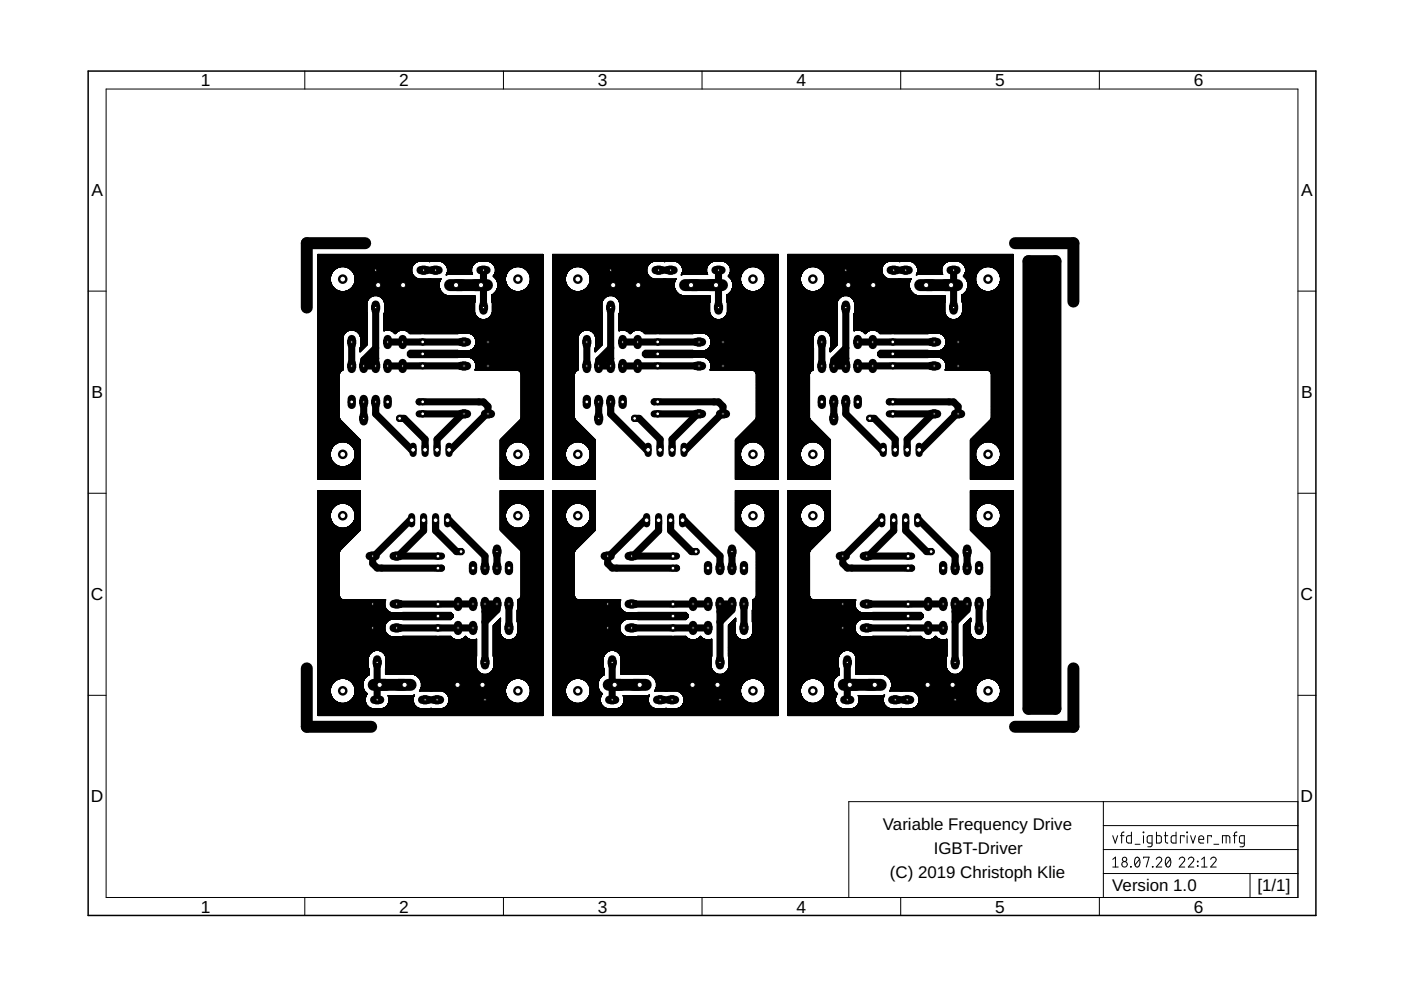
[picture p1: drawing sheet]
<svg xmlns="http://www.w3.org/2000/svg" width="297mm" height="210mm" viewBox="0 0 297 210" stroke-linecap="round" stroke-linejoin="round" font-family="sans-serif">
<defs><g id="words">
<g font-size="3.7">
<text x="42.5" y="18.3">1</text>
<text x="84.7" y="18.3">2</text>
<text x="126.8" y="18.3">3</text>
<text x="168.9" y="18.3">4</text>
<text x="211" y="18.3">5</text>
<text x="253.1" y="18.3">6</text>
<text x="19.4" y="41.6">A</text>
<text x="275.9" y="41.6">A</text>
<text x="19.4" y="84.4">B</text>
<text x="275.9" y="84.4">B</text>
<text x="19.3" y="127.3">C</text>
<text x="275.8" y="127.3">C</text>
<text x="19.3" y="170.1">D</text>
<text x="275.8" y="170.1">D</text>
<text x="42.5" y="193.5">1</text>
<text x="84.7" y="193.5">2</text>
<text x="126.8" y="193.5">3</text>
<text x="168.9" y="193.5">4</text>
<text x="211" y="193.5">5</text>
<text x="253.1" y="193.5">6</text>
</g>
<g font-size="3.6">
<text x="187.2" y="176">Variable Frequency Drive</text>
<text x="198" y="181.1">IGBT-Driver</text>
<text x="188.7" y="186.2">(C) 2019 Christoph Klie</text>
<text x="235.8" y="189">Version 1.0</text>
<text x="266.6" y="189">[1/1]</text>
</g>
</g></defs>
<g fill="none" stroke="#000" stroke-width=".51">
<circle cx="72.7" cy="59.2" r=".76"/>
<circle cx="109.8" cy="59.2" r=".76"/>
<circle cx="122.5" cy="59.2" r=".76"/>
<circle cx="159.6" cy="59.2" r=".76"/>
<circle cx="172.3" cy="59.2" r=".76"/>
<circle cx="209.5" cy="59.2" r=".76"/>
<circle cx="72.7" cy="96.3" r=".76"/>
<circle cx="109.8" cy="96.3" r=".76"/>
<circle cx="122.5" cy="96.3" r=".76"/>
<circle cx="159.6" cy="96.3" r=".76"/>
<circle cx="172.3" cy="96.3" r=".76"/>
<circle cx="209.5" cy="96.3" r=".76"/>
<circle cx="72.7" cy="109.3" r=".76"/>
<circle cx="109.8" cy="109.3" r=".76"/>
<circle cx="122.5" cy="109.3" r=".76"/>
<circle cx="159.6" cy="109.3" r=".76"/>
<circle cx="172.3" cy="109.3" r=".76"/>
<circle cx="209.5" cy="109.3" r=".76"/>
<circle cx="72.7" cy="146.5" r=".76"/>
<circle cx="109.8" cy="146.5" r=".76"/>
<circle cx="122.5" cy="146.5" r=".76"/>
<circle cx="159.6" cy="146.5" r=".76"/>
<circle cx="172.3" cy="146.5" r=".76"/>
<circle cx="209.5" cy="146.5" r=".76"/>
</g>
<path d="M77.4 51.6h-12.4v13.6M215.2 51.6h12.4v12.3M218.1 55.4h5.7v94.9h-5.7zM220 57h1.9v91.4h-1.9v-91.1M96.8 60.5h5.4M146.6 60.5h5.4M196.5 60.5h5.4M65 141.7v12.4h13.7M80.3 145.2h5.4M130.1 145.2h5.4M180 145.2h5.4M227.6 141.7v12.4h-12.4" fill="none" stroke="#000" stroke-width="2.5"/>
<g fill="none" stroke="#000" stroke-width="1.5">
<path d="M79.7 57.3v2.6l.5 .6h5.5M90.4 57.3h1.3M102.5 57.3v7.3M129.5 57.3v2.6l.5 .6h5.5M140.3 57.3h1.2M152.3 57.3v7.3M179.3 57.3v2.6l.6 .6h5.5M190.1 57.3h1.3M202.2 57.3v7.3M74.6 73.2v3.8M79.7 76h-1l-1.6 1.6h2.6M79.7 65.8v11.2"/>
<path d="M79.7 73.8l-2.6 2.5v.7M80.9 60.5l1.9 1.9 1.9-1.9M82.2 72.5h15.5M82.8 60.5v6.6l1.6 1.6h17.8l1.3 1.3v7.6M85.4 77.6h.1M89.6 72.5h.1M89.6 75v.1M89.6 75.1h12.6M96.7 60.5h.1M97.7 77.6h-15.5M102.2 60.5h.3M102.2 75.1l1.3 1.2"/>
<path d="M103.5 73.8l-1.3 1.3M124.4 73.2v3.8M129.5 76h-1l-1.6 1.6h2.6M129.5 65.8v11.2M129.5 73.8l-2.6 2.5v.7M130.7 60.5l2 1.9 1.9-1.9M132 72.5h15.6M132.7 60.5v6.6l1.5 1.6h17.8l1.3 1.3v7.6M135.2 77.6h.1M139.4 72.5h.1M139.4 75l.1 .1M139.5 75.1h12.5"/>
<path d="M146.5 60.5h.1M147.6 77.6h-15.6M152 60.5h.3M152 75.1l1.3 1.2M153.3 73.8l-1.3 1.3M174.2 73.2v3.8M179.3 76h-.9l-1.6 1.6h2.5M179.3 65.8v11.2M179.3 73.8l-2.5 2.5v.7M180.6 60.5l1.9 1.9 1.9-1.9M181.9 72.5h15.5M182.5 60.5v6.6l1.6 1.6h17.8l1.2 1.3v7.6"/>
<path d="M185.1 77.6h-.1M189.3 75l12.6 .1M189.3 72.5h.1M196.4 60.5h.1M197.4 77.6h-15.5M201.9 60.5h.3M201.9 75.1l1.2 1.2M203.1 73.8l-1.2 1.3M77.1 85.9v2.2M79.7 85.2v2.6l7.6 7.6h.3M84.7 88.7h1l4.4 4.5v2.2M88.9 87.8h8.8"/>
<path d="M89.6 87.7v.1M98.4 87.8h-.3l-5.4 5.4v2.2M101.5 85.2h-12.6M101.6 85.2h.9l1 1v1.6h-.4l-7.6 7.6h-.3M126.9 85.9v2.2M129.5 85.2v2.6l7.6 7.6h.3M134.6 88.7h.9l4.5 4.5v2.2M138.7 87.8h8.9M139.4 87.7v.1M148.2 87.8h-.3l-5.4 5.4v2.2M151.4 85.2h.9l1 1v1.6h-.3l-7.6 7.6h-.4M151.4 85.2h-12.7"/>
<path d="M176.8 85.9v2.2M179.3 85.2v2.6l7.6 7.6h.4M184.4 88.7h1l4.4 4.5v2.2M188.5 87.8h8.9M189.3 87.7v.1M198.1 87.8h-.4l-5.4 5.4v2.2M201.2 85.2h-12.7M201.2 85.2h1l.9 1v1.6h-.3l-7.6 7.6h-.3M84.7 117.9h8.9M87.3 110.3h-.3l-7.7 7.6h-.3v1.6l1 .9h.9M89.8 110.3v2.2l-5.4 5.4h-.3M92.4 110.3v2.2l4.4 4.4h.9"/>
<path d="M92.9 117.9h.1M94.9 110.3h.3l7.6 7.6v2.5M105.4 117.6v2.2M134.6 117.9h8.8M137.1 110.3h-.3l-7.6 7.6h-.4v1.6l1 .9h.9M139.6 110.3v2.2l-5.4 5.4h-.3M142.2 110.3v2.2l4.4 4.4h1M142.7 117.9h.1M144.7 110.3h.3l7.7 7.6v2.5M155.2 117.6v2.2M184.4 117.9h8.9M186.9 110.3h-.3l-7.6 7.6h-.3v1.6l.9 .9h1"/>
<path d="M189.5 110.3v2.2l-5.4 5.4h-.3M192 110.3v2.2l4.5 4.4h.9M192.6 117.9h-.1M194.6 110.3h.3l7.6 7.6v2.5M205 117.6v2.2M79 128.1v7.6l1.3 1.2h17.8l1.6 1.6v6.7M79 129.3l1.3 1.3M80.3 130.6h12.6M80.3 130.6l-1.3 1.3M84.7 133.1h15.6M92.8 133.1l.1 .1M93.6 120.4l-12.7 .1"/>
<path d="M97.1 128.1h.1M100.3 128.1h-15.6M102.8 128.1h2.6l-1.6 1.5h-1M102.8 128.7v11.1M105.4 128.7v.6l-2.6 2.6M107.9 128.7v3.8M128.8 128.1v7.6l1.3 1.2h17.8l1.6 1.6v6.7M128.8 129.3l1.3 1.3M130.1 130.6h12.6M130.1 130.6l-1.3 1.3M134.6 133.1h15.5M142.7 130.6h.1"/>
<path d="M142.7 133.1v.1M143.4 120.4l-12.6 .1M146.9 128.1h.1M150.1 128.1h-15.5M152.7 128.1h2.5l-1.6 1.5h-.9M152.7 128.7v11.1M155.2 128.7v.6l-2.5 2.6M157.7 128.7v3.8M178.7 128.1v7.6l1.3 1.2h17.7l1.6 1.6v6.7M178.7 129.3l1.3 1.3M180 130.6h12.5M180 130.6l-1.3 1.3"/>
<path d="M184.4 133.1h15.6M192.5 133.1v.1M192.5 130.6h.1M193.3 120.4l-12.7 .1M196.8 128.1h.1M200 128.1h-15.6M202.5 128.1h2.5l-1.5 1.5h-1M202.5 128.7v11.1M205 128.7v.6l-2.5 2.6M207.6 128.7v3.8M80 145.2h.3M80 141.1v7.3"/>
<path d="M85.7 145.2h.1M90.8 148.4h1.2M96.8 145.2h5.5l.5 .5v2.7M97.7 145.2l2-1.9 1.9 1.9M129.8 145.2h.3M129.8 141.1v7.3M135.5 145.2h.1M140.6 148.4h1.3M146.6 145.2h5.5l.6 .5v2.7M147.6 145.2l1.9-1.9 1.9 1.9M179.6 145.2h.4M179.6 141.1v7.3"/>
<path d="M185.4 145.2h.1M190.4 148.4h1.3M196.5 145.2h5.5l.5 .5v2.7M197.4 145.2l1.9-1.9 1.9 1.9"/>
</g>
<g fill="none" stroke="#000" stroke-width="1.8">
<path d="M79 57.3h1.3M89.2 57.3h1.2M91.7 57.3h1.3M101.9 57.3h1.2M128.8 57.3h1.3M139 57.3h1.3M141.5 57.3h1.3M151.7 57.3h1.3M178.7 57.3h1.3M188.8 57.3h1.3M191.4 57.3h1.3M201.5 57.3h1.3"/>
<path d="M74.6 71.9v1.3M74.6 77v1.2M77.1 77v1.2M79.7 64.6v1.2M79.7 77v1.2M82.2 71.9v1.3M82.2 77v1.2M85.4 71.9v1.3M85.4 77v1.2M97.7 77.6h1.3M97.7 77.6h.1M97.7 72.5h1.3"/>
<path d="M102.5 64.6v1.2M102.8 77.6h1.3M102.8 72.5h1.3M124.4 71.9v1.3M124.4 77v1.2M126.9 77v1.2M129.5 64.6v1.2M129.5 77v1.2M132 71.9v1.3M132 77v1.2M135.2 71.9v1.3M135.2 77v1.2"/>
<path d="M147.6 77.6h1.2M147.6 72.5h1.2M152.3 64.6v1.2M152.7 77.6h1.2M152.7 72.5h1.2M174.2 71.9v1.3M174.2 77v1.2M176.8 77v1.2M179.3 64.6v1.2M179.3 77v1.2M181.9 71.9v1.3M181.9 77v1.2"/>
<path d="M185 71.9v1.3M185 77v1.2M197.4 72.5h1.3M197.4 77.6h.1M197.4 77.6h1.3M202.2 64.6v1.2M202.5 77.6h1.3M202.5 72.5h1.3M74.6 84.6v1.3M77.1 84.6v1.3M77.1 88.1v1.2M79.7 84.6v1.3"/>
<path d="M82.2 84.6v1.3M97.7 87.8h1.3M102.8 87.8h1.3M124.4 84.6v1.3M126.9 84.6v1.3M126.9 88.1v1.2M129.5 84.6v1.3M132 84.6v1.3M147.6 87.8h1.2M152.7 87.8h1.2M174.2 84.6v1.3M176.8 84.6v1.3"/>
<path d="M176.8 88.1v1.2M179.3 84.6v1.3M181.9 84.6v1.3M197.4 87.8h1.3M202.5 87.8h1.3M78.4 117.9h1.3M83.5 117.9h1.2M100.3 119.8v1.3M102.8 119.8v1.3M105.4 116.3v1.3M105.4 119.8v1.3M107.9 119.8v1.3"/>
<path d="M128.2 117.9h1.3M133.3 117.9h1.3M150.1 119.8v1.3M152.7 119.8v1.3M155.2 116.3v1.3M155.2 119.8v1.3M157.7 119.8v1.3M178.1 117.9h1.2M183.1 117.9h1.3M200 119.8v1.3M202.5 119.8v1.3M205 116.3v1.3"/>
<path d="M205 119.8v1.3M207.6 119.8v1.3M78.4 128.1h1.3M78.4 133.1h1.3M80 139.8v1.3M83.5 128.1h1.2M83.5 133.1h1.2M97.1 127.4v1.3M97.1 132.5v1.3M100.3 127.4v1.3M100.3 132.5v1.3M102.8 127.4v1.3"/>
<path d="M102.8 139.8v1.3M105.4 127.4v1.3M107.9 127.4v1.3M107.9 132.5v1.3M128.2 128.1h1.3M128.2 133.1h1.3M129.8 139.8v1.3M133.3 128.1h1.3M133.3 133.1h1.3M134.6 128.1h.1M146.9 127.4v1.3M146.9 132.5v1.3"/>
<path d="M150.1 127.4v1.3M150.1 132.5v1.3M152.7 127.4v1.3M152.7 139.8v1.3M155.2 127.4v1.3M157.7 127.4v1.3M157.7 132.5v1.3M178.1 128.1h1.2M178.1 133.1h1.2M179.6 139.8v1.3M183.1 128.1h1.3M183.1 133.1h1.3"/>
<path d="M184.4 128.1h.1M196.8 127.4v1.3M196.8 132.5v1.3M200 127.4v1.3M200 132.5v1.3M202.5 127.4v1.3M202.5 139.8v1.3M205 127.4v1.3M207.6 127.4v1.3M207.6 132.5v1.3M79.3 148.4h1.3M89.5 148.4h1.3"/>
<path d="M92 148.4h1.3M102.2 148.4h1.3M129.2 148.4h1.2M139.3 148.4h1.3M141.9 148.4h1.2M152 148.4h1.3M179 148.4h1.3M189.2 148.4h1.2M191.7 148.4h1.3M201.9 148.4h1.2"/>
</g>
<path d="M89.6 87.7v.1M101.5 85.2h.1M139.4 87.7v.1M151.4 85.2h.1M189.3 87.7v.1M201.2 85.2h.1M92.9 117.9h.1M142.7 117.9h.1M192.5 117.9h.1M80.9 120.4v.1M130.7 120.4l.1 .1M180.6 120.4v.1" fill="none" stroke="#000" stroke-width="1.3"/>
<path d="M79.7 85.2l-.4 .3M129.5 85.2l-.3 .3M179.3 85.2l-.3 .3M103.1 120.1l-.3 .3M153 120.1l-.3 .3M202.8 120.1l-.3 .3" fill="none" stroke="#000" stroke-width=".63"/>
<g fill="none" stroke="#000" stroke-width=".21">
<path d="M67.4 58.2h2.8M67.4 59.1h2.6M67.4 60h2.8M67.4 59.9h2.7M67.4 59.8h2.7M67.4 59.7l2.7 .1M67.4 59.7h2.7M67.4 59.6h2.7M67.4 59.5h2.6M67.4 59.4h2.6M67.4 59.3h2.6M67.4 59.2h2.6"/>
<path d="M67.4 59h2.6M67.4 58.9h2.6M67.4 58.8h2.6M67.4 58.7h2.7M67.4 58.5h2.7M67.4 58.4h2.7M67.4 58h2.9M67.4 57.9h3M67.4 57.8h3M67.4 57.6h3.2M67.4 56h20.4M67.4 55.3h47.7"/>
<path d="M67.4 55.2h47.7M67.4 55.1h47.7M67.4 55h47.7M67.4 54.9h47.7M67.4 54.8h47.7M67.4 54.7h47.7M67.4 54.6h47.7M67.4 54.5h47.7M67.4 54.4h47.7M67.4 54.3h47.7M67.4 54.2h47.7M67.4 54.1h47.7"/>
<path d="M67.4 54h47.7M70 58.8v.7M70 59.5l.2 .7M70.1 58.8h-2.7M70.1 58.7h-2.7M70.1 58.6h-2.7M70.1 58.4l-2.7 .1M70.2 58.3l-2.8 .1M70.2 58.3h-2.8M70.2 58.2l-.2 .6M70.3 58.1l-2.9 .1M70.3 58.1h-2.9"/>
<path d="M70.3 58l-2.9 .1M70.4 57.9h-3M70.4 57.8h-3M70.5 57.7h-3.1M70.5 57.6h-3.1M70.7 57.5h-3.3M70.7 57.4l-3.3 .1M70.7 57.4h-3.3M70.8 57.3l-3.4 .1M70.9 57.3h-3.5M70.9 57.2l-3.5 .1M71 57.2h-3.6"/>
<path d="M71 57.1h-3.6M71.1 57.1l-.9 1.1M71.1 57.1h-3.7M71.2 57h-3.8M71.3 57h-3.9M71.3 56.9h-3.9M71.5 56.9h-4.1M71.5 56.8h-4.1M71.6 56.7l-4.2 .1M71.8 56.7h-4.4M72 56.6l-4.6 .1M72.2 56.6h-4.8"/>
<path d="M72.3 56.6l-1.2 .5M73 56.6l1.3 .5M73.2 56.6h14.2M73.3 56.6h14.1M73.5 56.7h13.9M73.7 56.7h13.7M73.8 56.8h13.5M73.9 56.9h13.4M74 56.9h13.3M74.1 57h13.2M74.2 57h13.1M74.3 57.1h13"/>
<path d="M74.3 57.1l.5 .5M74.4 57.2h12.9M74.5 57.3h12.8M74.6 57.4h12.7M74.7 57.5h12.6M74.7 57.6h12.6M74.8 57.6l.5 1.2M74.8 57.6h12.5M74.8 57.7h12.5M74.9 57.8h12.4M74.9 57.8h12.5M74.9 57.9h12.5"/>
<path d="M75 57.9l12.4 .1M75 58h12.4M75 58l12.5 .1M75.1 58.1h12.4M75.1 58.1l12.4 .1M75.1 58.2h12.4M75.1 58.2l12.4 .1M75.1 58.3h12.5M75.2 60h17.9M75.2 58.3l12.4 .1M75.2 59.9h18M75.2 58.4l12.5 .1"/>
<path d="M75.2 58.4h12.5M75.2 58.5l12.6 .1M75.2 58.5h12.6M75.2 59.8h18M75.2 58.6h12.7M75.2 59.7h18.1M75.2 58.7h12.7M75.3 59.6h18M75.3 58.8h12.7M75.3 58.7h12.7M75.3 58.8v.7M75.3 59.5l-.2 .7"/>
<path d="M75.3 59.1h18.2M75.3 59.5h18M75.3 59.4h18.1M75.3 59.2h18.2M75.3 59.1h13.4M75.3 59l13.2 .1M75.3 59h13.1M75.3 58.9h13M75.3 58.9h12.9M75.3 58.8h12.8M87.3 56.9v.8M87.3 57.7l.3 .7 .5 .5 .7 .3"/>
<path d="M87.4 56.5l-20 .1M87.5 56.5h-20.1M87.5 56.4l-20.1 .1M87.5 56.4h-20.1M87.5 56.3h-20.1M87.6 56.2l-.3 .7M87.6 56.2l-20.2 .1M87.6 56.2h-20.2M87.7 56.1l-20.3 .1M87.7 56.1h-20.3M87.8 56h-20.4M87.9 55.9h-20.5"/>
<path d="M88 55.8h-20.6M88.1 55.7l-.5 .5M88.1 55.7h-20.7M88.2 55.6l-20.8 .1M88.3 55.6h-20.9M88.4 55.5l-21 .1M88.6 55.5h-21.2M88.7 55.4l-21.3 .1M88.8 55.4l-.7 .3M90.8 55.4h.5M90.9 55.4h.3M90.9 59.1h.3"/>
<path d="M91 55.5h.1M91.1 59.1l-.3 .1M91.1 59.1l.2 .1M91.1 59.1h.1M93.2 59.9l-18 .1M93.2 59.8l-18 .1M93.3 59.6h-18M93.4 55.4l.6 .3M93.4 59.3h-18.1M93.4 55.4h8M93.5 59.2h-18.2M93.5 59.1h.1"/>
<path d="M93.6 59.1l-.2 .1M93.6 59.1l-.5 .9M93.6 55.5h7.7M93.7 55.5h7.4M93.8 55.6h7.2M94 55.6h6.9M94 55.7l.6 .5M94 55.7h6.8M94.1 55.8h6.6M94.3 55.9h6.3M94.3 56h6.2M94.4 56h6.1"/>
<path d="M94.4 56.1h6M94.6 56.2l.3 .7v.8l-.3 .6M94.6 56.2h5.7M94.6 56.3h5.6M94.7 58.1l5.5 .1M94.7 58.3h-.1M94.7 58.1h5.5M94.7 58l5.5 .1M94.7 58h5.4M94.7 57.9h5.4M94.7 56.6h5.4M94.8 57.9h5.3"/>
<path d="M94.8 57.8h5.3M94.8 56.7h5.3M94.8 57.8h5.2M94.8 58.2l-.2 .1M94.8 57.7h5.2M94.8 56.8h5.2M94.8 56.9h5.2M94.9 57.6h5.1M94.9 57.5h5.1M94.9 57.4h5.1M94.9 57.3h5.1M94.9 57.2h5.1"/>
<path d="M94.9 57.1h5.1M94.9 57h5.1M94.9 56.9h5.1M94.9 58.2h-.3M95 58.2l-.4 .1M100 57.7l.2 .5h-1.8M100.1 56.7l-5.3 .1M100.1 56.6l-5.3 .1M100.1 56.5l-5.4 .1M100.2 56.5h-5.5M100.2 56.4l-5.5 .1M100.2 56.4h-5.5"/>
<path d="M100.2 56.3h-5.6M100.3 56.2l-.3 .7v.8M100.3 56.2h-5.7M100.4 56.1h-5.9M100.6 55.9h-6.4M100.7 55.8h-6.5M100.8 55.7l-.5 .5M101.5 55.4l-.7 .3M103.5 55.4l.7 .3M103.6 55.4h11.5M103.7 55.5h11.4M103.9 55.5h11.2"/>
<path d="M104 55.6h11.1M104.1 55.6h11M104.2 55.7l.5 .5M104.2 55.7h10.9M104.3 55.8h10.8M104.4 55.9h10.7M104.5 56h10.6M104.6 58.5l.6 .7M104.6 58.5h2.7M104.6 56.1h10.5M104.6 58.6h2.6M104.7 58.7h2.5"/>
<path d="M104.7 58.4h2.6M104.7 56.2h10.4M104.7 58.4l-.1 .1M104.7 56.2l.3 .7M104.8 58.3h2.5M104.8 58.8h2.4M104.8 56.3h10.3M104.8 56.4h10.3M104.8 58.1h2.6M104.9 56.5h10.2M104.9 58.9h2.3M104.9 58h2.6"/>
<path d="M104.9 57.9h2.6M105 57.8h2.6M105 59h2.2M105 57.7l-.3 .7M105 56.9v.8M105.1 59h2.1M105.1 59.1h2.1M105.2 59.1h2M105.2 59.2l.3 .8M105.2 59.2h2M105.2 59.3h2M105.3 59.4h1.9"/>
<path d="M105.3 59.5h1.9M105.3 59.6h1.9M105.4 59.6h1.8M105.4 59.7h1.8M105.4 59.8h1.9M105.5 59.8l1.8 .1M105.5 59.9h1.8M105.5 60h1.8M107.2 58.8v.7M107.2 59.5l.5 1.3M107.3 58.5h-2.7M107.3 58.4l-2.7 .1"/>
<path d="M107.3 58.4h-2.6M107.4 58.2h-2.6M107.4 58.1l-2.6 .1M107.4 58h-2.5M107.5 57.9h-2.6M107.6 57.8h-2.7M107.6 57.7h-2.6M107.7 57.7h-2.7M107.7 57.6l-.5 1.2M107.7 57.6h-2.7M107.8 57.5h-2.8M107.8 57.4l-2.8 .1"/>
<path d="M107.9 57.4h-2.9M107.9 57.3l-2.9 .1M108 57.3h-3M108 57.2l-3 .1M108.1 57.2h-3.1M108.1 57.1h-3.1M108.2 57.1h-3.2M108.3 57h-3.3M108.4 57h-3.4M108.5 56.9h-3.5M108.6 56.9h-3.6M108.6 56.8h-3.6"/>
<path d="M108.8 56.7l-3.8 .1M108.9 56.7h-4M109.2 56.6l-4.3 .1M109.3 56.6h-4.4M109.5 56.6l-.7 .1-1.1 .9M110.2 56.6l1.2 .5M110.3 56.6h4.8M110.4 56.6h4.7M110.7 56.7h4.4M110.8 56.7h4.3M111 56.8h4.1M111 56.9h4.1"/>
<path d="M111.1 56.9h4M111.2 57h3.9M111.3 57h3.8M111.4 57.1h3.7M111.4 57.1l.5 .5M111.5 57.1h3.6M111.5 57.2h3.6M111.6 57.2h3.5M111.6 57.3h3.5M111.7 57.3h3.4M111.7 57.4h3.4M111.8 57.4h3.3"/>
<path d="M111.8 57.5h3.3M111.9 57.6h3.2M111.9 57.6l.5 1.2M112 57.7h3.1M112 57.8h3.1M112.1 57.9h3M112.1 58h3M112.2 58h2.9M112.2 58.1h2.9M112.3 58.2h2.8M112.3 58.3h2.8M112.3 60h2.8"/>
<path d="M112.3 58.4h2.8M112.3 59.9h2.8M112.4 59.8h2.7M112.4 58.5h2.7M112.4 59.7h2.7M112.4 58.7h2.7M112.4 58.6h2.7M112.4 59.6h2.7M112.4 58.8h2.7M112.4 58.8v.7M112.4 59.5l-.2 .7M112.4 59.1h2.7"/>
<path d="M112.4 59.5h2.7M112.4 59.4h2.7M112.4 59.3h2.7M112.4 59.2h2.7M112.4 59h2.7M112.4 58.9h2.7M115.1 56.5l-10.2 .1M115.1 55.4h-47.7M117.2 58.2h2.9M117.2 59.1h2.7M117.2 60h2.8M117.2 59.9h2.8"/>
<path d="M117.2 59.8l2.8 .1M117.2 59.8h2.8M117.2 59.7h2.7M117.2 59.6h2.7M117.2 59.5h2.7M117.2 59.4h2.7M117.2 59.3h2.7M117.2 59.2h2.7M117.2 59h2.7M117.2 58.9h2.7M117.2 58.8h2.7M117.2 58.7h2.7"/>
<path d="M117.2 58.6h2.7M117.2 58.5h2.8M117.2 58.4h2.8M117.2 58.3h2.8M117.2 58.2h2.8M117.2 58.1h2.9M117.2 56.5h20.1M117.2 56.4h20.1M117.2 56.3h20.2M117.2 56.2h20.2M117.2 55.3h47.8M117.2 55.2h47.8"/>
<path d="M117.2 55.1h47.8M117.2 55h47.8M117.2 54.9h47.8M117.2 54.8h47.8M117.2 54.7h47.8M117.2 54.6h47.8M117.2 54.5h47.8M117.2 54.4h47.8M117.2 54.3h47.8M117.2 54.2h47.8M117.2 54.1h47.8M117.2 54h47.8"/>
<path d="M119.9 58.7h-2.7M120 58.3l-2.8 .1M120.1 58.2l-.2 .6 .2 1.4M120.1 58.1h-2.9M120.1 58h-2.9M120.2 58h-3M120.2 57.9h-3M120.3 57.8h-3.1M120.3 57.7h-3.1M120.4 57.7h-3.2M120.4 57.6h-3.2M120.5 57.5h-3.3"/>
<path d="M120.5 57.4l-3.3 .1M120.6 57.4h-3.4M120.6 57.3l-3.4 .1M120.7 57.3h-3.5M120.7 57.2l-3.5 .1M120.8 57.2h-3.6M120.8 57.1h-3.6M120.9 57.1l-.8 1.1M120.9 57.1h-3.7M121 57h-3.8M121.1 57h-3.9M121.2 56.9h-4"/>
<path d="M121.3 56.9h-4.1M121.3 56.8h-4.1M121.5 56.7l-4.3 .1M121.6 56.7h-4.4M121.9 56.6l-4.7 .1M122 56.6h-4.8M122.2 56.6l-1.3 .5M122.9 56.6a2.64 2.64 0 0 1 2 1.6M123 56.6h14.2M123.1 56.6h14.1M123.4 56.7h13.8M123.5 56.7h13.7"/>
<path d="M123.7 56.8h13.5M123.7 56.9h13.4M123.8 56.9h13.3M123.9 57h13.2M124 57h13.1M124.1 57.1h13M124.2 57.1h12.9M124.2 57.2h12.9M124.3 57.2h12.8M124.3 57.3h12.8M124.4 57.3h12.7M124.4 57.4h12.7"/>
<path d="M124.5 57.4h12.6M124.5 57.5h12.6M124.6 57.6h12.5M124.7 57.7h12.4M124.7 57.7h12.5M124.7 57.8h12.5M124.8 57.9h12.4M124.8 58h12.5M124.9 58h12.4M124.9 58.1h12.4M124.9 58.2h12.5M124.9 58.2l.2 1.3"/>
<path d="M125 58.2h12.4M125 58.3l12.5 .1M125 58.3h12.4M125 58.4h12.5M125 58.5h12.6M125 58.4l12.5 .1M125.1 58.5l12.5 .1M125.1 58.7h12.7M125.1 58.6h12.6M125.1 58.8h12.8M125.1 59.1h18.2M125.1 59.5h18.1"/>
<path d="M125.1 59.4h18.1M125.1 59.2h18.2M125.1 59.1h13.4M125.1 59l13.3 .1M125.1 59h13.2M125.1 58.9h13M125.1 58.9h12.9M125.1 59.5l-.2 .7M137.1 56.9v.8M137.1 57.7l.3 .7 .5 .5 .7 .3M137.3 56.5l-20.1 .1M137.4 56.2l-.3 .7"/>
<path d="M137.4 56.2h-20.2M137.5 56.1l-20.3 .1M137.6 56.1h-20.4M137.6 56h-20.4M137.7 56h-20.5M137.7 55.9h-20.5M137.8 55.9h-20.6M137.8 55.8h-20.6M137.9 55.8h-20.7M137.9 55.7h-20.7M137.9 55.7l-.5 .5M138 55.6l-20.8 .1"/>
<path d="M138.2 55.6h-21M138.3 55.5l-21.1 .1M138.4 55.5h-21.2M138.6 55.4l-21.4 .1M138.6 55.4l-.7 .3M140.7 55.4l.2 .1M140.7 55.4h.4M140.8 59.1h.3M140.9 55.5h.1M140.9 59.1l-.2 .1M140.9 59.1l.3 .1M140.9 59.1h.1"/>
<path d="M141.2 55.4l-.3 .1M143 60h-18M143 59.9h-18M143 59.8h-17.9M143.1 59.8h-18M143.1 59.7l-18 .1M143.1 59.7h-18M143.1 59.6h-18M143.2 59.6h-18.1M143.2 59.5h-18.1M143.2 55.4l.7 .3M143.2 59.4h-18.1"/>
<path d="M143.3 59.3h-18.2M143.3 55.4h8M143.3 59.2h-18.2M143.3 59.2l-.3 .8v.9l.3 .8M143.4 59.1h-.1M143.4 59.1l-.2 .1M143.4 59.1l-.1 .1M143.4 55.5h7.7M143.6 55.5h7.4M143.6 55.6h7.3M143.8 55.6h6.9M143.9 55.7h6.7"/>
<path d="M143.9 55.7l.5 .5M144 55.8h6.6M144 55.8h6.5M144.1 55.9h6.4M144.1 55.9h6.3M144.2 56h6.2M144.2 56h6.1M144.3 56.1h6M144.3 56.1h5.9M144.4 56.2h5.7M144.4 56.2l.3 .7v.8M144.4 56.3h5.7"/>
<path d="M144.5 56.3h5.6M144.5 58.2h5.5M144.5 56.4h5.5M144.5 58.3h-.1M144.5 58.1h5.5M144.5 56.5h5.5M144.6 58h5.4M144.6 56.6h5.3M144.6 57.9h5.3M144.6 56.7h5.3M144.6 57.8h5.3M144.7 57.8h5.2"/>
<path d="M144.7 58.2l-.3 .1M144.7 57.7h5.2M144.7 56.9h5.1M144.7 57.7h5.1M144.7 57.6h5.1M144.7 57.5h5.1M144.7 57.4h5.1M144.7 57.3h5.1M144.7 57.2h5.1M144.7 57.1h5.1M144.7 57h5.1M144.7 57.7l-.3 .6"/>
<path d="M144.8 58.2h-.3M144.8 58.2l-.4 .1M148.3 58.2h.1M149.9 56.8h-5.2M150.1 56.2l-.3 .7v.8l.3 .5h-1.8M150.6 55.7l-.5 .5M151.3 55.4l-.7 .3M153.4 55.4l.7 .3M153.4 55.4h11.6M153.6 55.5h11.4M153.7 55.5h11.3M153.8 55.6h11.2"/>
<path d="M154 55.6h11M154.1 55.7h10.9M154.1 55.7l.5 .5M154.1 55.8h10.9M154.2 55.8h10.8M154.2 55.9h10.8M154.3 55.9h10.7M154.3 56h10.7M154.4 56h10.6M154.4 58.5h2.7M154.4 58.5l.6 .7 .4 .8M154.4 56.1h10.6"/>
<path d="M154.5 58.6h2.6M154.5 56.1h10.5M154.5 58.7h2.6M154.5 58.4h2.6M154.5 56.2h10.5M154.6 58.3h2.6M154.6 56.2h10.4M154.6 58.4l-.2 .1M154.6 56.2l.3 .7v.8M154.6 56.3h10.4M154.6 58.8h2.4M154.6 58.2h2.6"/>
<path d="M154.6 56.4h10.4M154.7 56.4h10.3M154.7 58.8h2.3M154.7 56.5h10.3M154.7 58.9h2.3M154.7 56.6h4.5M154.7 56.6h4.3M154.8 58.9h2.2M154.8 57.9h2.6M154.8 56.7h4M154.8 56.7h3.8M154.8 59h2.2"/>
<path d="M154.8 56.9h3.6M154.9 57.7h2.6M154.9 57.6h2.7M154.9 57.2h3M154.9 57.7l-.3 .7M154.9 59h2.1M154.9 59.1h2.1M155 59.1h2M155 59.2h2M155.1 59.3h1.9M155.1 59.4h1.9M155.2 59.5h1.8"/>
<path d="M155.2 59.6h1.8M155.2 59.6h1.9M155.2 59.7h1.9M155.3 59.7h1.8M155.3 59.8h1.8M155.3 59.9h1.8M155.3 59.9l1.8 .1M155.4 60h1.7M157 58.8v.7M157 59.5l.2 .7M157.1 58.7h-2.5M157.1 58.5h-2.7"/>
<path d="M157.1 58.4h-2.6M157.2 58.2l-2.6 .1M157.2 58.2l-.2 .6M157.2 58.1l-2.6 .1M157.2 58.1h-2.5M157.3 58l-2.6 .1M157.3 58h-2.6M157.4 57.9l-2.7 .1M157.4 57.8h-2.6M157.5 57.7h-2.7M157.5 57.6h-2.6M157.6 57.5h-2.7"/>
<path d="M157.7 57.4l-2.8 .1M157.7 57.4h-2.8M157.8 57.3l-2.9 .1M157.8 57.3h-2.9M157.9 57.2h-3M158 57.1h-3.1M158.1 57.1h-3.2M158.1 57h-3.2M158.3 57h-3.4M158.3 56.9h-3.4M158.5 56.8h-3.7M159.3 56.6a2.64 2.64 0 0 0-2.1 1.6"/>
<path d="M160 56.6l1.2 .5M160.1 56.6h4.9M160.3 56.6h4.7M160.5 56.7h4.5M160.7 56.7h4.3M160.8 56.8h4.2M160.9 56.9h4.1M161 56.9h4M161 57h4M161.1 57h3.9M161.2 57.1h3.8M161.2 57.1l.9 1.1"/>
<path d="M161.3 57.1h3.7M161.4 57.2h3.6M161.4 57.3h3.6M161.5 57.3h3.5M161.6 57.4h3.4M161.7 57.5h3.3M161.7 57.6h3.3M161.8 57.6h3.2M161.8 57.7h3.2M161.9 57.8h3.1M161.9 57.9h3.1M162 58h3"/>
<path d="M162.1 58.1h2.9M162.1 58.2h2.9M162.1 58.2l.2 .6M162.1 58.3h2.9M162.2 59.9h2.8M162.2 58.4h2.8M162.2 59.8h2.8M162.2 58.5h2.8M162.2 58.6h2.8M162.2 59.7h2.8M162.2 58.7h2.8M162.2 59.6h2.8"/>
<path d="M162.2 58.8h2.8M162.3 59.1h2.7M162.3 59.6h2.7M162.3 59.5h2.7M162.3 59.4h2.7M162.3 59.3h2.7M162.3 59.2h2.7M162.3 59h2.7M162.3 58.9h2.7M162.3 58.8h2.7M162.3 58.8v.7M162.3 59.5l-.2 .7"/>
<path d="M165 55.4h-47.8M167 58.2h2.9M167 59.1h2.7M167 60h2.8M167 59.9l2.8 .1M167 59.9h2.8M167 59.8h2.8M167 59.7h2.8M167 59.6h2.8M167 59.6h2.7M167 59.5h2.7M167 59.4h2.7"/>
<path d="M167 59.3h2.7M167 59.2h2.7M167 59h2.7M167 58.9h2.7M167 58.8h2.7M167 58.7h2.7M167 58.7h2.8M167 58.5h2.8M167 58.3h2.8M167 57.9h3.1M167 57.8h3.1M167 57.7h3.2"/>
<path d="M167 57.6h3.3M167 57.2h3.6M167 56.3h20.2M167 55.3h47.8M167 55.2h47.8M167 55.1h47.8M167 55h47.8M167 54.9h47.8M167 54.8h47.8M167 54.7h47.8M167 54.6h47.8M167 54.5h47.8"/>
<path d="M167 54.4h47.8M167 54.3h47.8M167 54.2h47.8M167 54.1h47.8M167 54h47.8M169.7 58.8v.7M169.7 59.5l.2 .7M169.7 58.8h-2.7M169.8 58.6h-2.8M169.8 58.5l-2.8 .1M169.8 58.4l-2.8 .1M169.8 58.4h-2.8"/>
<path d="M169.9 58.3h-2.9M169.9 58.2l-2.9 .1M169.9 58.1l-2.9 .1M169.9 58.1h-2.9M170 58l-3 .1M170 58h-3M170.1 57.9l-3.1 .1M170.1 57.8h-3.1M170.2 57.7h-3.2M170.2 57.6h-3.2M170.2 57.6l-.5 1.2M170.3 57.5h-3.3"/>
<path d="M170.4 57.4l-3.4 .1M170.4 57.4h-3.4M170.5 57.3l-3.5 .1M170.5 57.3h-3.5M170.6 57.2h-3.6M170.7 57.1h-3.7M170.7 57.1l-.5 .5M170.8 57.1h-3.8M170.8 57h-3.8M171 57h-4M171 56.9h-4M171.1 56.9h-4.1"/>
<path d="M171.2 56.8h-4.2M171.3 56.7l-4.3 .1M171.5 56.7h-4.5M171.7 56.6l-4.7 .1M171.9 56.6h-4.9M172 56.6l-1.3 .5M172.7 56.6l.7 .1 1 .9M172.8 56.6h14.3M173 56.6h14.1M173.2 56.7h13.8M173.4 56.7h13.6M173.5 56.8h13.5"/>
<path d="M173.5 56.9h13.5M173.7 56.9h13.3M173.7 57h13.3M173.8 57h13.2M173.9 57.1h13.1M174 57.1h13M174 57.2h13M174.1 57.2h12.9M174.1 57.3h12.9M174.2 57.3h12.8M174.3 57.4h12.7M174.3 57.5h12.7"/>
<path d="M174.4 57.6h12.6M174.4 57.6l.6 1.2M174.5 57.6h12.5M174.5 57.7h12.5M174.6 57.8h12.4M174.6 57.9h12.4M174.6 57.9l12.5 .1M174.7 58h12.4M174.7 58l12.4 .1M174.7 58.1h12.5M174.8 58.1l12.4 .1M174.8 58.2h12.4"/>
<path d="M174.8 58.2l12.4 .1M174.8 58.3h12.4M174.8 58.3l12.5 .1M174.9 59.9h17.9M174.9 58.4l12.5 .1M174.9 58.4h12.4M174.9 58.5l12.6 .1M174.9 58.5h12.5M174.9 59.8h18M174.9 58.6h12.6M174.9 59.7h18M174.9 58.7h12.7"/>
<path d="M174.9 58.8h12.8M175 59.1h18.2M175 59.5h18M175 59.1h13.4M175 59l13.2 .1M175 59h13.1M175 58.9h13M175 58.9h12.9M175 58.8h12.7M175 58.8v.7M175 59.5l-.6 1.3M187 57.7l.2 .7"/>
<path d="M187.1 56.5l-20.1 .1M187.1 56.5h-20.1M187.2 56.4l-20.2 .1M187.2 56.4h-20.2M187.2 56.3l-20.2 .1M187.2 56.2l-20.2 .1M187.2 56.2l-.2 .7v.8M187.2 58.4l.6 .5 .7 .3M187.3 56.2h-20.3M187.3 56.1l-20.3 .1M187.4 56.1h-20.4M187.5 56h-20.5"/>
<path d="M187.6 55.9h-20.6M187.7 55.8h-20.7M187.8 55.7h-20.8M187.8 55.7l-.6 .5M187.9 55.6l-20.9 .1M188 55.6h-21M188.1 55.5l-21.1 .1M188.3 55.5h-21.3M188.4 55.4l-21.4 .1M188.5 55.4l-.7 .3M190.5 55.4h.5M190.6 55.4h.3"/>
<path d="M190.6 59.1h.3M190.7 55.5h.1M190.8 59.1l-.3 .1M190.8 59.1l.2 .1M190.8 59.1h.1M192.8 59.9l-17.9 .1M192.9 59.8h-18M192.9 59.7l-18 .1M193 59.6h-18.1M193 59.5h-18M193 55.4l.7 .3M193.1 59.4h-18.1"/>
<path d="M193.1 59.3h-18.1M193.1 59.2l-18.1 .1M193.1 55.4h8M193.1 59.2h-18.1M193.1 59.1h.1M193.2 55.5h7.8M193.2 59.1l-.2 .1M193.2 59.1l-.4 .9M193.4 55.5h7.4M193.5 55.6h7.2M193.6 55.6h7M193.7 55.7l.6 .5"/>
<path d="M193.7 55.7h6.8M193.8 55.8h6.6M193.9 55.9h6.4M194 55.9h6.3M194 56h6.2M194.1 56h6.1M194.1 56.1h6M194.2 56.1h5.8M194.2 56.2h5.8M194.3 56.2l.2 .7M194.3 58.2h5.6M194.4 58.3h-.1"/>
<path d="M194.4 58.1h5.5M194.4 58.1h5.4M194.4 58h5.4M194.4 56.6h5.4M194.4 57.9h5.3M194.5 57.8h5.2M194.5 56.7h5.2M194.5 57.7h5.2M194.5 56.8h5.2M194.5 58.2l-.2 .1M194.5 56.9h5.2M194.5 57.6h5.2"/>
<path d="M194.5 57.5h5.2M194.5 57.4h5.2M194.5 57.3h5.2M194.5 57.2h5.2M194.5 57.1h5.2M194.5 57h5.2M194.5 57.7l-.2 .6M194.5 56.9v.8M194.6 58.2h-.3M194.6 58.2l-.3 .1M198.1 58.2h.1M199.7 57.7l.2 .5h-1.8"/>
<path d="M199.7 56.9v.8M199.8 56.5l-5.4 .1M199.8 56.5h-5.4M199.9 56.4l-5.5 .1M199.9 56.4h-5.6M199.9 56.3h-5.6M199.9 56.2l-5.6 .1M199.9 56.2l-.2 .7M200.5 55.7l-.6 .5M201.2 55.4l-.7 .3M203.2 55.4l.7 .3M203.3 55.4h11.5"/>
<path d="M203.4 55.5h11.4M203.6 55.5h11.2M203.6 55.6h11.2M203.8 55.6h11M203.9 55.7h10.9M203.9 55.7l.5 .5 .3 .7M203.9 55.8h10.9M204 55.8h10.8M204.1 55.9h10.7M204.2 56h10.6M204.2 58.5h2.7M204.2 58.5l.7 .7 .3 .8"/>
<path d="M204.3 56.1h10.5M204.3 58.6h2.6M204.3 58.7h2.6M204.3 58.4h2.7M204.4 58.4h2.6M204.4 56.2h10.4M204.4 58.7h2.5M204.4 58.4l-.2 .1M204.4 58.3h2.6M204.4 58.8h2.5M204.4 56.3h10.4M204.5 58.2h2.5"/>
<path d="M204.5 56.3h10.3M204.5 56.4h10.3M204.5 58.8h2.4M204.5 56.5h10.3M204.6 58.9h2.3M204.6 57.9h2.6M204.7 59h2.2M204.7 57.7l-.3 .7M204.7 56.9v.8M204.8 59.1h2.1M204.9 59.2h2M204.9 59.3h2"/>
<path d="M204.9 59.4h2M205 59.4h1.9M205 59.5h1.9M205 59.6h1.9M205.1 59.7h1.8M205.1 59.7l1.8 .1M205.1 59.8h1.8M205.1 59.9h1.8M205.2 59.9h1.8M205.2 60h1.8M206.9 58.8v.7M206.9 59.5l.1 .7"/>
<path d="M207 58.4l-2.7 .1M207 58.2l-.1 .6M207.1 58.1l-2.6 .1M207.1 58.1h-2.6M207.1 58l-2.6 .1M207.2 58h-2.6M207.2 57.9h-2.6M207.2 57.8h-2.6M207.3 57.8h-2.7M207.3 57.7h-2.6M207.4 57.6h-2.7M207.5 57.5h-2.8"/>
<path d="M207.5 57.4l-2.8 .1M207.6 57.4h-2.9M207.6 57.3l-2.9 .1M207.7 57.3h-3M207.7 57.2l-3 .1M207.8 57.2h-3.1M207.8 57.1h-3.1M207.9 57.1l-.9 1.1M207.9 57.1h-3.2M208 57h-3.3M208.1 57h-3.4M208.2 56.9h-3.5"/>
<path d="M208.3 56.9h-3.6M208.3 56.8h-3.6M208.4 56.7l-3.8 .1M208.6 56.7h-4M208.9 56.6l-4.3 .1M209 56.6h-4.4M209.1 56.6l-1.2 .5M209.8 56.6a2.67 2.67 0 0 1 2.3 2.2M210 56.6h4.8M210.1 56.6h4.7M210.4 56.7h4.4M210.5 56.7h4.3"/>
<path d="M210.6 56.8h4.2M210.7 56.9h4.1M210.8 56.9h4M210.9 57h3.9M211 57h3.8M211.1 57.1h3.7M211.2 57.2h3.6M211.3 57.3h3.5M211.4 57.4h3.4M211.5 57.4h3.3M211.5 57.5h3.3M211.6 57.6h3.2"/>
<path d="M211.6 57.7h3.2M211.7 57.7h3.1M211.7 57.8h3.1M211.8 57.9h3M211.8 58h3M211.9 58.1h2.9M211.9 58.2h2.9M212 58.3h2.8M212 60h2.8M212 58.4h2.8M212 59.9h2.8M212 59.8h2.8"/>
<path d="M212 58.5h2.8M212 59.7h2.8M212 58.6h2.8M212.1 59.7h2.7M212.1 59.6h2.7M212.1 58.7h2.7M212.1 58.8h2.7M212.1 59.1h2.7M212.1 59.5h2.7M212.1 59.4h2.7M212.1 59.3h2.7M212.1 59.2h2.7"/>
<path d="M212.1 59h2.7M212.1 58.9h2.7M212.1 58.8v.7M212.1 59.5a2.67 2.67 0 0 1-2.3 2.3M214.8 56.5l-10.2 .1M214.8 55.4h-47.8M67.4 78.4h5.3M67.4 75.7h5.4M67.4 75.8h5.4M67.4 74.3h5.4M67.4 74.4h5.4M67.4 62.7h27.5"/>
<path d="M67.4 61.8h26.2M67.4 67.7h10.5M67.4 80h4.6M67.4 79.9h4.6M67.4 79.8h4.6M67.4 79.7h4.6M67.4 79.6h4.6M67.4 79.5h4.6M67.4 79.4h4.6M67.4 79.3h4.6M67.4 79h4.7M67.4 78.9h4.7"/>
<path d="M67.4 78.5h5.3M67.4 78.3h5.3M67.4 78.2h5.3M67.4 78.1h5.3M67.4 78h5.3M67.4 77.9h5.3M67.4 77.8h5.3M67.4 77.7h5.3M67.4 77.6h5.3M67.4 77.5h5.3M67.4 77.4h5.3M67.4 77.3h5.3"/>
<path d="M67.4 77.2h5.3M67.4 77.1h5.3M67.4 77h5.3M67.4 76.9h5.3M67.4 76.8h5.3M67.4 76.7h5.3M67.4 76.6h5.3M67.4 76.2h5.4M67.4 76.1h5.4M67.4 76h5.4M67.4 75.9h5.4M67.4 75.6h5.4"/>
<path d="M67.4 75.5h5.4M67.4 75.4h5.4M67.4 75.3h5.4M67.4 75.2h5.4M67.4 75.1h5.4M67.4 75h5.4M67.4 74.9h5.4M67.4 74.8h5.4M67.4 74.7h5.4M67.4 74.6h5.4M67.4 74.5h5.4M67.4 74.2h5.4"/>
<path d="M67.4 74.1h5.4M67.4 74h5.4M67.4 73.9h5.4M67.4 73.8h5.4M67.4 73.7h5.4M67.4 73.7h5.3M67.4 73.6h5.3M67.4 73.5h5.3M67.4 73.4h5.3M67.4 73.3h5.3M67.4 73.2h5.3M67.4 73.1h5.3"/>
<path d="M67.4 73h5.3M67.4 72.9h5.3M67.4 72.8h5.3M67.4 72.7h5.3M67.4 72.6h5.3M67.4 72.5h5.3M67.4 72.4h5.3M67.4 72.3h5.3M67.4 72.2h5.3M67.4 72.1h5.3M67.4 72h5.3M67.4 71.9h5.3"/>
<path d="M67.4 71.8h5.3M67.4 71.7h5.3M67.4 71.6h5.3M67.4 71.5h5.3M67.4 71.4h5.3M67.4 71.3h5.3M67.4 71.2h5.4M67.4 71.1h5.4M67.4 71.1h5.5M67.4 71h5.5M67.4 70.9h5.5M67.4 70.7h5.7"/>
<path d="M67.4 70.4h6M67.4 70h10.5M67.4 69.9h10.5M67.4 69.8h10.5M67.4 69.7h10.5M67.4 69.6h10.5M67.4 69.5h10.5M67.4 69.4h10.5M67.4 69.3h10.5M67.4 69.2h10.5M67.4 69.1h10.5M67.4 69h10.5"/>
<path d="M67.4 68.9h10.5M67.4 68.8h10.5M67.4 68.7h10.5M67.4 68.6h10.5M67.4 68.5h10.5M67.4 68.4h10.5M67.4 68.3h10.5M67.4 68.2h10.5M67.4 68.1h10.5M67.4 68h10.5M67.4 67.9h10.5M67.4 67.8h10.5"/>
<path d="M67.4 67.6h10.5M67.4 67.5h10.5M67.4 67.4h10.5M67.4 67.3h10.5M67.4 67.2h10.5M67.4 67.1h10.5M67.4 67h10.5M67.4 66.9h10.5M67.4 66.8h10.5M67.4 66.7h10.5M67.4 66.6h10.5M67.4 66.5h10.5"/>
<path d="M67.4 66.4l10.5 .1M67.4 66.4h10.5M67.4 66.3l10.4 .1M67.4 66.3h10.4M67.4 66.2l10.4 .1M67.4 66.2h10.4M67.4 66.1h10.4M67.4 66h10.4M67.4 65.9h10.4M67.4 65.8h10.4M67.4 65.7h10.4M67.4 65.6h10.4"/>
<path d="M67.4 65.5h10.4M67.4 65.4h10.4M67.4 65.3h10.4M67.4 65.2h10.4M67.4 65.1h10.4M67.4 65h10.4M67.4 64.9h10.4M67.4 64.8h10.4M67.4 64.7h10.4M67.4 64.6h10.4M67.4 64.5h10.4M67.4 64.4h10.4"/>
<path d="M67.4 64.3h10.4M67.4 64.2h10.4M67.4 64.1h10.4M67.4 64h10.5M67.4 63.9h10.5M67.4 63.8h10.6M67.4 63.6h10.6M67.4 63.3h10.8M67.4 63h11.1M67.4 62.6l27.4 .1M67.4 62.6h27.3M67.4 62.5l27.2 .1"/>
<path d="M67.4 62.5h27M67.4 62.4l26.9 .1M67.4 62.4h26.7M67.4 62.3l26.7 .1M67.4 62.3h26.6M67.4 62.2l26.6 .1M67.4 62.2h26.5M67.4 62.1h26.5M67.4 62.1h26.4M67.4 62h26.4M67.4 62h26.3M67.4 61.9h26.3"/>
<path d="M67.4 61.8l26.2 .1M67.4 61.7l4.7 .1M67.4 61.7h4.6M67.4 61.6l4.4 .1M67.4 61.6h4.2M67.4 61.5l4.1 .1M67.4 61.5h4M67.4 61.4h3.9M67.4 61.3h3.7M67.4 61.2h3.6M67.4 61.1h3.5M67.4 61l3.4 .1"/>
<path d="M67.4 61h3.4M67.4 60.9l3.4 .1M67.4 60.9h3.3M67.4 60.8l3.2 .1M67.4 60.8h3.2M67.4 60.7l3.1 .1M67.4 60.7h3.1M67.4 60.6l3.1 .1M67.4 60.6h3M67.4 60.5h3M67.4 60.4h3M67.4 60.3l2.9 .1"/>
<path d="M67.4 60.3h2.9M67.4 60.2l2.9 .1M67.4 60.2h2.8M67.4 60.1l2.8 .1M67.4 60.1h2.8M67.4 60l2.8 .1M70.2 60.2l.4 .6M70.6 60.8l.5 .5M71.1 61.3l1.2 .5M72 79.3v9.3M72 79.2h-4.6M72 79.1h-4.6"/>
<path d="M72.1 79.1h-4.7M72.1 79h-4.7M72.1 78.9l-.1 .4M72.2 78.8l-4.8 .1M72.2 78.8h-4.8M72.3 78.7l-4.9 .1M72.3 78.7h-4.9M72.4 78.6l-.3 .3M72.4 78.6l-5 .1M72.5 78.6h-5.1M72.6 78.5l-5.2 .1M72.7 71.5v2"/>
<path d="M72.7 76.6v1.9M72.7 73.5l.1 .3M72.7 78.5l-.3 .1M72.7 76.5h-5.3M72.7 76.4l-5.3 .1M72.8 76.4h-5.4M72.8 71.3h-5.4M72.8 76.3h-5.4M72.8 73.8v2.5M72.8 76.3l-.1 .3M72.8 71.2h-5.4M73 70.8l-.3 .7"/>
<path d="M73 70.8l-5.6 .1M73 70.8h-5.6M73 70.7l-5.6 .1M73.2 70.6l-5.8 .1M73.2 70.6h-5.8M73.2 61.8h20.3M73.3 70.5l-5.9 .1M73.3 70.5h-5.9M73.3 61.7h20.2M73.4 70.4h-6M73.5 70.3l-6.1 .1M73.5 70.3h-6.1"/>
<path d="M73.6 61.7h19.9M73.7 70.2l-6.3 .1M73.7 61.6h19.7M73.8 70.2h-6.4M73.8 61.6h19.6M73.9 61.5h19.5M74 70.1h-6.6M74 61.4h19.3M74.1 61.4h19.2M74.2 61.3h19.1M74.2 70l-.7 .3-.5 .5M74.3 61.3h19"/>
<path d="M74.3 61.3l-1.3 .5M74.3 61.2h19M74.4 61.2h18.8M74.4 61.1h18.8M74.5 61.1h18.7M74.5 61h18.7M74.6 61h18.6M74.6 60.9h18.5M74.7 60.9h18.4M74.8 60.8l-.5 .5M74.8 60.8h18.3M74.8 60.7h18.3"/>
<path d="M74.8 60.6h18.3M74.9 60.6h18.2M74.9 60.5h18.2M75 70l.6 .3M75 60.5h18.1M75 60.4h18.1M75 60.3h18.1M75.1 60.3h18M75.1 70.1h2.8M75.1 60.2h18M75.1 60.2l-.3 .6M75.1 60.1h18"/>
<path d="M75.2 70.1h2.7M75.4 70.2h2.5M75.5 70.2h2.4M75.6 70.3l.6 .5M75.6 70.3h2.3M75.7 70.3h2.2M75.7 70.4h2.2M75.8 70.4h2.1M75.8 70.5h2.1M75.9 70.5h2M75.9 70.6h2M76 70.6h1.9"/>
<path d="M76.1 70.7h1.8M76.2 70.8h1.7M76.2 70.8l.3 .7M76.2 70.9h1.7M76.2 71h1.7M76.3 71.1h1.6M76.3 71.2h1.6M76.3 73.8v.8M76.3 74.6h.1M76.3 71.3h1.6M76.4 74.6h-.1M76.4 71.4h1.5"/>
<path d="M76.4 71.3h1.5M76.4 74.5h-.1M76.5 73.5l-.2 .3M76.5 71.5v2M76.5 73h1.4M76.5 72.9h1.4M76.5 72.8h1.4M76.5 72.7h1.4M76.5 72.6h1.4M76.5 72.5h1.4M76.5 72.4h1.4M76.5 72.3h1.4"/>
<path d="M76.5 72.2h1.4M76.5 72.1h1.4M76.5 72h1.4M76.5 71.9h1.4M76.5 71.8h1.4M76.5 71.7h1.4M76.5 71.6h1.4M76.5 71.5h1.4M76.5 74.5h-.2M76.5 74.4h-.2M76.6 74.4h-.3M76.6 74.3h-.3"/>
<path d="M76.7 74.3h-.4M76.8 74.2h-.5M76.8 74.1l-.5 .1M76.9 74.1h-.6M76.9 74l-.6 .1M77 74h-.7M77 73.9l-.7 .1M77.1 73.9h-.8M77.1 73.8l-.8 .1M77.2 73.8h-.9M77.2 73.7h-.8M77.3 73.7h-.9"/>
<path d="M77.3 73.6h-.9M77.4 73.6h-1M77.4 73.5h-.9M77.5 73.4l-1 .1M77.5 73.4h-1M77.6 73.3l-1.1 .1M77.6 73.3h-1.1M77.7 73.2l-1.2 .1M77.8 64.2v2l.1 .3M77.8 73.2h-1.3M77.8 73.1l-1.3 .1M77.9 73.1h-1.4"/>
<path d="M77.9 73l-1.6 1.6M77.9 70h-10.5M77.9 66.5v6.5M77.9 63.8h-10.5M78 63.7h-10.6M78 63.6h-10.6M78 63.5l-10.6 .1M78.1 63.5h-10.7M78.1 63.4l-10.7 .1M78.2 63.4h-10.8M78.3 63.3h-10.9M78.3 63.2h-10.9"/>
<path d="M78.4 63.2h-11M78.4 63.1h-11M78.5 63.1h-11.1M78.7 62.9l-11.3 .1M78.8 62.9h-11.4M78.9 62.8l-11.5 .1M79 62.8h-11.6M79.2 62.7l-11.8 .1M79.3 62.7l-.7 .3-.6 .5-.2 .7M80 62.7l.7 .3 .5 .5 .3 .7M80.1 62.7h20.6v1.2M80.3 62.8h20.4"/>
<path d="M80.4 62.8h20.3M80.5 62.9h20.2M80.6 62.9h20.1M80.8 63h19.9M80.8 63.1h19.9M80.9 63.1h19.8M80.9 63.2h19.8M81 63.2h19.7M81 63.3h19.7M81.1 63.3h19.6M81.1 63.4h19.6M81.2 63.4h19.5"/>
<path d="M81.2 63.5h19.5M81.3 63.5h19.4M81.3 63.6h19.4M81.3 63.7h19.4M81.3 63.8h19.4M81.4 63.8h19.3M81.4 63.9h19.3M81.4 66.5v3.7M81.4 67.7l33.7 .1M81.4 70.2h.1M81.4 70h33.7M81.4 69.9h33.7"/>
<path d="M81.4 69.8h33.7M81.4 69.7h33.7M81.4 69.6h33.7M81.4 69.5h33.7M81.4 69.4h33.7M81.4 69.3h33.7M81.4 69.2h33.7M81.4 69.1h33.7M81.4 69h33.7M81.4 68.9h33.7M81.4 68.8h33.7M81.4 68.7h33.7"/>
<path d="M81.4 68.6h33.7M81.4 68.5h33.7M81.4 68.4h33.7M81.4 68.3h33.7M81.4 68.2h33.7M81.4 68.1h33.7M81.4 68h33.7M81.4 67.9h33.7M81.4 67.8h33.7M81.4 67.7h20.7M81.4 67.6h20.5M81.4 67.6h20.4"/>
<path d="M81.4 67.5h20.3M81.4 67.5h20.2M81.4 67.4h20M81.4 67.3h19.9M81.4 67.2l19.9 .1M81.4 67.2h19.8M81.4 67.1l19.8 .1M81.4 67.1h19.7M81.4 67l19.7 .1M81.4 67h19.6M81.4 66.9l19.6 .1M81.4 66.9h19.5"/>
<path d="M81.4 66.8h19.5M81.4 66.7h19.4M81.4 66.6h19.4M81.4 66.5l19.4 .1M81.4 66.5h19.3M81.4 64h19.3M81.4 66.4h19.3M81.5 66.4h19.2M81.5 64.1h19.2M81.5 66.3h19.1M81.5 64.1h19.1M81.5 66.2l-.1 .3"/>
<path d="M81.5 64.2v2M81.5 66.2h19.1M81.5 66.1h19.1M81.5 66h19.1M81.5 65.9h19.1M81.5 65.8h19.1M81.5 65.7h19.1M81.5 65.6h19.1M81.5 65.5h19.1M81.5 65.4h19.1M81.5 65.3h19.1M81.5 65.2h19.1"/>
<path d="M81.5 65.1h19.1M81.5 65h19.1M81.5 64.9h19.1M81.5 64.8h19.1M81.5 64.7h19.1M81.5 64.6h19.1M81.5 64.5h19.1M81.5 64.4h19.1M81.5 64.3h19.1M81.5 64.2h19.1M81.6 70.1h-.2M81.7 70.1h-.3"/>
<path d="M81.8 70l-.4 .2M82.6 70l.6 .3M82.7 70.1h2.1M82.8 70.1h1.9M83 70.2h1.6M83.1 70.2h1.4M83.2 70.3l.5 .5M83.2 70.3h1.1M83.3 70.3h1M83.4 70.4h.8M83.5 70.5h.6M83.6 70.6h.4"/>
<path d="M83.6 70.6h.3M83.7 70.7h.2M83.7 70.7h.1M85 70l-.7 .3-.5 .5M85.7 70l.7 .3M85.9 70.1h29.2M86 70.1h29.1M86.1 70.2h29M86.3 70.2h28.8M86.4 75.3v.1M86.4 74.8v.5M86.4 75.3h28.7"/>
<path d="M86.4 75.2h28.7M86.4 75.1h28.7M86.4 75h28.7M86.4 74.9h28.7M86.4 74.8h28.7M86.4 70.3h28.7M86.4 75.4l.5 .4M86.4 74.8h.1M86.4 70.3l.5 .5M86.4 75.4h28.7M86.5 74.7h28.6M86.5 70.3h28.6"/>
<path d="M86.5 75.4h28.6M86.5 75.5h28.6M86.5 74.6h28.6M86.5 70.4h28.6M86.6 70.4h28.5M86.6 75.5h28.5M86.6 74.6h28.5M86.6 75.6h28.5M86.6 74.5h28.5M86.6 70.5h28.5M86.7 70.5h28.4M86.7 75.6h28.4"/>
<path d="M86.7 74.5h28.4M86.7 74.4h28.4M86.7 75.7h28.4M86.7 70.6h28.4M86.8 70.6h28.3M86.8 74.4h10.5M86.8 75.7h10.5M86.8 75.8h10.4M86.8 74.3h10.4M86.8 70.7h10.4M86.9 70.7h10.2M89.3 70.7l-.1 .1"/>
<path d="M90 70.7v.1M93.1 60v.9M93.1 60.9l.4 .8 .6 .7 .9 .3M97.4 75.7l-.3 .1M97.4 74.4l-.3-.1h-10.2l-.5 .5M97.4 70.6l-.3 .2M98.1 75.7h.1M98.4 62.7h1.8M99.4 75.7l.7 .3M99.4 70.6l.7 .3M99.4 74.4h15.7M99.5 75.7h15.6"/>
<path d="M99.5 75.8h15.6M99.5 74.3h15.6M99.5 70.7h15.6M99.6 70.7h15.5M99.7 74.3h15.4M99.7 75.8h15.4M99.8 70.8h15.3M99.8 75.9h15.3M99.8 74.2h15.3M99.9 70.8h15.2M99.9 75.9h15.2M99.9 74.2h15.2"/>
<path d="M100 74.1h15.1M100.1 70.9h15M100.1 76l.5 .5M100.1 70.9l.5 .5M100.1 76h15M100.1 74.1h15M100.1 71h15M100.1 76.1h15M100.2 76.1h14.9M100.2 74h14.9M100.2 71h14.9M100.2 71.1h14.9"/>
<path d="M100.2 76.2h14.9M100.2 73.9h14.9M100.3 71.1h14.8M100.3 76.2h14.8M100.3 73.9h14.8M100.3 71.2h14.8M100.4 76.3h14.7M100.4 73.9h14.7M100.4 73.8h14.7M100.4 71.2h14.7M100.4 73.7h14.7M100.4 71.3h14.7"/>
<path d="M100.5 76.4h14.6M100.5 73.7h14.6M100.5 71.3h14.6M100.5 71.4h14.6M100.6 76.5h14.5M100.6 73.6h14.5M100.6 71.4h14.5M100.6 71.4l.3 .7v.8M100.6 76.5l.3 .7M100.6 73.6l-.5 .5-.7 .3M100.6 64.2v2M100.6 66.2l.3 .7 .5 .6 .7 .2"/>
<path d="M100.6 76.6h14.5M100.6 73.5h14.5M100.6 71.5h14.5M100.7 76.7h14.4M100.7 73.4h14.4M100.7 71.6h14.4M100.7 78.4h14.4M100.7 76.8h14.4M100.7 73.3h14.4M100.7 71.7h14.4M100.7 63.9l-.1 .3M100.7 71.8h14.4"/>
<path d="M100.8 78.3h14.3M100.8 76.9h14.3M100.8 73.2h14.3M100.8 71.8h14.3M100.8 71.9h14.3M100.8 78.2h14.3M100.8 73.1h14.3M100.8 78.1h14.3M100.8 77h14.3M100.8 72h14.3M100.8 73h14.3M100.9 78.1h14.2"/>
<path d="M100.9 78h14.2M100.9 77.2h14.2M100.9 77.1h14.2M100.9 73h14.2M100.9 72.1h14.2M100.9 72.9h14.2M100.9 78l-.2 .5 14.4-.1M100.9 77.2v.8M100.9 72.9l-.3 .7M100.9 77.9h14.2M100.9 77.8h14.2M100.9 77.7h14.2"/>
<path d="M100.9 77.6h14.2M100.9 77.5h14.2M100.9 77.4h14.2M100.9 77.3h14.2M100.9 72.8h14.2M100.9 72.7h14.2M100.9 72.6h14.2M100.9 72.5h14.2M100.9 72.4h14.2M100.9 72.3h14.2M100.9 72.2h14.2M102.9 67.7h12.2"/>
<path d="M103.1 67.6h12M103.2 67.6h11.9M103.4 67.5h11.7M103.6 67.4h11.5M103.7 67.3h11.4M103.8 67.2h11.3M103.9 67.1h11.2M104 67h11.1M104.1 67h11M104.1 66.9h11M104.1 66.8h11M104.2 66.7h10.9"/>
<path d="M104.2 66.6h10.9M104.2 66.5h10.9M104.3 62.7h10.8M104.3 63.9l.1 .3v2l-.3 .7-.5 .6-.7 .2M104.3 62.5v1.4M104.3 66.5h10.8M104.3 63.9h10.8M104.3 63.8h10.8M104.3 63.7h10.8M104.3 63.6h10.8M104.3 63.5h10.8M104.3 63.4h10.8"/>
<path d="M104.3 63.3h10.8M104.3 63.2h10.8M104.3 63.1h10.8M104.3 63h10.8M104.3 62.9h10.8M104.3 62.8h10.8M104.3 62.6h10.8M104.3 62.5h10.8M104.3 66.4h10.8M104.3 64h10.8M104.3 64.1h10.8M104.4 66.3h10.7"/>
<path d="M104.4 64.1h10.7M104.4 62.5h10.7M104.4 64.2h10.7M104.4 66.2h10.7M104.4 66.1h10.7M104.4 66h10.7M104.4 65.9h10.7M104.4 65.8h10.7M104.4 65.7h10.7M104.4 65.6h10.7M104.4 65.5h10.7M104.4 65.4h10.7"/>
<path d="M104.4 65.3h10.7M104.4 65.2h10.7M104.4 65.1h10.7M104.4 65h10.7M104.4 64.9h10.7M104.4 64.8h10.7M104.4 64.7h10.7M104.4 64.6h10.7M104.4 64.5h10.7M104.4 64.4h10.7M104.4 64.3h10.7M104.5 62.4h10.6"/>
<path d="M104.5 62.4l-.2 .1M104.6 62.4h10.5M104.6 62.3h10.5M104.7 62.3h10.4M104.7 62.2h10.4M104.8 62.1h10.3M104.9 62h10.2M105 61.9h10.1M105.1 61.9h10M105.1 61.8h10M105.2 61.8h4.1M105.2 61.7l-.7 .7"/>
<path d="M105.2 61.7h3.9M105.2 61.6l3.7 .1M105.2 61.6h3.6M105.3 61.5l3.4 .1M105.3 61.5h3.3M105.3 61.4h3.2M105.3 61.4h3.1M105.3 61.3h3M105.4 61.3h2.8M105.4 61.2h2.7M105.4 61.1h2.6M105.5 61.1h2.5"/>
<path d="M105.5 61h2.4M105.5 60.9h2.3M105.5 60.9l-.3 .8M105.5 60v.9M105.5 60.8l2.3 .1M105.5 60.8h2.2M105.5 60.7l2.2 .1M105.5 60.7h2.2M105.5 60.6l2.1 .1M105.5 60.6h2.1M105.5 60.5l2.1 .1M105.5 60.5h2"/>
<path d="M105.5 60.4h2M105.5 60.3l2 .1M105.5 60.3h1.9M105.5 60.2l1.9 .1M105.5 60.2h1.9M105.5 60.1l1.9 .1M105.5 60.1h1.8M107.7 60.8l1.1 .8 .7 .2M109.7 78.5l.4 .1M109.7 78.5h5.4M109.8 78.5h5.3M110 78.6h5.1"/>
<path d="M110.1 78.6l.3 .3M110.1 78.6h5M110.1 78.7h5M110.2 78.7h4.9M110.2 78.8h4.9M110.3 78.8h4.8M110.3 61.8h4.8M110.3 78.9h4.8M110.4 78.9l.1 .4M110.4 79h4.7M110.4 79.1h4.7M110.5 79.2h4.6"/>
<path d="M110.5 61.7h4.6M110.5 79.3h4.6M110.5 79.3v9.3M110.5 80h4.6M110.5 79.9h4.6M110.5 79.8h4.6M110.5 79.7h4.6M110.5 79.6h4.6M110.5 79.5h4.6M110.5 79.4h4.6M110.7 61.7h4.4M110.8 61.6h4.3"/>
<path d="M110.9 61.6h4.2M111 61.5h4.1M111.1 61.4h4M111.2 61.4h3.9M111.3 61.3h3.8M111.4 61.3h3.7M111.5 61.2h3.6M111.6 61.1h3.5M111.7 61h3.4M111.8 60.9h3.3M111.9 60.8h3.2M111.9 60.8l-1.1 .8-.6 .2"/>
<path d="M111.9 60.7h3.2M112 60.7h3.1M112 60.6h3.1M112.1 60.5h3M112.1 60.4h3M112.2 60.3h2.9M112.2 60.2l-.3 .6M112.2 60.2h2.9M112.3 60.1h2.8M115.1 70h-33.7M117.2 78.4h5.3M117.2 75.7h5.4"/>
<path d="M117.2 75.8h5.4M117.2 74.3h5.4M117.2 74.4h5.4M117.2 62.7h27.6M117.2 61.8h26.2M117.2 67.7h10.5M117.2 80h4.6M117.2 79.9h4.6M117.2 79.8h4.6M117.2 79.7h4.6M117.2 79.6h4.6M117.2 79.5h4.6"/>
<path d="M117.2 79.4h4.6M117.2 79.3h4.6M117.2 79.2h4.6M117.2 79.1h4.7M117.2 79h4.7M117.2 78.7h5M117.2 78.5h5.3M117.2 78.3h5.3M117.2 78.2h5.3M117.2 78.1h5.3M117.2 78h5.3M117.2 77.9h5.3"/>
<path d="M117.2 77.8h5.3M117.2 77.7h5.3M117.2 77.6h5.3M117.2 77.5h5.3M117.2 77.4h5.3M117.2 77.3h5.3M117.2 77.2h5.3M117.2 77.1h5.3M117.2 77h5.3M117.2 76.9h5.3M117.2 76.8h5.3M117.2 76.7h5.3"/>
<path d="M117.2 76.6h5.3M117.2 76.5h5.4M117.2 76.3h5.4M117.2 76.2h5.4M117.2 76.1h5.4M117.2 76h5.4M117.2 75.9h5.4M117.2 75.6h5.4M117.2 75.5h5.4M117.2 75.4h5.4M117.2 75.3h5.4M117.2 75.2h5.4"/>
<path d="M117.2 75.1h5.4M117.2 75h5.4M117.2 74.9h5.4M117.2 74.8h5.4M117.2 74.7h5.4M117.2 74.6h5.4M117.2 74.5h5.4M117.2 74.2h5.4M117.2 74.1h5.4M117.2 74h5.4M117.2 73.9h5.4M117.2 73.8h5.4"/>
<path d="M117.2 73.7h5.4M117.2 73.6h5.4M117.2 73.5h5.3M117.2 73.4h5.3M117.2 73.3h5.3M117.2 73.2h5.3M117.2 73.1h5.3M117.2 73h5.3M117.2 72.9h5.3M117.2 72.8h5.3M117.2 72.7h5.3M117.2 72.6h5.3"/>
<path d="M117.2 72.5h5.3M117.2 72.4h5.3M117.2 72.3h5.3M117.2 72.2h5.3M117.2 72.1h5.3M117.2 72h5.3M117.2 71.9h5.3M117.2 71.8h5.3M117.2 71.7h5.3M117.2 71.6h5.3M117.2 71.5h5.3M117.2 71h5.5"/>
<path d="M117.2 70.9h5.6M117.2 70.8h5.6M117.2 70h10.5M117.2 69.9h10.5M117.2 69.8h10.5M117.2 69.7h10.5M117.2 69.6h10.5M117.2 69.5h10.5M117.2 69.4h10.5M117.2 69.3h10.5M117.2 69.2h10.5M117.2 69.1h10.5"/>
<path d="M117.2 69h10.5M117.2 68.9h10.5M117.2 68.8h10.5M117.2 68.7h10.5M117.2 68.6h10.5M117.2 68.5h10.5M117.2 68.4h10.5M117.2 68.3h10.5M117.2 68.2h10.5M117.2 68.1h10.5M117.2 68h10.5M117.2 67.9h10.5"/>
<path d="M117.2 67.8h10.5M117.2 67.6h10.5M117.2 67.5h10.5M117.2 67.4h10.5M117.2 67.3h10.5M117.2 67.2h10.5M117.2 67.1h10.5M117.2 67h10.5M117.2 66.9h10.5M117.2 66.8h10.5M117.2 66.7h10.5M117.2 66.6h10.5"/>
<path d="M117.2 66.5h10.5M117.2 66.4h10.5M117.2 66.3l10.5 .1M117.2 66.3h10.4M117.2 66.2l10.4 .1M117.2 66.2h10.4M117.2 66.1h10.4M117.2 66h10.4M117.2 65.9h10.4M117.2 65.8h10.4M117.2 65.7h10.4M117.2 65.6h10.4"/>
<path d="M117.2 65.5h10.4M117.2 65.4h10.4M117.2 65.3h10.4M117.2 65.2h10.4M117.2 65.1h10.4M117.2 65h10.4M117.2 64.9h10.4M117.2 64.8h10.4M117.2 64.7h10.4M117.2 64.6h10.4M117.2 64.5h10.4M117.2 64.4h10.4"/>
<path d="M117.2 64.3h10.4M117.2 64.2h10.4M117.2 64h10.5M117.2 63.9h10.5M117.2 63.8h10.6M117.2 63.7h10.6M117.2 63.6h10.6M117.2 63.6h10.7M117.2 63.5h10.7M117.2 62.6l27.5 .1M117.2 62.6h27.3M117.2 62.5l27.2 .1"/>
<path d="M117.2 62.5h27.1M117.2 62.4l26.9 .1M117.2 62.4h26.8M117.2 62.3l26.7 .1M117.2 62.3h26.7M117.2 62.2l26.6 .1M117.2 62.2h26.6M117.2 62.1h26.5M117.2 62h26.4M117.2 61.9h26.3M117.2 61.8l26.2 .1M117.2 61.7l4.8 .1"/>
<path d="M117.2 61.7h4.6M117.2 61.6l4.4 .1M117.2 61.6h4.3M117.2 61.5l4.2 .1M117.2 61.5h4.1M117.2 61.4h4M117.2 61.4h3.9M117.2 61.3h3.8M117.2 61.3h3.7M117.2 61.2h3.6M117.2 61.1h3.5M117.2 61l3.5 .1"/>
<path d="M117.2 61h3.4M117.2 60.9l3.4 .1M117.2 60.9h3.3M117.2 60.8l3.3 .1M117.2 60.8h3.2M117.2 60.7l3.2 .1M117.2 60.7h3.2M117.2 60.6l3.1 .1M117.2 60.6h3.1M117.2 60.5l3.1 .1M117.2 60.5h3M117.2 60.4h3"/>
<path d="M117.2 60.3l3 .1M117.2 60.3h2.9M117.2 60.2l2.9 .1M117.2 60.2h2.9M117.2 60.1l2.9 .1M117.2 60.1h2.8M120.1 60.2l.8 1.1M120.9 61.3l1.3 .5M121.8 79.3v9.3M121.9 79.2h-4.7M121.9 79.1h-4.7M121.9 79h-4.7"/>
<path d="M121.9 78.9l-.1 .4M122 78.9h-4.8M122 78.8l-4.8 .1M122.1 78.8h-4.9M122.1 78.7l-4.9 .1M122.2 78.6l-5 .1M122.2 78.6l-.3 .3M122.3 78.6h-5.1M122.5 78.5l-5.3 .1M122.5 78.5l-.3 .1M122.5 71.5h-5.3M122.6 76.5h-5.4"/>
<path d="M122.6 71.4l-5.4 .1M122.6 71.4h-5.4M122.6 76.4h-5.4M122.6 71.3l-5.4 .1M122.6 71.3h-5.4M122.6 76.3h-5.4M122.6 71.2h-5.4M122.6 76.3l-.1 .3v1.9M122.6 73.8v2.5M122.7 71.2h-5.5M122.7 71.1h-5.5M122.7 71h-5.5"/>
<path d="M122.8 70.8l-5.6 .1M122.8 70.8l-.3 .7v2l.1 .3M122.9 70.7l-5.7 .1M122.9 70.7h-5.7M123 70.6l-5.8 .1M123 70.6h-5.8M123 61.8h20.3M123.1 70.5l-5.9 .1M123.1 70.5h-5.9M123.2 61.7h20.1M123.2 70.4l-6 .1M123.3 70.4h-6.1"/>
<path d="M123.3 70.3l-6.1 .1M123.3 70.3l-.5 .5M123.4 70.3h-6.2M123.4 61.7h19.9M123.5 70.2l-6.3 .1M123.5 61.6h19.8M123.6 70.2h-6.4M123.6 61.6h19.6M123.7 61.5h19.5M123.8 70.1h-6.6M123.8 61.4h19.4M123.9 70.1h-6.7"/>
<path d="M123.9 61.4h19.3M124 61.3h19.2M124 70l-.7 .3M124.1 61.3h19M124.2 61.2h18.9M124.3 61.1h18.8M124.3 61.1h18.7M124.4 61h18.6M124.5 60.9h18.5M124.6 60.8h18.4M124.6 60.7h18.4M124.7 60.7h18.3"/>
<path d="M124.7 60.6h18.3M124.8 60.5h18.2M124.8 70l.7 .3M124.8 60.4h18.2M124.9 60.3h18.1M124.9 60.2h18.1M124.9 70.1h2.8M124.9 60.2a2.64 2.64 0 0 1-2 1.6M125 60.1h18M125 60h18M125 70.1h2.7M125.2 70.2h2.5"/>
<path d="M125.3 70.2h2.4M125.5 70.3h2.2M125.5 70.3l.5 .5M125.6 70.4h2.1M125.7 70.5h2M125.8 70.6h1.9M125.9 70.7h1.8M126 70.8h1.7M126 70.8l.3 .7v2l-.1 .3M126 70.9h1.7M126.1 71h1.6M126.1 71.1h1.6"/>
<path d="M126.2 71.2h1.5M126.2 74.3h.3M126.2 74.6h.1M126.2 73.9h.7M126.2 73.8v.8M126.2 71.3h1.5M126.2 71.4h1.5M126.3 71.4h1.4M126.3 74.5h-.1M126.3 71.5h1.4M126.3 73.3h1.2M126.3 73h1.4"/>
<path d="M126.3 72.9h1.4M126.3 72.8h1.4M126.3 72.7h1.4M126.3 72.6h1.4M126.3 72.5h1.4M126.3 72.4h1.4M126.3 72.3h1.4M126.3 72.2h1.4M126.3 72.1h1.4M126.3 72h1.4M126.3 71.9h1.4M126.3 71.8h1.4"/>
<path d="M126.3 71.7h1.4M126.3 71.6h1.4M126.4 74.4h-.2M126.5 74.3h-.3M126.6 74.2h-.4M126.6 74.1l-.4 .1M126.7 74.1h-.5M126.7 74l-.5 .1M126.8 74h-.6M126.9 73.9h-.7M127 73.8l-.8 .1M127 73.8h-.8"/>
<path d="M127.1 73.7h-.9M127.2 73.6h-1M127.2 73.6h-.9M127.3 73.5h-1M127.3 73.4l-1 .1M127.4 73.4h-1.1M127.4 73.3l-1.1 .1M127.6 73.2l-1.3 .1M127.6 73.2h-1.3M127.6 64.2h-10.4M127.6 64.1l-10.4 .1M127.7 73.1l-1.4 .1"/>
<path d="M127.7 64.1h-10.5M127.7 64l-10.5 .1M127.7 70h-10.5M127.7 73.1h-1.4M127.7 63.9h-10.5M127.7 73l-1.5 1.6M127.7 66.5v6.5M127.8 63.8h-10.6M127.9 63.5l-.3 .7v2l.1 .3M127.9 63.5h-10.7M128 63.4l-10.8 .1M128 63.4h-10.8"/>
<path d="M128.1 63.3l-10.9 .1M128.1 63.3h-10.9M128.2 63.2h-11M128.3 63.1h-11.1M128.4 63.1h-11.2M128.4 63h-11.2M128.5 62.9l-11.3 .1M128.6 62.9h-11.4M128.8 62.8l-11.6 .1M128.9 62.8h-11.7M129 62.7l-11.8 .1M129.1 62.7l-.7 .3-.5 .5"/>
<path d="M129.9 62.7l.7 .3 .5 .5M129.9 62.7h20.7v1.2M130.1 62.8h20.5M130.2 62.8h20.4M130.4 62.9h20.2M130.5 62.9h20.1M130.6 63h20M130.6 63.1h20M130.7 63.1h19.9M130.7 63.2h19.9M130.8 63.2h19.8M130.8 63.3h19.8"/>
<path d="M130.9 63.3h19.7M130.9 63.4h19.7M131 63.4h19.6M131.1 63.5h19.5M131.1 63.5l.3 .7v2l-.1 .3M131.1 63.6h19.5M131.1 63.7h19.5M131.2 63.8h19.4M131.2 63.9h19.4M131.3 67.7l33.7 .1M131.3 70h33.7M131.3 69.9h33.7"/>
<path d="M131.3 69.8h33.7M131.3 69.7h33.7M131.3 69.6h33.7M131.3 69.5h33.7M131.3 69.4h33.7M131.3 69.3h33.7M131.3 69.2h33.7M131.3 69.1h33.7M131.3 69h33.7M131.3 68.9h33.7M131.3 68.8h33.7M131.3 68.7h33.7"/>
<path d="M131.3 68.6h33.7M131.3 68.5h33.7M131.3 68.4h33.7M131.3 68.3h33.7M131.3 68.2h33.7M131.3 68.1h33.7M131.3 68h33.7M131.3 67.9h33.7M131.3 67.8h33.7M131.3 67.7h20.6M131.3 67.6h20.5M131.3 67.6h20.4"/>
<path d="M131.3 67.5h20.2M131.3 67.5h20.1M131.3 67.4h20M131.3 67.4h19.9M131.3 67.3h19.9M131.3 67.2l19.8 .1M131.3 67.2h19.7M131.3 67.1l19.7 .1M131.3 67.1h19.6M131.3 67l19.6 .1M131.3 67h19.6M131.3 66.9l19.5 .1"/>
<path d="M131.3 66.9h19.4M131.3 66.8l19.4 .1M131.3 66.8h19.4M131.3 66.7h19.4M131.3 66.6h19.3M131.3 66.5h19.3M131.3 66.5v3.7M131.3 70.2h.1M131.3 66.4h19.2M131.3 66.3h19.2M131.4 66.2l19.1 .1M131.4 66.2h19.1"/>
<path d="M131.4 66.1h19.1M131.4 66h19.1M131.4 65.9h19.1M131.4 65.8h19.1M131.4 65.7h19.1M131.4 65.6h19.1M131.4 65.5h19.1M131.4 65.4h19.1M131.4 65.3h19.1M131.4 65.2h19.1M131.4 65.1h19.1M131.4 65h19.1"/>
<path d="M131.4 64.9h19.1M131.4 64.8h19.1M131.4 64.7h19.1M131.4 64.6h19.1M131.4 64.5h19.1M131.4 64.4h19.1M131.4 64.3h19.1M131.4 64.2h19.1M131.4 70.1h-.1M131.5 70.1h-.2M131.7 70l-.4 .2M132.4 70l.7 .3"/>
<path d="M132.5 70.1h2.2M132.7 70.1h1.9M132.8 70.2h1.6M132.9 70.2h1.4M133.1 70.3h1.1M133.1 70.3l.5 .5M133.1 70.3h1M133.2 70.4h.8M133.3 70.5h.6M133.4 70.6h.4M133.5 70.7h.2M134.1 70.3l-.6 .4"/>
<path d="M134.8 70l-.7 .3M135.6 70l.7 .3M135.7 70.1h29.3M135.8 70.1h29.2M136 70.2h29M136.1 70.2h28.9M136.2 75.3h28.8M136.2 75.2h28.8M136.2 75.1h28.8M136.2 75h28.8M136.2 74.9h28.8M136.2 74.8h28.8"/>
<path d="M136.2 75.3l.1 .1M136.2 74.8v.5M136.2 75.4h28.8M136.2 70.3h28.8M136.3 75.4l.4 .4M136.3 70.3l.4 .5M136.3 70.3h28.7M136.3 74.7h28.7M136.3 75.4h28.7M136.4 75.5h28.6M136.4 74.7h28.6M136.4 70.4h28.6"/>
<path d="M136.4 74.6h28.6M136.5 75.6h28.5M136.5 74.5h28.5M136.5 70.5h28.5M136.6 74.4h28.4M136.6 75.7h28.4M136.6 70.6h28.4M136.6 74.4h10.6M136.7 75.8h10.3M136.7 74.3h10.3M136.7 70.7h10.3M139.1 70.7v.1"/>
<path d="M139.8 70.7v.1M143.3 61.7l.7 .7M144 62.4l.8 .3M147.1 75.7l-10.4 .1M147.2 74.4l-.3-.1h-10.2l-.5 .5M147.2 75.7l-.3 .1M147.2 70.6l-.3 .2M148 75.7h.1M148.3 62.7h1.8M149.2 75.7l.7 .3M149.2 70.6l.7 .3M149.3 74.4h15.7"/>
<path d="M149.3 75.7h15.7M149.4 70.7h15.6M149.4 75.8h15.6M149.4 74.3h15.6M149.5 70.7h15.5M149.5 74.3h15.5M149.5 75.8h15.5M149.6 75.9h15.4M149.6 74.2h15.4M149.6 70.8h15.4M149.8 70.8h15.2M149.8 75.9h15.2"/>
<path d="M149.8 74.2h15.2M149.9 74.1h15.1M149.9 76h15.1M149.9 70.9h15.1M149.9 76l.6 .5M149.9 74.1l-.7 .3M149.9 70.9l.6 .5M149.9 71h15.1M150 74.1h15M150 76.1h15M150 74h15M150 71h15"/>
<path d="M150.1 71.1h14.9M150.1 76.2h14.9M150.1 74h14.9M150.1 73.9h14.9M150.2 71.2h14.8M150.2 76.3h14.8M150.2 73.9h14.8M150.2 73.8h14.8M150.3 71.3h14.7M150.3 73.7h14.7M150.3 76.4h14.7M150.4 71.4h14.6"/>
<path d="M150.4 76.5h14.6M150.4 73.6h14.6M150.5 76.5l.2 .7M150.5 73.6l-.6 .5M150.5 71.4l.2 .7M150.5 76.6h14.5M150.5 73.5h14.5M150.5 71.5h14.5M150.5 64.2h-19.1M150.5 64.1h-19.2M150.5 76.7h14.5M150.5 73.4h14.5"/>
<path d="M150.5 71.6h14.5M150.5 64h-19.2M150.6 78.4h14.4M150.6 76.8h14.4M150.6 73.3h14.4M150.6 71.7h14.4M150.6 64h-19.3M150.6 78.3h14.4M150.6 71.8h14.4M150.6 63.9h-19.3M150.6 63.9l-.1 .3v2l.2 .7 .6 .6 .7 .2M150.6 76.9h14.4"/>
<path d="M150.6 73.2h14.4M150.6 78.2h14.4M150.6 71.9h14.4M150.6 77h14.4M150.6 73.1h14.4M150.7 78.1h14.3M150.7 77h14.3M150.7 73h14.3M150.7 72h14.3M150.7 77.1h14.3M150.7 78h14.3M150.7 77.2h14.3"/>
<path d="M150.7 72.1h14.3M150.7 78l-.2 .5 14.5-.1M150.7 77.9h14.3M150.7 77.8h14.3M150.7 77.7h14.3M150.7 77.6h14.3M150.7 77.5h14.3M150.7 77.4h14.3M150.7 77.3h14.3M150.7 72.9h14.3M150.7 72.8h14.3M150.7 72.7h14.3"/>
<path d="M150.7 72.6h14.3M150.7 72.5h14.3M150.7 72.4h14.3M150.7 72.3h14.3M150.7 72.2h14.3M150.7 72.1v.8M150.7 77.2v.8M150.7 72.9l-.2 .7M152.8 67.7h12.2M152.9 67.6h12.1M153 67.6h12M153.2 67.5h11.8"/>
<path d="M153.3 67.5h11.7M153.4 67.4h11.6M153.5 67.4h11.5M153.5 67.3h11.5M153.6 67.3h11.4M153.6 67.2h11.4M153.7 67.2h11.3M153.7 67.1h11.3M153.8 67.1h11.2M153.8 67h11.2M153.9 67h11.1M153.9 66.9h11.1"/>
<path d="M154 66.8h11M154 66.7h11M154.1 66.6h10.9M154.1 62.7h10.9M154.1 66.5h10.9M154.1 63.9h10.9M154.1 63.8h10.9M154.1 63.7h10.9M154.1 63.6h10.9M154.1 63.5h10.9M154.1 63.4h10.9M154.1 63.3h10.9"/>
<path d="M154.1 63.2h10.9M154.1 63.1h10.9M154.1 63h10.9M154.1 62.9h10.9M154.1 62.8h10.9M154.1 62.6h10.9M154.1 62.5h10.9M154.1 63.9l.1 .3M154.1 62.5v1.4M154.1 64h10.9M154.2 66.4h10.8M154.2 64.1h10.8"/>
<path d="M154.2 66.3h10.8M154.2 62.5h10.8M154.2 66.2h10.8M154.2 66.1h10.8M154.2 66h10.8M154.2 65.9h10.8M154.2 65.8h10.8M154.2 65.7h10.8M154.2 65.6h10.8M154.2 65.5h10.8M154.2 65.4h10.8M154.2 65.3h10.8"/>
<path d="M154.2 65.2h10.8M154.2 65.1h10.8M154.2 65h10.8M154.2 64.9h10.8M154.2 64.8h10.8M154.2 64.7h10.8M154.2 64.6h10.8M154.2 64.5h10.8M154.2 64.4h10.8M154.2 64.3h10.8M154.2 64.2h10.8M154.2 66.2l-.3 .7-.5 .6-.7 .2"/>
<path d="M154.2 64.2v2M154.3 62.4h10.7M154.4 62.4h10.6M154.5 62.3h10.5M154.6 62.2h10.4M154.6 62.1h10.4M154.7 62.1h10.3M154.7 62h10.3M154.8 62h10.2M154.8 61.9h10.2M154.9 61.9h10.1M154.9 61.8h10.1"/>
<path d="M155 61.8h4.1M155 61.7h4M155.1 61.6l3.6 .1M155.1 61.6h3.5M155.1 61.5l3.4 .1M155.1 61.5h3.3M155.2 61.4h3.1M155.2 61.4h3M155.2 61.3h2.9M155.2 61.2h2.8M155.3 61.2h2.6M155.3 61.1h2.6"/>
<path d="M155.3 61l2.5 .1M155.3 61h2.5M155.3 61h2.4M155.4 60.9h2.3M155.4 60.8l2.2 .1M155.4 60.8h2.2M155.4 60.7h2.1M155.4 60.6h2.1M155.4 60.6h2M155.4 60.5h2M155.4 60.4h1.9M155.4 60.3l1.9 .1"/>
<path d="M155.4 60.3h1.9M155.4 60.2l1.8 .1M155.4 60.2h1.8M155.4 60.1h1.8M155.4 60h1.8M155.4 60.9l-.4 .8-.9 .8M155.4 60v.9M157.2 60.2a2.64 2.64 0 0 0 2.1 1.6M159.5 78.5h5.5M159.5 78.5l.4 .1M159.7 78.5h5.3M159.8 78.6h5.2"/>
<path d="M159.9 78.6h5.1M159.9 78.6l.3 .3M160 78.7h5M160.1 78.8h4.9M160.2 61.8h4.8M160.2 78.9h4.8M160.2 78.9l.2 .4M160.2 79h4.8M160.3 79.1h4.7M160.3 79.2h4.7M160.3 61.7h4.7M160.3 79.3h4.7"/>
<path d="M160.4 80h4.6M160.4 79.9h4.6M160.4 79.8h4.6M160.4 79.7h4.6M160.4 79.6h4.6M160.4 79.5h4.6M160.4 79.4h4.6M160.4 79.3h4.6M160.4 79.3v9.3M160.5 61.7h4.5M160.7 61.6h4.3M160.8 61.6h4.2"/>
<path d="M160.9 61.5h4.1M161 61.4h4M161.2 61.3h3.8M161.2 61.3l-1.2 .5M161.3 61.2h3.7M161.4 61.2h3.6M161.4 61.1h3.6M161.5 61.1h3.5M161.5 61h3.5M161.6 61h3.4M161.6 60.9h3.4M161.7 60.9h3.3"/>
<path d="M161.7 60.8h3.3M161.8 60.8h3.2M161.8 60.7h3.2M161.9 60.6h3.1M161.9 60.5h3.1M162 60.4h3M162 60.3h3M162.1 60.2h2.9M162.1 60.2l-.9 1.1M162.1 60.1h2.9M162.1 60h2.9M165 70h-33.7"/>
<path d="M167 78.4h5.4M167 75.7h5.5M167 75.8h5.5M167 74.3h5.5M167 74.4h5.5M167 62.7h27.6M167 61.8h26.2M167 67.7h10.6M167 80h4.6M167 79.9h4.6M167 79.8h4.6M167 79.7h4.6"/>
<path d="M167 79.6h4.6M167 79.5h4.6M167 79.4h4.6M167 79.3h4.6M167 79.2h4.7M167 79.1h4.7M167 79h4.7M167 78.9h4.8M167 78.5h5.4M167 78.3h5.4M167 78.2h5.4M167 78.1h5.4"/>
<path d="M167 78h5.4M167 77.9h5.4M167 77.8h5.4M167 77.7h5.4M167 77.6h5.4M167 77.5h5.4M167 77.4h5.4M167 77.3h5.4M167 77.2h5.4M167 77.1h5.4M167 77h5.4M167 76.9h5.4"/>
<path d="M167 76.8h5.4M167 76.7h5.4M167 76.6h5.4M167 76.5h5.4M167 76.4h5.4M167 76.3h5.5M167 76.2h5.5M167 76.1h5.5M167 76h5.5M167 75.9h5.5M167 75.6h5.5M167 75.5h5.5"/>
<path d="M167 75.4h5.5M167 75.3h5.5M167 75.2h5.5M167 75.1h5.5M167 75h5.5M167 74.9h5.5M167 74.8h5.5M167 74.7h5.5M167 74.6h5.5M167 74.5h5.5M167 74.2h5.5M167 74.1h5.5"/>
<path d="M167 74h5.5M167 73.9h5.5M167 73.8h5.5M167 73.7h5.4M167 73.6h5.4M167 73.5h5.4M167 73.4h5.4M167 73.3h5.4M167 73.2h5.4M167 73.1h5.4M167 73h5.4M167 72.9h5.4"/>
<path d="M167 72.8h5.4M167 72.7h5.4M167 72.6h5.4M167 72.5h5.4M167 72.4h5.4M167 72.3h5.4M167 72.2h5.4M167 72.1h5.4M167 72h5.4M167 71.9h5.4M167 71.8h5.4M167 71.7h5.4"/>
<path d="M167 71.6h5.4M167 71.5h5.4M167 71.4h5.4M167 71.3h5.4M167 71.3h5.5M167 71.2h5.5M167 71.1h5.5M167 71h5.6M167 70h10.6M167 69.9h10.6M167 69.8h10.6M167 69.7h10.6"/>
<path d="M167 69.6h10.6M167 69.5h10.6M167 69.4h10.6M167 69.3h10.6M167 69.2h10.6M167 69.1h10.6M167 69h10.6M167 68.9h10.6M167 68.8h10.6M167 68.7h10.6M167 68.6h10.6M167 68.5h10.6"/>
<path d="M167 68.4h10.6M167 68.3h10.6M167 68.2h10.6M167 68.1h10.6M167 68h10.6M167 67.9h10.6M167 67.8h10.6M167 67.6h10.6M167 67.5h10.6M167 67.4h10.6M167 67.3h10.6M167 67.2h10.6"/>
<path d="M167 67.1h10.6M167 67h10.6M167 66.9h10.6M167 66.8h10.6M167 66.7h10.6M167 66.6h10.6M167 66.5h10.6M167 66.4l10.5 .1M167 66.4h10.5M167 66.3l10.5 .1M167 66.3h10.5M167 66.2l10.5 .1"/>
<path d="M167 66.2h10.4M167 66.1h10.4M167 66h10.4M167 65.9h10.4M167 65.8h10.4M167 65.7h10.4M167 65.6h10.4M167 65.5h10.4M167 65.4h10.4M167 65.3h10.4M167 65.2h10.4M167 65.1h10.4"/>
<path d="M167 65h10.4M167 64.9h10.4M167 64.8h10.4M167 64.7h10.4M167 64.6h10.4M167 64.5h10.4M167 64.4h10.4M167 64.3h10.4M167 64.2h10.4M167 64.1h10.5M167 64h10.5M167 62.6l27.5 .1"/>
<path d="M167 62.6h27.4M167 62.5l27.2 .1M167 62.5h27.1M167 62.4l27 .1M167 62.4h26.8M167 62.3l26.8 .1M167 62.3h26.7M167 62.2l26.7 .1M167 62.2h26.6M167 62.1h26.5M167 62h26.4M167 61.9h26.4"/>
<path d="M167 61.8l26.3 .1M167 61.7l4.8 .1M167 61.7h4.7M167 61.6l4.4 .1M167 61.6h4.3M167 61.5l4.2 .1M167 61.5h4.1M167 61.4h4M167 61.4h3.9M167 61.3h3.8M167 61.2h3.7M167 61.2h3.6"/>
<path d="M167 61.1h3.6M167 61l3.5 .1M167 61h3.5M167 60.9l3.4 .1M167 60.9h3.4M167 60.8l3.3 .1M167 60.8h3.2M167 60.7l3.2 .1M167 60.7h3.2M167 60.6h3.2M167 60.6h3.1M167 60.5h3.1"/>
<path d="M167 60.4h3M167 60.3l3 .1M167 60.3h3M167 60.2l2.9 .1M167 60.2h2.9M167 60.1h2.9M167 60h2.9M169.9 60.2l.3 .6M170.2 60.8l1.1 .8 .7 .2M171.6 79.3v9.3M171.7 79.2h-4.7M171.7 79.1h-4.7"/>
<path d="M171.8 79h-4.8M171.8 78.9l-.2 .4M171.9 78.8l-4.9 .1M171.9 78.8h-4.9M172 78.7l-5 .1M172 78.7h-5M172.1 78.6l-5.1 .1M172.1 78.6l-.3 .3M172.2 78.6h-5.2M172.3 78.5l-5.3 .1M172.4 71.5v2M172.4 76.6v1.9"/>
<path d="M172.4 73.5l.1 .3M172.4 78.5l-.3 .1M172.4 76.5l-5.4 .1M172.4 76.4l-5.4 .1M172.5 76.3h-5.5M172.5 73.8v2.5M172.5 76.3l-.1 .3M172.5 71.2h-5.5M172.6 71.1h-5.6M172.6 71h-5.6M172.6 70.9h-5.6M172.6 70.8l-5.6 .1"/>
<path d="M172.7 70.8h-5.7M172.7 70.8l-.3 .7M172.7 70.7l-5.7 .1M172.8 70.7h-5.8M172.8 70.6l-5.8 .1M172.9 70.6h-5.9M172.9 61.8h20.3M172.9 70.5l-5.9 .1M173 70.5h-6M173 61.7h20.1M173 70.4l-6 .1M173.1 70.4h-6.1"/>
<path d="M173.1 70.3l-6.1 .1M173.2 70.3h-6.2M173.2 70.3l-.5 .5M173.2 61.7h19.9M173.4 70.2l-6.4 .1M173.4 61.6h19.7M173.5 70.2h-6.5M173.5 61.6h19.6M173.6 61.5h19.5M173.6 70.1h-6.6M173.7 61.4h19.3M173.7 70.1h-6.7"/>
<path d="M173.9 61.3h19.1M173.9 70l-.7 .3M174 61.2h18.9M174.1 61.2h18.8M174.1 61.1h18.8M174.2 61.1h18.7M174.2 61h18.6M174.3 60.9h18.5M174.4 60.9h18.4M174.4 60.8h18.4M174.4 60.8l-1 .8-.7 .2M174.5 60.8h18.3"/>
<path d="M174.5 60.7h18.3M174.6 60.6h18.2M174.6 60.5h18.2M174.6 70l.7 .3 .6 .5 .2 .7M174.6 60.4h18.2M174.7 60.4h18.1M174.7 60.3h18.1M174.8 70.1h2.8M174.8 60.2h18M174.8 60.1h18M174.8 60h18M174.9 70.1h2.7"/>
<path d="M175 70.2h2.6M175.2 70.2h2.4M175.3 70.3h2.3M175.4 70.4h2.2M175.5 70.4h2.1M175.5 70.5h2.1M175.6 70.5h2M175.6 70.6h2M175.7 70.6h1.9M175.7 70.7h1.9M175.8 70.7h1.8M175.8 70.8h1.8"/>
<path d="M175.9 70.8h1.7M175.9 71h1.7M175.9 70.9h1.7M175.9 71.1h1.7M176 71.1h1.6M176 74.6h.1M176 71.2h1.6M176 73.8v.8M176 71.3h1.6M176.1 71.3h1.5M176.1 71.4h1.5M176.1 74.5h-.1"/>
<path d="M176.1 73h1.5M176.1 72.9h1.5M176.1 72.8h1.5M176.1 72.7h1.5M176.1 72.6h1.5M176.1 72.5h1.5M176.1 72.4h1.5M176.1 72.3h1.5M176.1 72.2h1.5M176.1 72.1h1.5M176.1 72h1.5M176.1 71.9h1.5"/>
<path d="M176.1 71.8h1.5M176.1 71.7h1.5M176.1 71.6h1.5M176.1 71.5h1.5M176.1 73.5l-.1 .3M176.1 71.5v2M176.2 74.4h-.2M176.3 74.4h-.3M176.3 74.3h-.3M176.4 74.3h-.4M176.4 74.2h-.4M176.5 74.1l-.5 .1"/>
<path d="M176.5 74.1h-.5M176.6 74l-.6 .1M176.7 74h-.7M176.7 73.9l-.7 .1M176.7 73.9h-.7M176.8 73.8l-.8 .1M176.8 73.8h-.8M176.9 73.7h-.9M177 73.7h-.9M177 73.6h-.9M177.1 73.6h-1M177.1 73.5h-1"/>
<path d="M177.2 73.4l-1.1 .1M177.2 73.4h-1.1M177.3 73.3l-1.2 .1M177.3 73.3h-1.2M177.4 73.2l-1.3 .1M177.4 73.2h-1.3M177.4 64.2v2M177.4 66.2l.2 .3M177.5 73.1l-1.4 .1M177.5 64.1h-10.5M177.5 64h-10.5M177.5 73.1h-1.4"/>
<path d="M177.6 70h-10.6M177.6 63.9h-10.6M177.6 73l-1.6 1.6M177.6 66.5v6.5M177.6 63.8h-10.6M177.7 63.7h-10.7M177.7 63.6l-10.7 .1M177.7 63.6h-10.7M177.7 63.5l-10.7 .1M177.8 63.5h-10.8M177.8 63.4l-10.8 .1M177.9 63.4h-10.9"/>
<path d="M177.9 63.3l-10.9 .1M178 63.3h-11M178 63.2h-11M178.1 63.2h-11.1M178.1 63.1h-11.1M178.2 63.1h-11.2M178.2 63h-11.2M178.4 62.9l-11.4 .1M178.4 62.9h-11.4M178.6 62.8l-11.6 .1M178.7 62.8h-11.7M178.9 62.7l-11.9 .1"/>
<path d="M178.9 62.7l-.6 .3-.6 .5-.3 .7M179.7 62.7l.7 .3 .5 .5 .3 .7M179.8 62.7h20.6v1.2M179.9 62.8h20.5M180.1 62.8h20.3M180.2 62.9h20.2M180.3 62.9h20.1M180.4 63h20M180.5 63.1h19.9M180.6 63.2h19.8M180.7 63.3h19.7M180.8 63.4h19.6"/>
<path d="M180.9 63.5h19.5M181 63.6h19.4M181 63.7h19.4M181 63.8h19.4M181.1 63.9h19.3M181.1 67.7l33.7 .1M181.1 70h33.7M181.1 69.9h33.7M181.1 69.8h33.7M181.1 69.7h33.7M181.1 69.6h33.7M181.1 69.5h33.7"/>
<path d="M181.1 69.4h33.7M181.1 69.3h33.7M181.1 69.2h33.7M181.1 69.1h33.7M181.1 69h33.7M181.1 68.9h33.7M181.1 68.8h33.7M181.1 68.7h33.7M181.1 68.6h33.7M181.1 68.5h33.7M181.1 68.4h33.7M181.1 68.3h33.7"/>
<path d="M181.1 68.2h33.7M181.1 68.1h33.7M181.1 68h33.7M181.1 67.9h33.7M181.1 67.8h33.7M181.1 67.7h20.7M181.1 67.6h20.5M181.1 67.6h20.4M181.1 67.5h20.2M181.1 67.4h20M181.1 67.3h19.9M181.1 67.2l19.9 .1"/>
<path d="M181.1 67.2h19.8M181.1 67.1l19.8 .1M181.1 67.1h19.7M181.1 67l19.6 .1M181.1 67h19.6M181.1 66.9l19.5 .1M181.1 66.9h19.5M181.1 66.8h19.5M181.1 66.8h19.4M181.1 66.7h19.4M181.1 66.6h19.4M181.1 66.5l19.3 .1"/>
<path d="M181.1 66.5h19.3M181.1 66.5v3.7M181.1 70.2h.1M181.1 64h19.3M181.1 66.4h19.3M181.1 64.1h19.2M181.2 66.3h19.1M181.2 64.1h19.1M181.2 66.2h19.1M181.2 66.1h19.1M181.2 66h19.1M181.2 65.9h19.1"/>
<path d="M181.2 65.8h19.1M181.2 65.7h19.1M181.2 65.6h19.1M181.2 65.5h19.1M181.2 65.4h19.1M181.2 65.3h19.1M181.2 65.2h19.1M181.2 65.1h19.1M181.2 65h19.1M181.2 64.9h19.1M181.2 64.8h19.1M181.2 64.7h19.1"/>
<path d="M181.2 64.6h19.1M181.2 64.5h19.1M181.2 64.4h19.1M181.2 64.3h19.1M181.2 64.2h19.1M181.2 64.2v2l-.1 .3M181.3 70.1h-.2M181.5 70l-.4 .2M182.2 70l.7 .3M182.4 70.1h2.1M182.5 70.1h1.9M182.6 70.2h1.7"/>
<path d="M182.8 70.2h1.3M182.9 70.3h1.1M182.9 70.3l.5 .4 .6-.4M183 70.3h.9M183 70.4h.9M183.1 70.4h.7M183.1 70.5h.7M183.2 70.5h.5M183.2 70.6h.5M183.3 70.6h.3M183.3 70.7h.3M184.7 70l-.7 .3"/>
<path d="M185.4 70l.7 .3M185.6 70.1h29.2M185.7 70.1h29.1M185.8 70.2h29M185.9 70.2h28.9M186.1 75.3h28.7M186.1 75.2h28.7M186.1 75.1h28.7M186.1 75h28.7M186.1 74.9h28.7M186.1 74.8h28.7M186.1 75.3v.1"/>
<path d="M186.1 74.8v.5M186.1 75.4h28.7M186.1 70.3h28.7M186.1 70.3l.5 .4h10.2M186.1 75.4l.5 .4M186.2 75.4h28.6M186.2 74.7h28.6M186.2 75.5h28.6M186.2 70.4h28.6M186.3 75.5h28.5M186.3 74.6h28.5M186.3 75.6h28.5"/>
<path d="M186.3 74.5h28.5M186.3 70.5h28.5M186.4 70.5h28.4M186.4 75.6h28.4M186.4 74.5h28.4M186.4 75.7h28.4M186.4 74.4h28.4M186.4 70.6h28.4M186.5 70.6h28.3M186.5 75.7h10.5M186.5 74.4h10.5M186.5 75.8h10.3"/>
<path d="M186.5 74.3h10.4M186.5 70.7h10.4M188.9 70.7v.1M189.7 70.7v.1M192.8 60v.9M192.8 60.9l.3 .8M193.1 61.7l.7 .7 .8 .3M197 74.4l-.3-.1h-10.1l-.5 .5M197 75.7l-.3 .1M197 70.6l-.3 .2M197.8 75.7h.1M198.1 62.7h1.8"/>
<path d="M199.1 75.7l.6 .3M199.1 70.6l.6 .3M199.1 74.4h15.7M199.1 75.7h15.7M199.2 75.8h15.6M199.2 74.3h15.6M199.2 70.7h15.6M199.3 70.7h15.5M199.4 74.3h15.4M199.4 75.8h15.4M199.5 75.9h15.3M199.5 74.2h15.3"/>
<path d="M199.5 70.8h15.3M199.6 70.8h15.2M199.6 75.9h15.2M199.6 74.2h15.2M199.7 74.1h15.1M199.7 76h15.1M199.7 70.9h15.1M199.7 76l.6 .5M199.7 70.9l.6 .5M199.8 71h15M199.8 76.1h15M199.8 74.1h15"/>
<path d="M199.9 76.1h14.9M199.9 74h14.9M199.9 71h14.9M199.9 71.1h14.9M199.9 76.2h14.9M200 76.2h14.8M200 73.9h14.8M200 71.1h14.8M200 71.2h14.8M200 76.3h14.8M200.1 76.3h14.7M200.1 73.8h14.7"/>
<path d="M200.1 71.2h14.7M200.1 71.3h14.7M200.1 76.4h14.7M200.1 73.7h14.7M200.2 76.4h14.6M200.2 73.7h14.6M200.2 71.3h14.6M200.2 71.4h14.6M200.2 76.5h14.6M200.2 73.6h14.6M200.3 76.5h14.5M200.3 73.6h14.5"/>
<path d="M200.3 71.4h14.5M200.3 76.5l.3 .7M200.3 73.6l-.6 .5-.6 .3M200.3 71.4l.3 .7M200.3 76.6h14.5M200.3 73.5h14.5M200.3 71.5h14.5M200.3 64.2v2M200.3 66.2l.3 .7 .5 .6 .7 .2M200.3 73.4h14.5M200.3 71.6h14.5M200.4 76.7h14.4"/>
<path d="M200.4 73.4h14.4M200.4 71.6h14.4M200.4 71.7h14.4M200.4 78.4h14.4M200.4 76.8h14.4M200.4 73.3h14.4M200.4 71.8h14.4M200.4 63.9l-.1 .3M200.4 78.3h14.4M200.4 76.9h14.4M200.4 73.2h14.4M200.5 76.9h14.3"/>
<path d="M200.5 73.1h14.3M200.5 71.9h14.3M200.5 78.2h14.3M200.5 77h14.3M200.5 78.1h14.3M200.5 73h14.3M200.5 72h14.3M200.5 77.1h14.3M200.6 78h14.2M200.6 77.2h14.2M200.6 72.9h14.2M200.6 72.1h14.2"/>
<path d="M200.6 78l-.2 .5h14.4M200.6 77.9h14.2M200.6 77.8h14.2M200.6 77.7h14.2M200.6 77.6h14.2M200.6 77.5h14.2M200.6 77.4h14.2M200.6 77.3h14.2M200.6 72.8h14.2M200.6 72.7h14.2M200.6 72.6h14.2M200.6 72.5h14.2"/>
<path d="M200.6 72.4h14.2M200.6 72.3h14.2M200.6 72.2h14.2M200.6 72.1v.8M200.6 77.2v.8M200.6 72.9l-.3 .7M202.6 67.7h12.2M202.8 67.6h12M202.9 67.6h11.9M203 67.5h11.8M203.1 67.5h11.7M203.3 67.4h11.5"/>
<path d="M203.4 67.3h11.4M203.5 67.2h11.3M203.6 67.1h11.2M203.7 67h11.1M203.8 66.9l-.6 .6-.6 .2M203.8 66.9h11M203.8 66.8h11M203.9 66.7h10.9M203.9 66.6h10.9M203.9 62.7h10.9M203.9 66.5h10.9M203.9 63.9h10.9"/>
<path d="M203.9 63.8h10.9M203.9 63.7h10.9M203.9 63.6h10.9M203.9 63.5h10.9M203.9 63.4h10.9M203.9 63.3h10.9M203.9 63.2h10.9M203.9 63.1h10.9M203.9 63h10.9M203.9 62.9h10.9M203.9 62.8h10.9M203.9 62.6h10.9"/>
<path d="M203.9 62.5h10.9M203.9 63.9l.2 .3M203.9 62.5v1.4M204 66.5h10.8M204 64h10.8M204 66.4h10.8M204 64.1h10.8M204 66.3h10.8M204 62.5h10.8M204.1 66.2h10.7M204.1 66.1h10.7M204.1 66h10.7"/>
<path d="M204.1 65.9h10.7M204.1 65.8h10.7M204.1 65.7h10.7M204.1 65.6h10.7M204.1 65.5h10.7M204.1 65.4h10.7M204.1 65.3h10.7M204.1 65.2h10.7M204.1 65.1h10.7M204.1 65h10.7M204.1 64.9h10.7M204.1 64.8h10.7"/>
<path d="M204.1 64.7h10.7M204.1 64.6h10.7M204.1 64.5h10.7M204.1 64.4h10.7M204.1 64.3h10.7M204.1 64.2h10.7M204.1 66.2l-.3 .7M204.1 64.2v2M204.2 62.4h10.6M204.3 62.3h10.5M204.4 62.2h10.4M204.5 62.1h10.3"/>
<path d="M204.6 62h10.2M204.7 61.9h10.1M204.8 61.8h10M204.9 61.7l4.1 .1M204.9 61.7l-1 .8M204.9 61.7h3.9M204.9 61.7h3.7M204.9 61.6h3.5M204.9 61.6h3.4M205 61.5h3.3M205 61.4h3.2M205 61.4h3.1"/>
<path d="M205 61.3h3M205 61.3h2.9M205.1 61.2h2.7M205.1 61.1h2.6M205.2 61h2.4M205.2 60.9h2.3M205.2 60.8l2.3 .1M205.2 60.8h2.2M205.2 60.7l2.2 .1M205.2 60.7h2.1M205.2 60.6l2.1 .1M205.2 60.6h2.1"/>
<path d="M205.2 60.5h2M205.2 60.4h2M205.2 60.3l1.9 .1M205.2 60.3h1.9M205.2 60.2l1.9 .1M205.2 60.2h1.9M205.2 60.1l1.8 .1M205.2 60.1h1.8M205.2 60l1.8 .1M205.2 60.9l-.3 .8M205.2 60v.9M207 60.2l.9 1.1"/>
<path d="M207.9 61.3l1.2 .5M209.4 78.5l.3 .1M209.4 78.5h5.4M209.5 78.5h5.3M209.7 78.6h5.1M209.7 78.6l.5 .7M209.8 78.7h5M209.9 78.8h4.9M210 78.8h4.8M210 78.9h4.8M210 61.8h4.8M210 79h4.8"/>
<path d="M210.1 79.1h4.7M210.1 79h4.7M210.1 79.2h4.7M210.1 61.7h4.7M210.2 79.2h4.6M210.2 80h4.6M210.2 79.9h4.6M210.2 79.8h4.6M210.2 79.7h4.6M210.2 79.6h4.6M210.2 79.5h4.6M210.2 79.4h4.6"/>
<path d="M210.2 79.3h4.6M210.2 79.3v9.3M210.4 61.7h4.4M210.5 61.6h4.3M210.6 61.6h4.2M210.7 61.5h4.1M210.8 61.4h4M210.9 61.4h3.9M211 61.3h3.8M211.1 61.3h3.7M211.1 61.2h3.7M211.2 61.2h3.6"/>
<path d="M211.2 61.1h3.6M211.3 61.1h3.5M211.3 61h3.5M211.4 61h3.4M211.5 60.9h3.3M211.6 60.8h3.2M211.6 60.7h3.2M211.7 60.6h3.1M211.7 60.5h3.1M211.8 60.5h3M211.8 60.4h3M211.9 60.3h2.9"/>
<path d="M211.9 60.2h2.9M211.9 60.1h2.9M212 60.1h2.8M214.8 70h-33.7M67.4 99h9M67.4 99.9h9M67.4 99.8h9M67.4 99.7h9M67.4 99.6h9M67.4 99.5h9M67.4 99.4h9M67.4 99.3h9"/>
<path d="M67.4 99.2h9M67.4 99.1h9M67.4 98.9h4.9M67.4 98.8l4.6 .1M67.4 98.8h4.5M67.4 98.7l4.2 .1M67.4 98.7h4.2M67.4 98.6l4.1 .1M67.4 98.6h4M67.4 98.5l3.9 .1M67.4 98.5h3.8M67.4 98.4h3.7"/>
<path d="M67.4 98.4h3.6M67.4 98.3h3.6M67.4 98.3h3.5M67.4 98.2h3.5M67.4 98.1l3.4 .1M67.4 98.1h3.4M67.4 98l3.3 .1M67.4 98h3.3M67.4 97.9l3.2 .1M67.4 97.9h3.1M67.4 97.8h3.1M67.4 97.7h3.1"/>
<path d="M67.4 97.7h3M67.4 97.6h3M67.4 97.5h2.9M67.4 97.4h2.9M67.4 97.3l2.9 .1M67.4 97.3h2.8M67.4 97.2l2.8 .1M67.4 97.2h2.8M67.4 97.1h2.8M67.4 97h2.7M67.4 96.9l2.7 .1M67.4 96.9h2.7"/>
<path d="M67.4 96.8h2.7M67.4 96.7h2.7M67.4 96.7h2.6M67.4 96.6h2.6M67.4 96.5h2.6M67.4 96.4h2.6M67.4 96.3h2.6M67.4 96.2h2.6M67.4 96.1h2.6M67.4 96h2.6M67.4 95.9h2.6M67.4 95.9h2.7"/>
<path d="M67.4 95.8h2.7M67.4 95.7h2.7M67.4 95.6h2.7M67.4 95.5h2.7M67.4 95.4h2.8M67.4 95.2h2.9M67.4 95.1h3M67.4 95h3M67.4 94.8h3.1M67.4 93.6h9M67.4 93.5h9M67.4 93.4h9"/>
<path d="M67.4 93.3h9M67.4 93.2h9M67.4 93.2h8.9M67.4 93.1l8.9 .1M67.4 93.1h8.8M67.4 93h8.8M67.4 93h8.7M67.4 92.9h8.7M67.4 92.9h8.6M67.4 92.8h8.6M67.4 92.8h8.5M67.4 92.7h8.5"/>
<path d="M67.4 92.6l8.4 .1M67.4 92.6h8.4M67.4 92.5l8.3 .1M67.4 92.5h8.3M67.4 92.4l8.2 .1M67.4 92.4h8.2M67.4 92.3l8.1 .1M67.4 92.3h8.1M67.4 92.2h8M67.4 92.2h7.9M67.4 92.1h7.9M67.4 92.1h7.8"/>
<path d="M67.4 92h7.8M67.4 91.9l7.7 .1M67.4 91.9h7.7M67.4 91.8l7.6 .1M67.4 91.8h7.6M67.4 91.7l7.5 .1M67.4 91.7h7.5M67.4 91.6l7.4 .1M67.4 91.6h7.4M67.4 91.5h7.3M67.4 91.4h7.2M67.4 91.4h7.1"/>
<path d="M67.4 91.3h7.1M67.4 91.2l7 .1M67.4 91.2h7M67.4 91.1l6.9 .1M67.4 91.1h6.9M67.4 91l6.8 .1M67.4 91h6.8M67.4 90.9l6.7 .1M67.4 90.9h6.7M67.4 90.8l6.6 .1M67.4 90.8h6.6M67.4 90.7l6.5 .1"/>
<path d="M67.4 90.7h6.5M67.4 90.6l6.4 .1M67.4 90.6h6.3M67.4 90.5l6.3 .1M67.4 90.5h6.2M67.4 90.4h6.2M67.4 90.4h6.1M67.4 90.3h6.1M67.4 90.3h6M67.4 90.2h6M67.4 90.1l5.9 .1M67.4 90.1h5.9"/>
<path d="M67.4 90l5.8 .1M67.4 90h5.8M67.4 89.9l5.7 .1M67.4 89.9h5.7M67.4 89.8l5.6 .1M67.4 89.8h5.6M67.4 89.7h5.5M67.4 89.6h5.4M67.4 89.6h5.3M67.4 89.5h5.3M67.4 89.5h5.2M67.4 89.4h5.2"/>
<path d="M67.4 89.3l5.1 .1M67.4 89.3h5.1M67.4 89.2l5 .1M67.4 89.2h5M67.4 89.1l4.9 .1M67.4 89.1h4.9M67.4 89l4.8 .1M67.4 89h4.8M67.4 88.9l4.7 .1M67.4 88.9h4.7M67.4 88.8l4.7 .1M67.4 88.8h4.7"/>
<path d="M67.4 88.7l4.6 .1M67.4 88.7h4.6M67.4 88.6h4.6M67.4 88.5h4.6M67.4 88.4h4.6M67.4 88.3h4.6M67.4 88.2h4.6M67.4 88.1h4.6M67.4 88h4.6M67.4 87.9h4.6M67.4 87.8h4.6M67.4 87.7h4.6"/>
<path d="M67.4 87.6h4.6M67.4 87.5h4.6M67.4 87.4h4.6M67.4 87.3h4.6M67.4 87.2h4.6M67.4 87.1h4.6M67.4 87h4.6M67.4 86.9h4.6M67.4 86.8h4.6M67.4 86.7h4.6M67.4 86.6h4.6M67.4 86.5h4.6"/>
<path d="M67.4 86.4h4.6M67.4 86.3h4.6M67.4 86.2h4.6M67.4 86.1h4.6M67.4 86h4.6M67.4 85.9h4.6M67.4 85.8h4.6M67.4 85.7h4.6M67.4 85.6h4.6M67.4 85.5h4.6M67.4 85.4h4.6M67.4 85.3h4.6"/>
<path d="M67.4 85.2h4.6M67.4 85.1h4.6M67.4 85h4.6M67.4 84.9h4.6M67.4 84.8h4.6M67.4 84.7h4.6M67.4 84.6h4.6M67.4 84.5h4.6M67.4 84.4h4.6M67.4 84.3h4.6M67.4 84.2h4.6M67.4 84.1h4.6"/>
<path d="M67.4 84h4.6M67.4 83.9h4.6M67.4 83.8h4.6M67.4 83.7h4.6M67.4 83.6h4.6M67.4 83.5h4.6M67.4 83.4h4.6M67.4 83.3h4.6M67.4 83.2h4.6M67.4 83.1h4.6M67.4 83h4.6M67.4 82.9h4.6"/>
<path d="M67.4 82.8h4.6M67.4 82.7h4.6M67.4 82.6h4.6M67.4 82.5h4.6M67.4 82.4h4.6M67.4 82.3h4.6M67.4 82.2h4.6M67.4 82.1h4.6M67.4 82h4.6M67.4 81.9h4.6M67.4 81.8h4.6M67.4 81.7h4.6"/>
<path d="M67.4 81.6h4.6M67.4 81.5h4.6M67.4 81.4h4.6M67.4 81.3h4.6M67.4 81.2h4.6M67.4 81.1h4.6M67.4 81h4.6M67.4 80.9h4.6M67.4 80.8h4.6M67.4 80.7h4.6M67.4 80.6h4.6M67.4 80.5h4.6"/>
<path d="M67.4 80.4h4.6M67.4 80.3h4.6M67.4 80.2h4.6M67.4 80.1h4.6M70 96v.7M70 96.7l.2 .6M70.1 95.8h-2.7M70.1 95.7h-2.7M70.2 95.5h-2.8M70.2 95.4l-2.8 .1M70.2 95.3l-.2 .7M70.2 97.3l.9 1.1"/>
<path d="M70.2 95.3l-2.8 .1M70.2 95.3h-2.8M70.3 95.2l-2.9 .1M70.3 95.1h-2.9M70.4 95l-3 .1M70.4 94.9h-3M70.5 94.9h-3.1M70.5 94.8h-3.1M70.6 94.7l-.4 .6M70.6 94.7h-3.2M70.7 94.6h-3.3M70.8 94.5h-3.4"/>
<path d="M70.8 94.4l-3.4 .1M70.9 94.4h-3.5M70.9 94.3l-3.5 .1M71 94.3h-3.6M71 94.2l-3.6 .1M71.1 98.4l.5 .4M71.1 94.2h-3.7M71.2 94.1h-3.8M71.3 94.1h-3.9M71.4 94h-4M71.5 94h-4.1M71.6 93.9h-4.2"/>
<path d="M71.6 98.8l.7 .2M71.8 93.9h-4.4M71.9 93.8h-4.5M72 88.6l.1 .4M72.1 89l4.3 4.3M72.1 93.7l-4.7 .1M72.3 93.7l-.7 .2-1 .8M73 93.7l.7 .2 1.1 .8M73.1 98.9h3.3M73.2 93.7h3.2M73.3 98.9h3.1M73.4 93.8h3"/>
<path d="M73.4 98.8h3M73.6 93.9h2.8M73.7 98.8l-.7 .2M73.7 98.8h2.7M73.7 93.9h2.7M73.8 98.7h2.6M73.8 94h2.6M73.9 98.7h2.5M73.9 94h2.5M74 98.6h2.4M74 94.1h2.4M74.1 94.1h2.3"/>
<path d="M74.2 98.5h2.2M74.2 94.2h2.2M74.2 98.4h2.2M74.3 94.2h2.1M74.3 98.4h2.1M74.3 94.3h2.1M74.4 98.3h2M74.4 94.3h2M74.4 94.4h2M74.5 98.2h1.9M74.5 94.4h1.9M74.5 94.5h1.9"/>
<path d="M74.6 98.1h1.8M74.6 94.6h1.8M74.7 94.6h1.7M74.7 98h1.7M74.7 94.7h1.7M74.8 97.9l-1.1 .9M74.8 94.7l.3 .6M74.8 94.7h1.6M74.8 97.9h1.6M74.8 94.8h1.6M74.8 97.8h1.6M74.8 94.9h1.6"/>
<path d="M74.9 97.7h1.5M74.9 94.9h1.5M74.9 97.6h1.5M74.9 95h1.5M75 97.6h1.4M75 95h1.4M75 95.1h1.4M75 97.5h1.4M75 95.2h1.4M75.1 97.4h1.3M75.1 95.2h1.3M75.1 95.3h1.3"/>
<path d="M75.1 95.3l.2 .7M75.1 97.3h1.3M75.1 97.2h1.3M75.1 95.4h1.3M75.2 97.1h1.2M75.2 95.5h1.2M75.2 97h1.2M75.2 95.6h1.2M75.2 95.7h1.2M75.2 96.9h1.2M75.2 95.8h1.2M75.2 96.8h1.2"/>
<path d="M75.3 96.7h1.1M75.3 95.9h1.1M75.3 96v.7M75.3 96.7l-.5 1.2M75.3 96.6h1.1M75.3 96.5h1.1M75.3 96.4h1.1M75.3 96.3h1.1M75.3 96.2h1.1M75.3 96.1h1.1M75.3 96h1.1M76.4 93.3v8.3h-9v-47.7h47.7v47.7h-9v-8.3"/>
<path d="M76.4 93.7h-9M106.1 99h9M106.1 99.9h9M106.1 99.8h9M106.1 99.7h9M106.1 99.6h9M106.1 99.5h9M106.1 99.4h9M106.1 99.3h9M106.1 99.2h9M106.1 99.1h9M106.1 98.9h3.3"/>
<path d="M106.1 98.8l3.1 .1M106.1 98.8h2.9M106.1 98.7l2.7 .1M106.1 98.7h2.6M106.1 98.6l2.5 .1M106.1 98.6h2.4M106.1 98.5l2.3 .1M106.1 98.5h2.2M106.1 98.4h2.1M106.1 98.3h2M106.1 98.3h1.9M106.1 98.2h1.9"/>
<path d="M106.1 98.1l1.8 .1M106.1 98.1h1.8M106.1 98l1.7 .1M106.1 98h1.7M106.1 97.9h1.6M106.1 97.8l1.6 .1M106.1 97.8h1.5M106.1 97.7h1.5M106.1 97.6h1.4M106.1 97.5h1.4M106.1 97.5h1.3M106.1 97.4h1.3"/>
<path d="M106.1 97.3l1.3 .1M106.1 97.3h1.3M106.1 97.2h1.2M106.1 97.1l1.2 .1M106.1 97.1h1.2M106.1 97l1.2 .1M106.1 97h1.2M106.1 96.9h1.2M106.1 96.9h1.1M106.1 96.8h1.1M106.1 96.7l1.1 .1M106.1 96.7h1.1"/>
<path d="M106.1 96.6h1.1M106.1 96.5h1.1M106.1 96.4h1.1M106.1 96.3h1.1M106.1 96.2h1.1M106.1 96.1h1.1M106.1 96h1.1M106.1 95.9h1.1M106.1 95.8h1.1M106.1 95.7h1.2M106.1 95.6h1.2M106.1 95.5h1.2"/>
<path d="M106.1 95.4h1.2M106.1 95.3h1.3M106.1 95.1h1.4M106.1 94.4h1.9M106.1 93.6h9M106.1 93.5h9M106.1 93.4h9M106.1 93.3h9M106.1 93.2h9M106.2 93.2h8.9M106.2 93.1h8.9M106.3 93h8.8"/>
<path d="M106.4 92.9h8.7M106.5 92.8h8.6M106.6 92.8h8.5M106.6 92.7h8.5M106.7 92.6h8.4M106.8 92.5h8.3M106.9 92.5h8.2M106.9 92.4h8.2M107 92.4h8.1M107 92.3h8.1M107.1 92.2h8M107.2 96v.7"/>
<path d="M107.2 96.7l.5 1.2M107.2 92.1h7.9M107.2 95.9h-1.1M107.3 92.1h7.8M107.3 92h7.8M107.3 95.5l-1.2 .1M107.4 95.3l-.2 .7M107.4 95.2h-1.3M107.4 91.9h7.7M107.5 95.1h-1.4M107.5 91.8h7.6M107.5 95h-1.4"/>
<path d="M107.6 91.8h7.5M107.6 94.9l-1.5 .1M107.6 91.7h7.5M107.6 94.9h-1.5M107.7 94.8h-1.6M107.7 91.7h7.4M107.7 94.7l-.3 .6M107.7 97.9l1.1 .9M107.7 94.7h-1.6M107.7 91.6h7.4M107.8 94.7h-1.7M107.8 91.5h7.3"/>
<path d="M107.8 94.6h-1.7M107.9 94.6h-1.8M107.9 91.4h7.2M107.9 94.5h-1.8M108 91.3h7.1M108 94.4h-1.9M108.1 94.3l-2 .1M108.1 91.2h7M108.1 94.3h-2M108.2 94.2l-2.1 .1M108.2 91.1h6.9M108.3 94.2h-2.2"/>
<path d="M108.3 91h6.8M108.4 94.1h-2.3M108.4 91h6.7M108.4 90.9h6.7M108.5 94.1h-2.4M108.5 90.9h6.6M108.5 90.8h6.6M108.5 94h-2.4M108.6 90.7h6.5M108.6 94h-2.5M108.7 90.6h6.4M108.7 93.9h-2.6"/>
<path d="M108.8 90.6h6.3M108.8 98.8l.7 .2M108.8 90.5h6.3M108.9 90.4h6.2M108.9 93.9h-2.8M109 90.3h6.1M109 93.8h-2.9M109.1 90.3h6M109.1 90.2h6M109.2 90.2h5.9M109.2 90.1h5.9M109.3 93.7l-3.2 .1"/>
<path d="M109.3 90h5.8M109.4 89.9h5.7M109.5 93.7l-1.3 .5-.5 .5M109.5 89.9h5.6M109.5 89.8h5.6M109.6 89.7h5.5M109.7 89.6h5.4M109.8 89.5h5.3M109.9 89.4h5.2M110 89.3h5.1M110.1 89.2h5M110.2 93.7l.6 .2 1.1 .8"/>
<path d="M110.2 98.9h4.9M110.2 89.1h4.9M110.3 89h4.8M110.3 93.7h4.8M110.4 89l-4.3 4.3M110.4 88.9h4.7M110.4 88.8h4.7M110.4 98.9h4.7M110.4 88.7h4.7M110.5 88.7h4.6M110.5 88.6h4.6M110.5 88.6l-.1 .4"/>
<path d="M110.5 88.5h4.6M110.5 88.4h4.6M110.5 88.3h4.6M110.5 88.2h4.6M110.5 88.1h4.6M110.5 88h4.6M110.5 87.9h4.6M110.5 87.8h4.6M110.5 87.7h4.6M110.5 87.6h4.6M110.5 87.5h4.6M110.5 87.4h4.6"/>
<path d="M110.5 87.3h4.6M110.5 87.2h4.6M110.5 87.1h4.6M110.5 87h4.6M110.5 86.9h4.6M110.5 86.8h4.6M110.5 86.7h4.6M110.5 86.6h4.6M110.5 86.5h4.6M110.5 86.4h4.6M110.5 86.3h4.6M110.5 86.2h4.6"/>
<path d="M110.5 86.1h4.6M110.5 86h4.6M110.5 85.9h4.6M110.5 85.8h4.6M110.5 85.7h4.6M110.5 85.6h4.6M110.5 85.5h4.6M110.5 85.4h4.6M110.5 85.3h4.6M110.5 85.2h4.6M110.5 85.1h4.6M110.5 85h4.6"/>
<path d="M110.5 84.9h4.6M110.5 84.8h4.6M110.5 84.7h4.6M110.5 84.6h4.6M110.5 84.5h4.6M110.5 84.4h4.6M110.5 84.3h4.6M110.5 84.2h4.6M110.5 84.1h4.6M110.5 84h4.6M110.5 83.9h4.6M110.5 83.8h4.6"/>
<path d="M110.5 83.7h4.6M110.5 83.6h4.6M110.5 83.5h4.6M110.5 83.4h4.6M110.5 83.3h4.6M110.5 83.2h4.6M110.5 83.1h4.6M110.5 83h4.6M110.5 82.9h4.6M110.5 82.8h4.6M110.5 82.7h4.6M110.5 82.6h4.6"/>
<path d="M110.5 82.5h4.6M110.5 82.4h4.6M110.5 82.3h4.6M110.5 82.2h4.6M110.5 82.1h4.6M110.5 82h4.6M110.5 81.9h4.6M110.5 81.8h4.6M110.5 81.7h4.6M110.5 81.6h4.6M110.5 81.5h4.6M110.5 81.4h4.6"/>
<path d="M110.5 81.3h4.6M110.5 81.2h4.6M110.5 81.1h4.6M110.5 81h4.6M110.5 80.9h4.6M110.5 80.8h4.6M110.5 80.7h4.6M110.5 80.6h4.6M110.5 80.5h4.6M110.5 80.4h4.6M110.5 80.3h4.6M110.5 80.2h4.6"/>
<path d="M110.5 80.1h4.6M110.6 98.8h4.5M110.6 93.8h4.5M110.7 93.9h4.4M110.8 98.8h4.3M110.8 98.8l-.6 .2M110.9 93.9h4.2M110.9 98.7h4.2M111 94h4.1M111 98.7h4.1M111.1 94h4M111.1 98.6h4"/>
<path d="M111.1 94.1h4M111.2 98.6h3.9M111.3 94.1h3.8M111.3 98.5h3.8M111.3 94.2h3.8M111.4 98.4h3.7M111.4 94.2h3.7M111.5 94.3h3.6M111.5 98.3h3.6M111.6 98.3h3.5M111.6 94.4h3.5M111.6 98.2h3.5"/>
<path d="M111.7 98.2h3.4M111.7 94.5h3.4M111.7 98.1h3.4M111.7 94.6h3.4M111.8 98.1h3.3M111.8 94.6h3.3M111.8 98h3.3M111.9 94.7h3.2M111.9 97.9h3.2M111.9 94.7l.3 .6M111.9 97.9l-1.1 .9M111.9 94.8h3.2"/>
<path d="M112 97.9h3.1M112 94.8h3.1M112 97.8h3.1M112 94.9h3.1M112 97.7h3.1M112.1 95h3M112.1 97.6h3M112.1 95.1h3M112.1 97.5h3M112.2 97.5h2.9M112.2 95.2h2.9M112.2 97.4h2.9"/>
<path d="M112.2 95.3l.2 .7M112.2 95.3h2.9M112.3 97.3h2.8M112.3 97.2h2.8M112.3 95.4h2.8M112.3 95.3h2.8M112.3 97.1h2.8M112.3 95.5h2.8M112.3 97h2.8M112.3 95.6h2.8M112.4 97h2.7M112.4 96.9h2.7"/>
<path d="M112.4 95.7h2.7M112.4 95.8h2.7M112.4 96.8h2.7M112.4 95.9h2.7M112.4 96.7h2.7M112.4 96v.7M112.4 96.7l-.5 1.2M112.4 96.6h2.7M112.4 96.5h2.7M112.4 96.4h2.7M112.4 96.3h2.7M112.4 96.2h2.7"/>
<path d="M112.4 96.1h2.7M112.4 96h2.7M115.1 93.7h-9M117.2 99h9M117.2 99.9h9M117.2 99.8h9M117.2 99.7h9M117.2 99.6h9M117.2 99.5h9M117.2 99.4h9M117.2 99.3h9M117.2 99.2h9"/>
<path d="M117.2 99.1h9M117.2 98.9h4.9M117.2 98.8l4.7 .1M117.2 98.8h4.5M117.2 98.7l4.3 .1M117.2 98.7h4.2M117.2 98.6l4.1 .1M117.2 98.6h4M117.2 98.5l3.9 .1M117.2 98.5h3.8M117.2 98.4h3.7M117.2 98.3h3.6"/>
<path d="M117.2 98.3h3.5M117.2 98.2h3.5M117.2 98.1l3.4 .1M117.2 98.1h3.4M117.2 98l3.3 .1M117.2 98h3.3M117.2 97.9h3.2M117.2 97.8l3.2 .1M117.2 97.8h3.1M117.2 97.7h3.1M117.2 97.6h3M117.2 97.5h3"/>
<path d="M117.2 97.5h2.9M117.2 97.4h2.9M117.2 97.3l2.9 .1M117.2 97.3h2.9M117.2 97.2h2.8M117.2 97.1l2.8 .1M117.2 97.1h2.8M117.2 97h2.8M117.2 96.9h2.8M117.2 96.9h2.7M117.2 96.8h2.7M117.2 96.7h2.7"/>
<path d="M117.2 96.6h2.7M117.2 96.5h2.7M117.2 96.4h2.7M117.2 96.3h2.7M117.2 96.2h2.7M117.2 96.1h2.7M117.2 96h2.7M117.2 95.9h2.7M117.2 95.8h2.7M117.2 95.7h2.8M117.2 95.6h2.8M117.2 95.5h2.8"/>
<path d="M117.2 95.4h2.8M117.2 95.3h2.9M117.2 94.8h3.2M117.2 94.4h3.5M117.2 93.6h9M117.2 93.5h9M117.2 93.4h9M117.2 93.3h9M117.2 93.2h9M117.2 93.1l8.9 .1M117.2 93.1h8.9M117.2 93h8.8"/>
<path d="M117.2 92.9h8.7M117.2 92.8h8.6M117.2 92.7h8.5M117.2 92.6l8.5 .1M117.2 92.6h8.4M117.2 92.5h8.3M117.2 92.4l8.2 .1M117.2 92.4h8.2M117.2 92.3l8.1 .1M117.2 92.3h8.1M117.2 92.2h8M117.2 92.1h7.9"/>
<path d="M117.2 92h7.8M117.2 91.9l7.8 .1M117.2 91.9h7.7M117.2 91.8h7.6M117.2 91.7l7.5 .1M117.2 91.7h7.5M117.2 91.6l7.5 .1M117.2 91.6h7.4M117.2 91.5h7.3M117.2 91.4h7.2M117.2 91.3h7.1M117.2 91.2l7.1 .1"/>
<path d="M117.2 91.2h7M117.2 91.1l7 .1M117.2 91.1h6.9M117.2 91l6.9 .1M117.2 91h6.8M117.2 90.9l6.8 .1M117.2 90.9h6.7M117.2 90.8l6.6 .1M117.2 90.8h6.6M117.2 90.7l6.6 .1M117.2 90.7h6.5M117.2 90.6h6.4"/>
<path d="M117.2 90.5l6.3 .1M117.2 90.5h6.3M117.2 90.4h6.2M117.2 90.3h6.1M117.2 90.2h6M117.2 90.1l5.9 .1M117.2 90.1h5.9M117.2 90l5.9 .1M117.2 90h5.8M117.2 89.9h5.7M117.2 89.8l5.6 .1M117.2 89.8h5.6"/>
<path d="M117.2 89.7h5.5M117.2 89.6h5.4M117.2 89.5h5.3M117.2 89.4h5.2M117.2 89.3l5.2 .1M117.2 89.3h5.1M117.2 89.2l5.1 .1M117.2 89.2h5M117.2 89.1l5 .1M117.2 89.1h4.9M117.2 89h4.8M117.2 88.9h4.7"/>
<path d="M117.2 88.8h4.7M117.2 88.7h4.7M117.2 88.7h4.6M117.2 88.6h4.6M117.2 88.5h4.6M117.2 88.4h4.6M117.2 88.3h4.6M117.2 88.2h4.6M117.2 88.1h4.6M117.2 88h4.6M117.2 87.9h4.6M117.2 87.8h4.6"/>
<path d="M117.2 87.7h4.6M117.2 87.6h4.6M117.2 87.5h4.6M117.2 87.4h4.6M117.2 87.3h4.6M117.2 87.2h4.6M117.2 87.1h4.6M117.2 87h4.6M117.2 86.9h4.6M117.2 86.8h4.6M117.2 86.7h4.6M117.2 86.6h4.6"/>
<path d="M117.2 86.5h4.6M117.2 86.4h4.6M117.2 86.3h4.6M117.2 86.2h4.6M117.2 86.1h4.6M117.2 86h4.6M117.2 85.9h4.6M117.2 85.8h4.6M117.2 85.7h4.6M117.2 85.6h4.6M117.2 85.5h4.6M117.2 85.4h4.6"/>
<path d="M117.2 85.3h4.6M117.2 85.2h4.6M117.2 85.1h4.6M117.2 85h4.6M117.2 84.9h4.6M117.2 84.8h4.6M117.2 84.7h4.6M117.2 84.6h4.6M117.2 84.5h4.6M117.2 84.4h4.6M117.2 84.3h4.6M117.2 84.2h4.6"/>
<path d="M117.2 84.1h4.6M117.2 84h4.6M117.2 83.9h4.6M117.2 83.8h4.6M117.2 83.7h4.6M117.2 83.6h4.6M117.2 83.5h4.6M117.2 83.4h4.6M117.2 83.3h4.6M117.2 83.2h4.6M117.2 83.1h4.6M117.2 83h4.6"/>
<path d="M117.2 82.9h4.6M117.2 82.8h4.6M117.2 82.7h4.6M117.2 82.6h4.6M117.2 82.5h4.6M117.2 82.4h4.6M117.2 82.3h4.6M117.2 82.2h4.6M117.2 82.1h4.6M117.2 82h4.6M117.2 81.9h4.6M117.2 81.8h4.6"/>
<path d="M117.2 81.7h4.6M117.2 81.6h4.6M117.2 81.5h4.6M117.2 81.4h4.6M117.2 81.3h4.6M117.2 81.2h4.6M117.2 81.1h4.6M117.2 81h4.6M117.2 80.9h4.6M117.2 80.8h4.6M117.2 80.7h4.6M117.2 80.6h4.6"/>
<path d="M117.2 80.5h4.6M117.2 80.4h4.6M117.2 80.3h4.6M117.2 80.2h4.6M117.2 80.1h4.6M119.9 95.9h-2.7M120 95.7h-2.8M120 95.5l-2.8 .1M120 95.4h-2.8M120.1 95.3l-.2 .7 .2 1.3M120.1 97.3l.8 1.1 .6 .4M120.1 95.2h-2.9"/>
<path d="M120.2 95.1h-3M120.2 95l-3 .1M120.2 95h-3M120.3 94.9l-3.1 .1M120.3 94.9h-3.1M120.4 94.8h-3.2M120.4 94.7h-3.2M120.5 94.7h-3.3M120.5 94.6h-3.3M120.6 94.6h-3.4M120.6 94.5h-3.4M120.7 94.4h-3.5"/>
<path d="M120.8 94.3l-3.6 .1M120.8 94.3h-3.6M120.9 94.2l-3.7 .1M121 94.2h-3.8M121.1 94.1h-3.9M121.2 94.1h-4M121.2 94h-4M121.3 94h-4.1M121.4 93.9h-4.2M121.5 98.8l.7 .2M121.6 93.9h-4.4M121.7 93.8h-4.5"/>
<path d="M121.8 88.6l.1 .4M121.9 89l4.3 4.3M122 93.7l-4.8 .1M122.2 93.7a2.54 2.54 0 0 0-2.1 1.6M122.9 93.7a2.54 2.54 0 0 1 2 1.6M122.9 98.9h3.3M123 93.7h3.2M123.1 98.9h3.1M123.3 98.8h2.9M123.3 93.8h2.9M123.4 93.9h2.8M123.5 98.8h2.7"/>
<path d="M123.5 98.8l-.6 .2M123.6 93.9h2.6M123.6 98.7h2.6M123.7 94h2.5M123.7 98.7h2.5M123.8 94h2.4M123.8 98.6h2.4M123.8 94.1h2.4M123.9 98.6h2.3M124 94.1h2.2M124 98.5h2.2M124 94.2h2.2"/>
<path d="M124.1 98.4h2.1M124.1 94.2h2.1M124.2 94.3h2M124.2 98.3h2M124.3 98.3h1.9M124.3 94.4h1.9M124.3 98.2h1.9M124.4 98.2h1.8M124.4 94.5h1.8M124.4 98.1h1.8M124.4 94.6h1.8M124.5 98.1h1.7"/>
<path d="M124.5 94.6h1.7M124.5 98h1.7M124.5 94.7h1.7M124.6 97.9h1.6M124.6 94.7h1.6M124.6 94.8h1.6M124.7 97.9h1.5M124.7 94.8h1.5M124.7 97.8h1.5M124.7 94.9h1.5M124.7 97.7h1.5M124.8 95h1.4"/>
<path d="M124.8 97.6h1.4M124.8 95.1h1.4M124.8 97.5h1.4M124.9 97.5h1.3M124.9 97.4h1.3M124.9 95.2h1.3M124.9 97.3h1.3M124.9 95.3h1.3M124.9 95.3l.2 .7M124.9 97.3l-.8 1.1-.6 .4M125 97.2h1.2M125 95.4h1.2"/>
<path d="M125 95.3h1.2M125 97.1h1.2M125 95.5h1.2M125 97h1.2M125 95.6h1.2M125.1 96.9h1.1M125.1 95.7h1.1M125.1 95.8h1.1M125.1 96.8h1.1M125.1 95.9h1.1M125.1 96.7h1.1M125.1 96.6h1.1"/>
<path d="M125.1 96.5h1.1M125.1 96.4h1.1M125.1 96.3h1.1M125.1 96.2h1.1M125.1 96.1h1.1M125.1 96h1.1M125.1 96l-.2 1.3M126.2 93.3v8.3h-9v-47.7h47.8v47.7h-9.1v-8.3M126.2 93.7h-9M155.9 99h9.1M155.9 99.9h9.1M155.9 99.8h9.1"/>
<path d="M155.9 99.7h9.1M155.9 99.6h9.1M155.9 99.5h9.1M155.9 99.4h9.1M155.9 99.3h9.1M155.9 99.2h9.1M155.9 99.1h9.1M155.9 98.9h3.4M155.9 98.8l3.1 .1M155.9 98.8h3M155.9 98.7l2.7 .1M155.9 98.7h2.6"/>
<path d="M155.9 98.6l2.5 .1M155.9 98.6h2.4M155.9 98.5l2.4 .1M155.9 98.5h2.3M155.9 98.4h2.2M155.9 98.4h2.1M155.9 98.3h2M155.9 98.2h1.9M155.9 98.1l1.9 .1M155.9 98.1h1.8M155.9 98l1.8 .1M155.9 98h1.7"/>
<path d="M155.9 97.9l1.7 .1M155.9 97.9h1.6M155.9 97.8l1.6 .1M155.9 97.8h1.6M155.9 97.7h1.5M155.9 97.6h1.5M155.9 97.5h1.4M155.9 97.4h1.3M155.9 97.3l1.3 .1M155.9 97.3h1.3M155.9 97.2l1.3 .1M155.9 97.2h1.3"/>
<path d="M155.9 97.1l1.3 .1M155.9 97.1h1.2M155.9 97h1.2M155.9 96.9h1.2M155.9 96.8l1.2 .1M155.9 96.8h1.2M155.9 96.7h1.1M155.9 96.6h1.1M155.9 96.5h1.1M155.9 96.4h1.1M155.9 96.3h1.1M155.9 96.2h1.1"/>
<path d="M155.9 96.1h1.1M155.9 96h1.1M155.9 95.9h1.1M155.9 95.8h1.2M155.9 95.7h1.2M155.9 95.5h1.2M155.9 95.4h1.3M155.9 95.3h1.3M155.9 95.1h1.4M155.9 94.9h1.6M155.9 94.8h1.6M155.9 93.6h9.1"/>
<path d="M155.9 93.5h9.1M155.9 93.4h9.1M155.9 93.3h9.1M155.9 93.2h9.1M156 93.2h9M156.1 93.1h8.9M156.1 93h8.9M156.2 93h8.8M156.2 92.9h8.8M156.3 92.9h8.7M156.3 92.8h8.7M156.4 92.8h8.6"/>
<path d="M156.4 92.7h8.6M156.5 92.7h8.5M156.5 92.6h8.5M156.6 92.6h8.4M156.6 92.5h8.4M156.7 92.5h8.3M156.7 92.4h8.3M156.8 92.4h8.2M156.8 92.3h8.2M156.9 92.2h8.1M157 92.2h8M157 92.1h8"/>
<path d="M157 96v.7M157 96.7l.2 .6M157 95.9h-1.1M157.1 95.8h-1.2M157.1 92.1h7.9M157.1 95.6h-1.2M157.1 92h7.9M157.2 95.4l-1.3 .1M157.2 92h7.8M157.2 95.3h-1.3M157.2 95.3l-.2 .7M157.2 97.3l.3 .6 1.1 .9"/>
<path d="M157.2 91.9h7.8M157.2 95.2l-1.3 .1M157.3 95.2h-1.4M157.3 91.9h7.7M157.3 95.1l-1.4 .1M157.3 91.8h7.7M157.4 95l-1.5 .1M157.4 95h-1.5M157.4 91.8h7.6M157.4 94.9l-1.5 .1M157.4 91.7h7.6M157.5 94.8h-1.6"/>
<path d="M157.5 91.7h7.5M157.5 94.7h-1.6M157.5 91.6h7.5M157.5 94.7l-.3 .6M157.6 94.7h-1.7M157.6 91.5h7.4M157.6 94.6h-1.7M157.7 94.6h-1.8M157.7 91.4h7.3M157.8 91.4h7.2M157.8 94.5h-1.9M157.8 94.4l-1.9 .1"/>
<path d="M157.8 91.3h7.2M157.9 94.4h-2M157.9 91.3h7.1M157.9 94.3l-2 .1M157.9 91.2h7.1M158 94.3h-2.1M158 91.2h7M158 94.2l-2.1 .1M158 91.1h7M158.1 91.1h6.9M158.1 94.2h-2.2M158.1 91h6.9"/>
<path d="M158.2 91h6.8M158.2 94.1h-2.3M158.2 90.9h6.8M158.3 90.9h6.7M158.3 94.1h-2.4M158.3 90.8h6.7M158.4 94h-2.5M158.4 90.8h6.6M158.5 90.7h6.5M158.5 94h-2.6M158.6 93.9h-2.7M158.6 90.6h6.4"/>
<path d="M158.6 98.8l.7 .2M158.7 90.5h6.3M158.7 90.4h6.3M158.7 93.9h-2.8M158.8 90.4h6.2M158.8 90.3h6.2M158.9 93.8h-3M158.9 90.3h6.1M158.9 90.2h6.1M159 90.2h6M159 90.1h6M159.1 90.1h5.9"/>
<path d="M159.1 93.7l-3.2 .1M159.1 90h5.9M159.2 90h5.8M159.2 89.9h5.8M159.3 89.9h5.7M159.3 93.7l-.7 .2-1.1 .8M159.3 89.8h5.7M159.4 89.7h5.6M159.5 89.6h5.5M159.6 89.6h5.4M159.6 89.5h5.4M159.7 89.5h5.3"/>
<path d="M159.7 89.4h5.3M159.8 89.4h5.2M159.8 89.3h5.2M159.9 89.3h5.1M159.9 89.2h5.1M160 89.2h5M160 93.7a2.62 2.62 0 0 1 2.1 1.6M160 98.9h5M160 89.1h5M160.1 89.1h4.9M160.1 89h4.9M160.2 93.7h4.8"/>
<path d="M160.2 89h4.8M160.2 89l-4.3 4.3M160.2 88.9h4.8M160.3 98.9h4.7M160.3 88.8h4.7M160.3 88.7h4.7M160.3 88.6h4.7M160.4 88.6h4.6M160.4 88.5h4.6M160.4 88.4h4.6M160.4 88.3h4.6M160.4 88.2h4.6"/>
<path d="M160.4 88.1h4.6M160.4 88h4.6M160.4 87.9h4.6M160.4 87.8h4.6M160.4 87.7h4.6M160.4 87.6h4.6M160.4 87.5h4.6M160.4 87.4h4.6M160.4 87.3h4.6M160.4 87.2h4.6M160.4 87.1h4.6M160.4 87h4.6"/>
<path d="M160.4 86.9h4.6M160.4 86.8h4.6M160.4 86.7h4.6M160.4 86.6h4.6M160.4 86.5h4.6M160.4 86.4h4.6M160.4 86.3h4.6M160.4 86.2h4.6M160.4 86.1h4.6M160.4 86h4.6M160.4 85.9h4.6M160.4 85.8h4.6"/>
<path d="M160.4 85.7h4.6M160.4 85.6h4.6M160.4 85.5h4.6M160.4 85.4h4.6M160.4 85.3h4.6M160.4 85.2h4.6M160.4 85.1h4.6M160.4 85h4.6M160.4 84.9h4.6M160.4 84.8h4.6M160.4 84.7h4.6M160.4 84.6h4.6"/>
<path d="M160.4 84.5h4.6M160.4 84.4h4.6M160.4 84.3h4.6M160.4 84.2h4.6M160.4 84.1h4.6M160.4 84h4.6M160.4 83.9h4.6M160.4 83.8h4.6M160.4 83.7h4.6M160.4 83.6h4.6M160.4 83.5h4.6M160.4 83.4h4.6"/>
<path d="M160.4 83.3h4.6M160.4 83.2h4.6M160.4 83.1h4.6M160.4 83h4.6M160.4 82.9h4.6M160.4 82.8h4.6M160.4 82.7h4.6M160.4 82.6h4.6M160.4 82.5h4.6M160.4 82.4h4.6M160.4 82.3h4.6M160.4 82.2h4.6"/>
<path d="M160.4 82.1h4.6M160.4 82h4.6M160.4 81.9h4.6M160.4 81.8h4.6M160.4 81.7h4.6M160.4 81.6h4.6M160.4 81.5h4.6M160.4 81.4h4.6M160.4 81.3h4.6M160.4 81.2h4.6M160.4 81.1h4.6M160.4 81h4.6"/>
<path d="M160.4 80.9h4.6M160.4 80.8h4.6M160.4 80.7h4.6M160.4 80.6h4.6M160.4 80.5h4.6M160.4 80.4h4.6M160.4 80.3h4.6M160.4 80.2h4.6M160.4 80.1h4.6M160.4 88.6l-.2 .4M160.4 93.8h4.6M160.4 98.8h4.6"/>
<path d="M160.5 93.9h4.5M160.7 98.8h4.3M160.7 98.8l-.7 .2M160.7 93.9h4.3M160.7 98.7h4.3M160.8 94h4.2M160.8 98.7h4.2M160.9 94h4.1M161 98.6h4M161 94.1h4M161.1 94.1h3.9M161.1 98.5h3.9"/>
<path d="M161.2 94.2h3.8M161.2 98.4h3.8M161.3 94.2h3.7M161.3 98.4h3.7M161.3 94.3h3.7M161.3 98.3h3.7M161.4 94.3h3.6M161.4 98.3h3.6M161.4 94.4h3.6M161.4 98.2h3.6M161.5 94.4h3.5M161.5 98.2h3.5"/>
<path d="M161.5 94.5h3.5M161.5 98.1h3.5M161.6 94.6h3.4M161.6 98.1h3.4M161.6 98h3.4M161.7 94.7h3.3M161.7 98h3.3M161.8 97.9h3.2M161.8 94.8h3.2M161.8 97.8h3.2M161.8 97.7h3.2M161.8 94.9h3.2"/>
<path d="M161.9 94.9h3.1M161.9 97.7h3.1M161.9 95h3.1M161.9 97.6h3.1M162 97.5h3M162 95.1h3M162 95.2h3M162 97.4h3M162.1 95.2h2.9M162.1 97.4h2.9M162.1 97.3h2.9M162.1 95.3h2.9"/>
<path d="M162.1 95.3l.2 .7M162.1 97.3l-.3 .6-1.1 .9M162.1 97.2h2.9M162.1 95.4h2.9M162.1 97.1h2.9M162.1 95.5h2.9M162.2 97.1h2.8M162.2 97h2.8M162.2 95.5h2.8M162.2 95.7h2.8M162.2 95.6h2.8M162.2 96.9h2.8"/>
<path d="M162.2 96.8h2.8M162.2 95.8h2.8M162.2 96.7h2.8M162.2 95.9h2.8M162.3 96.7h2.7M162.3 96.6h2.7M162.3 96.5h2.7M162.3 96.4h2.7M162.3 96.3h2.7M162.3 96.2h2.7M162.3 96.1h2.7M162.3 96h2.7"/>
<path d="M162.3 95.9h2.7M162.3 96v.7M162.3 96.7l-.2 .6M165 93.7h-9.1M167 99h9.1M167 99.9h9.1M167 99.8h9.1M167 99.7h9.1M167 99.6h9.1M167 99.5h9.1M167 99.4h9.1M167 99.3h9.1"/>
<path d="M167 99.2h9.1M167 99.1h9.1M167 98.9h4.9M167 98.8l4.7 .1M167 98.8h4.6M167 98.7l4.3 .1M167 98.7h4.2M167 98.6l4.1 .1M167 98.6h4M167 98.5l4 .1M167 98.5h3.8M167 98.4h3.8"/>
<path d="M167 98.4h3.7M167 98.3h3.6M167 98.2h3.5M167 98.1l3.5 .1M167 98.1h3.4M167 98l3.4 .1M167 98h3.3M167 97.9l3.3 .1M167 97.9h3.2M167 97.8l3.2 .1M167 97.8h3.2M167 97.7h3.1"/>
<path d="M167 97.6h3.1M167 97.5h3M167 97.4h2.9M167 97.3l2.9 .1M167 97.3h2.9M167 97.2l2.9 .1M167 97.2h2.9M167 97.1h2.8M167 97h2.8M167 96.9l2.8 .1M167 96.9h2.8M167 96.8h2.8"/>
<path d="M167 96.7h2.7M167 96.6h2.7M167 96.5h2.7M167 96.4h2.7M167 96.3h2.7M167 96.2h2.7M167 96.1h2.7M167 96h2.7M167 95.9h2.7M167 95.8h2.8M167 95.7h2.8M167 95.5h2.8"/>
<path d="M167 95.4h2.9M167 95.1h3M167 95h3.1M167 94.9h3.2M167 94.8h3.2M167 93.6h9.1M167 93.5h9.1M167 93.4h9.1M167 93.3h9.1M167 93.2l9.1 .1M167 93.2h9M167 93.1l9 .1"/>
<path d="M167 93.1h8.9M167 93h8.9M167 93h8.8M167 92.9h8.8M167 92.9h8.7M167 92.8h8.7M167 92.8h8.6M167 92.7h8.6M167 92.6l8.5 .1M167 92.6h8.5M167 92.5l8.4 .1M167 92.5h8.3"/>
<path d="M167 92.4l8.3 .1M167 92.4h8.2M167 92.3l8.2 .1M167 92.3h8.1M167 92.2h8.1M167 92.2h8M167 92.1h8M167 92.1h7.9M167 92h7.9M167 91.9l7.8 .1M167 91.9h7.8M167 91.8l7.7 .1"/>
<path d="M167 91.8h7.6M167 91.7l7.6 .1M167 91.7h7.5M167 91.6l7.5 .1M167 91.6h7.4M167 91.5h7.4M167 91.5h7.3M167 91.4h7.3M167 91.4h7.2M167 91.3h7.2M167 91.2l7.1 .1M167 91.2h7.1"/>
<path d="M167 91.1l7 .1M167 91.1h6.9M167 91l6.9 .1M167 91h6.8M167 90.9l6.8 .1M167 90.9h6.7M167 90.8l6.7 .1M167 90.8h6.6M167 90.7l6.6 .1M167 90.7h6.5M167 90.6l6.5 .1M167 90.6h6.4"/>
<path d="M167 90.5l6.4 .1M167 90.5h6.3M167 90.4h6.3M167 90.4h6.2M167 90.3h6.2M167 90.3h6.1M167 90.2h6.1M167 90.1l6 .1M167 90.1h6M167 90l5.9 .1M167 90h5.8M167 89.9l5.8 .1"/>
<path d="M167 89.9h5.7M167 89.8l5.7 .1M167 89.8h5.6M167 89.7h5.6M167 89.7h5.5M167 89.6h5.5M167 89.6h5.4M167 89.5h5.4M167 89.5h5.3M167 89.4h5.3M167 89.3l5.2 .1M167 89.3h5.1"/>
<path d="M167 89.2l5.1 .1M167 89.2h5M167 89.1l5 .1M167 89.1h4.9M167 89l4.9 .1M167 89h4.8M167 88.9h4.8M167 88.8h4.7M167 88.7h4.7M167 88.6h4.7M167 88.6h4.6M167 88.5h4.6"/>
<path d="M167 88.4h4.6M167 88.3h4.6M167 88.2h4.6M167 88.1h4.6M167 88h4.6M167 87.9h4.6M167 87.8h4.6M167 87.7h4.6M167 87.6h4.6M167 87.5h4.6M167 87.4h4.6M167 87.3h4.6"/>
<path d="M167 87.2h4.6M167 87.1h4.6M167 87h4.6M167 86.9h4.6M167 86.8h4.6M167 86.7h4.6M167 86.6h4.6M167 86.5h4.6M167 86.4h4.6M167 86.3h4.6M167 86.2h4.6M167 86.1h4.6"/>
<path d="M167 86h4.6M167 85.9h4.6M167 85.8h4.6M167 85.7h4.6M167 85.6h4.6M167 85.5h4.6M167 85.4h4.6M167 85.3h4.6M167 85.2h4.6M167 85.1h4.6M167 85h4.6M167 84.9h4.6"/>
<path d="M167 84.8h4.6M167 84.7h4.6M167 84.6h4.6M167 84.5h4.6M167 84.4h4.6M167 84.3h4.6M167 84.2h4.6M167 84.1h4.6M167 84h4.6M167 83.9h4.6M167 83.8h4.6M167 83.7h4.6"/>
<path d="M167 83.6h4.6M167 83.5h4.6M167 83.4h4.6M167 83.3h4.6M167 83.2h4.6M167 83.1h4.6M167 83h4.6M167 82.9h4.6M167 82.8h4.6M167 82.7h4.6M167 82.6h4.6M167 82.5h4.6"/>
<path d="M167 82.4h4.6M167 82.3h4.6M167 82.2h4.6M167 82.1h4.6M167 82h4.6M167 81.9h4.6M167 81.8h4.6M167 81.7h4.6M167 81.6h4.6M167 81.5h4.6M167 81.4h4.6M167 81.3h4.6"/>
<path d="M167 81.2h4.6M167 81.1h4.6M167 81h4.6M167 80.9h4.6M167 80.8h4.6M167 80.7h4.6M167 80.6h4.6M167 80.5h4.6M167 80.4h4.6M167 80.3h4.6M167 80.2h4.6M167 80.1h4.6"/>
<path d="M169.7 96v.7M169.7 96.7l.5 1.2M169.7 95.9h-2.7M169.8 95.8h-2.8M169.8 95.7h-2.8M169.8 95.6h-2.8M169.9 95.4l-2.9 .1M169.9 95.3l-2.9 .1M169.9 95.3l-.2 .7M169.9 95.3h-2.9M169.9 95.2l-2.9 .1M170 95.2h-3"/>
<path d="M170 95.1l-3 .1M170.1 95l-3.1 .1M170.1 94.9l-3.1 .1M170.2 94.8h-3.2M170.2 94.7h-3.2M170.2 94.7l-.3 .6M170.2 97.9l1.1 .9M170.3 94.7h-3.3M170.3 94.6h-3.3M170.4 94.6h-3.4M170.5 94.5h-3.5M170.5 94.4l-3.5 .1"/>
<path d="M170.6 94.4h-3.6M170.6 94.3l-3.6 .1M170.7 94.3h-3.7M170.7 94.2l-3.7 .1M170.8 94.2h-3.8M170.9 94.1h-3.9M171 94.1h-4M171.1 94h-4.1M171.2 94h-4.2M171.3 93.9h-4.3M171.3 98.8l.7 .2M171.4 93.9h-4.4"/>
<path d="M171.6 93.8h-4.6M171.6 88.6l.2 .4M171.8 89l4.3 4.3M171.8 93.7l-4.8 .1M172 93.7l-.7 .2-1.1 .8M172.7 93.7l.7 .2 1 .8M172.7 98.9h3.4M172.9 93.7h3.2M173 98.9h3.1M173.1 93.8h3M173.1 98.8h3M173.2 93.9h2.9"/>
<path d="M173.4 98.8h2.7M173.4 98.8l-.7 .2M173.4 93.9h2.7M173.4 98.7h2.7M173.5 94h2.6M173.5 98.7h2.6M173.6 94h2.5M173.7 98.6h2.4M173.7 94.1h2.4M173.8 94.1h2.3M173.8 98.5h2.3M173.9 94.2h2.2"/>
<path d="M173.9 98.4h2.2M174 94.2h2.1M174 98.4h2.1M174 94.3h2.1M174 98.3h2.1M174.1 94.3h2M174.1 98.3h2M174.1 94.4h2M174.1 98.2h2M174.2 94.4h1.9M174.2 98.2h1.9M174.2 94.5h1.9"/>
<path d="M174.2 98.1h1.9M174.3 94.6h1.8M174.3 98.1h1.8M174.3 98h1.8M174.4 94.7h1.7M174.4 98h1.7M174.4 97.9l-1 .9M174.4 94.7l.6 1.3M174.5 97.9h1.6M174.5 94.8h1.6M174.5 97.8h1.6M174.5 97.7h1.6"/>
<path d="M174.5 94.9h1.6M174.6 94.9h1.5M174.6 97.7h1.5M174.6 95h1.5M174.6 97.6h1.5M174.7 97.5h1.4M174.7 95.1h1.4M174.7 95.2h1.4M174.7 97.4h1.4M174.8 97.4h1.3M174.8 95.2h1.3M174.8 95.3h1.3"/>
<path d="M174.8 97.3h1.3M174.8 97.2h1.3M174.8 95.4h1.3M174.8 97.1h1.3M174.8 95.5h1.3M174.9 97.1h1.2M174.9 97h1.2M174.9 95.5h1.2M174.9 95.7h1.2M174.9 95.6h1.2M174.9 96.9h1.2M174.9 95.8h1.2"/>
<path d="M174.9 96.8h1.2M174.9 96.7h1.2M174.9 95.9h1.2M175 96.7h1.1M175 96.6h1.1M175 96.5h1.1M175 96.4h1.1M175 96.3h1.1M175 96.2h1.1M175 96.1h1.1M175 96h1.1M175 95.9h1.1"/>
<path d="M175 96v.7M175 96.7l-.6 1.2M176.1 93.3v8.3h-9.1v-47.7h47.8v47.7h-9.1v-8.3M176.1 93.7h-9.1M205.7 99h9.1M205.7 99.9h9.1M205.7 99.8h9.1M205.7 99.7h9.1M205.7 99.6h9.1M205.7 99.5h9.1M205.7 99.4h9.1M205.7 99.3h9.1"/>
<path d="M205.7 99.2h9.1M205.7 99.1h9.1M205.7 98.9h3.4M205.7 98.8l3.2 .1M205.7 98.8h3M205.7 98.7l2.8 .1M205.7 98.7h2.7M205.7 98.6l2.6 .1M205.7 98.6h2.5M205.7 98.5l2.4 .1M205.7 98.5h2.3M205.7 98.4h2.2"/>
<path d="M205.7 98.4h2.1M205.7 98.3h2.1M205.7 98.3h2M205.7 98.2h2M205.7 98.1l1.9 .1M205.7 98.1h1.9M205.7 98l1.8 .1M205.7 98h1.8M205.7 97.9l1.7 .1M205.7 97.9h1.7M205.7 97.8h1.6M205.7 97.7h1.6"/>
<path d="M205.7 97.7h1.5M205.7 97.6h1.5M205.7 97.5h1.5M205.7 97.5h1.4M205.7 97.4h1.4M205.7 97.3l1.4 .1M205.7 97.3h1.3M205.7 97.2h1.3M205.7 97.1h1.3M205.7 97h1.3M205.7 97h1.2M205.7 96.9h1.2"/>
<path d="M205.7 96.8h1.2M205.7 96.7h1.2M205.7 96.6h1.2M205.7 96.5h1.2M205.7 96.4h1.2M205.7 96.3h1.2M205.7 96.2h1.2M205.7 96.1h1.2M205.7 96h1.2M205.7 95.9h1.2M205.7 95.8h1.2M205.7 95.7h1.2"/>
<path d="M205.7 95.6h1.2M205.7 95.4h1.3M205.7 95.2h1.4M205.7 95.1h1.5M205.7 94.4h1.9M205.7 93.6h9.1M205.7 93.5h9.1M205.7 93.4h9.1M205.7 93.3h9.1M205.8 93.2h9M205.9 93.1h8.9M206 93h8.8"/>
<path d="M206.1 92.9h8.7M206.2 92.8h8.6M206.3 92.7h8.5M206.4 92.6h8.4M206.5 92.5h8.3M206.6 92.4h8.2M206.7 92.4h8.1M206.7 92.3h8.1M206.8 92.2h8M206.9 92.1h7.9M206.9 96v.7M206.9 96.7a2.54 2.54 0 0 0 1.6 2.1"/>
<path d="M206.9 95.9h-1.2M206.9 95.8h-1.2M206.9 95.7h-1.2M207 95.5l-1.3 .1M207 92h7.8M207 95.5h-1.3M207 95.3l-1.3 .1M207 95.3l-.1 .7M207.1 95.3h-1.4M207.1 95.2l-1.4 .1M207.1 91.9h7.7M207.1 95.1h-1.4"/>
<path d="M207.2 91.8h7.6M207.2 95h-1.5M207.3 94.9h-1.6M207.3 91.7h7.5M207.3 94.8h-1.6M207.4 94.7h-1.7M207.4 91.6h7.4M207.5 91.5h7.3M207.5 94.6h-1.8M207.6 91.4h7.2M207.6 94.5h-1.9M207.7 91.3h7.1"/>
<path d="M207.7 94.4h-2M207.8 94.3l-2.1 .1M207.8 91.2h7M207.8 94.3h-2.1M207.9 94.2l-2.2 .1M207.9 91.1h6.9M208 94.2h-2.3M208 91h6.8M208 94.1h-2.3M208.1 90.9h6.7M208.2 94.1h-2.5M208.2 90.8h6.6"/>
<path d="M208.2 94h-2.5M208.3 90.7h6.5M208.3 94h-2.6M208.4 93.9h-2.7M208.4 90.6h6.4M208.5 98.8l.6 .2M208.5 90.5h6.3M208.6 90.4h6.2M208.6 93.9h-2.9M208.7 90.3h6.1M208.7 93.8h-3M208.8 90.2h6"/>
<path d="M208.9 90.1h5.9M209 93.7l-3.3 .1M209 90h5.8M209.1 89.9h5.7M209.1 93.7a2.62 2.62 0 0 0-2.1 1.6M209.2 89.8h5.6M209.3 89.7h5.5M209.4 89.6h5.4M209.5 89.5h5.3M209.6 89.4h5.2M209.7 89.3h5.1M209.8 89.2h5"/>
<path d="M209.8 93.7l.7 .2 1.1 .8M209.9 98.9h4.9M209.9 89.1h4.9M210 89h4.8M210 93.7h4.8M210 88.9h4.8M210 89l-4.3 4.3M210.1 88.9h4.7M210.1 88.8h4.7M210.1 98.9h4.7M210.1 88.7h4.7M210.2 88.6h4.6"/>
<path d="M210.2 88.5h4.6M210.2 88.4h4.6M210.2 88.3h4.6M210.2 88.2h4.6M210.2 88.1h4.6M210.2 88h4.6M210.2 87.9h4.6M210.2 87.8h4.6M210.2 87.7h4.6M210.2 87.6h4.6M210.2 87.5h4.6M210.2 87.4h4.6"/>
<path d="M210.2 87.3h4.6M210.2 87.2h4.6M210.2 87.1h4.6M210.2 87h4.6M210.2 86.9h4.6M210.2 86.8h4.6M210.2 86.7h4.6M210.2 86.6h4.6M210.2 86.5h4.6M210.2 86.4h4.6M210.2 86.3h4.6M210.2 86.2h4.6"/>
<path d="M210.2 86.1h4.6M210.2 86h4.6M210.2 85.9h4.6M210.2 85.8h4.6M210.2 85.7h4.6M210.2 85.6h4.6M210.2 85.5h4.6M210.2 85.4h4.6M210.2 85.3h4.6M210.2 85.2h4.6M210.2 85.1h4.6M210.2 85h4.6"/>
<path d="M210.2 84.9h4.6M210.2 84.8h4.6M210.2 84.7h4.6M210.2 84.6h4.6M210.2 84.5h4.6M210.2 84.4h4.6M210.2 84.3h4.6M210.2 84.2h4.6M210.2 84.1h4.6M210.2 84h4.6M210.2 83.9h4.6M210.2 83.8h4.6"/>
<path d="M210.2 83.7h4.6M210.2 83.6h4.6M210.2 83.5h4.6M210.2 83.4h4.6M210.2 83.3h4.6M210.2 83.2h4.6M210.2 83.1h4.6M210.2 83h4.6M210.2 82.9h4.6M210.2 82.8h4.6M210.2 82.7h4.6M210.2 82.6h4.6"/>
<path d="M210.2 82.5h4.6M210.2 82.4h4.6M210.2 82.3h4.6M210.2 82.2h4.6M210.2 82.1h4.6M210.2 82h4.6M210.2 81.9h4.6M210.2 81.8h4.6M210.2 81.7h4.6M210.2 81.6h4.6M210.2 81.5h4.6M210.2 81.4h4.6"/>
<path d="M210.2 81.3h4.6M210.2 81.2h4.6M210.2 81.1h4.6M210.2 81h4.6M210.2 80.9h4.6M210.2 80.8h4.6M210.2 80.7h4.6M210.2 80.6h4.6M210.2 80.5h4.6M210.2 80.4h4.6M210.2 80.3h4.6M210.2 80.2h4.6"/>
<path d="M210.2 80.1h4.6M210.2 88.6l-.2 .4M210.2 98.8h4.6M210.2 93.8h4.6M210.4 93.9h4.4M210.5 98.8h4.3M210.5 98.8l-.7 .2M210.6 93.9h4.2M210.6 98.7h4.2M210.7 94h4.1M210.7 98.7h4.1M210.8 94h4"/>
<path d="M210.8 98.6h4M210.8 94.1h4M210.9 98.6h3.9M210.9 94.1h3.9M211 98.5h3.8M211 94.2h3.8M211.1 98.4h3.7M211.1 94.2h3.7M211.2 94.3h3.6M211.2 98.3h3.6M211.3 94.4h3.5M211.3 98.2h3.5"/>
<path d="M211.3 94.5h3.5M211.4 98.1h3.4M211.4 94.6h3.4M211.5 98.1h3.3M211.5 94.6h3.3M211.5 98h3.3M211.5 94.7h3.3M211.6 98h3.2M211.6 94.7h3.2M211.6 94.7l.5 1.3M211.6 97.9h3.2M211.6 94.8h3.2"/>
<path d="M211.6 97.8h3.2M211.7 94.9h3.1M211.7 97.7h3.1M211.7 95h3.1M211.8 97.6h3M211.8 95h3M211.8 95.1h3M211.8 97.5h3M211.9 95.2h2.9M211.9 97.4h2.9M211.9 95.3h2.9M211.9 97.3h2.9"/>
<path d="M212 97.2h2.8M212 95.4h2.8M212 97.1h2.8M212 95.5h2.8M212 97h2.8M212 95.6h2.8M212 96.9h2.8M212 95.7h2.8M212 95.8h2.8M212.1 96.8h2.7M212.1 95.8h2.7M212.1 96.7h2.7"/>
<path d="M212.1 95.9h2.7M212.1 96.6h2.7M212.1 96.5h2.7M212.1 96.4h2.7M212.1 96.3h2.7M212.1 96.2h2.7M212.1 96.1h2.7M212.1 96h2.7M212.1 96v.7M212.1 96.7a2.64 2.64 0 0 1-1.6 2.1M214.8 93.7h-9.1M67.4 101.6h9"/>
<path d="M67.4 101.5h9M67.4 101.4h9M67.4 101.3h9M67.4 101.2h9M67.4 101.1h9M67.4 101h9M67.4 100.9h9M67.4 100.8h9M67.4 100.7h9M67.4 100.6h9M67.4 100.5h9M67.4 100.4h9"/>
<path d="M67.4 100.3h9M67.4 100.2h9M67.4 100.1h9M67.4 100h9M67.4 111.9l9 .1M67.4 120h4.6M67.4 119.9h4.6M67.4 119.8h4.6M67.4 119.7h4.6M67.4 119.6h4.6M67.4 119.5h4.6M67.4 119.4h4.6"/>
<path d="M67.4 119.3h4.6M67.4 119.2h4.6M67.4 119.1h4.6M67.4 119h4.6M67.4 118.9h4.6M67.4 118.8h4.6M67.4 118.7h4.6M67.4 118.6h4.6M67.4 118.5h4.6M67.4 118.4h4.6M67.4 118.3h4.6M67.4 118.2h4.6"/>
<path d="M67.4 118.1h4.6M67.4 118h4.6M67.4 117.9h4.6M67.4 117.8h4.6M67.4 117.7h4.6M67.4 117.6h4.6M67.4 117.5h4.6M67.4 117.4h4.6M67.4 117.3h4.6M67.4 117.2h4.6M67.4 117.1h4.6M67.4 117h4.6"/>
<path d="M67.4 116.9h4.7M67.4 116.5h4.9M67.4 116.2h5.2M67.4 115.9h5.5M67.4 115.6h5.8M67.4 115.3h6.1M67.4 115h6.5M67.4 114.6h6.8M67.4 114.3h7.1M67.4 114h7.4M67.4 113.7h7.7M67.4 113.4h8"/>
<path d="M67.4 113.1h8.4M67.4 112.7h8.7M67.4 112.4h9M67.4 112.3h9M67.4 112.2h9M67.4 112.1h9M67.4 112h9M67.4 111.9h4.7M67.4 111.8l4.5 .1M67.4 111.8h4.3M67.4 111.7l4.2 .1M67.4 111.7h4.1"/>
<path d="M67.4 111.6l4 .1M67.4 111.6h3.9M67.4 111.5h3.8M67.4 111.5h3.7M67.4 111.4h3.7M67.4 111.3l3.6 .1M67.4 111.3h3.5M67.4 111.2l3.5 .1M67.4 111.2h3.4M67.4 111.1l3.4 .1M67.4 111.1h3.3M67.4 111l3.3 .1"/>
<path d="M67.4 111h3.2M67.4 110.9l3.2 .1M67.4 110.9h3.1M67.4 110.8h3.1M67.4 110.7h3M67.4 110.6h3M67.4 110.5h2.9M67.4 110.4h2.9M67.4 110.3l2.8 .1M67.4 110.3h2.8M67.4 110.2h2.8M67.4 110.1h2.8"/>
<path d="M67.4 110.1h2.7M67.4 110h2.7M67.4 109.9h2.7M67.4 109.8h2.7M67.4 109.7h2.7M67.4 109.7h2.6M67.4 109.6h2.6M67.4 109.5h2.6M67.4 109.4h2.6M67.4 109.3h2.6M67.4 109.2h2.6M67.4 109.1h2.6"/>
<path d="M67.4 109h2.6M67.4 108.9h2.7M67.4 108.8h2.7M67.4 108.6h2.7M67.4 108.5h2.8M67.4 108.3h2.8M67.4 107.9h3.1M67.4 107.8h3.1M67.4 107.6h3.3M67.4 107.3h3.6M67.4 106.6h9M67.4 106.5h9"/>
<path d="M67.4 106.4h9M67.4 106.3h9M67.4 106.2h9M67.4 106.1h9M67.4 106h9M67.4 105.9h9M67.4 105.8h9M67.4 105.7h9M67.4 105.6h9M67.4 105.5h9M67.4 105.4h9M67.4 105.3h9"/>
<path d="M67.4 105.2h9M67.4 105.1h9M67.4 105h9M67.4 104.9h9M67.4 104.8h9M67.4 104.7h9M67.4 104.6h9M67.4 104.5h9M67.4 104.4h9M67.4 104.3h9M67.4 104.2h9M67.4 104.1h9"/>
<path d="M67.4 104h9M70 109v.7M70 109.7l.2 .6M70.1 108.9h-2.7M70.1 108.8h-2.7M70.1 108.7h-2.7M70.1 108.6h-2.7M70.2 108.4l-2.8 .1M70.2 108.3l-.2 .7M70.2 110.3l.4 .7M70.2 108.4h-2.8M70.3 108.3h-2.9"/>
<path d="M70.3 108.2h-2.9M70.3 108.1h-2.9M70.4 108.1h-3M70.4 108h-3M70.4 107.9l-3 .1M70.5 107.8l-3.1 .1M70.5 107.7l-3.1 .1M70.6 111l.5 .4M70.6 107.7h-3.2M70.7 107.6l-3.3 .1M70.8 107.5l-3.4 .1M70.8 107.5h-3.4"/>
<path d="M70.9 107.4l-3.5 .1M70.9 107.4h-3.5M71 107.3h-3.6M71.1 107.2l-.9 1.1M71.1 111.4l1.2 .6M71.1 107.2l-3.7 .1M71.2 107.2h-3.8M71.3 107.1h-3.9M71.4 107.1h-4M71.5 107h-4.1M71.6 106.9l-.5 .3M71.6 106.9h-4.2"/>
<path d="M71.8 106.8l-4.4 .1M72 117.1v9.3M72 117h-4.6M72 116.9h-4.6M72 106.8h-4.6M72.1 116.8h-4.7M72.1 116.7l-.1 .4M72.1 116.7h-4.7M72.2 116.6l-4.8 .1M72.2 116.6h-4.8M72.2 106.7l-4.8 .1M72.3 106.7l-.7 .2"/>
<path d="M72.3 116.5h-4.9M72.4 116.4l-5 .1M72.4 116.4h-5M72.5 116.3l-5.1 .1M72.5 116.3h-5.1M72.6 116.2h-5.2M72.7 116.1h-5.3M72.8 116h-5.4M72.9 116h-5.5M73 115.8l-5.6 .1M73 106.7l.7 .2M73 115.8h-5.6"/>
<path d="M73.1 115.7l-5.7 .1M73.1 115.7h-5.7M73.1 106.7h3.3M73.2 115.6l-5.8 .1M73.2 111.9h3.2M73.3 115.5l-5.9 .1M73.3 106.8h3.1M73.3 115.5h-5.9M73.4 115.4l-6 .1M73.4 111.9h3M73.4 115.4h-6M73.5 115.3h-6.1"/>
<path d="M73.5 106.8h2.9M73.6 115.2l-6.2 .1M73.6 111.8h2.8M73.6 115.2h-6.2M73.7 106.9l1.1 .8M73.7 106.9h2.7M73.7 115.1h-6.3M73.7 111.8h2.7M73.8 107h2.6M73.8 115h-6.4M73.8 111.7h2.6M73.9 107h2.5"/>
<path d="M73.9 111.7h2.5M73.9 114.9h-6.5M74 114.9h-6.6M74 107.1h2.4M74 111.6h2.4M74 114.8h-6.6M74.1 114.7l-6.7 .1M74.1 107.1h2.3M74.1 111.5h2.3M74.1 114.7h-6.7M74.2 107.2h2.2M74.2 111.5h2.2"/>
<path d="M74.2 114.6h-6.8M74.3 111.4l-1.3 .6M74.3 114.5l-6.9 .1M74.3 111.4h2.1M74.3 107.3h2.1M74.3 114.5h-6.9M74.4 107.3h2M74.4 114.4h-7M74.4 111.3h2M74.4 107.4h2M74.5 107.4h1.9M74.5 111.2h1.9"/>
<path d="M74.5 107.5h1.9M74.5 114.3h-7.1M74.6 107.5h1.8M74.6 114.2h-7.2M74.6 111.1h1.8M74.6 107.6h1.8M74.7 114.2h-7.3M74.7 111.1h1.7M74.7 107.6h1.7M74.7 114.1h-7.3M74.7 111h1.7M74.7 107.7h1.7"/>
<path d="M74.8 107.7l.3 .6M74.8 111l-.5 .4M74.8 114l-7.4 .1M74.8 111h1.6M74.8 107.7h1.6M74.8 110.9h1.6M74.8 107.8h1.6M74.8 110.8h1.6M74.9 113.9l-7.5 .1M74.9 110.8h1.5M74.9 107.9h1.5M74.9 110.7h1.5"/>
<path d="M74.9 113.9h-7.5M74.9 108h1.5M75 110.6h1.4M75 108.1h1.4M75 113.8l-7.6 .1M75 113.8h-7.6M75 110.5h1.4M75 108.2h1.4M75.1 110.4h1.3M75.1 108.2h1.3M75.1 113.7h-7.7M75.1 108.3h1.3"/>
<path d="M75.1 108.3l.2 .7M75.1 110.3l-.3 .7M75.1 110.3h1.3M75.1 108.4h1.3M75.1 110.2h1.3M75.2 110.1h1.2M75.2 108.5h1.2M75.2 113.6l-7.8 .1M75.2 110h1.2M75.2 108.6h1.2M75.2 108.7h1.2M75.2 113.6h-7.8"/>
<path d="M75.2 109.9h1.2M75.2 108.8h1.2M75.2 109.8h1.2M75.2 108.9h1.2M75.3 109.7h1.1M75.3 108.9h1.1M75.3 109v.7M75.3 109.7l-.2 .6M75.3 113.5l-7.9 .1M75.3 109.6h1.1M75.3 109.5h1.1M75.3 109.4h1.1"/>
<path d="M75.3 109.3h1.1M75.3 109.2h1.1M75.3 109.1h1.1M75.3 109h1.1M75.3 113.5h-7.9M75.4 113.4h-8M75.5 113.3h-8.1M75.6 113.2h-8.2M75.7 113.1h-8.3M75.8 113h-8.4M75.9 112.9l-8.5 .1M75.9 112.9h-8.5"/>
<path d="M76 112.8l-8.6 .1M76 112.8h-8.6M76.1 112.7h-8.7M76.2 112.6h-8.8M76.3 112.5h-8.9M76.4 112.4v-8.4h-9v47.7h47.7v-47.7h-9v8.4M76.4 112.4l-4.3 4.3M76.4 106.7h-9M106.1 101.6h9M106.1 101.5h9M106.1 101.4h9M106.1 101.3h9"/>
<path d="M106.1 101.2h9M106.1 101.1h9M106.1 101h9M106.1 100.9h9M106.1 100.8h9M106.1 100.7h9M106.1 100.6h9M106.1 100.5h9M106.1 100.4h9M106.1 100.3h9M106.1 100.2h9M106.1 100.1h9"/>
<path d="M106.1 100h9M106.1 112.4l4.3 4.3M106.1 111.9l9 .1M106.1 112.4h9M106.1 112.3h9M106.1 112.2h9M106.1 112.1h9M106.1 112h9M106.1 111.9h3.2M106.1 111.8l3 .1M106.1 111.8h2.8M106.1 111.7l2.7 .1"/>
<path d="M106.1 111.7h2.5M106.1 111.6l2.5 .1M106.1 111.6h2.4M106.1 111.5h2.3M106.1 111.5h2.2M106.1 111.4h2.1M106.1 111.3l2 .1M106.1 111.3h2M106.1 111.2l1.9 .1M106.1 111.2h1.9M106.1 111.1l1.8 .1M106.1 111.1h1.8"/>
<path d="M106.1 111l1.7 .1M106.1 111h1.7M106.1 110.9l1.6 .1M106.1 110.9h1.6M106.1 110.8h1.6M106.1 110.8h1.5M106.1 110.7h1.5M106.1 110.7h1.4M106.1 110.6h1.4M106.1 110.5h1.4M106.1 110.4h1.3M106.1 110.3h1.3"/>
<path d="M106.1 110.2h1.2M106.1 110.1h1.2M106.1 110h1.2M106.1 109.9h1.2M106.1 109.9h1.1M106.1 109.8h1.1M106.1 109.7l1.1 .1M106.1 109.7h1.1M106.1 109.6l1.1 .1M106.1 109.6h1.1M106.1 109.5h1.1M106.1 109.4h1.1"/>
<path d="M106.1 109.3h1.1M106.1 109.2h1.1M106.1 109.1h1.1M106.1 109h1.1M106.1 108.9h1.1M106.1 108.8h1.1M106.1 108.7h1.2M106.1 108.5h1.2M106.1 108.4h1.2M106.1 108.2h1.3M106.1 108.1h1.4M106.1 108h1.4"/>
<path d="M106.1 107.9h1.5M106.1 107.6h1.7M106.1 107.3h2.1M106.1 106.6h9M106.1 106.5h9M106.1 106.4h9M106.1 106.3h9M106.1 106.2h9M106.1 106.1h9M106.1 106h9M106.1 105.9h9M106.1 105.8h9"/>
<path d="M106.1 105.7h9M106.1 105.6h9M106.1 105.5h9M106.1 105.4h9M106.1 105.3h9M106.1 105.2h9M106.1 105.1h9M106.1 105h9M106.1 104.9h9M106.1 104.8h9M106.1 104.7h9M106.1 104.6h9"/>
<path d="M106.1 104.5h9M106.1 104.4h9M106.1 104.3h9M106.1 104.2h9M106.1 104.1h9M106.1 104h9M106.1 112.5h9M106.2 112.5h8.9M106.2 112.6h8.9M106.3 112.6h8.8M106.3 112.7h8.8M106.4 112.7h8.7"/>
<path d="M106.4 112.8h8.7M106.5 112.8h8.6M106.6 112.9h8.5M106.7 113h8.4M106.7 113.1h8.4M106.8 113.2h8.3M106.9 113.2h8.2M106.9 113.3h8.2M107 113.3h8.1M107 113.4h8.1M107.1 113.4h8M107.1 113.5h8"/>
<path d="M107.2 109v.7M107.2 109.7l.2 .6M107.2 113.5h7.9M107.2 109h-1.1M107.2 108.9h-1.1M107.2 108.8h-1.1M107.3 113.6h7.8M107.3 108.6l-1.2 .1M107.3 108.6h-1.2M107.3 108.5h-1.2M107.4 108.3l-.2 .7M107.4 110.3l.3 .7"/>
<path d="M107.4 113.7h7.7M107.4 108.3l-1.3 .1M107.4 108.3h-1.3M107.4 113.8h7.7M107.4 108.2h-1.3M107.5 113.8h7.6M107.5 108.1h-1.4M107.6 113.9h7.5M107.6 107.9l-1.5 .1M107.6 107.8l-1.5 .1M107.7 107.8h-1.6M107.7 114h7.4"/>
<path d="M107.7 111l.5 .4M107.7 107.7l-1.6 .1M107.7 107.7h-1.6M107.8 114.1h7.3M107.8 107.6l-1.7 .1M107.8 114.2h7.3M107.9 114.2h7.2M107.9 107.5l-1.8 .1M107.9 114.3h7.2M107.9 107.5h-1.8M108 114.3h7.1M108 114.4h7.1"/>
<path d="M108 107.4l-1.9 .1M108.1 107.4h-2M108.1 114.4h7M108.1 107.3h-2M108.1 114.5h7M108.2 111.4l1.3 .6M108.2 114.5h6.9M108.2 114.6h6.9M108.2 107.2l-2.1 .1M108.3 114.6h6.8M108.3 107.2h-2.2M108.3 114.7h6.8"/>
<path d="M108.4 114.7h6.7M108.4 107.1h-2.3M108.5 114.8h6.6M108.5 107.1h-2.4M108.5 114.9h6.6M108.6 114.9h6.5M108.6 107h-2.5M108.6 115h6.5M108.7 107h-2.6M108.7 115.1h6.4M108.8 115.1h6.3M108.8 106.9l-1.1 .8-.3 .6"/>
<path d="M108.8 106.9h-2.7M108.8 115.2h6.3M108.9 115.2h6.2M108.9 106.8l-2.8 .1M108.9 115.3h6.2M109 115.3h6.1M109 115.4h6.1M109.1 115.4h6M109.2 115.5h5.9M109.2 106.8h-3.1M109.3 115.6h5.8M109.3 115.7h5.8"/>
<path d="M109.4 106.7l-3.3 .1M109.4 115.7h5.7M109.5 106.7l-.7 .2M109.5 115.8h5.6M109.6 115.9h5.5M109.6 116h5.5M109.7 116h5.4M109.7 116.1h5.4M109.8 116.1h5.3M109.8 116.2h5.3M109.9 116.2h5.2M109.9 116.3h5.2"/>
<path d="M110 116.3h5.1M110 116.4h5.1M110.1 116.4h5M110.2 106.7l.6 .2M110.2 116.5h4.9M110.2 116.6h4.9M110.3 106.7h4.8M110.3 116.6h4.8M110.3 111.9h4.8M110.4 116.7l.1 .4M110.4 116.7h4.7M110.4 116.8h4.7"/>
<path d="M110.4 116.9h4.7M110.4 106.8h4.7M110.5 117h4.6M110.5 117.1v9.3M110.5 120h4.6M110.5 119.9h4.6M110.5 119.8h4.6M110.5 119.7h4.6M110.5 119.6h4.6M110.5 119.5h4.6M110.5 119.4h4.6M110.5 119.3h4.6"/>
<path d="M110.5 119.2h4.6M110.5 119.1h4.6M110.5 119h4.6M110.5 118.9h4.6M110.5 118.8h4.6M110.5 118.7h4.6M110.5 118.6h4.6M110.5 118.5h4.6M110.5 118.4h4.6M110.5 118.3h4.6M110.5 118.2h4.6M110.5 118.1h4.6"/>
<path d="M110.5 118h4.6M110.5 117.9h4.6M110.5 117.8h4.6M110.5 117.7h4.6M110.5 117.6h4.6M110.5 117.5h4.6M110.5 117.4h4.6M110.5 117.3h4.6M110.5 117.2h4.6M110.5 117.1h4.6M110.5 111.9h4.6M110.7 106.8h4.4"/>
<path d="M110.8 111.8h4.3M110.8 106.9l1.1 .8 .3 .6M110.8 106.9h4.3M110.9 107h4.2M111 111.7h4.1M111 107h4.1M111.1 107.1h4M111.1 111.6h4M111.2 107.1h3.9M111.2 111.5h3.9M111.3 107.2h3.8M111.3 111.5h3.8"/>
<path d="M111.4 107.2h3.7M111.4 111.4h3.7M111.4 111.4l-1.2 .6M111.5 107.3h3.6M111.5 111.4h3.6M111.5 111.3h3.6M111.5 107.4h3.6M111.6 111.3h3.5M111.6 107.4h3.5M111.6 111.2h3.5M111.7 107.5h3.4M111.7 111.1h3.4"/>
<path d="M111.8 111.1h3.3M111.8 107.6h3.3M111.9 111h3.2M111.9 107.7h3.2M111.9 111l-.5 .4M111.9 110.9h3.2M112 107.8h3.1M112 110.8h3.1M112 107.9h3.1M112 110.7h3.1M112.1 110.7h3M112.1 110.6h3"/>
<path d="M112.1 108h3M112.1 108.1h3M112.1 110.5h3M112.2 108.2h2.9M112.2 110.4h2.9M112.2 108.3h2.9M112.2 108.3l.2 .7M112.2 110.3l-.3 .7M112.2 110.3h2.9M112.3 110.3h2.8M112.3 108.4h2.8M112.3 110.2h2.8"/>
<path d="M112.3 108.5h2.8M112.3 110.1h2.8M112.3 110h2.8M112.3 108.6h2.8M112.4 110h2.7M112.4 109.9h2.7M112.4 108.7h2.7M112.4 108.8h2.7M112.4 109.8h2.7M112.4 108.9h2.7M112.4 109.7h2.7M112.4 109h2.7"/>
<path d="M112.4 109v.7M112.4 109.7l-.2 .6M112.4 109.6h2.7M112.4 109.5h2.7M112.4 109.4h2.7M112.4 109.3h2.7M112.4 109.2h2.7M112.4 109.1h2.7M115.1 106.7h-9M117.2 101.6h9M117.2 101.5h9M117.2 101.4h9"/>
<path d="M117.2 101.3h9M117.2 101.2h9M117.2 101.1h9M117.2 101h9M117.2 100.9h9M117.2 100.8h9M117.2 100.7h9M117.2 100.6h9M117.2 100.5h9M117.2 100.4h9M117.2 100.3h9M117.2 100.2h9"/>
<path d="M117.2 100.1h9M117.2 100h9M117.2 111.9l9 .1M117.2 120h4.6M117.2 119.9h4.6M117.2 119.8h4.6M117.2 119.7h4.6M117.2 119.6h4.6M117.2 119.5h4.6M117.2 119.4h4.6M117.2 119.3h4.6M117.2 119.2h4.6"/>
<path d="M117.2 119.1h4.6M117.2 119h4.6M117.2 118.9h4.6M117.2 118.8h4.6M117.2 118.7h4.6M117.2 118.6h4.6M117.2 118.5h4.6M117.2 118.4h4.6M117.2 118.3h4.6M117.2 118.2h4.6M117.2 118.1h4.6M117.2 118h4.6"/>
<path d="M117.2 117.9h4.6M117.2 117.8h4.6M117.2 117.7h4.6M117.2 117.6h4.6M117.2 117.5h4.6M117.2 117.4h4.6M117.2 117.3h4.6M117.2 117.2h4.6M117.2 117.1h4.6M117.2 116.9h4.7M117.2 116.8h4.7M117.2 112.4h9"/>
<path d="M117.2 112.3h9M117.2 112.2h9M117.2 112.1h9M117.2 112h9M117.2 111.9h4.8M117.2 111.8l4.6 .1M117.2 111.8h4.4M117.2 111.7l4.3 .1M117.2 111.7h4.1M117.2 111.6l4.1 .1M117.2 111.6h4M117.2 111.5h3.9"/>
<path d="M117.2 111.5h3.8M117.2 111.4h3.7M117.2 111.3l3.6 .1M117.2 111.3h3.6M117.2 111.2l3.5 .1M117.2 111.2h3.5M117.2 111.1h3.4M117.2 111.1h3.3M117.2 111l3.3 .1M117.2 111h3.3M117.2 110.9l3.2 .1M117.2 110.9h3.2"/>
<path d="M117.2 110.8h3.1M117.2 110.7h3.1M117.2 110.7h3M117.2 110.6h3M117.2 110.5h3M117.2 110.4h2.9M117.2 110.3h2.9M117.2 110.2l2.8 .1M117.2 110.2h2.8M117.2 110.1h2.8M117.2 110h2.8M117.2 109.9h2.8"/>
<path d="M117.2 109.9h2.7M117.2 109.8h2.7M117.2 109.7l2.7 .1M117.2 109.7h2.7M117.2 109.6l2.7 .1M117.2 109.6h2.7M117.2 109.5h2.7M117.2 109.4h2.7M117.2 109.3h2.7M117.2 109.2h2.7M117.2 109.1h2.7M117.2 109h2.7"/>
<path d="M117.2 108.9h2.7M117.2 108.8h2.7M117.2 108.7h2.8M117.2 108.6h2.8M117.2 108.5h2.8M117.2 108.4h2.8M117.2 108.2h2.9M117.2 108.1h3M117.2 107.9h3.1M117.2 106.6h9M117.2 106.5h9M117.2 106.4h9"/>
<path d="M117.2 106.3h9M117.2 106.2h9M117.2 106.1h9M117.2 106h9M117.2 105.9h9M117.2 105.8h9M117.2 105.7h9M117.2 105.6h9M117.2 105.5h9M117.2 105.4h9M117.2 105.3h9M117.2 105.2h9"/>
<path d="M117.2 105.1h9M117.2 105h9M117.2 104.9h9M117.2 104.8h9M117.2 104.7h9M117.2 104.6h9M117.2 104.5h9M117.2 104.4h9M117.2 104.3h9M117.2 104.2h9M117.2 104.1h9M117.2 104h9"/>
<path d="M119.9 109h-2.7M119.9 108.8h-2.7M120 108.6l-2.8 .1M120 108.5h-2.8M120.1 108.3l-.2 .7 .2 1.3M120.1 108.3l-2.9 .1M120.1 110.3l.8 1.1M120.1 108.3h-2.9M120.1 108.2h-2.9M120.2 108.1h-3M120.2 108h-3M120.3 107.9l-3.1 .1"/>
<path d="M120.3 107.8l-3.1 .1M120.4 107.8h-3.2M120.4 107.7l-3.2 .1M120.4 107.7h-3.2M120.5 107.6l-3.3 .1M120.5 107.6h-3.3M120.6 107.5l-3.4 .1M120.6 107.5h-3.4M120.7 107.4l-3.5 .1M120.8 107.4h-3.6M120.8 107.3l-3.6 .1M120.9 107.3h-3.7"/>
<path d="M120.9 111.4l1.3 .6M120.9 107.2l-3.7 .1M121 107.2h-3.8M121.1 107.1h-3.9M121.2 107.1h-4M121.3 107h-4.1M121.4 107h-4.2M121.5 106.9h-4.3M121.5 106.9l-1.1 .8-.3 .6M121.6 106.8l-4.4 .1M121.8 117.1v9.3M121.8 117l-4.6 .1"/>
<path d="M121.8 117h-4.6M121.9 116.9h-4.7M121.9 106.8h-4.7M121.9 116.8h-4.7M121.9 116.7h-4.7M121.9 116.7l-.1 .4M122 116.6l-4.8 .1M122.1 116.6h-4.9M122.1 106.7l-4.9 .1M122.1 116.5l-4.9 .1M122.2 106.7l-.7 .2M122.2 116.5h-5"/>
<path d="M122.2 116.4l-5 .1M122.3 116.4h-5.1M122.3 116.3l-5.1 .1M122.4 116.3h-5.2M122.4 116.2h-5.2M122.5 116.2h-5.3M122.5 116.1h-5.3M122.6 116.1h-5.4M122.6 116h-5.4M122.7 116h-5.5M122.7 115.9h-5.5M122.8 115.8l-5.6 .1"/>
<path d="M122.8 115.8h-5.6M122.9 106.7l.6 .2M122.9 115.7l-5.7 .1M123 115.7h-5.8M123 106.7h3.2M123 115.6l-5.8 .1M123 111.9h3.2M123.1 115.6h-5.9M123.1 115.5l-5.9 .1M123.1 115.5h-5.9M123.1 106.8h3.1M123.2 115.4l-6 .1"/>
<path d="M123.2 111.9h3M123.3 115.4h-6.1M123.3 115.3l-6.1 .1M123.4 115.3h-6.2M123.4 106.8h2.8M123.4 115.2l-6.2 .1M123.4 111.8h2.8M123.5 115.2h-6.3M123.5 106.9h2.7M123.5 106.9l.6 .3 .8 1.1M123.5 115.1h-6.3M123.5 111.8h2.7"/>
<path d="M123.6 115.1h-6.4M123.6 107h2.6M123.7 115h-6.5M123.7 111.7h2.5M123.7 107h2.5M123.8 114.9h-6.6M123.8 107.1h2.4M123.8 114.8h-6.6M123.8 111.6h2.4M123.9 107.1h2.3M123.9 114.7l-6.7 .1M123.9 111.5h2.3"/>
<path d="M124 114.7h-6.8M124 107.2h2.2M124 114.6l-6.8 .1M124 111.5h2.2M124.1 107.2h2.1M124.1 114.6h-6.9M124.1 114.5l-6.9 .1M124.1 111.4h2.1M124.1 107.3h2.1M124.2 114.5h-7M124.2 111.4h2M124.2 107.3h2"/>
<path d="M124.2 114.4h-7M124.2 111.3h2M124.2 107.4h2M124.3 111.3h1.9M124.3 114.4h-7.1M124.3 107.4h1.9M124.3 114.3h-7.1M124.3 111.2h1.9M124.4 107.5h1.8M124.4 114.3h-7.2M124.4 111.1h1.8M124.4 114.2h-7.2"/>
<path d="M124.5 111.1h1.7M124.5 107.6h1.7M124.5 114.2h-7.3M124.5 114.1h-7.3M124.5 111h1.7M124.6 107.7h1.6M124.6 111h1.6M124.6 114l-7.4 .1M124.6 110.9h1.6M124.7 114h-7.5M124.7 107.8h1.5M124.7 110.8h1.5"/>
<path d="M124.7 113.9l-7.5 .1M124.7 110.7h1.5M124.7 107.9h1.5M124.7 113.9h-7.5M124.8 110.7h1.4M124.8 110.6h1.4M124.8 108h1.4M124.8 113.8l-7.6 .1M124.8 108.1h1.4M124.8 110.5h1.4M124.9 113.8h-7.7M124.9 108.2h1.3"/>
<path d="M124.9 110.4h1.3M124.9 113.7l-7.7 .1M124.9 108.3h1.3M124.9 108.3l.2 1.4M124.9 110.3h1.3M124.9 110.3a2.61 2.61 0 0 1-2 1.7M125 113.7h-7.8M125 110.3h1.2M125 108.4h1.2M125 110.2h1.2M125 108.5h1.2M125 110.1h1.2"/>
<path d="M125 108.6h1.2M125 113.6l-7.8 .1M125 110h1.2M125.1 113.6h-7.9M125.1 110h1.1M125.1 109.9h1.1M125.1 108.7h1.1M125.1 108.8h1.1M125.1 109.8h1.1M125.1 108.9h1.1M125.1 113.5l-7.9 .1M125.1 109.7h1.1"/>
<path d="M125.1 109h1.1M125.1 109.6h1.1M125.1 109.5h1.1M125.1 109.4h1.1M125.1 109.3h1.1M125.1 109.2h1.1M125.1 109.1h1.1M125.1 109.7l-.2 .6M125.2 113.5h-8M125.2 113.4l-8 .1M125.3 113.4h-8.1M125.3 113.3h-8.1"/>
<path d="M125.4 113.3h-8.2M125.4 113.2h-8.2M125.5 113.2h-8.3M125.6 113.1h-8.4M125.7 113h-8.5M125.7 112.9l-8.5 .1M125.8 112.9h-8.6M125.8 112.8l-8.6 .1M125.9 112.8h-8.7M125.9 112.7l-8.7 .1M126 112.7h-8.8M126 112.6h-8.8"/>
<path d="M126.1 112.6h-8.9M126.1 112.5h-8.9M126.2 112.5h-9M126.2 112.4v-8.4h-9v47.7h47.8v-47.7h-9.1v8.4M126.2 106.7h-9M126.2 112.4h-9M126.2 112.4l-4.3 4.3M155.9 101.6h9.1M155.9 101.5h9.1M155.9 101.4h9.1M155.9 101.3h9.1M155.9 101.2h9.1"/>
<path d="M155.9 101.1h9.1M155.9 101h9.1M155.9 100.9h9.1M155.9 100.8h9.1M155.9 100.7h9.1M155.9 100.6h9.1M155.9 100.5h9.1M155.9 100.4h9.1M155.9 100.3h9.1M155.9 100.2h9.1M155.9 100.1h9.1M155.9 100h9.1"/>
<path d="M155.9 111.9l9.1 .1M155.9 112.4h9.1M155.9 112.3h9.1M155.9 112.2h9.1M155.9 112.1h9.1M155.9 112h9.1M155.9 111.9h3.2M155.9 111.8l3 .1M155.9 111.8h2.8M155.9 111.7l2.7 .1M155.9 111.7h2.6M155.9 111.6l2.5 .1"/>
<path d="M155.9 111.6h2.4M155.9 111.5h2.3M155.9 111.5h2.2M155.9 111.4h2.2M155.9 111.3l2.1 .1M155.9 111.3h2M155.9 111.2l2 .1M155.9 111.2h1.9M155.9 111.1h1.9M155.9 111.1h1.8M155.9 111l1.7 .1M155.9 111h1.7"/>
<path d="M155.9 110.9l1.7 .1M155.9 110.9h1.6M155.9 110.8h1.6M155.9 110.8h1.5M155.9 110.7h1.5M155.9 110.6h1.5M155.9 110.6h1.4M155.9 110.5h1.4M155.9 110.4l1.4 .1M155.9 110.4h1.3M155.9 110.3l1.3 .1M155.9 110.3h1.3"/>
<path d="M155.9 110.2h1.3M155.9 110.1h1.2M155.9 110h1.2M155.9 109.9h1.2M155.9 109.8h1.2M155.9 109.7h1.1M155.9 109.6h1.1M155.9 109.5h1.1M155.9 109.4h1.1M155.9 109.3h1.1M155.9 109.2h1.1M155.9 109.1h1.1"/>
<path d="M155.9 109h1.1M155.9 108.9h1.1M155.9 108.8h1.2M155.9 108.6h1.2M155.9 108.5h1.3M155.9 108.4h1.3M155.9 108.3h1.3M155.9 108.2h1.3M155.9 106.6h9.1M155.9 106.5h9.1M155.9 106.4h9.1M155.9 106.3h9.1"/>
<path d="M155.9 106.2h9.1M155.9 106.1h9.1M155.9 106h9.1M155.9 105.9h9.1M155.9 105.8h9.1M155.9 105.7h9.1M155.9 105.6h9.1M155.9 105.5h9.1M155.9 105.4h9.1M155.9 105.3h9.1M155.9 105.2h9.1M155.9 105.1h9.1"/>
<path d="M155.9 105h9.1M155.9 104.9h9.1M155.9 104.8h9.1M155.9 104.7h9.1M155.9 104.6h9.1M155.9 104.5h9.1M155.9 104.4h9.1M155.9 104.3h9.1M155.9 104.2h9.1M155.9 104.1h9.1M155.9 104h9.1M155.9 112.4l4.3 4.3"/>
<path d="M156 112.5h9M156.1 112.6h8.9M156.2 112.7h8.8M156.3 112.8h8.7M156.4 112.9h8.6M156.5 113h8.5M156.5 113.1h8.5M156.6 113.1h8.4M156.7 113.2h8.3M156.8 113.3h8.2M156.9 113.4h8.1M157 113.5h8"/>
<path d="M157 109v.7M157 109.7l.2 .6M157.1 108.9h-1.2M157.1 113.6h7.9M157.1 108.7h-1.2M157.1 108.5l-1.2 .1M157.2 113.7h7.8M157.2 108.4h-1.3M157.2 108.3l-.2 .7M157.2 110.3a2.61 2.61 0 0 0 2.1 1.7M157.2 108.3h-1.3M157.3 113.8h7.7"/>
<path d="M157.3 108.2h-1.4M157.3 108.1h-1.4M157.4 108.1h-1.5M157.4 108h-1.5M157.4 113.9h7.6M157.4 107.9l-1.5 .1M157.4 107.9h-1.5M157.5 107.8l-1.6 .1M157.5 114h7.5M157.5 107.8h-1.6M157.5 107.7l-1.6 .1M157.6 107.7h-1.7"/>
<path d="M157.6 114.1h7.4M157.6 114.2h7.4M157.6 107.6l-1.7 .1M157.7 107.6h-1.8M157.7 114.2h7.3M157.7 107.5l-1.8 .1M157.8 114.3h7.2M157.8 107.5h-1.9M157.8 107.4l-1.9 .1M157.9 114.4h7.1M157.9 107.4h-2M158 114.5h7"/>
<path d="M158 107.3l-2.1 .1M158 107.3h-2.1M158.1 114.6h6.9M158.1 107.2l-2.2 .1M158.1 107.2h-2.2M158.2 114.7h6.8M158.3 107.1h-2.4M158.3 114.8h6.7M158.3 114.9h6.7M158.4 114.9h6.6M158.5 115h6.5M158.5 107h-2.6"/>
<path d="M158.6 115.1h6.4M158.6 106.9h-2.7M158.6 106.9l-1.1 .8-.3 .6M158.7 115.2h6.3M158.8 115.3h6.2M158.8 106.8l-2.9 .1M158.9 115.4h6.1M159 115.5h6M159 106.8h-3.1M159.1 115.6h5.9M159.2 115.7h5.8M159.2 106.7l-3.3 .1"/>
<path d="M159.3 115.8h5.7M159.3 106.7l-.7 .2M159.4 115.9h5.6M159.4 116h5.6M159.5 116h5.5M159.6 116.1h5.4M159.7 116.2h5.3M159.8 116.3h5.2M159.9 116.4h5.1M160 116.5h5M160 106.7l.7 .2M160.1 116.6h4.9"/>
<path d="M160.1 106.7h4.9M160.2 111.9h4.8M160.2 116.7h4.8M160.2 116.7l.2 .4M160.2 116.8h4.8M160.3 116.9h4.7M160.3 106.8h4.7M160.3 117h4.7M160.4 117.1v9.3M160.4 120h4.6M160.4 119.9h4.6M160.4 119.8h4.6"/>
<path d="M160.4 119.7h4.6M160.4 119.6h4.6M160.4 119.5h4.6M160.4 119.4h4.6M160.4 119.3h4.6M160.4 119.2h4.6M160.4 119.1h4.6M160.4 119h4.6M160.4 118.9h4.6M160.4 118.8h4.6M160.4 118.7h4.6M160.4 118.6h4.6"/>
<path d="M160.4 118.5h4.6M160.4 118.4h4.6M160.4 118.3h4.6M160.4 118.2h4.6M160.4 118.1h4.6M160.4 118h4.6M160.4 117.9h4.6M160.4 117.8h4.6M160.4 117.7h4.6M160.4 117.6h4.6M160.4 117.5h4.6M160.4 117.4h4.6"/>
<path d="M160.4 117.3h4.6M160.4 117.2h4.6M160.4 117.1h4.6M160.4 111.9h4.6M160.5 106.8h4.5M160.6 111.8h4.4M160.7 106.9h4.3M160.7 106.9l1.1 .8 .3 .6M160.7 111.8h4.3M160.8 107h4.2M160.8 111.7h4.2M160.9 111.7h4.1"/>
<path d="M161 107.1h4M161 111.6h4M161.1 111.5h3.9M161.1 107.2h3.9M161.2 111.5h3.8M161.2 107.2h3.8M161.2 111.4h3.8M161.2 111.4l-1.2 .6M161.3 107.3h3.7M161.3 111.4h3.7M161.4 111.3h3.6M161.4 107.4h3.6"/>
<path d="M161.5 111.2h3.5M161.5 107.5h3.5M161.6 111.1h3.4M161.6 107.6h3.4M161.7 111h3.3M161.7 107.7h3.3M161.8 107.7h3.2M161.8 110.9h3.2M161.8 110.8h3.2M161.8 107.8h3.2M161.9 110.7h3.1M161.9 107.9h3.1"/>
<path d="M161.9 108h3.1M161.9 110.6h3.1M161.9 108.1h3.1M162 110.6h3M162 108.1h3M162 110.5h3M162 108.2h3M162 110.4h3M162.1 110.4h2.9M162.1 108.3h2.9M162.1 110.3h2.9M162.1 108.3l.2 .7"/>
<path d="M162.1 110.3l-.9 1.1M162.1 110.2h2.9M162.1 108.4h2.9M162.1 108.5h2.9M162.2 110.1h2.8M162.2 108.6h2.8M162.2 108.5h2.8M162.2 110h2.8M162.2 109.9h2.8M162.2 108.8h2.8M162.2 108.7h2.8M162.2 109.8h2.8"/>
<path d="M162.2 109.7h2.8M162.2 108.9h2.8M162.3 109v.7M162.3 109.7h2.7M162.3 109.6h2.7M162.3 109.5h2.7M162.3 109.4h2.7M162.3 109.3h2.7M162.3 109.2h2.7M162.3 109.1h2.7M162.3 109h2.7M162.3 109.7l-.2 .6"/>
<path d="M165 106.7h-9.1M167 101.6h9.1M167 101.5h9.1M167 101.4h9.1M167 101.3h9.1M167 101.2h9.1M167 101.1h9.1M167 101h9.1M167 100.9h9.1M167 100.8h9.1M167 100.7h9.1M167 100.6h9.1"/>
<path d="M167 100.5h9.1M167 100.4h9.1M167 100.3h9.1M167 100.2h9.1M167 100.1h9.1M167 100h9.1M167 111.9l9.1 .1M167 120h4.6M167 119.9h4.6M167 119.8h4.6M167 119.7h4.6M167 119.6h4.6"/>
<path d="M167 119.5h4.6M167 119.4h4.6M167 119.3h4.6M167 119.2h4.6M167 119.1h4.6M167 119h4.6M167 118.9h4.6M167 118.8h4.6M167 118.7h4.6M167 118.6h4.6M167 118.5h4.6M167 118.4h4.6"/>
<path d="M167 118.3h4.6M167 118.2h4.6M167 118.1h4.6M167 118h4.6M167 117.9h4.6M167 117.8h4.6M167 117.7h4.6M167 117.6h4.6M167 117.5h4.6M167 117.4h4.6M167 117.3h4.6M167 117.2h4.6"/>
<path d="M167 117.1h4.6M167 112.4h9.1M167 112.3h9.1M167 112.2h9.1M167 112.1h9.1M167 112h9.1M167 111.9h4.8M167 111.8l4.6 .1M167 111.8h4.4M167 111.7l4.3 .1M167 111.7h4.2M167 111.6l4.1 .1"/>
<path d="M167 111.6h4M167 111.5h3.9M167 111.5h3.8M167 111.4h3.7M167 111.3l3.7 .1M167 111.3h3.6M167 111.2l3.6 .1M167 111.2h3.5M167 111.1l3.5 .1M167 111.1h3.4M167 111l3.3 .1M167 111h3.3"/>
<path d="M167 110.9l3.2 .1M167 110.9h3.2M167 110.8h3.2M167 110.8h3.1M167 110.7h3.1M167 110.6h3.1M167 110.6h3M167 110.5h3M167 110.4l3 .1M167 110.4h2.9M167 110.3l2.9 .1M167 110.3h2.9"/>
<path d="M167 110.2h2.9M167 110.1h2.8M167 110h2.8M167 109.9h2.8M167 109.8h2.8M167 109.7h2.7M167 109.6h2.7M167 109.5h2.7M167 109.4h2.7M167 109.3h2.7M167 109.2h2.7M167 109.1h2.7"/>
<path d="M167 109h2.7M167 108.9h2.7M167 108.9h2.8M167 108.8h2.8M167 108.6h2.8M167 108.5h2.8M167 108.4h2.9M167 108.3h2.9M167 107.9h3.1M167 106.6h9.1M167 106.5h9.1M167 106.4h9.1"/>
<path d="M167 106.3h9.1M167 106.2h9.1M167 106.1h9.1M167 106h9.1M167 105.9h9.1M167 105.8h9.1M167 105.7h9.1M167 105.6h9.1M167 105.5h9.1M167 105.4h9.1M167 105.3h9.1M167 105.2h9.1"/>
<path d="M167 105.1h9.1M167 105h9.1M167 104.9h9.1M167 104.8h9.1M167 104.7h9.1M167 104.6h9.1M167 104.5h9.1M167 104.4h9.1M167 104.3h9.1M167 104.2h9.1M167 104.1h9.1M167 104h9.1"/>
<path d="M169.7 109v.7M169.7 109.7l.2 .6M169.8 108.7h-2.8M169.8 108.5l-2.8 .1M169.9 108.4h-2.9M169.9 108.3l-.2 .7M169.9 110.3l.3 .7M169.9 108.3h-2.9M169.9 108.2h-2.9M170 108.2h-3M170 108.1h-3M170.1 108.1h-3.1"/>
<path d="M170.1 108h-3.1M170.1 107.9l-3.1 .1M170.2 107.8l-3.2 .1M170.2 107.8h-3.2M170.2 107.7l-3.2 .1M170.2 107.7l-.3 .6M170.2 111l.5 .4M170.3 107.7h-3.3M170.3 107.6l-3.3 .1M170.4 107.6h-3.4M170.4 107.5l-3.4 .1M170.5 107.5h-3.5"/>
<path d="M170.5 107.4l-3.5 .1M170.6 107.4h-3.6M170.6 107.3l-3.6 .1M170.7 107.3h-3.7M170.7 111.4l1.3 .6M170.8 107.2l-3.8 .1M170.8 107.2h-3.8M171 107.1h-4M171.2 107h-4.2M171.3 106.9h-4.3M171.3 106.9l-1.1 .8M171.5 106.8l-4.5 .1"/>
<path d="M171.6 117.1v9.3M171.7 117h-4.7M171.7 116.9h-4.7M171.7 106.8h-4.7M171.7 116.8h-4.7M171.8 116.8h-4.8M171.8 116.7h-4.8M171.8 116.7l-.2 .4M171.8 116.6l-4.8 .1M171.9 116.6h-4.9M171.9 106.7l-4.9 .1M171.9 116.5l-4.9 .1"/>
<path d="M172 116.5h-5M172 106.7l-.7 .2M172 116.4l-5 .1M172.1 116.4h-5.1M172.1 116.3l-5.1 .1M172.2 116.3h-5.2M172.3 116.2h-5.3M172.4 116.1h-5.4M172.5 116h-5.5M172.6 115.9h-5.6M172.6 115.8l-5.6 .1M172.7 115.8h-5.7"/>
<path d="M172.7 106.7l.7 .2M172.7 115.7l-5.7 .1M172.8 115.7h-5.8M172.8 106.7h3.3M172.8 115.6l-5.8 .1M172.9 111.9h3.2M172.9 115.6h-5.9M173 115.5l-6 .1M173 106.8h3.1M173 115.5h-6M173.1 115.4l-6.1 .1M173.1 111.9h3"/>
<path d="M173.1 115.4h-6.1M173.2 115.3l-6.2 .1M173.2 115.3h-6.2M173.2 106.8h2.9M173.3 115.2l-6.3 .1M173.3 111.8h2.8M173.3 115.2h-6.3M173.4 106.9h2.7M173.4 106.9l1 .8M173.4 115.1h-6.4M173.4 111.8h2.7M173.5 107h2.6"/>
<path d="M173.5 115h-6.5M173.5 111.7h2.6M173.6 111.7h2.5M173.6 114.9h-6.6M173.7 107.1h2.4M173.7 111.6h2.4M173.7 114.8h-6.7M173.7 114.7l-6.7 .1M173.8 111.5h2.3M173.8 114.7h-6.8M173.8 114.6l-6.8 .1M173.8 107.2h2.3"/>
<path d="M173.9 111.5h2.2M173.9 114.6h-6.9M173.9 107.2h2.2M173.9 114.5l-6.9 .1M173.9 111.4h2.2M173.9 111.4l-1.2 .6M174 107.3h2.1M174 114.5h-7M174 111.4h2.1M174.1 114.4h-7.1M174.1 111.3h2M174.1 107.4h2"/>
<path d="M174.2 114.3h-7.2M174.2 111.2h1.9M174.2 107.5h1.9M174.3 114.2h-7.3M174.3 111.1h1.8M174.3 107.6h1.8M174.4 114.1h-7.4M174.4 111h1.7M174.4 107.7h1.7M174.4 114l-7.4 .1M174.4 107.7l.4 .6M174.4 111l-.5 .4"/>
<path d="M174.5 107.7h1.6M174.5 114h-7.5M174.5 110.9h1.6M174.5 110.8h1.6M174.5 107.8h1.6M174.5 113.9l-7.5 .1M174.5 107.9h1.6M174.6 110.7h1.5M174.6 107.9h1.5M174.6 113.9h-7.6M174.6 108h1.5M174.6 110.6h1.5"/>
<path d="M174.6 113.8l-7.6 .1M174.6 108.1h1.5M174.7 108.1h1.4M174.7 113.8h-7.7M174.7 110.5h1.4M174.7 108.2h1.4M174.7 110.4h1.4M174.8 113.7l-7.8 .1M174.8 110.4h1.3M174.8 108.3h1.3M174.8 113.7h-7.8M174.8 110.3h1.3"/>
<path d="M174.8 108.4h1.3M174.8 108.3l.2 .7M174.8 110.2h1.3M174.8 108.5h1.3M174.9 113.6l-7.9 .1M174.9 110.1h1.2M174.9 108.6h1.2M174.9 108.5h1.2M174.9 110h1.2M174.9 108.7h1.2M174.9 113.6h-7.9M174.9 109.9h1.2"/>
<path d="M174.9 108.8h1.2M174.9 109.8h1.2M174.9 109.7h1.2M174.9 108.9h1.2M175 109v.7M175 113.5l-8 .1M175 109.7h1.1M175 109.6h1.1M175 109.5h1.1M175 109.4h1.1M175 109.3h1.1M175 109.2h1.1"/>
<path d="M175 109.1h1.1M175 109h1.1M175 109.7l-.6 1.3M175 113.5h-8M175.1 113.4l-8.1 .1M175.1 113.4h-8.1M175.2 113.3h-8.2M175.3 113.2h-8.3M175.4 113.1h-8.4M175.5 113h-8.5M175.5 112.9l-8.5 .1M175.6 112.9h-8.6"/>
<path d="M175.6 112.8l-8.6 .1M175.7 112.8h-8.7M175.7 112.7l-8.7 .1M175.8 112.7h-8.8M175.9 112.6h-8.9M176 112.5h-9M176.1 112.4h-9.1M176.1 112.4v-8.4h-9.1v47.7h47.8v-47.7h-9.1v8.4M176.1 106.7h-9.1M176.1 112.4l-4.3 4.3M205.7 101.6h9.1M205.7 101.5h9.1"/>
<path d="M205.7 101.4h9.1M205.7 101.3h9.1M205.7 101.2h9.1M205.7 101.1h9.1M205.7 101h9.1M205.7 100.9h9.1M205.7 100.8h9.1M205.7 100.7h9.1M205.7 100.6h9.1M205.7 100.5h9.1M205.7 100.4h9.1M205.7 100.3h9.1"/>
<path d="M205.7 100.2h9.1M205.7 100.1h9.1M205.7 100h9.1M205.7 111.9l9.1 .1M205.7 112.4h9.1M205.7 112.3h9.1M205.7 112.2h9.1M205.7 112.1h9.1M205.7 112h9.1M205.7 111.9h3.3M205.7 111.8l3.1 .1M205.7 111.8h2.8"/>
<path d="M205.7 111.7l2.7 .1M205.7 111.7h2.6M205.7 111.6l2.6 .1M205.7 111.6h2.5M205.7 111.5h2.3M205.7 111.5h2.2M205.7 111.4h2.2M205.7 111.3l2.1 .1M205.7 111.3h2.1M205.7 111.2l2 .1M205.7 111.2h1.9M205.7 111.1l1.9 .1"/>
<path d="M205.7 111.1h1.8M205.7 111l1.8 .1M205.7 111h1.7M205.7 110.9l1.7 .1M205.7 110.9h1.6M205.7 110.8h1.6M205.7 110.7h1.6M205.7 110.7h1.5M205.7 110.6h1.5M205.7 110.5h1.4M205.7 110.4h1.4M205.7 110.3l1.4 .1"/>
<path d="M205.7 110.3h1.3M205.7 110.2h1.3M205.7 110.1l1.3 .1M205.7 110.1h1.3M205.7 110h1.2M205.7 109.9h1.2M205.7 109.8h1.2M205.7 109.7h1.2M205.7 109.6h1.2M205.7 109.5h1.2M205.7 109.4h1.2M205.7 109.3h1.2"/>
<path d="M205.7 109.2h1.2M205.7 109.1h1.2M205.7 109h1.2M205.7 108.9h1.2M205.7 108.8h1.2M205.7 108.7h1.2M205.7 108.6h1.2M205.7 108.5h1.3M205.7 108.4h1.3M205.7 108.3h1.3M205.7 108h1.5M205.7 107.9h1.6"/>
<path d="M205.7 107.8h1.6M205.7 107.6h1.8M205.7 107.3h2.1M205.7 106.6h9.1M205.7 106.5h9.1M205.7 106.4h9.1M205.7 106.3h9.1M205.7 106.2h9.1M205.7 106.1h9.1M205.7 106h9.1M205.7 105.9h9.1M205.7 105.8h9.1"/>
<path d="M205.7 105.7h9.1M205.7 105.6h9.1M205.7 105.5h9.1M205.7 105.4h9.1M205.7 105.3h9.1M205.7 105.2h9.1M205.7 105.1h9.1M205.7 105h9.1M205.7 104.9h9.1M205.7 104.8h9.1M205.7 104.7h9.1M205.7 104.6h9.1"/>
<path d="M205.7 104.5h9.1M205.7 104.4h9.1M205.7 104.3h9.1M205.7 104.2h9.1M205.7 104.1h9.1M205.7 104h9.1M205.7 112.4l4.3 4.3M205.8 112.4h9M205.8 112.5h9M205.9 112.6h8.9M206 112.6h8.8M206 112.7h8.8"/>
<path d="M206.1 112.7h8.7M206.1 112.8h8.7M206.2 112.8h8.6M206.2 112.9h8.6M206.3 112.9h8.5M206.3 113h8.5M206.4 113.1h8.4M206.5 113.2h8.3M206.6 113.3h8.2M206.7 113.3h8.1M206.7 113.4h8.1M206.8 113.5h8"/>
<path d="M206.9 109v.7M206.9 113.5h7.9M206.9 109.7l.1 .6M206.9 108.9h-1.2M206.9 113.6h7.9M206.9 108.8h-1.2M207 113.6h7.8M207 108.6h-1.3M207 108.4l-1.3 .1M207 113.7h7.8M207 108.3l-.1 .7M207 110.3l.9 1.1"/>
<path d="M207.1 113.7h7.7M207.1 108.3h-1.4M207.1 108.2h-1.4M207.1 113.8h7.7M207.2 108.1h-1.5M207.2 113.8h7.6M207.2 113.9h7.6M207.2 107.9l-1.5 .1M207.3 113.9h7.5M207.3 107.8l-1.6 .1M207.3 114h7.5M207.4 114h7.4"/>
<path d="M207.4 107.7l-1.7 .1M207.4 107.7h-1.7M207.4 114.1h7.4M207.5 107.6l-1.8 .1M207.5 114.2h7.3M207.6 114.2h7.2M207.6 107.5l-1.9 .1M207.6 114.3h7.2M207.6 107.5h-1.9M207.7 114.3h7.1M207.7 114.4h7.1M207.7 107.4l-2 .1"/>
<path d="M207.7 107.4h-2M207.8 114.4h7M207.8 107.3h-2.1M207.8 114.5h7M207.9 114.5h6.9M207.9 111.4l1.2 .6M207.9 114.6h6.9M207.9 107.2l-2.2 .1M208 114.6h6.8M208 107.2h-2.3M208 114.7h6.8M208.1 114.7h6.7"/>
<path d="M208.1 107.1h-2.4M208.1 114.8h6.7M208.2 107.1h-2.5M208.2 114.9h6.6M208.3 115h6.5M208.3 107h-2.6M208.4 107h-2.7M208.4 115.1h6.4M208.5 106.9h-2.8M208.5 106.9l-1.1 .8-.4 .6M208.5 115.2h6.3M208.6 115.2h6.2"/>
<path d="M208.6 115.3h6.2M208.6 106.8l-2.9 .1M208.7 115.4h6.1M208.8 115.4h6M208.8 115.5h6M208.9 106.8h-3.2M208.9 115.5h5.9M208.9 115.6h5.9M209 115.6h5.8M209 115.7h5.8M209 106.7l-3.3 .1M209.1 115.7h5.7"/>
<path d="M209.1 106.7l-.6 .2M209.1 115.8h5.7M209.2 115.8h5.6M209.3 115.9h5.5M209.3 116h5.5M209.4 116.1h5.4M209.5 116.1h5.3M209.5 116.2h5.3M209.6 116.2h5.2M209.6 116.3h5.2M209.7 116.3h5.1M209.7 116.4h5.1"/>
<path d="M209.8 116.4h5M209.8 116.5h5M209.8 106.7l.7 .2M209.9 116.5h4.9M209.9 116.6h4.9M209.9 106.7h4.9M210 116.6h4.8M210 111.9h4.8M210 116.7h4.8M210 116.7l.2 .4M210.1 116.8h4.7M210.1 116.9h4.7"/>
<path d="M210.1 106.8h4.7M210.1 117h4.7M210.2 117h4.6M210.2 117.1v9.3M210.2 120h4.6M210.2 119.9h4.6M210.2 119.8h4.6M210.2 119.7h4.6M210.2 119.6h4.6M210.2 119.5h4.6M210.2 119.4h4.6M210.2 119.3h4.6"/>
<path d="M210.2 119.2h4.6M210.2 119.1h4.6M210.2 119h4.6M210.2 118.9h4.6M210.2 118.8h4.6M210.2 118.7h4.6M210.2 118.6h4.6M210.2 118.5h4.6M210.2 118.4h4.6M210.2 118.3h4.6M210.2 118.2h4.6M210.2 118.1h4.6"/>
<path d="M210.2 118h4.6M210.2 117.9h4.6M210.2 117.8h4.6M210.2 117.7h4.6M210.2 117.6h4.6M210.2 117.5h4.6M210.2 117.4h4.6M210.2 117.3h4.6M210.2 117.2h4.6M210.2 117.1h4.6M210.2 111.9h4.6M210.4 106.8h4.4"/>
<path d="M210.4 111.8h4.4M210.5 106.9h4.3M210.5 106.9l.6 .3 .8 1.1M210.5 111.8h4.3M210.6 107h4.2M210.7 111.7h4.1M210.7 107h4.1M210.8 107.1h4M210.8 111.6h4M210.9 107.1h3.9M210.9 111.5h3.9M211 107.2h3.8"/>
<path d="M211 111.5h3.8M211.1 107.2h3.7M211.1 111.4h3.7M211.1 107.3h3.7M211.2 111.4h3.6M211.2 107.3h3.6M211.2 111.3h3.6M211.2 107.4h3.6M211.3 111.3h3.5M211.3 107.4h3.5M211.3 111.2h3.5M211.3 107.5h3.5"/>
<path d="M211.4 111.2h3.4M211.4 107.5h3.4M211.4 111.1h3.4M211.5 107.6h3.3M211.5 111.1h3.3M211.5 111h3.3M211.6 107.7h3.2M211.6 110.9h3.2M211.6 111l-.5 .4-1.3 .6M211.6 107.8h3.2M211.6 110.8h3.2M211.7 110.8h3.1"/>
<path d="M211.7 107.9h3.1M211.7 110.7h3.1M211.8 110.6h3M211.8 108h3M211.8 108.1h3M211.8 110.5h3M211.8 108.2h3M211.9 110.5h2.9M211.9 110.4h2.9M211.9 108.2h2.9M211.9 108.3h2.9M211.9 110.3h2.9"/>
<path d="M211.9 108.4h2.9M211.9 108.3l.2 .7M212 110.2h2.8M212 108.5h2.8M212 108.4h2.8M212 110.1h2.8M212 110h2.8M212 108.6h2.8M212 108.7h2.8M212 109.9h2.8M212 108.8h2.8M212.1 109.8h2.7"/>
<path d="M212.1 108.9h2.7M212.1 109.7h2.7M212.1 109v.7M212.1 109.6h2.7M212.1 109.5h2.7M212.1 109.4h2.7M212.1 109.3h2.7M212.1 109.2h2.7M212.1 109.1h2.7M212.1 109h2.7M212.1 109.7l-.5 1.3M214.8 106.7h-9.1"/>
<path d="M67.4 135.6l33.6 .1M67.4 127.2h14.4l-.2 .5M67.4 129.9l28.3 .1M67.4 129.8l15.5 .1M67.4 135h28.3M67.4 134.9h15.4M67.4 140h10.7M67.4 139.9h10.7M67.4 139.8h10.7M67.4 139.7h10.7M67.4 139.6h10.7M67.4 139.5h10.7"/>
<path d="M67.4 139.4h10.7M67.4 139.3h10.7M67.4 137.9h33.6M67.4 137.8h33.6M67.4 137.7h33.6M67.4 137.6h33.6M67.4 137.5h33.6M67.4 137.4h33.6M67.4 137.3h33.6M67.4 137.2h33.6M67.4 137.1h33.6M67.4 137h33.6"/>
<path d="M67.4 136.9h33.6M67.4 136.8h33.6M67.4 136.7h33.6M67.4 136.6h33.6M67.4 136.5h33.6M67.4 136.4h33.6M67.4 136.3h33.6M67.4 136.2h33.6M67.4 136.1h33.6M67.4 136h33.6M67.4 135.9h33.6M67.4 135.8h33.6"/>
<path d="M67.4 135.7h33.6M67.4 135.6h29.2M67.4 135.5l29.1 .1M67.4 135.5h28.9M67.4 135.4h28.8M67.4 135.4h28.7M67.4 135.3h28.6M67.4 135.3h28.5M67.4 135.2h28.5M67.4 135.1h28.4M67.4 135l28.3 .1M67.4 134.9l15.5 .1"/>
<path d="M67.4 134.8l15.3 .1M67.4 134.8h15.2M67.4 134.7h15M67.4 134.6h14.9M67.4 134.5h14.8M67.4 134.5h14.7M67.4 134.4h14.7M67.4 134.3l14.6 .1M67.4 134.3h14.6M67.4 134.2l14.5 .1M67.4 134.2h14.5M67.4 134.1l14.5 .1"/>
<path d="M67.4 134.1h14.4M67.4 134l14.4 .1M67.4 134h14.4M67.4 133.9h14.3M67.4 133.8h14.3M67.4 133.7h14.3M67.4 133.7h14.2M67.4 133.6h14.2M67.4 133.5h14.2M67.4 133.4h14.2M67.4 133.3h14.2M67.4 133.2h14.2"/>
<path d="M67.4 133.1h14.2M67.4 133h14.2M67.4 132.9h14.2M67.4 132.8h14.2M67.4 132.3h14.4M67.4 132.2h14.4M67.4 132.1h14.5M67.4 131h28.5M67.4 130.8h28.7M67.4 130.7h28.7M67.4 130.6h28.7M67.4 130.5h28.7"/>
<path d="M67.4 130.4h28.7M67.4 130.3h28.7M67.4 130.2h28.6M67.4 130.2h28.5M67.4 130.1h28.5M67.4 130l28.4 .1M67.4 130h28.4M67.4 129.9h15.6M67.4 129.8h15.4M67.4 129.7l15.3 .1M67.4 129.7h15.1M67.4 129.6l15 .1"/>
<path d="M67.4 129.6h14.9M67.4 129.5l14.9 .1M67.4 129.5h14.8M67.4 129.4h14.8M67.4 129.4h14.7M67.4 129.3h14.7M67.4 129.3h14.6M67.4 129.2h14.6M67.4 129.2h14.5M67.4 129.1h14.5M67.4 129.1h14.4M67.4 129h14.4"/>
<path d="M67.4 128.9h14.4M67.4 128.8h14.3M67.4 128.7h14.3M67.4 128.6l14.3 .1M67.4 128.6h14.2M67.4 128.5h14.2M67.4 128.4h14.2M67.4 128.3h14.2M67.4 128.2h14.2M67.4 128.1h14.2M67.4 128h14.2M67.4 127.9h14.2"/>
<path d="M67.4 127.8h14.2M67.4 127.7h14.2M67.4 127.5h14.3M67.4 127.4h14.3M67.4 127.3h14.3M67.4 127.1l5.3 .1M67.4 127.1h5.2M67.4 127l5.1 .1M67.4 127h5M67.4 126.9l4.9 .1M67.4 126.9h4.9M67.4 126.8h4.8"/>
<path d="M67.4 126.7h4.7M67.4 126.6h4.7M67.4 126.5h4.6M67.4 126.4l4.6 .1M67.4 126.4h4.6M67.4 126.3h4.6M67.4 126.2h4.6M67.4 126.1h4.6M67.4 126h4.6M67.4 125.9h4.6M67.4 125.8h4.6M67.4 125.7h4.6"/>
<path d="M67.4 125.6h4.6M67.4 125.5h4.6M67.4 125.4h4.6M67.4 125.3h4.6M67.4 125.2h4.6M67.4 125.1h4.6M67.4 125h4.6M67.4 124.9h4.6M67.4 124.8h4.6M67.4 124.7h4.6M67.4 124.6h4.6M67.4 124.5h4.6"/>
<path d="M67.4 124.4h4.6M67.4 124.3h4.6M67.4 124.2h4.6M67.4 124.1h4.6M67.4 124h4.6M67.4 123.9h4.6M67.4 123.8h4.6M67.4 123.7h4.6M67.4 123.6h4.6M67.4 123.5h4.6M67.4 123.4h4.6M67.4 123.3h4.6"/>
<path d="M67.4 123.2h4.6M67.4 123.1h4.6M67.4 123h4.6M67.4 122.9h4.6M67.4 122.8h4.6M67.4 122.7h4.6M67.4 122.6h4.6M67.4 122.5h4.6M67.4 122.4h4.6M67.4 122.3h4.6M67.4 122.2h4.6M67.4 122.1h4.6"/>
<path d="M67.4 122h4.6M67.4 121.9h4.6M67.4 121.8h4.6M67.4 121.7h4.6M67.4 121.6h4.6M67.4 121.5h4.6M67.4 121.4h4.6M67.4 121.3h4.6M67.4 121.2h4.6M67.4 121.1h4.6M67.4 121h4.6M67.4 120.9h4.6"/>
<path d="M67.4 120.8h4.6M67.4 120.7h4.6M67.4 120.6h4.6M67.4 120.5h4.6M67.4 120.4h4.6M67.4 120.3h4.6M67.4 120.2h4.6M67.4 120.1h4.6M72 126.4l.1 .3M72.1 126.7l.3 .3M72.4 127l.4 .2M78.1 139.4h-10.7"/>
<path d="M78.1 139.3h-10.7M78.2 139.2l-10.8 .1M78.2 139.2h-10.8M78.2 139.1h-10.8M78.3 139h-10.9M78.3 138.9h-10.9M78.3 138.8h-10.9M78.4 138.7l-.3 .7v2.1M78.4 138.7l-11 .1M78.4 138.7h-11M78.5 138.6l-11.1 .1M78.5 138.6h-11.1"/>
<path d="M78.6 138.5l-11.2 .1M78.6 138.5h-11.2M78.7 138.4l-11.3 .1M78.7 138.4h-11.3M78.8 138.3l-11.4 .1M78.8 138.3h-11.4M78.9 138.2l-.5 .5M78.9 138.2l-11.5 .1M79 138.2h-11.6M79.1 138.1l-11.7 .1M79.2 138.1h-11.8M79.4 138h-12"/>
<path d="M79.5 138h-12.1M79.6 137.9l-.7 .3M80.3 137.9l.7 .3M80.4 138h20.6M80.5 138h20.5M80.7 138.1h20.3M80.8 138.1h20.2M80.9 138.2h20.1M81 138.2l.6 .5M81 138.2h20M81.1 138.3h19.9M81.2 138.3h19.8"/>
<path d="M81.2 138.4h19.8M81.3 138.5h19.7M81.4 138.5h19.6M81.4 138.6h19.6M81.5 138.6h19.5M81.5 138.7h19.5M81.6 138.7l.3 .7M81.6 138.7h19.4M81.6 127.7v.7M81.6 132.8v.7M81.6 128.4l.3 .7M81.6 133.5l.3 .7 .5 .5 .7 .3"/>
<path d="M81.6 138.8h19.4M81.6 132.7h-14.2M81.6 127.6l-14.2 .1M81.6 138.9h19.4M81.6 127.6h-14.2M81.6 132.6h-14.2M81.6 127.5l-14.2 .1M81.7 139h19.3M81.7 132.5l-14.3 .1M81.7 132.5h-14.3M81.7 127.4h-14.3M81.7 139.1h19.3"/>
<path d="M81.7 132.4l-14.3 .1M81.7 132.4h-14.3M81.7 127.3h-14.3M81.7 132.3l-14.3 .1M81.8 139.2h19.2M81.8 139.3h19.2M81.8 132.2l-14.4 .1M81.8 139.4h19.2M81.8 132.1l-14.4 .1M81.9 129.1l.5 .6 .7 .2M81.9 132.1l-.3 .7M81.9 139.4v2.1"/>
<path d="M81.9 140h19M81.9 139.9h19M81.9 139.8h19M81.9 139.7h19M81.9 139.6h19M81.9 139.5h19M81.9 139.4h19M81.9 132l-14.5 .1M82 132h-14.6M82 131.9l-14.6 .1M82.1 131.9h-14.7M82.1 131.8h-14.7"/>
<path d="M82.2 131.8h-14.8M82.2 131.7h-14.8M82.3 131.7h-14.9M82.3 131.6h-14.9M82.4 131.6l-.5 .5M82.4 131.6h-15M82.5 131.5h-15.1M82.7 131.4l-15.3 .1M82.8 131.4h-15.4M82.9 131.3l-15.5 .1M83 131.3h-15.6M83.1 131.3l-.7 .3"/>
<path d="M84.3 129.9v.1M85.1 135l.3-.1h10.2l.4 .5M85.1 131.3h10.6M85.2 129.9h10.5M85.3 135h10.3M85.3 129.9h10.3M85.3 131.3h10.3M85.4 129.8l-.3 .2M92.5 134.9h.1M93.2 134.9h.1M95.6 129.8l.4 .5M95.7 131.2l-28.3 .1"/>
<path d="M95.8 131.2h-28.4M95.8 131.1h-28.4M95.9 131.1h-28.5M96 131h-28.6M96 130.3h.1M96 130.9l-.4 .5h-10.2l-.3-.1M96 135.4l.7 .3M96 130.9h-28.6M96.1 130.3v.6M96.1 130.9h-.1M96.1 130.9h-28.7M97.6 135.6h2.2"/>
<path d="M97.7 135.6h1.9M97.9 135.5h1.6M98 135.4h1.4M98.1 135.4h1.1M98.2 135.4l.4-.5 .6 .5M98.2 135.4l-.7 .3M98.2 135.3h1M98.3 135.3h.8M98.3 135.2h.8M98.4 135.2h.6M98.4 135.1h.6M98.5 135.1h.4"/>
<path d="M98.5 135h.4M98.6 135h.2M99.2 135.4l.7 .3M100.8 135.6h.2M100.9 135.6h.1M101 139.1l-.1 2.4M101 135.5l-.4 .2M101 135.5v3.6M101 137.9h-33.6M101 139.2h-19.3M101 135.5h.1M104.6 135.6l10.5 .1"/>
<path d="M104.6 135h1.9M104.6 134.9h1.8M104.6 139.1l.1 .3v2.1l-.3 .7M104.6 132.6v6.5M104.6 137.9h10.5M104.6 139.1h10.5M104.6 139h10.5M104.6 138.9h10.5M104.6 138.8h10.5M104.6 138.7h10.5M104.6 138.6h10.5M104.6 138.5h10.5"/>
<path d="M104.6 138.4h10.5M104.6 138.3h10.5M104.6 138.2h10.5M104.6 138.1h10.5M104.6 138h10.5M104.6 137.8h10.5M104.6 137.7h10.5M104.6 137.6h10.5M104.6 137.5h10.5M104.6 137.4h10.5M104.6 137.3h10.5M104.6 137.2h10.5"/>
<path d="M104.6 137.1h10.5M104.6 137h10.5M104.6 136.9h10.5M104.6 136.8h10.5M104.6 136.7h10.5M104.6 136.6h10.5M104.6 136.5h10.5M104.6 136.4h10.5M104.6 136.3h10.5M104.6 136.2h10.5M104.6 136.1h10.5M104.6 136h10.5"/>
<path d="M104.6 135.9h10.5M104.6 135.8h10.5M104.6 135.7h10.5M104.6 135.6h2.8M104.6 135.5l2.7 .1M104.6 135.5h2.5M104.6 135.4h2.4M104.6 135.4h2.2M104.6 135.3h2.2M104.6 135.3h2.1M104.6 135.2h2.1M104.6 135.1h2"/>
<path d="M104.6 135l1.9 .1M104.6 134.9l1.8 .1M104.6 134.8h1.7M104.6 134.7h1.7M104.6 134.7h1.6M104.6 134.6h1.6M104.6 134.5h1.6M104.6 134.4h1.5M104.6 134.3l1.5 .1M104.6 134.3h1.5M104.6 134.2l1.5 .1M104.6 134.2h1.4"/>
<path d="M104.6 134.1l1.4 .1M104.6 134.1h1.4M104.6 134h1.4M104.6 133.9h1.4M104.6 133.8h1.4M104.6 133.7h1.4M104.6 133.6h1.4M104.6 133.5h1.4M104.6 133.4h1.4M104.6 133.3h1.4M104.6 133.2h1.4M104.6 133.1h1.4"/>
<path d="M104.6 133h1.4M104.6 132.9h1.4M104.6 132.8h1.4M104.6 132.7h1.4M104.6 132.6h1.4M104.6 139.2h10.5M104.6 139.3h10.5M104.6 132.5h1.4M104.7 139.3h10.4M104.7 139.4h10.4M104.7 132.5h1.3M104.7 140h10.4"/>
<path d="M104.7 139.9h10.4M104.7 139.8h10.4M104.7 139.7h10.4M104.7 139.6h10.4M104.7 139.5h10.4M104.8 132.4h1.2M104.9 132.3h1.1M105 132.2h1M105.2 132h.9M105.3 131.8h.8M105.4 131.8h.7M105.5 131.7h.6"/>
<path d="M105.5 131.6h.6M105.6 131.6h.5M105.6 131.5h.5M105.7 131.5h.4M105.8 131.4h.3M105.8 131.3h.3M105.9 131.3h.2M106 131.2h.1M106 132.1v2.1M106 134.2l.3 .7M106 132.1l-1 .1M106 131.1h.1"/>
<path d="M106 132.1h-.9M106.1 132h-1M106.1 131.1h.1M106.1 131.9l-.9 .1M106.1 131.8v-.8l-1.5 1.6M106.1 131.8l-.1 .3M106.1 131.9h-.8M106.3 134.9l.5 .5 .7 .3M108.4 135.6h6.7M108.5 135.6h6.6M108.7 135.5h6.4M108.8 135.4h6.3"/>
<path d="M108.9 135.4h6.2M109 135.3h6.1M109.1 135.3h6M109.1 135.2h6M109.2 135.2h5.9M109.2 135.1h5.9M109.3 135.1h5.8M109.3 135h5.8M109.4 135h5.7M109.4 134.9h5.7M109.5 134.9l-.5 .5-.7 .3M109.5 134.8h5.6"/>
<path d="M109.5 134.7h5.6M109.6 134.7h5.5M109.6 134.6h5.5M109.6 134.5h5.5M109.7 131.8l.1 .3M109.7 129.4v2.4M109.7 129.9h5.4M109.7 129.8h5.4M109.7 131.4h5.4M109.7 131.2h5.4M109.7 134.4h5.4M109.7 131.8h5.4"/>
<path d="M109.7 131.7h5.4M109.7 131.6h5.4M109.7 131.5h5.4M109.7 131.3h5.4M109.7 131.1h5.4M109.7 131h5.4M109.7 130.9h5.4M109.7 130.8h5.4M109.7 130.7h5.4M109.7 130.6h5.4M109.7 130.5h5.4M109.7 130.4h5.4"/>
<path d="M109.7 130.3h5.4M109.7 130.2h5.4M109.7 130.1h5.4M109.7 130h5.4M109.7 129.7h5.4M109.7 129.6h5.4M109.7 129.5h5.4M109.7 129.4h5.4M109.7 129.3h5.4M109.7 131.9h5.4M109.7 134.3h5.4M109.7 129.2h5.4"/>
<path d="M109.7 132h5.4M109.8 134.2h5.3M109.8 132.1h5.3M109.8 129.1h5.3M109.8 134.2l-.3 .7M109.8 127.1v2M109.8 132.1v2.1M109.8 129.1l-.1 .3M109.8 127.2h5.3M109.8 134.1h5.3M109.8 134h5.3M109.8 133.9h5.3"/>
<path d="M109.8 133.8h5.3M109.8 133.7h5.3M109.8 133.6h5.3M109.8 133.5h5.3M109.8 133.4h5.3M109.8 133.3h5.3M109.8 133.2h5.3M109.8 133.1h5.3M109.8 133h5.3M109.8 132.9h5.3M109.8 132.8h5.3M109.8 132.7h5.3"/>
<path d="M109.8 132.6h5.3M109.8 132.5h5.3M109.8 132.4h5.3M109.8 132.3h5.3M109.8 132.2h5.3M109.8 129h5.3M109.8 128.9h5.3M109.8 128.8h5.3M109.8 128.7h5.3M109.8 128.6h5.3M109.8 128.5h5.3M109.8 128.4h5.3"/>
<path d="M109.8 128.3h5.3M109.8 128.2h5.3M109.8 128.1h5.3M109.8 128h5.3M109.8 127.9h5.3M109.8 127.8h5.3M109.8 127.7h5.3M109.8 127.6h5.3M109.8 127.5h5.3M109.8 127.4h5.3M109.8 127.3h5.3M109.8 127.1h5.3"/>
<path d="M110 127.1h5.1M110.1 127l-.3 .1M110.1 127h5M110.2 126.9h4.9M110.3 126.8h4.8M110.3 126.7h4.8M110.4 126.7l-.3 .3M110.4 126.7h4.7M110.4 126.6h4.7M110.4 126.5h4.7M110.5 126.4h4.6M110.5 126.4l-.1 .3"/>
<path d="M110.5 126.3h4.6M110.5 126.2h4.6M110.5 126.1h4.6M110.5 126h4.6M110.5 125.9h4.6M110.5 125.8h4.6M110.5 125.7h4.6M110.5 125.6h4.6M110.5 125.5h4.6M110.5 125.4h4.6M110.5 125.3h4.6M110.5 125.2h4.6"/>
<path d="M110.5 125.1h4.6M110.5 125h4.6M110.5 124.9h4.6M110.5 124.8h4.6M110.5 124.7h4.6M110.5 124.6h4.6M110.5 124.5h4.6M110.5 124.4h4.6M110.5 124.3h4.6M110.5 124.2h4.6M110.5 124.1h4.6M110.5 124h4.6"/>
<path d="M110.5 123.9h4.6M110.5 123.8h4.6M110.5 123.7h4.6M110.5 123.6h4.6M110.5 123.5h4.6M110.5 123.4h4.6M110.5 123.3h4.6M110.5 123.2h4.6M110.5 123.1h4.6M110.5 123h4.6M110.5 122.9h4.6M110.5 122.8h4.6"/>
<path d="M110.5 122.7h4.6M110.5 122.6h4.6M110.5 122.5h4.6M110.5 122.4h4.6M110.5 122.3h4.6M110.5 122.2h4.6M110.5 122.1h4.6M110.5 122h4.6M110.5 121.9h4.6M110.5 121.8h4.6M110.5 121.7h4.6M110.5 121.6h4.6"/>
<path d="M110.5 121.5h4.6M110.5 121.4h4.6M110.5 121.3h4.6M110.5 121.2h4.6M110.5 121.1h4.6M110.5 121h4.6M110.5 120.9h4.6M110.5 120.8h4.6M110.5 120.7h4.6M110.5 120.6h4.6M110.5 120.5h4.6M110.5 120.4h4.6"/>
<path d="M110.5 120.3h4.6M110.5 120.2h4.6M110.5 120.1h4.6M117.2 135.6l33.7 .1M117.2 127.2h14.4l-.2 .5M117.2 129.9l28.4 .1M117.2 129.8l15.6 .1M117.2 135h28.3M117.2 134.9h15.5M117.2 140h10.7M117.2 139.9h10.7M117.2 139.8h10.7"/>
<path d="M117.2 139.7h10.7M117.2 139.6h10.7M117.2 139.5h10.7M117.2 139.4h10.7M117.2 139.3h10.8M117.2 139.2h10.8M117.2 139.1h10.8M117.2 139.1h10.9M117.2 139h10.9M117.2 138.9h10.9M117.2 138.8h11M117.2 138.7h11"/>
<path d="M117.2 138.4h11.4M117.2 137.9h33.7M117.2 137.8h33.7M117.2 137.7h33.7M117.2 137.6h33.7M117.2 137.5h33.7M117.2 137.4h33.7M117.2 137.3h33.7M117.2 137.2h33.7M117.2 137.1h33.7M117.2 137h33.7M117.2 136.9h33.7"/>
<path d="M117.2 136.8h33.7M117.2 136.7h33.7M117.2 136.6h33.7M117.2 136.5h33.7M117.2 136.4h33.7M117.2 136.3h33.7M117.2 136.2h33.7M117.2 136.1h33.7M117.2 136h33.7M117.2 135.9h33.7M117.2 135.8h33.7M117.2 135.7h33.7"/>
<path d="M117.2 135.6h29.2M117.2 135.5l29.1 .1M117.2 135.5h28.9M117.2 135.4h28.8M117.2 135.4h28.7M117.2 135.3h28.6M117.2 135.2h28.5M117.2 135.1l28.5 .1M117.2 135.1h28.4M117.2 135l28.4 .1M117.2 134.9l15.6 .1M117.2 134.8l15.3 .1"/>
<path d="M117.2 134.8h15.2M117.2 134.7h15M117.2 134.6h14.9M117.2 134.5h14.8M117.2 134.4h14.7M117.2 134.3l14.7 .1M117.2 134.3h14.6M117.2 134.2l14.6 .1M117.2 134.2h14.5M117.2 134.1l14.5 .1M117.2 134.1h14.5M117.2 134h14.4"/>
<path d="M117.2 133.9h14.4M117.2 133.8h14.4M117.2 133.8h14.3M117.2 133.7h14.3M117.2 133.6h14.3M117.2 133.6h14.2M117.2 133.5h14.2M117.2 133.4h14.2M117.2 133.3h14.2M117.2 133.2h14.2M117.2 133.1h14.2M117.2 133h14.2"/>
<path d="M117.2 132.9h14.2M117.2 132.8h14.2M117.2 132.7h14.2M117.2 132.7h14.3M117.2 132.6h14.3M117.2 132.5h14.3M117.2 132.4h14.4M117.2 132.3h14.4M117.2 132h14.6M117.2 131.7h14.9M117.2 130.8h28.7M117.2 130.7h28.7"/>
<path d="M117.2 130.6h28.7M117.2 130.5h28.7M117.2 130.4h28.7M117.2 130.3h28.7M117.2 130.2h28.6M117.2 130.1h28.5M117.2 130l28.5 .1M117.2 130h28.4M117.2 129.9h15.7M117.2 129.8h15.4M117.2 129.7l15.3 .1M117.2 129.7h15.1"/>
<path d="M117.2 129.6l15 .1M117.2 129.6h15M117.2 129.5l14.9 .1M117.2 129.5h14.9M117.2 129.4l14.8 .1M117.2 129.4h14.8M117.2 129.3h14.7M117.2 129.3h14.6M117.2 129.2h14.6M117.2 129.2h14.5M117.2 129.1h14.5M117.2 129h14.5"/>
<path d="M117.2 128.9l14.4 .1M117.2 128.9h14.4M117.2 128.8l14.4 .1M117.2 128.8h14.4M117.2 128.7h14.3M117.2 128.6h14.3M117.2 128.5h14.3M117.2 128.5h14.2M117.2 128.4h14.2M117.2 128.3h14.2M117.2 128.2h14.2M117.2 128.1h14.2"/>
<path d="M117.2 128h14.2M117.2 127.9h14.2M117.2 127.8h14.2M117.2 127.7h14.2M117.2 127.6h14.3M117.2 127.5h14.3M117.2 127.1l5.4 .1M117.2 127.1h5.3M117.2 127l5.1 .1M117.2 127h5M117.2 126.9l5 .1M117.2 126.9h4.9"/>
<path d="M117.2 126.8l4.9 .1M117.2 126.8h4.8M117.2 126.7h4.8M117.2 126.7h4.7M117.2 126.6h4.7M117.2 126.5h4.7M117.2 126.4l4.7 .1M117.2 126.4h4.6M117.2 126.3l4.6 .1M117.2 126.3h4.6M117.2 126.2h4.6M117.2 126.1h4.6"/>
<path d="M117.2 126h4.6M117.2 125.9h4.6M117.2 125.8h4.6M117.2 125.7h4.6M117.2 125.6h4.6M117.2 125.5h4.6M117.2 125.4h4.6M117.2 125.3h4.6M117.2 125.2h4.6M117.2 125.1h4.6M117.2 125h4.6M117.2 124.9h4.6"/>
<path d="M117.2 124.8h4.6M117.2 124.7h4.6M117.2 124.6h4.6M117.2 124.5h4.6M117.2 124.4h4.6M117.2 124.3h4.6M117.2 124.2h4.6M117.2 124.1h4.6M117.2 124h4.6M117.2 123.9h4.6M117.2 123.8h4.6M117.2 123.7h4.6"/>
<path d="M117.2 123.6h4.6M117.2 123.5h4.6M117.2 123.4h4.6M117.2 123.3h4.6M117.2 123.2h4.6M117.2 123.1h4.6M117.2 123h4.6M117.2 122.9h4.6M117.2 122.8h4.6M117.2 122.7h4.6M117.2 122.6h4.6M117.2 122.5h4.6"/>
<path d="M117.2 122.4h4.6M117.2 122.3h4.6M117.2 122.2h4.6M117.2 122.1h4.6M117.2 122h4.6M117.2 121.9h4.6M117.2 121.8h4.6M117.2 121.7h4.6M117.2 121.6h4.6M117.2 121.5h4.6M117.2 121.4h4.6M117.2 121.3h4.6"/>
<path d="M117.2 121.2h4.6M117.2 121.1h4.6M117.2 121h4.6M117.2 120.9h4.6M117.2 120.8h4.6M117.2 120.7h4.6M117.2 120.6h4.6M117.2 120.5h4.6M117.2 120.4h4.6M117.2 120.3h4.6M117.2 120.2h4.6M117.2 120.1h4.6"/>
<path d="M121.8 126.4l.1 .3M121.9 126.7l.3 .3M122.2 127l.4 .2M127.9 139.4h-10.7M128 139.3h-10.8M128 139.2h-10.8M128.2 138.9h-11M128.2 138.7l-11 .1M128.2 138.7l-.3 .7v2.1l.1 .3M128.3 138.6l-11.1 .1M128.4 138.6h-11.2M128.4 138.5l-11.2 .1"/>
<path d="M128.5 138.5h-11.3M128.5 138.4l-11.3 .1M128.6 138.3l-11.4 .1M128.7 138.3h-11.5M128.7 138.2l-11.5 .1M128.7 138.2l-.5 .5M128.8 138.2h-11.6M129 138.1l-11.8 .1M129.1 138.1h-11.9M129.2 138h-12M129.3 138h-12.1M129.4 137.9l-.7 .3"/>
<path d="M130.2 137.9l.7 .3M130.3 138h20.6M130.4 138h20.5M130.5 138.1h20.4M130.6 138.1h20.3M130.8 138.2h20.1M130.9 138.2h20M130.9 138.2l.5 .5M130.9 138.3h20M131 138.3h19.9M131 138.4h19.9M131.1 138.4h19.8"/>
<path d="M131.1 138.5h19.8M131.2 138.5h19.7M131.3 138.6h19.6M131.4 138.7h19.5M131.4 127.7v.7M131.4 132.8v.7M131.4 128.4l.3 .7M131.4 133.5l.3 .7M131.4 138.7l.3 .7v2.1l-.1 .3M131.4 138.8h19.5M131.4 127.7h-14.2M131.4 138.9h19.5"/>
<path d="M131.4 127.6h-14.2M131.5 139h19.4M131.5 138.9h19.4M131.5 127.5h-14.3M131.5 139.1h19.4M131.5 127.4h-14.3M131.6 132.4l-14.4 .1M131.6 127.4h-14.4M131.6 139.2h19.3M131.6 139.1h19.3M131.6 127.3h-14.4M131.6 132.3l-14.4 .1"/>
<path d="M131.6 139.3h19.2M131.6 132.2h-14.4M131.7 139.4h19.1M131.7 139.3h19.1M131.7 132.2h-14.5M131.7 132.1h-14.5M131.7 140h19.1M131.7 139.9h19.1M131.7 139.8h19.1M131.7 139.7h19.1M131.7 139.6h19.1M131.7 139.5h19.1"/>
<path d="M131.7 129.1l.5 .6M131.7 132.1l-.3 .7M131.7 134.2l.5 .5M131.8 132h-14.6M131.9 131.9l-14.7 .1M131.9 131.9h-14.7M132 131.8h-14.8M132.1 131.7h-14.9M132.2 131.6h-15M132.2 129.7l.7 .2M132.2 131.6l-.5 .5M132.2 134.7l.7 .3"/>
<path d="M132.4 131.5h-15.2M132.5 131.4l-15.3 .1M132.6 131.4h-15.4M132.7 131.3l-15.5 .1M132.9 131.3h-15.7M132.9 131.3l-.7 .3M134.2 129.9v.1M134.9 135l10.5-.1 .5 .5 .7 .3M135 131.3h10.5M135 129.9h10.5M135.1 135h10.4M135.1 129.9h10.4"/>
<path d="M135.1 131.3h10.4M135.2 129.8l-.3 .2M142.3 134.9h.1M143.1 134.9h-.1M145.4 129.8l.5 .5M145.5 131.2l-28.3 .1M145.6 131.2h-28.4M145.7 131.1h-28.5M145.8 131h-28.6M145.9 130.9h-28.7M145.9 130.9l-.5 .5h-10.2l-.3-.1M145.9 130.3v.6"/>
<path d="M145.9 130.9h.1M147.3 135.7l.7-.3 .5-.5 .6 .5 .7 .3M147.5 135.6h2.1M147.6 135.6h1.9M147.7 135.5h1.6M147.8 135.4h1.4M148 135.4h1.1M148 135.3h1M148.1 135.3h.8M148.2 135.2h.7M148.2 135.1l.6 .1M148.3 135.1h.5"/>
<path d="M148.3 135.1h.4M148.4 135h.3M148.4 135h.2M150.6 135.6h.3M150.8 135.6h.1M150.9 139.1l-.1 .3v2.1l.3 .7M150.9 137.9h-33.7M150.9 135.5l-.4 .2M150.9 135.5v3.6M150.9 135.5h.1M154.4 135.6l10.6 .1M154.4 135h1.9"/>
<path d="M154.4 134.9h1.8M154.4 137.9h10.6M154.4 139.2h10.6M154.4 139.1h10.6M154.4 139h10.6M154.4 138.9h10.6M154.4 138.8h10.6M154.4 138.7h10.6M154.4 138.6h10.6M154.4 138.5h10.6M154.4 138.4h10.6M154.4 138.3h10.6"/>
<path d="M154.4 138.2h10.6M154.4 138.1h10.6M154.4 138h10.6M154.4 137.8h10.6M154.4 137.7h10.6M154.4 137.6h10.6M154.4 137.5h10.6M154.4 137.4h10.6M154.4 137.3h10.6M154.4 137.2h10.6M154.4 137.1h10.6M154.4 137h10.6"/>
<path d="M154.4 136.9h10.6M154.4 136.8h10.6M154.4 136.7h10.6M154.4 136.6h10.6M154.4 136.5h10.6M154.4 136.4h10.6M154.4 136.3h10.6M154.4 136.2h10.6M154.4 136.1h10.6M154.4 136h10.6M154.4 135.9h10.6M154.4 135.8h10.6"/>
<path d="M154.4 135.7h10.6M154.4 135.6h2.8M154.4 135.5l2.7 .1M154.4 135.5h2.5M154.4 135.4h2.4M154.4 135.4h2.3M154.4 135.3h2.2M154.4 135.2h2.1M154.4 135.1l2.1 .1M154.4 135.1h2M154.4 135l2 .1M154.4 134.9l1.9 .1"/>
<path d="M154.4 134.8h1.7M154.4 134.7h1.7M154.4 134.6h1.7M154.4 134.6h1.6M154.4 134.5h1.6M154.4 134.4h1.6M154.4 134.3l1.6 .1M154.4 134.3h1.5M154.4 134.2l1.5 .1M154.4 134.2h1.5M154.4 134.1l1.5 .1M154.4 134.1h1.5"/>
<path d="M154.4 134h1.5M154.4 133.9h1.5M154.4 133.8h1.5M154.4 133.7h1.5M154.4 133.6h1.5M154.4 133.5h1.5M154.4 133.4h1.5M154.4 133.3h1.5M154.4 133.2h1.5M154.4 133.1h1.5M154.4 133h1.5M154.4 132.9h1.5"/>
<path d="M154.4 132.8h1.5M154.4 132.7h1.5M154.4 132.6h1.5M154.4 139.1l.1 2.4M154.4 132.6v6.5M154.5 139.3h10.5M154.5 139.2h10.5M154.5 132.5h1.4M154.5 139.4h10.5M154.5 140h10.5M154.5 139.9h10.5M154.5 139.8h10.5"/>
<path d="M154.5 139.7h10.5M154.5 139.6h10.5M154.5 139.5h10.5M154.6 132.4h1.3M154.7 132.3h1.2M154.8 132.2h1.1M154.9 132.2h1M154.9 132.1h1M155 132h.9M155.1 131.9h.9M155.2 131.8h.8M155.3 131.7h.7"/>
<path d="M155.4 131.6h.6M155.5 131.5h.5M155.6 131.5h.4M155.6 131.4h.4M155.7 131.4h.3M155.7 131.3h.3M155.8 131.3h.2M155.8 131.2h.2M155.9 132.1v2.1l.2 .7M155.9 131.1h.1M155.9 132l-.9 .1M156 131.9l-.9 .1"/>
<path d="M156 131.8v-.8l-1.6 1.6M156 131.8l-.1 .3M156 131.1h.1M156.1 134.9l.6 .5M156.7 135.4l.7 .3M158.3 135.6h6.7M158.4 135.6h6.6M158.5 135.5h6.5M158.6 135.4h6.4M158.8 135.4h6.2M158.8 135.4l-.7 .3M158.8 135.3h6.2"/>
<path d="M158.9 135.3h6.1M159 135.2h6M159 135.1h6M159.1 135.1h5.9M159.2 135h5.8M159.3 134.9h5.7M159.3 134.8h5.7M159.3 134.9l-.5 .5M159.4 134.7h5.6M159.4 134.6h5.6M159.5 134.5h5.5M159.5 129.9h5.5"/>
<path d="M159.5 129.8h5.5M159.5 131.4h5.5M159.5 131.2h5.5M159.5 134.4h5.5M159.5 131.9h5.5M159.5 131.8h5.5M159.5 131.7h5.5M159.5 131.6h5.5M159.5 131.5h5.5M159.5 131.3h5.5M159.5 131.1h5.5M159.5 131h5.5"/>
<path d="M159.5 130.9h5.5M159.5 130.8h5.5M159.5 130.7h5.5M159.5 130.6h5.5M159.5 130.5h5.5M159.5 130.4h5.5M159.5 130.3h5.5M159.5 130.2h5.5M159.5 130.1h5.5M159.5 130h5.5M159.5 129.7h5.5M159.5 129.6h5.5"/>
<path d="M159.5 129.5h5.5M159.5 129.4h5.5M159.5 129.3h5.5M159.5 131.8l.1 .3M159.5 129.4v2.4M159.6 134.3h5.4M159.6 132h5.4M159.6 129.2h5.4M159.6 134.2h5.4M159.6 132.1h5.4M159.6 129.1h5.4M159.6 127.2h5.4"/>
<path d="M159.6 134.1h5.4M159.6 134h5.4M159.6 133.9h5.4M159.6 133.8h5.4M159.6 133.7h5.4M159.6 133.6h5.4M159.6 133.5h5.4M159.6 133.4h5.4M159.6 133.3h5.4M159.6 133.2h5.4M159.6 133.1h5.4M159.6 133h5.4"/>
<path d="M159.6 132.9h5.4M159.6 132.8h5.4M159.6 132.7h5.4M159.6 132.6h5.4M159.6 132.5h5.4M159.6 132.4h5.4M159.6 132.3h5.4M159.6 132.2h5.4M159.6 129h5.4M159.6 128.9h5.4M159.6 128.8h5.4M159.6 128.7h5.4"/>
<path d="M159.6 128.6h5.4M159.6 128.5h5.4M159.6 128.4h5.4M159.6 128.3h5.4M159.6 128.2h5.4M159.6 128.1h5.4M159.6 128h5.4M159.6 127.9h5.4M159.6 127.8h5.4M159.6 127.7h5.4M159.6 127.6h5.4M159.6 127.5h5.4"/>
<path d="M159.6 127.4h5.4M159.6 127.3h5.4M159.6 127.1h5.4M159.6 134.2l-.3 .7M159.6 127.1v2M159.6 132.1v2.1M159.6 129.1l-.1 .3M159.7 127.1h5.3M159.8 127.1h5.2M159.9 127h5.1M159.9 127l-.3 .1M160 127h5"/>
<path d="M160 126.9h5M160.1 126.9h4.9M160.1 126.8h4.9M160.2 126.7h4.8M160.2 126.7l-.3 .3M160.2 126.6h4.8M160.3 126.6h4.7M160.3 126.5h4.7M160.3 126.4h4.7M160.4 126.3h4.6M160.4 126.2h4.6M160.4 126.1h4.6"/>
<path d="M160.4 126h4.6M160.4 125.9h4.6M160.4 125.8h4.6M160.4 125.7h4.6M160.4 125.6h4.6M160.4 125.5h4.6M160.4 125.4h4.6M160.4 125.3h4.6M160.4 125.2h4.6M160.4 125.1h4.6M160.4 125h4.6M160.4 124.9h4.6"/>
<path d="M160.4 124.8h4.6M160.4 124.7h4.6M160.4 124.6h4.6M160.4 124.5h4.6M160.4 124.4h4.6M160.4 124.3h4.6M160.4 124.2h4.6M160.4 124.1h4.6M160.4 124h4.6M160.4 123.9h4.6M160.4 123.8h4.6M160.4 123.7h4.6"/>
<path d="M160.4 123.6h4.6M160.4 123.5h4.6M160.4 123.4h4.6M160.4 123.3h4.6M160.4 123.2h4.6M160.4 123.1h4.6M160.4 123h4.6M160.4 122.9h4.6M160.4 122.8h4.6M160.4 122.7h4.6M160.4 122.6h4.6M160.4 122.5h4.6"/>
<path d="M160.4 122.4h4.6M160.4 122.3h4.6M160.4 122.2h4.6M160.4 122.1h4.6M160.4 122h4.6M160.4 121.9h4.6M160.4 121.8h4.6M160.4 121.7h4.6M160.4 121.6h4.6M160.4 121.5h4.6M160.4 121.4h4.6M160.4 121.3h4.6"/>
<path d="M160.4 121.2h4.6M160.4 121.1h4.6M160.4 121h4.6M160.4 120.9h4.6M160.4 120.8h4.6M160.4 120.7h4.6M160.4 120.6h4.6M160.4 120.5h4.6M160.4 120.4h4.6M160.4 120.3h4.6M160.4 120.2h4.6M160.4 120.1h4.6"/>
<path d="M160.4 126.4l-.2 .3M167 135.6l33.7 .1M167 127.2h14.5l-.2 .5M167 129.9l28.4 .1M167 129.8l15.6 .1M167 135h28.4M167 134.9h15.5M167 140h10.8M167 139.9h10.8M167 139.8h10.8M167 139.7h10.8M167 139.6h10.8"/>
<path d="M167 139.5h10.8M167 139.4h10.8M167 139h10.9M167 138.9h11M167 137.9h33.7M167 137.8h33.7M167 137.7h33.7M167 137.6h33.7M167 137.5h33.7M167 137.4h33.7M167 137.3h33.7M167 137.2h33.7"/>
<path d="M167 137.1h33.7M167 137h33.7M167 136.9h33.7M167 136.8h33.7M167 136.7h33.7M167 136.6h33.7M167 136.5h33.7M167 136.4h33.7M167 136.3h33.7M167 136.2h33.7M167 136.1h33.7M167 136h33.7"/>
<path d="M167 135.9h33.7M167 135.8h33.7M167 135.7h33.7M167 135.6h29.3M167 135.5l29.1 .1M167 135.5h29M167 135.4h28.9M167 135.4h28.7M167 135.3h28.7M167 135.3h28.6M167 135.2h28.6M167 135.1l28.5 .1"/>
<path d="M167 135.1h28.5M167 135l28.4 .1M167 134.9l15.6 .1M167 134.8l15.3 .1M167 134.8h15.2M167 134.7h15.1M167 134.7h15M167 134.6h15M167 134.6h14.9M167 134.5h14.9M167 134.5h14.8M167 134.4h14.8"/>
<path d="M167 134.3l14.7 .1M167 134.3h14.7M167 134.2l14.6 .1M167 134.2h14.5M167 134.1l14.5 .1M167 134.1h14.5M167 134l14.5 .1M167 134h14.5M167 133.9l14.4 .1M167 133.9h14.4M167 133.8l14.4 .1M167 133.8h14.4"/>
<path d="M167 133.7l14.4 .1M167 133.7h14.3M167 133.6h14.3M167 133.5h14.3M167 133.4h14.3M167 133.3h14.3M167 133.2h14.3M167 133.1h14.3M167 133h14.3M167 132.9h14.3M167 132.8h14.3M167 132.6h14.3"/>
<path d="M167 132.5h14.4M167 132.4h14.4M167 132.3h14.4M167 132.2h14.5M167 132.1h14.5M167 130.8h28.8M167 130.7h28.8M167 130.6h28.8M167 130.5h28.8M167 130.4h28.8M167 130.3h28.8M167 130.3h28.7"/>
<path d="M167 130.2h28.7M167 130.2h28.6M167 130.1h28.6M167 130l28.5 .1M167 130h28.5M167 129.9h15.7M167 129.8h15.5M167 129.7l15.3 .1M167 129.7h15.2M167 129.6l15.1 .1M167 129.6h15M167 129.5l15 .1"/>
<path d="M167 129.5h14.9M167 129.4l14.9 .1M167 129.4h14.8M167 129.3h14.8M167 129.3h14.7M167 129.2h14.7M167 129.2h14.6M167 129.1h14.5M167 129h14.5M167 128.9h14.5M167 128.8h14.4M167 128.7h14.4"/>
<path d="M167 128.6h14.3M167 128.5h14.3M167 128.4h14.3M167 128.3h14.3M167 128.2h14.3M167 128.1h14.3M167 128h14.3M167 127.9h14.3M167 127.8h14.3M167 127.7h14.3M167 127.6h14.3M167 127.5h14.3"/>
<path d="M167 127.4h14.4M167 127.3h14.4M167 127.1l5.4 .1M167 127.1h5.3M167 127l5.2 .1M167 127h5.1M167 126.9l5 .1M167 126.9h5M167 126.8h4.9M167 126.7h4.8M167 126.6h4.7M167 126.5h4.7"/>
<path d="M167 126.4h4.7M167 126.3h4.6M167 126.2h4.6M167 126.1h4.6M167 126h4.6M167 125.9h4.6M167 125.8h4.6M167 125.7h4.6M167 125.6h4.6M167 125.5h4.6M167 125.4h4.6M167 125.3h4.6"/>
<path d="M167 125.2h4.6M167 125.1h4.6M167 125h4.6M167 124.9h4.6M167 124.8h4.6M167 124.7h4.6M167 124.6h4.6M167 124.5h4.6M167 124.4h4.6M167 124.3h4.6M167 124.2h4.6M167 124.1h4.6"/>
<path d="M167 124h4.6M167 123.9h4.6M167 123.8h4.6M167 123.7h4.6M167 123.6h4.6M167 123.5h4.6M167 123.4h4.6M167 123.3h4.6M167 123.2h4.6M167 123.1h4.6M167 123h4.6M167 122.9h4.6"/>
<path d="M167 122.8h4.6M167 122.7h4.6M167 122.6h4.6M167 122.5h4.6M167 122.4h4.6M167 122.3h4.6M167 122.2h4.6M167 122.1h4.6M167 122h4.6M167 121.9h4.6M167 121.8h4.6M167 121.7h4.6"/>
<path d="M167 121.6h4.6M167 121.5h4.6M167 121.4h4.6M167 121.3h4.6M167 121.2h4.6M167 121.1h4.6M167 121h4.6M167 120.9h4.6M167 120.8h4.6M167 120.7h4.6M167 120.6h4.6M167 120.5h4.6"/>
<path d="M167 120.4h4.6M167 120.3h4.6M167 120.2h4.6M167 120.1h4.6M171.6 126.4l.2 .3M171.8 126.7l.3 .3M172.1 127l.3 .2M177.8 139.4v2.1M177.8 139.4h-10.8M177.8 139.3l-10.8 .1M177.8 139.3h-10.8M177.8 139.2l-10.8 .1"/>
<path d="M177.9 139.2h-10.9M177.9 139.1h-10.9M177.9 139h-10.9M178 138.9h-11M178 138.8h-11M178 138.7l-.2 .7M178.1 138.7l-11.1 .1M178.1 138.7h-11.1M178.1 138.6l-11.1 .1M178.2 138.6h-11.2M178.2 138.5l-11.2 .1M178.3 138.5h-11.3"/>
<path d="M178.4 138.4l-11.4 .1M178.4 138.4h-11.4M178.5 138.3l-11.5 .1M178.5 138.3h-11.5M178.6 138.2l-11.6 .1M178.6 138.2l-.6 .5M178.7 138.2h-11.7M178.8 138.1l-11.8 .1M178.9 138.1h-11.9M179.1 138h-12.1M179.2 138h-12.2M179.3 137.9l-.7 .3"/>
<path d="M180 137.9l.7 .3M180.1 138h20.6M180.2 138h20.5M180.4 138.1h20.3M180.5 138.1h20.2M180.6 138.2h20.1M180.7 138.2h20M180.7 138.2l.6 .5M180.8 138.3h19.9M180.9 138.4h19.8M181 138.5h19.7M181.1 138.6h19.6"/>
<path d="M181.2 138.7h19.5M181.3 138.7h19.4M181.3 127.7v.7M181.3 132.8v.7M181.3 128.4l.2 .7M181.3 133.5l.2 .7M181.3 138.7l.2 .7v2.1M181.3 138.8h19.4M181.3 132.7h-14.3M181.3 127.6l-14.3 .1M181.3 138.9h19.4M181.3 139h19.4"/>
<path d="M181.3 132.5l-14.3 .1M181.4 139h19.3M181.4 139.1h19.3M181.4 132.4l-14.4 .1M181.4 139.2h19.3M181.4 127.3h-14.4M181.5 139.3h19.2M181.5 139.4h19.1M181.5 140h19.1M181.5 139.9h19.1M181.5 139.8h19.1M181.5 139.7h19.1"/>
<path d="M181.5 139.6h19.1M181.5 139.5h19.1M181.5 129.1l.6 .6M181.5 132.1l-.2 .7M181.5 134.2l.6 .5M181.6 132l-14.6 .1M181.6 132h-14.6M181.7 131.9l-14.7 .1M181.7 131.9h-14.7M181.8 131.8h-14.8M181.9 131.8h-14.9M181.9 131.7h-14.9"/>
<path d="M182 131.6h-15M182.1 131.6h-15.1M182.1 129.7l.7 .2M182.1 131.6l-.6 .5M182.1 134.7l.7 .3M182.2 131.5h-15.2M182.3 131.4l-15.3 .1M182.5 131.4h-15.5M182.6 131.3l-15.6 .1M182.7 131.3h-15.7M182.8 131.3l-.7 .3M184 129.9v.1"/>
<path d="M184.8 131.3l.3 .1M184.8 131.3h10.5M184.9 129.9h10.4M184.9 135h10.4M185 129.9h10.3M185 131.3h10.3M185.1 134.9h10.2M185.1 129.8l-.3 .2M185.1 134.9l-.3 .1M192.2 134.9h.1M192.9 134.9h.1M195.2 134.9l.5 .5 .7 .3"/>
<path d="M195.3 129.8l.5 .5M195.4 131.2l-28.4 .1M195.5 131.2h-28.5M195.5 131.1h-28.5M195.6 131.1h-28.6M195.6 131h-28.6M195.7 131h-28.7M195.7 130.9l-.5 .5h-10.1M195.7 130.9h-28.7M195.8 130.9h-28.8M195.8 130.3v.6M195.8 130.9h-.1"/>
<path d="M197.3 135.6h2.1M197.4 135.6h1.9M197.6 135.5h1.6M197.7 135.4h1.4M197.8 135.4h1.1M197.9 135.3h1M198 135.3h.8M198 135.2h.8M198.1 135.2h.6M198.1 135.1h.5M198.2 135.1h.4M198.2 135h.3"/>
<path d="M198.3 135h.2M198.3 134.9h.1M198.3 134.9l-.5 .5-.6 .3M198.4 134.9l.5 .5 .7 .3M200.5 135.6h.2M200.6 135.6h.1M200.6 139.4v2.1M200.7 137.9h-33.7M200.7 135.5l-.4 .2M200.7 135.5v3.6M200.7 139.1l-.1 .3M204.3 135.6l10.5 .1"/>
<path d="M204.3 135h1.9M204.3 134.9h1.8M204.3 137.9h10.5M204.3 139.1h10.5M204.3 139h10.5M204.3 138.9h10.5M204.3 138.8h10.5M204.3 138.7h10.5M204.3 138.6h10.5M204.3 138.5h10.5M204.3 138.4h10.5M204.3 138.3h10.5"/>
<path d="M204.3 138.2h10.5M204.3 138.1h10.5M204.3 138h10.5M204.3 137.8h10.5M204.3 137.7h10.5M204.3 137.6h10.5M204.3 137.5h10.5M204.3 137.4h10.5M204.3 137.3h10.5M204.3 137.2h10.5M204.3 137.1h10.5M204.3 137h10.5"/>
<path d="M204.3 136.9h10.5M204.3 136.8h10.5M204.3 136.7h10.5M204.3 136.6h10.5M204.3 136.5h10.5M204.3 136.4h10.5M204.3 136.3h10.5M204.3 136.2h10.5M204.3 136.1h10.5M204.3 136h10.5M204.3 135.9h10.5M204.3 135.8h10.5"/>
<path d="M204.3 135.7h10.5M204.3 135.6h2.8M204.3 135.5l2.6 .1M204.3 135.5h2.5M204.3 135.4h2.4M204.3 135.4h2.2M204.3 135.3h2.2M204.3 135.3h2.1M204.3 135.2h2.1M204.3 135.1l2 .1M204.3 135.1h2M204.3 135l1.9 .1"/>
<path d="M204.3 134.9l1.8 .1M204.3 134.8l1.7 .1M204.3 134.8h1.7M204.3 134.7h1.6M204.3 134.6h1.6M204.3 134.5h1.5M204.3 134.4h1.5M204.3 134.3l1.5 .1M204.3 134.3h1.5M204.3 134.2l1.4 .1M204.3 134.2h1.4M204.3 134.1h1.4"/>
<path d="M204.3 134h1.4M204.3 133.9h1.4M204.3 133.8h1.4M204.3 133.7h1.4M204.3 133.6h1.4M204.3 133.5h1.4M204.3 133.4h1.4M204.3 133.3h1.4M204.3 133.2h1.4M204.3 133.1h1.4M204.3 133h1.4M204.3 132.9h1.4"/>
<path d="M204.3 132.8h1.4M204.3 132.7h1.4M204.3 132.6h1.4M204.3 139.1l.1 .3M204.3 132.6v6.5M204.3 139.2h10.5M204.3 139.3h10.5M204.3 132.5h1.4M204.4 139.4h10.4M204.4 132.5h1.3M204.4 140h10.4M204.4 139.9h10.4"/>
<path d="M204.4 139.8h10.4M204.4 139.7h10.4M204.4 139.6h10.4M204.4 139.5h10.4M204.4 139.4v2.1M204.4 132.4h1.3M204.5 132.4h1.2M204.6 132.3h1.1M204.7 132.2h1M204.8 132h.9M205 131.9h.8M205.1 131.8h.7"/>
<path d="M205.1 131.7h.7M205.2 131.7h.6M205.2 131.6h.6M205.3 131.6h.5M205.3 131.5h.5M205.4 131.5h.4M205.4 131.4h.4M205.5 131.3h.3M205.6 131.3h.2M205.6 131.2h.2M205.7 131.1h.1M205.7 132.1v2.1"/>
<path d="M205.7 134.2l.3 .7M205.7 132.1h-1M205.8 132h-.9M205.8 131.1h.1M205.8 131.9l-.9 .1M205.8 131.8h-.8M205.8 131.8v-.8l-1.5 1.6M205.8 131.8l-.1 .3M206 134.9l.5 .5M206.5 135.4l.7 .3M208.1 135.6h6.7M208.2 135.6h6.6"/>
<path d="M208.4 135.5h6.4M208.5 135.4h6.3M208.6 135.4h6.2M208.6 135.4l-.6 .3M208.7 135.3h6.1M208.8 135.2h6M208.9 135.2h5.9M208.9 135.1h5.9M209 135.1h5.8M209 135h5.8M209.1 135h5.7M209.1 134.9h5.7"/>
<path d="M209.2 134.9h5.6M209.2 134.9l-.6 .5M209.2 134.8h5.6M209.2 134.7h5.6M209.3 134.6h5.5M209.3 134.5h5.5M209.3 129.9h5.5M209.3 129.8h5.5M209.3 131.4h5.5M209.3 131.2h5.5M209.3 131.8h5.5M209.3 131.7h5.5"/>
<path d="M209.3 131.6h5.5M209.3 131.5h5.5M209.3 131.3h5.5M209.3 131.1h5.5M209.3 131h5.5M209.3 130.9h5.5M209.3 130.8h5.5M209.3 130.7h5.5M209.3 130.6h5.5M209.3 130.5h5.5M209.3 130.4h5.5M209.3 130.3h5.5"/>
<path d="M209.3 130.2h5.5M209.3 130.1h5.5M209.3 130h5.5M209.3 129.7h5.5M209.3 129.6h5.5M209.3 129.5h5.5M209.3 129.4h5.5M209.3 131.8l.2 .3M209.3 129.4v2.4M209.4 134.4h5.4M209.4 131.9h5.4M209.4 129.3h5.4"/>
<path d="M209.4 134.3h5.4M209.4 132h5.4M209.4 129.2h5.4M209.4 134.2h5.4M209.4 132.1h5.4M209.4 129.1h5.4M209.5 127.2h5.3M209.5 134.1h5.3M209.5 134h5.3M209.5 133.9h5.3M209.5 133.8h5.3M209.5 133.7h5.3"/>
<path d="M209.5 133.6h5.3M209.5 133.5h5.3M209.5 133.4h5.3M209.5 133.3h5.3M209.5 133.2h5.3M209.5 133.1h5.3M209.5 133h5.3M209.5 132.9h5.3M209.5 132.8h5.3M209.5 132.7h5.3M209.5 132.6h5.3M209.5 132.5h5.3"/>
<path d="M209.5 132.4h5.3M209.5 132.3h5.3M209.5 132.2h5.3M209.5 132.1h5.3M209.5 129.1h5.3M209.5 129h5.3M209.5 128.9h5.3M209.5 128.8h5.3M209.5 128.7h5.3M209.5 128.6h5.3M209.5 128.5h5.3M209.5 128.4h5.3"/>
<path d="M209.5 128.3h5.3M209.5 128.2h5.3M209.5 128.1h5.3M209.5 128h5.3M209.5 127.9h5.3M209.5 127.8h5.3M209.5 127.7h5.3M209.5 127.6h5.3M209.5 127.5h5.3M209.5 127.4h5.3M209.5 127.3h5.3M209.5 127.1h5.3"/>
<path d="M209.5 132.1v2.1l-.3 .7M209.5 127.1v2M209.5 129.1l-.2 .3M209.7 127.1h5.1M209.7 127h5.1M209.7 127l-.2 .1M209.8 127h5M209.9 126.9h4.9M209.9 126.8h4.9M210 126.8h4.8M210 126.7h4.8M210.1 126.6h4.7"/>
<path d="M210.1 126.5h4.7M210.1 126.4h4.7M210.2 126.4h4.6M210.2 126.3h4.6M210.2 126.2h4.6M210.2 126.1h4.6M210.2 126h4.6M210.2 125.9h4.6M210.2 125.8h4.6M210.2 125.7h4.6M210.2 125.6h4.6M210.2 125.5h4.6"/>
<path d="M210.2 125.4h4.6M210.2 125.3h4.6M210.2 125.2h4.6M210.2 125.1h4.6M210.2 125h4.6M210.2 124.9h4.6M210.2 124.8h4.6M210.2 124.7h4.6M210.2 124.6h4.6M210.2 124.5h4.6M210.2 124.4h4.6M210.2 124.3h4.6"/>
<path d="M210.2 124.2h4.6M210.2 124.1h4.6M210.2 124h4.6M210.2 123.9h4.6M210.2 123.8h4.6M210.2 123.7h4.6M210.2 123.6h4.6M210.2 123.5h4.6M210.2 123.4h4.6M210.2 123.3h4.6M210.2 123.2h4.6M210.2 123.1h4.6"/>
<path d="M210.2 123h4.6M210.2 122.9h4.6M210.2 122.8h4.6M210.2 122.7h4.6M210.2 122.6h4.6M210.2 122.5h4.6M210.2 122.4h4.6M210.2 122.3h4.6M210.2 122.2h4.6M210.2 122.1h4.6M210.2 122h4.6M210.2 121.9h4.6"/>
<path d="M210.2 121.8h4.6M210.2 121.7h4.6M210.2 121.6h4.6M210.2 121.5h4.6M210.2 121.4h4.6M210.2 121.3h4.6M210.2 121.2h4.6M210.2 121.1h4.6M210.2 121h4.6M210.2 120.9h4.6M210.2 120.8h4.6M210.2 120.7h4.6"/>
<path d="M210.2 120.6h4.6M210.2 120.5h4.6M210.2 120.4h4.6M210.2 120.3h4.6M210.2 120.2h4.6M210.2 120.1h4.6M210.2 126.4l-.5 .6M67.4 142.9h10.8M67.4 149.1h10.2M67.4 150.3h47.7M67.4 147.4h2.8M67.4 147.5h2.9"/>
<path d="M67.4 146.5h2.6M67.4 151.6h47.7M67.4 151.5h47.7M67.4 151.4h47.7M67.4 151.3h47.7M67.4 151.2h47.7M67.4 151.1h47.7M67.4 151h47.7M67.4 150.9h47.7M67.4 150.8h47.7M67.4 150.7h47.7M67.4 150.6h47.7"/>
<path d="M67.4 150.5h47.7M67.4 150.4h47.7M67.4 150.2h11.5M67.4 150.2h11.3M67.4 150.1h11.3M67.4 150.1h11.1M67.4 150h11M67.4 149.9l10.9 .1M67.4 149.9h10.8M67.4 149.8l10.7 .1M67.4 149.8h10.7M67.4 149.7l10.6 .1"/>
<path d="M67.4 149.7h10.6M67.4 149.6h10.5M67.4 149.5h10.4M67.4 149.4h10.3M67.4 149.3h10.3M67.4 149.2h10.3M67.4 149.2h10.2M67.4 149.1l10.2 .1M67.4 149l4.8 .1M67.4 149h4.6M67.4 148.9h4.4M67.4 148.9h4.2"/>
<path d="M67.4 148.8h4.1M67.4 148.7h4M67.4 148.7h3.8M67.4 148.6h3.7M67.4 148.5l3.7 .1M67.4 148.5h3.6M67.4 148.4l3.6 .1M67.4 148.4h3.5M67.4 148.3l3.4 .1M67.4 148.3h3.4M67.4 148.2l3.3 .1M67.4 148.2h3.3"/>
<path d="M67.4 148.1l3.3 .1M67.4 148.1h3.2M67.4 148l3.1 .1M67.4 148h3.1M67.4 147.9l3.1 .1M67.4 147.9h3M67.4 147.8h3M67.4 147.7h3M67.4 147.7h2.9M67.4 147.6h2.9M67.4 147.3l2.8 .1M67.4 147.3h2.8"/>
<path d="M67.4 147.2h2.7M67.4 147.1h2.7M67.4 147h2.7M67.4 146.9h2.7M67.4 146.8h2.6M67.4 146.7h2.6M67.4 146.6h2.6M67.4 146.4h2.6M67.4 146.3h2.6M67.4 146.2h2.6M67.4 146.1h2.6M67.4 146.1h2.7"/>
<path d="M67.4 146h2.7M67.4 145.9h2.7M67.4 145.8h2.7M67.4 145.7h2.7M67.4 145.6h2.8M67.4 145.5h2.8M67.4 145.1h3M67.4 145h3.1M67.4 144.9h3.1M67.4 143.1h10.8M67.4 143h10.8M67.4 142.8h10.8"/>
<path d="M67.4 142.7h10.8M67.4 142.6h10.8M67.4 142.5h10.8M67.4 142.4h10.8M67.4 142.3h10.8M67.4 142.2h10.8M67.4 142.1h10.8M67.4 142h10.8M67.4 141.9h10.8M67.4 141.8h10.8M67.4 141.7l10.8 .1M67.4 141.7h10.8"/>
<path d="M67.4 141.6h10.8M67.4 141.6h10.7M67.4 141.5h10.7M67.4 141.4h10.7M67.4 141.3h10.7M67.4 141.2h10.7M67.4 141.1h10.7M67.4 141h10.7M67.4 140.9h10.7M67.4 140.8h10.7M67.4 140.7h10.7M67.4 140.6h10.7"/>
<path d="M67.4 140.5h10.7M67.4 140.4h10.7M67.4 140.3h10.7M67.4 140.2h10.7M67.4 140.1h10.7M70 146.1v.7M70 146.8l.2 .7M70.1 145.9h-2.7M70.1 145.8h-2.7M70.2 145.6h-2.8M70.2 145.5l-.2 .6M70.2 147.5l.9 1.1"/>
<path d="M70.2 145.5h-2.8M70.2 145.4l-2.8 .1M70.3 145.4h-2.9M70.3 145.3l-2.9 .1M70.3 145.3h-2.9M70.4 145.2h-3M70.4 145.1h-3M70.5 144.9l-3.1 .1M70.6 144.8l-3.2 .1M70.6 144.8h-3.2M70.7 144.7l-3.3 .1M70.7 144.7h-3.3"/>
<path d="M70.8 144.6l-3.4 .1M70.8 144.6h-3.4M70.9 144.5l-3.5 .1M71 144.5h-3.6M71 144.4l-3.6 .1M71 144.4h-3.6M71.1 148.6l1.2 .5M71.1 144.3l-3.7 .1M71.2 144.3h-3.8M71.4 144.2l-4 .1M71.4 144.2h-4M71.5 144.1h-4.1"/>
<path d="M71.6 144.1h-4.2M71.8 144h-4.4M71.9 144h-4.5M72.2 143.9h-4.8M72.3 143.8a2.72 2.72 0 0 0-2.1 1.7M73 143.8l1.3 .6M73.2 149.1h4.4M73.2 143.9h4.1M73.3 149h4.3M73.4 144h3.9M73.6 148.9h3.9M73.6 144h3.7"/>
<path d="M73.7 148.9h3.8M73.7 144.1h3.5M73.8 148.8h3.7M73.8 144.1h3.4M73.9 148.8h3.6M73.9 144.2h3.3M74 148.7h3.4M74 144.2h3.2M74.1 148.7h3.3M74.1 144.3h3M74.2 144.3h2.9M74.2 148.6h3.2"/>
<path d="M74.3 148.6h3.1M74.3 144.4l.5 .5M74.3 148.6l-1.3 .5M74.3 144.4h2.8M74.3 148.5h3.1M74.4 148.5h3M74.4 144.5h2.6M74.4 148.4h3M74.5 148.4h2.9M74.5 144.6h2.5M74.5 148.3h2.9M74.6 148.3h2.8"/>
<path d="M74.6 144.7h2.4M74.6 148.2h2.8M74.6 144.7h2.3M74.7 148.2h2.7M74.7 144.8h2.2M74.7 148.1h2.7M74.8 148.1l-.5 .5M74.8 144.9l.3 .6M74.8 148h2.6M74.8 144.9h2.1M74.8 145h2.1M74.9 145.1h2"/>
<path d="M74.9 147.9h2.6M74.9 145.2h2M75 145.2h1.9M75 145.3h1.9M75.1 145.4h1.8M75.1 145.5l.2 .6M75.1 145.5h1.8M75.1 145.6h1.8M75.2 145.6h1.7M75.2 145.8h1.8M75.2 145.7h1.8M75.2 147.1h2.7"/>
<path d="M75.2 147h2.6M75.2 145.9h1.9M75.2 145.9h1.8M75.2 146h1.9M75.3 146.9h2.4M75.3 146.1h1.8M75.3 146h1.8M75.3 146.1v.7M75.3 146.8l-.5 1.3M75.3 146.5h2M75.3 146.8h2.3M75.3 146.7l2.3 .1"/>
<path d="M75.3 146.7h2.2M75.3 146.6l2.2 .1M75.3 146.6h2.1M75.3 146.5l2.1 .1M75.3 146.4l2 .1M75.3 146.4h2M75.3 146.3l1.9 .1M75.3 146.3h1.9M75.3 146.2l1.9 .1M75.3 146.2h1.9M75.3 146.1l1.9 .1M76.9 144.8v.9"/>
<path d="M76.9 145.7l.4 .8 .6 .6M77.4 143.8l-10 .1M77.4 143.8h-10M77.4 148a1.89 1.89 0 0 0 1.6 2.3M77.4 143.7l-10 .1M77.5 147.9l-2.7 .1M77.5 143.7h-10.1M77.5 147.8h-2.6M77.6 147.8h-2.7M77.6 147.7h-2.6M77.6 143.6l-10.2 .1M77.6 147.6h-2.6"/>
<path d="M77.6 147.6h-2.5M77.6 143.6h-10.2M77.7 147.5h-2.6M77.7 147.4l-2.6 .1M77.7 143.5l-10.3 .1M77.7 147.4h-2.6M77.7 147.3l-2.6 .1M77.7 143.5h-10.3M77.8 147.3h-2.6M77.8 143.4h-10.4M77.8 147.2l-2.6 .1M77.9 147.2h-2.7"/>
<path d="M77.9 143.3h-10.5M77.9 147.1l-.5 .9M77.9 147.1l-2.7 .1M78 143.3h-10.6M78.1 141.5l.1 .3M78.1 143.2h-10.7M78.2 143.2l-.9 .7-.4 .9M78.2 141.8v1.4M78.2 143.2h-10.8M81 150.2h8.1M81.2 150.2h7.7M81.3 150.1h7.5"/>
<path d="M81.4 150.1h7.3M81.6 150h6.9M81.7 150h6.7M81.7 141.8v1.1h20.6M81.7 149.9h6.7M81.7 142.8l20.5 .1M81.7 142.8h20.4M81.7 142.7h20.2M81.7 142.7h20.1M81.7 142.6h20M81.7 142.5h19.9M81.7 142.4h19.8"/>
<path d="M81.7 142.3l19.8 .1M81.7 142.3h19.7M81.7 142.2l19.6 .1M81.7 142.2h19.6M81.7 142.1l19.6 .1M81.7 142.1h19.5M81.7 142l19.5 .1M81.7 142h19.5M81.7 141.9l19.5 .1M81.7 141.9h19.4M81.7 141.8l19.4 .1M81.7 141.8h19.4"/>
<path d="M81.7 141.7h19.3M81.8 141.6h19.2M81.8 149.9h6.5M81.8 141.5h19.2M81.8 149.8h6.5M81.9 141.5l-.2 .3M81.9 141.5h19M81.9 141.4h19M81.9 141.3h19M81.9 141.2h19M81.9 141.1h19M81.9 141h19"/>
<path d="M81.9 140.9h19M81.9 140.8h19M81.9 140.7h19M81.9 140.6h19M81.9 140.5h19M81.9 140.4h19M81.9 140.3h19M81.9 140.2h19M81.9 140.1h19M81.9 149.8h6.3M81.9 149.7h6.3M82 149.6h6.1"/>
<path d="M82.1 149.5h5.9M82.2 149.5h5.7M82.2 142.9h.1M82.2 149.4h5.7M82.2 142.9h1.9M82.3 149.3h5.5M82.3 149.2l5.5 .1M82.3 149.2h5.5M82.3 147.6h5.5M82.3 149.1h5.5M82.3 147.7h5.4M82.4 149l5.3 .1"/>
<path d="M82.4 147.7h5.3M82.4 149h5.3M82.4 147.8h5.3M82.4 148.9h5.3M82.4 147.9h5.3M82.4 148.8h5.2M82.5 148.8h5.1M82.5 148h5.1M82.5 148.8l-.3 .7-.5 .5-.7 .3M82.5 148v.8M82.5 148.7h5.1M82.5 148.6h5.1"/>
<path d="M82.5 148.5h5.1M82.5 148.4h5.1M82.5 148.3h5.1M82.5 148.2h5.1M82.5 148.1h5.1M84.1 147.5h-1.8l.2 .5M84.1 142.9h-.1M87.5 142.9l.8 .4 .7 .6 .3 .9M87.5 142.9l27.6 .1M87.6 148v.8M87.6 148.8l.3 .7 .5 .5 .7 .3M87.7 143h27.4"/>
<path d="M87.8 143h27.3M87.8 147.5h-5.5M87.8 147.4h.1M87.8 147.4l-.3 .1M87.9 147.4h-.2M87.9 147.3l-.4 .2M87.9 147.3l-.3 .7M87.9 147.3v.1M87.9 143.1h27.2M88.1 143.2h27M88.3 143.3h26.8M88.4 143.3h26.7"/>
<path d="M88.4 143.4h26.7M88.5 143.4h26.6M88.5 143.5h26.6M88.6 143.5h26.5M88.6 143.6h26.5M88.7 143.6h26.4M88.8 143.7h26.3M88.9 143.8h26.2M89 143.9h20.3M89 146.5l-.1 .1M89 146.5h18.2M89 144h20.1"/>
<path d="M89 146.4h18.2M89 146.3h18.2M89 144.1h19.7M89.1 146.3h18.1M89.1 144.1h19.6M89.1 146.2h18.1M89.1 144.2h19.5M89.1 146.5l-.2 .1M89.1 144.2h19.4M89.1 144.3h19.3M89.2 146.1h18M89.2 144.3h19.1"/>
<path d="M89.2 146h18M89.2 144.4h18.9M89.2 145.9h18M89.2 145.9h18.1M89.2 144.5h18.9M89.3 145.8h18M89.3 145.7l-.4 .9M89.3 144.8v.9M89.3 145.6h18M89.3 145.5h18M89.3 145.4h18.1M89.3 145.3h18.1"/>
<path d="M89.3 145.2h18.2M89.3 145.1h18.2M91.1 150.3h.6M91.1 146.5h.6M91.2 150.2h.4M91.2 146.5h.3M91.3 150.2h.1M93.7 146.5l.7 .3 .5 .5M93.7 150.2h21.4M93.8 146.5h13.4M93.9 150.2h21.2M93.9 146.6h13.3"/>
<path d="M94 150.1h21.1M94 146.6h13.2M94.1 150.1h21M94.2 146.7h13M94.3 150h20.8M94.3 146.7h12.9M94.4 150h20.7M94.4 146.8h12.8M94.4 149.9h20.7M94.4 146.9h12.8M94.5 149.9h20.6M94.5 146.9h12.7"/>
<path d="M94.5 149.8h20.6M94.6 147h12.6M94.6 149.8h20.5M94.6 149.7h20.5M94.6 147.1h12.7M94.7 149.6h20.4M94.7 147.1l12.6 .1M94.8 147.2h12.5M94.8 149.5h20.3M94.9 149.5h20.2M94.9 147.3h12.4M94.9 149.5l-.5 .5-.7 .3"/>
<path d="M94.9 147.3l.3 .7v.8l-.3 .7M94.9 149.4h20.2M94.9 147.4h12.4M95 147.4l12.4 .1M95 149.3h20.1M95 147.5h12.4M95 149.2h20.1M95 147.6h12.4M95 149.1h20.1M95 147.7h12.5M95.1 149l14.2 .1M95.1 147.7h12.4"/>
<path d="M95.1 149h14M95.1 147.8h12.4M95.1 148.9h13.8M95.1 147.8h12.5M95.1 148.9h13.7M95.1 147.9h12.5M95.1 148.8h13.6M95.1 147.9l12.5 .1M95.2 148.8h13.4M95.2 148h12.5M95.2 148.7h13.3M95.2 148.7h13.2"/>
<path d="M95.2 148.6h13.1M95.2 148.5l13 .1M95.2 148.5h12.9M95.2 148.4l12.9 .1M95.2 148.4h12.8M95.2 148.3l12.8 .1M95.2 148.3h12.7M95.2 148.2l12.7 .1M95.2 148.2h12.6M95.2 148.1l12.6 .1M95.2 148.1h12.5M95.2 148l12.5 .1"/>
<path d="M100.9 141.5l.3 .7M101.2 142.2l.5 .5 .7 .3M103.3 142.9h11.8M103.5 142.9h11.6M103.6 142.8h11.5M103.7 142.7h11.4M103.8 142.7h11.3M103.9 142.6h11.2M104 142.6h11.1M104 142.5h11.1M104.1 142.5h11M104.1 142.4h11"/>
<path d="M104.2 142.4h10.9M104.2 142.3h10.9M104.3 142.3h10.8M104.4 142.2h10.7M104.4 142.2l-.5 .5-.7 .3M104.4 142.1h10.7M104.5 142h10.6M104.5 141.9h10.6M104.5 141.8h10.6M104.6 141.8h10.5M104.6 141.7h10.5M104.6 141.6h10.5"/>
<path d="M104.7 141.5h10.4M104.7 141.4h10.4M104.7 141.3h10.4M104.7 141.2h10.4M104.7 141.1h10.4M104.7 141h10.4M104.7 140.9h10.4M104.7 140.8h10.4M104.7 140.7h10.4M104.7 140.6h10.4M104.7 140.5h10.4M104.7 140.4h10.4"/>
<path d="M104.7 140.3h10.4M104.7 140.2h10.4M104.7 140.1h10.4M107.2 146.1v.7M107.2 146.8l.5 1.3M107.2 146.5h-18.2M107.2 146.1h-18.1M107.2 146h-18M107.3 145.8h-18M107.3 145.7h-18M107.3 145.6l-18 .1M107.4 145.5h-18.1"/>
<path d="M107.4 145.4h-18.1M107.5 145.3h-18.2M107.5 145.2h-18.2M107.6 145.1h-18.3M107.6 145h-18.3M107.7 144.9l-18.4 .1M107.7 144.9h-18.4M107.7 148.1l1.1 .8 .7 .2M107.7 144.8l-18.4 .1M107.8 144.8h-18.5M107.8 144.7l-18.5 .1M107.9 144.7h-18.6"/>
<path d="M107.9 144.6l-18.6 .1M108 144.6h-18.7M108.1 144.5h-18.9M108.2 144.4l-.5 .5-.5 1.2M108.2 144.4h-19M108.9 144h-19.9M109.5 143.8l-1.3 .6M110.2 143.8l1.2 .6M110.3 143.9h4.8M110.3 149.1h4.8M110.5 149h4.6M110.5 144h4.6"/>
<path d="M110.7 144h4.4M110.7 148.9h4.4M110.8 148.9h4.3M110.9 144.1h4.2M111 148.8h4.1M111.1 144.2h4M111.1 148.7h4M111.2 148.7h3.9M111.2 144.3h3.9M111.3 148.6h3.8M111.3 144.3h3.8M111.4 148.6h3.7"/>
<path d="M111.4 144.4l.5 .5M111.4 148.6l-1.2 .5M111.4 144.4h3.7M111.5 148.5h3.6M111.5 144.4h3.6M111.5 144.5h3.6M111.6 148.4h3.5M111.6 144.5h3.5M111.6 144.6h3.5M111.7 148.3h3.4M111.7 144.6h3.4M111.7 144.7h3.4"/>
<path d="M111.8 148.2h3.3M111.8 144.7h3.3M111.8 144.8h3.3M111.9 148.1h3.2M111.9 144.8h3.2M111.9 144.9l.3 .6M111.9 148.1l-.5 .5M111.9 148h3.2M111.9 144.9h3.2M112 148h3.1M112 144.9h3.1M112 147.9h3.1"/>
<path d="M112 145h3.1M112 145.1h3.1M112 147.8h3.1M112.1 145.1h3M112.1 147.8h3M112.1 145.2h3M112.1 147.7h3M112.1 145.3h3M112.2 147.6h2.9M112.2 145.3h2.9M112.2 145.4h2.9M112.2 147.5h2.9"/>
<path d="M112.2 145.5l.2 .6M112.2 145.5h2.9M112.3 147.4h2.8M112.3 145.5h2.8M112.3 147.3h2.8M112.3 145.6h2.8M112.3 145.7h2.8M112.3 147.2h2.8M112.3 145.8h2.8M112.4 147.1h2.7M112.4 145.9h2.7M112.4 147h2.7"/>
<path d="M112.4 146.9h2.7M112.4 146h2.7M112.4 146.1h2.7M112.4 146.1v.7M112.4 146.8l-.5 1.3M112.4 146.5h2.7M112.4 146.8h2.7M112.4 146.7h2.7M112.4 146.6h2.7M112.4 146.4h2.7M112.4 146.3h2.7M112.4 146.2h2.7"/>
<path d="M117.2 142.9h10.8M117.2 149.1h10.2M117.2 150.3h47.8M117.2 147.4l2.9 .1M117.2 147.5h2.9M117.2 146.5h2.7M117.2 151.6h47.8M117.2 151.5h47.8M117.2 151.4h47.8M117.2 151.3h47.8M117.2 151.2h47.8M117.2 151.1h47.8"/>
<path d="M117.2 151h47.8M117.2 150.9h47.8M117.2 150.8h47.8M117.2 150.7h47.8M117.2 150.6h47.8M117.2 150.5h47.8M117.2 150.4h47.8M117.2 150.2h11.5M117.2 150.2h11.4M117.2 150.1h11.3M117.2 150.1h11.1M117.2 150h11"/>
<path d="M117.2 149.9h10.9M117.2 149.8l10.8 .1M117.2 149.8h10.8M117.2 149.7l10.7 .1M117.2 149.7h10.6M117.2 149.6h10.6M117.2 149.6h10.5M117.2 149.5h10.5M117.2 149.5h10.4M117.2 149.4h10.4M117.2 149.3h10.3M117.2 149.2h10.3"/>
<path d="M117.2 149l4.8 .1M117.2 149h4.6M117.2 148.9h4.4M117.2 148.9h4.3M117.2 148.8h4.1M117.2 148.7h4M117.2 148.7h3.9M117.2 148.6h3.8M117.2 148.5l3.7 .1M117.2 148.5h3.6M117.2 148.4l3.6 .1M117.2 148.4h3.5"/>
<path d="M117.2 148.3l3.5 .1M117.2 148.3h3.4M117.2 148.2l3.4 .1M117.2 148.2h3.3M117.2 148.1l3.3 .1M117.2 148.1h3.2M117.2 148h3.2M117.2 147.9l3.1 .1M117.2 147.9h3.1M117.2 147.8h3.1M117.2 147.8h3M117.2 147.7h3"/>
<path d="M117.2 147.6h2.9M117.2 147.4h2.8M117.2 147.3h2.8M117.2 147.2h2.8M117.2 147.1l2.8 .1M117.2 147.1h2.8M117.2 147h2.7M117.2 146.9h2.7M117.2 146.8h2.7M117.2 146.7h2.7M117.2 146.6h2.7M117.2 146.4h2.7"/>
<path d="M117.2 146.3h2.7M117.2 146.2h2.7M117.2 146.1h2.7M117.2 146h2.7M117.2 145.9h2.7M117.2 145.8h2.8M117.2 145.6h2.8M117.2 145.4h2.9M117.2 145.3h2.9M117.2 145.1h3M117.2 143.5h10.3M117.2 143.1h10.8"/>
<path d="M117.2 143h10.8M117.2 142.8h10.8M117.2 142.7h10.8M117.2 142.6h10.8M117.2 142.5h10.8M117.2 142.4h10.8M117.2 142.3h10.8M117.2 142.2h10.8M117.2 142.1h10.8M117.2 142h10.8M117.2 141.9h10.8M117.2 141.8h10.8"/>
<path d="M117.2 141.7h10.8M117.2 141.6h10.8M117.2 141.5h10.8M117.2 141.5h10.7M117.2 141.4h10.7M117.2 141.3h10.7M117.2 141.2h10.7M117.2 141.1h10.7M117.2 141h10.7M117.2 140.9h10.7M117.2 140.8h10.7M117.2 140.7h10.7"/>
<path d="M117.2 140.6h10.7M117.2 140.5h10.7M117.2 140.4h10.7M117.2 140.3h10.7M117.2 140.2h10.7M117.2 140.1h10.7M119.9 146.1h-2.7M119.9 146h-2.7M120 145.9h-2.8M120 145.8h-2.8M120 145.7h-2.8M120 145.5l-2.8 .1"/>
<path d="M120.1 145.5l-.2 .6 .2 1.4M120.1 145.5h-2.9M120.1 147.5l.8 1.1M120.1 145.4h-2.9M120.2 145.3h-3M120.2 145.2h-3M120.3 145.1h-3.1M120.3 145h-3.1M120.4 144.9l-3.2 .1M120.4 144.9h-3.2M120.4 144.8l-3.2 .1M120.5 144.8h-3.3"/>
<path d="M120.5 144.7l-3.3 .1M120.6 144.7h-3.4M120.6 144.6l-3.4 .1M120.7 144.6h-3.5M120.7 144.5l-3.5 .1M120.8 144.5h-3.6M120.8 144.4l-3.6 .1M120.9 144.4h-3.7M120.9 144.4l-.8 1.1M120.9 148.6l1.3 .5M121 144.3l-3.8 .1M121.1 144.3h-3.9"/>
<path d="M121.2 144.2l-4 .1M121.2 144.2h-4M121.4 144.1h-4.2M121.6 144h-4.4M121.8 144h-4.6M122 143.9h-4.8M122.2 143.8l-1.3 .6M122.9 143.8l1.2 .6M123 143.9h4.1M123 149.1h4.4M123.2 149h4.2M123.2 144h3.9"/>
<path d="M123.4 144h3.7M123.4 148.9h4M123.5 148.9h3.8M123.6 144.1h3.5M123.6 144.1h3.4M123.7 148.8h3.6M123.8 144.2h3.2M123.8 148.7h3.5M123.9 148.7h3.4M123.9 144.3h3.1M124 148.6h3.3M124 144.3h3"/>
<path d="M124.1 148.6h3.2M124.1 144.4h2.8M124.1 144.4l.8 1.1M124.2 148.5h3.1M124.2 144.4h2.7M124.2 144.5h2.7M124.3 148.4h3M124.3 144.5h2.6M124.3 144.6h2.6M124.4 148.3h2.9M124.4 144.6h2.4M124.4 144.7h2.4"/>
<path d="M124.5 148.2h2.8M124.5 144.7h2.3M124.5 144.8h2.3M124.6 148.1h2.7M124.6 144.8h2.2M124.6 148h2.7M124.6 144.9h2.2M124.7 144.9h2.1M124.7 145h2.1M124.7 147.9h2.6M124.7 145.1h2.1M124.8 145.1h2"/>
<path d="M124.8 147.8h2.6M124.8 145.2h2M124.8 147.7h2.6M124.8 145.3h2M124.9 147.6h2.5M124.9 145.3h1.9M124.9 147.6h2.6M124.9 145.4h1.9M124.9 147.5h2.6M124.9 145.5l.2 .6-.2 1.4M124.9 145.5h1.9M124.9 147.5a2.64 2.64 0 0 1-2 1.6"/>
<path d="M125 145.5h1.8M125 147.3h2.6M125 145.6h1.8M125 145.7h1.8M125 145.6l1.8 .1M125 145.8h1.9M125 145.8h1.8M125.1 147.1h2.6M125.1 145.9h1.8M125.1 147h2.6M125.1 147h2.5M125.1 146.9h2.5"/>
<path d="M125.1 146h1.8M125.1 146.9h2.4M125.1 146.8h2.4M125.1 146.1h1.9M125.1 146.5h2M125.1 146.7l2.3 .1M125.1 146.7h2.3M125.1 146.6l2.2 .1M125.1 146.6h2.2M125.1 146.5l2.1 .1M125.1 146.4h2M125.1 146.3h2"/>
<path d="M125.1 146.3h1.9M125.1 146.2h1.9M126.8 144.8v.9M126.8 145.7l.3 .8 .7 .6M127.2 143.8l-10 .1M127.3 143.8h-10.1M127.3 148h-2.6M127.3 143.7l-10.1 .1M127.3 147.9l-2.6 .1M127.4 147.8h-2.7M127.4 143.7h-10.2M127.4 147.7h-2.6"/>
<path d="M127.4 143.6l-10.2 .1M127.5 143.6h-10.3M127.6 147.4h-2.6M127.6 143.5h-10.4M127.6 147.3h-2.6M127.6 143.4h-10.4M127.6 147.2l-2.6 .1M127.7 143.4h-10.5M127.7 147.2h-2.7M127.7 143.3h-10.5M127.7 147.1l-2.7 .1M127.8 147.1a1.87 1.87 0 0 0 1 3.2"/>
<path d="M127.8 143.3h-10.6M128 143.2h-10.8M128 143.2l-.9 .7-.3 .9M128 141.8v1.4M130.9 150.2h8M131 150.2h7.7M131.1 150.1h7.6M131.3 150.1h7.2M131.4 150h7M131.5 149.9h6.7M131.6 149.9h6.6M131.6 141.8v1.1h20.6"/>
<path d="M131.6 142.8l20.4 .1M131.6 142.8h20.3M131.6 142.7h20.2M131.6 142.7h20.1M131.6 142.6h20M131.6 142.6h19.9M131.6 142.5h19.8M131.6 142.4h19.7M131.6 142.3l19.7 .1M131.6 142.3h19.6M131.6 142.2l19.6 .1M131.6 142.2h19.5"/>
<path d="M131.6 142.1l19.5 .1M131.6 142.1h19.4M131.6 142h19.4M131.6 141.9h19.4M131.6 141.8h19.3M131.6 141.7h19.3M131.6 149.9h6.5M131.6 141.6h19.3M131.6 141.6h19.2M131.7 149.8h6.4M131.7 141.5h19.1M131.7 141.4h19.1"/>
<path d="M131.7 141.3h19.1M131.7 141.2h19.1M131.7 141.1h19.1M131.7 141h19.1M131.7 140.9h19.1M131.7 140.8h19.1M131.7 140.7h19.1M131.7 140.6h19.1M131.7 140.5h19.1M131.7 140.4h19.1M131.7 140.3h19.1M131.7 140.2h19.1"/>
<path d="M131.7 140.1h19.1M131.7 149.8h6.3M131.8 149.7h6.2M131.8 149.6h6.1M131.9 149.6h6M131.9 149.5h5.9M132 149.5h5.8M132 149.4h5.7M132.1 142.9h1.8M132.1 149.4h5.6M132.1 149.3h5.6M132.1 147.5h5.5"/>
<path d="M132.1 149.2h5.5M132.1 147.6h5.5M132.2 149.1h5.4M132.2 147.6h5.4M132.2 147.7h5.4M132.2 149h5.4M132.2 149h5.3M132.2 147.8h5.3M132.2 148.9h5.3M132.3 148.9h5.2M132.3 147.9h5.2M132.3 148.8h5.2"/>
<path d="M132.3 148h5.2M132.3 148.7h5.1M132.3 148.6h5.1M132.3 148.5h5.1M132.3 148.4h5.1M132.3 148.3h5.1M132.3 148.2h5.1M132.3 148.1h5.1M132.3 148h5.1M133.9 147.5h.1M133.9 147.5h-1.8a1.86 1.86 0 0 1-1.3 2.8M133.9 142.9h.1"/>
<path d="M137.4 142.9l.8 .4 .6 .6M137.4 142.9l27.6 .1M137.4 147.5h.3M137.4 148v.8M137.4 148.8l.3 .7 .6 .5 .7 .3M137.5 143h27.5M137.6 147.4h.1M137.6 143h27.4M137.7 147.4h-.2M137.7 147.3l-.3 .2M137.7 147.3l-.3 .7M137.7 147.3v.1"/>
<path d="M137.7 143.1h27.3M137.9 143.2h27.1M138 143.2h27M138.1 143.3h26.9M138.2 143.3h26.8M138.3 143.4h26.7M138.4 143.5h26.6M138.5 143.5h26.5M138.5 143.6h26.5M138.6 143.6h26.4M138.6 143.7h26.4M138.7 143.7h26.3"/>
<path d="M138.7 143.8h26.3M138.8 143.8h26.2M138.8 143.9h20.4M138.8 146.5l-.1 .1M138.8 143.9l.4 .9M138.9 146.5l-.1 .1M138.9 146.4h18.1M138.9 146.3h18.1M139 146.2h18M139 146.5l-.3 .1M139 146.1h18M139 146h18.1"/>
<path d="M139 144.4h19M139.1 144.5h18.8M139.1 145.9h18M139.1 145.8h18M139.1 144.6h18.7M139.1 144.7h18.6M139.2 145.6h17.9M139.2 145.5h18M139.2 145.4h18M139.2 144.8h18.4M139.2 145.7l-.4 .8M139.2 144.8v.9"/>
<path d="M141 146.5h.5M141 150.2h.4M141.1 146.5h.3M141.2 150.2h.1M141.2 150.2l-.2 .1M141.2 150.2l.3 .1M143.5 146.5l.7 .3 .5 .5 .3 .7M143.6 150.2h21.4M143.6 146.5h13.4M143.7 150.2h21.3M143.8 146.6h13.2M143.8 150.1h21.2"/>
<path d="M143.9 146.6h13.1M144 150.1h21M144 146.7h13M144.1 150h20.9M144.1 146.7h12.9M144.2 149.9h20.8M144.2 146.8h12.8M144.3 149.9h20.7M144.3 146.9h12.7M144.3 146.9h12.8M144.4 149.8h20.6M144.4 147h12.7"/>
<path d="M144.5 149.7h20.5M144.5 147.1h12.6M144.5 149.6h20.5M144.6 149.6h20.4M144.6 147.2h12.5M144.6 149.5h20.4M144.7 147.2l12.4 .1M144.7 149.5h20.3M144.7 147.3h12.4M144.7 149.4h20.3M144.7 147.3h12.5M144.8 149.4h20.2"/>
<path d="M144.8 147.4h12.4M144.8 149.3h20.2M144.8 147.5h12.4M144.8 149.2h20.2M144.8 147.6h12.5M144.8 147.6h12.4M144.9 149.1h20.1M144.9 149.1h14.3M144.9 147.7h12.4M144.9 149h14.1M144.9 147.8h12.5M144.9 148.9h13.8"/>
<path d="M144.9 148.9h13.7M145 147.9h12.4M145 148.8h13.5M145 148.8h13.4M145 147.9h12.5M145 148h12.5M145 148.7h13.3M145 148.7h13.2M145 148.6h13.1M145 148.5l13.1 .1M145 148.5h13M145 148.4l12.9 .1"/>
<path d="M145 148.4h12.9M145 148.3l12.8 .1M145 148.3h12.8M145 148.2l12.7 .1M145 148.2h12.7M145 148.1l12.6 .1M145 148.1h12.6M145 148a1.92 1.92 0 0 1-1.5 2.3M151.1 142.2l.5 .5 .7 .3M153.2 142.9h11.8M153.3 142.9h11.7M153.4 142.8h11.6"/>
<path d="M153.5 142.7h11.5M153.6 142.7h11.4M153.8 142.6h11.2M153.9 142.5h11.1M154 142.4h11M154.1 142.3h10.9M154.2 142.2h10.8M154.3 142.1h10.7M154.3 142.2l-.6 .5-.7 .3M154.3 142h10.7M154.4 141.9h10.6M154.4 141.8h10.6"/>
<path d="M154.5 141.7h10.5M154.5 141.6h10.5M154.5 141.5h10.5M154.5 141.4h10.5M154.5 141.3h10.5M154.5 141.2h10.5M154.5 141.1h10.5M154.5 141h10.5M154.5 140.9h10.5M154.5 140.8h10.5M154.5 140.7h10.5M154.5 140.6h10.5"/>
<path d="M154.5 140.5h10.5M154.5 140.4h10.5M154.5 140.3h10.5M154.5 140.2h10.5M154.5 140.1h10.5M154.5 141.5l-.2 .7M157 146.1v.7M157 146.5h-18.2M157 146.8l.2 .7M157.1 145.9h-18M157.1 145.7h-18M157.2 145.6h-18"/>
<path d="M157.2 147.5a2.64 2.64 0 0 0 2.1 1.6M157.2 145.5l-.2 .6M157.2 145.4h-18M157.3 145.3l-18.1 .1M157.3 145.3h-18.1M157.3 145.2h-18.1M157.4 145.2h-18.2M157.4 145.1h-18.2M157.5 145h-18.3M157.5 144.9l-18.3 .1M157.5 144.9h-18.3M157.6 144.8l-18.4 .1"/>
<path d="M157.7 144.7l-18.5 .1M157.8 144.6l-18.7 .1M157.9 144.5h-18.8M158 144.4h-19M158 144.4l-.8 1.1M158.1 144.3h-19.1M158.2 144.3h-19.2M158.3 144.2h-19.3M158.4 144.2h-19.5M158.5 144.1h-19.6M158.6 144.1h-19.7M158.7 144h-19.8"/>
<path d="M158.9 144h-20M159.3 143.8l-1.3 .6M160 143.8a2.73 2.73 0 0 1 2.1 1.7M160.1 149.1h4.9M160.1 143.9h4.9M160.3 149h4.7M160.4 144h4.6M160.5 144h4.5M160.6 148.9h4.4M160.7 148.9h4.3M160.7 144.1h4.3M160.8 148.8h4.2"/>
<path d="M160.8 144.1h4.2M160.9 144.2h4.1M161 144.2h4M161 148.7h4M161.1 148.7h3.9M161.1 144.3h3.9M161.2 148.6h3.8M161.2 144.3h3.8M161.2 148.6l-1.2 .5M161.3 144.4h3.7M161.3 148.5h3.7M161.4 144.5h3.6"/>
<path d="M161.4 148.4h3.6M161.5 148.4h3.5M161.5 144.6h3.5M161.5 148.3h3.5M161.6 148.3h3.4M161.6 144.7h3.4M161.6 148.2h3.4M161.7 144.8h3.3M161.7 148.1h3.3M161.8 148.1h3.2M161.8 144.9h3.2M161.8 148h3.2"/>
<path d="M161.8 145h3.2M161.9 147.9h3.1M161.9 145.1h3.1M161.9 147.8h3.1M161.9 145.2h3.1M161.9 147.7h3.1M162 147.7h3M162 145.3h3M162 147.6h3M162 145.4h3M162.1 147.6h2.9M162.1 147.5h2.9"/>
<path d="M162.1 145.4h2.9M162.1 147.4h2.9M162.1 145.5h2.9M162.1 145.5l.2 .6M162.1 147.5l-.9 1.1M162.1 145.6h2.9M162.1 147.3h2.9M162.2 147.2h2.8M162.2 145.7h2.8M162.2 147.1h2.8M162.2 145.8h2.8M162.2 145.9h2.8"/>
<path d="M162.2 147h2.8M162.2 146h2.8M162.2 146.9h2.8M162.3 146.1v.7M162.3 146.5h2.7M162.3 146.8h2.7M162.3 146.7h2.7M162.3 146.6h2.7M162.3 146.4h2.7M162.3 146.3h2.7M162.3 146.2h2.7M162.3 146.1h2.7"/>
<path d="M162.3 146.8l-.2 .7M167 142.9h10.9M167 149.1h10.3M167 150.3h47.8M167 147.4h2.9M167 147.5h2.9M167 146.5h2.7M167 151.6h47.8M167 151.5h47.8M167 151.4h47.8M167 151.3h47.8M167 151.2h47.8"/>
<path d="M167 151.1h47.8M167 151h47.8M167 150.9h47.8M167 150.8h47.8M167 150.7h47.8M167 150.6h47.8M167 150.5h47.8M167 150.4h47.8M167 150.2h11.6M167 150.2h11.4M167 150.1h11.3M167 150.1h11.2"/>
<path d="M167 150h11.1M167 149.9l10.9 .1M167 149.9h10.9M167 149.8l10.8 .1M167 149.8h10.8M167 149.7l10.7 .1M167 149.7h10.7M167 149.6h10.6M167 149.5h10.5M167 149.5h10.4M167 149.4h10.4M167 149.3h10.4"/>
<path d="M167 149.2h10.3M167 149.1l10.3 .1M167 149l4.9 .1M167 149h4.7M167 148.9h4.4M167 148.9h4.3M167 148.8h4.2M167 148.8h4.1M167 148.7h4M167 148.7h3.9M167 148.6h3.8M167 148.5l3.8 .1"/>
<path d="M167 148.5h3.7M167 148.4l3.6 .1M167 148.4h3.6M167 148.3l3.5 .1M167 148.3h3.5M167 148.2l3.4 .1M167 148.2h3.4M167 148.1l3.3 .1M167 148.1h3.3M167 148h3.2M167 147.9h3.2M167 147.9h3.1"/>
<path d="M167 147.8h3.1M167 147.7h3M167 147.6h3M167 147.6h2.9M167 147.3h2.9M167 147.3h2.8M167 147.2l2.8 .1M167 147.2h2.8M167 147.1h2.8M167 147h2.8M167 146.9h2.7M167 146.8h2.7"/>
<path d="M167 146.7h2.7M167 146.6h2.7M167 146.4h2.7M167 146.3h2.7M167 146.2h2.7M167 146.1h2.7M167 146h2.8M167 145.9h2.8M167 145.8h2.8M167 145.7h2.8M167 145.6h2.8M167 145.5h2.9"/>
<path d="M167 144.9h3.2M167 144.8h3.3M167 144.5h3.6M167 143.1h10.9M167 143h10.9M167 142.8h10.9M167 142.7h10.9M167 142.6h10.9M167 142.5h10.9M167 142.4h10.9M167 142.3h10.9M167 142.2h10.9"/>
<path d="M167 142.1h10.9M167 142h10.9M167 141.9h10.9M167 141.8h10.9M167 141.7l10.9 .1M167 141.7h10.9M167 141.6h10.8M167 141.5h10.8M167 141.4h10.8M167 141.3h10.8M167 141.2h10.8M167 141.1h10.8"/>
<path d="M167 141h10.8M167 140.9h10.8M167 140.8h10.8M167 140.7h10.8M167 140.6h10.8M167 140.5h10.8M167 140.4h10.8M167 140.3h10.8M167 140.2h10.8M167 140.1h10.8M169.7 146.1v.7M169.7 146.8l.5 1.3"/>
<path d="M169.7 146.1h-2.7M169.8 145.9h-2.8M169.8 145.8h-2.8M169.9 145.6h-2.9M169.9 145.5l-.2 .6M169.9 145.4l-2.9 .1M169.9 145.4h-2.9M170 145.3l-3 .1M170 145.3h-3M170 145.2h-3M170.1 145.2h-3.1M170.1 145.1h-3.1"/>
<path d="M170.2 145h-3.2M170.2 144.9l-3.2 .1M170.2 144.9l-.3 .6M170.2 148.1l.5 .5M170.3 144.8l-3.3 .1M170.4 144.7l-3.4 .1M170.4 144.7h-3.4M170.5 144.6l-3.5 .1M170.5 144.6h-3.5M170.6 144.5h-3.6M170.7 144.4l-3.7 .1M170.7 144.4h-3.7"/>
<path d="M170.7 144.4l-.5 .5M170.7 148.6l1.3 .5M170.8 144.3l-3.8 .1M170.9 144.3h-3.9M171 144.2l-4 .1M171.1 144.2h-4.1M171.2 144.1h-4.2M171.3 144.1h-4.3M171.4 144h-4.4M171.6 144h-4.6M171.9 143.9h-4.9M172 143.8l-1.3 .6"/>
<path d="M172.7 143.8l1.2 .6M172.8 149.1h4.4M172.8 143.9h4.2M173 149h4.2M173.1 144h3.9M173.2 148.9h4M173.2 144h3.7M173.4 148.9h3.8M173.4 144.1h3.5M173.5 148.8h3.7M173.5 144.1h3.4M173.5 148.8h3.6"/>
<path d="M173.6 144.2h3.3M173.7 144.2h3.1M173.7 148.7h3.4M173.8 148.7h3.3M173.8 144.3h3M173.9 148.6h3.2M173.9 144.3h2.9M173.9 144.4l.5 .5M174 144.4h2.8M174 148.5h3.1M174.1 144.5h2.6M174.1 148.4h3"/>
<path d="M174.2 148.4h2.9M174.2 144.6h2.5M174.2 148.3h2.9M174.3 148.3h2.8M174.3 144.7h2.3M174.3 148.2h2.8M174.4 144.8h2.2M174.4 148.1h2.7M174.4 148.1l-1 .8-.7 .2M174.4 144.9l.6 1.2M174.5 148.1h2.6M174.5 144.9h2.1"/>
<path d="M174.5 148h2.6M174.5 145h2.1M174.6 145.1h2M174.6 145.2h2M174.7 147.7h2.6M174.7 145.3h1.9M174.7 145.4h1.9M174.8 145.4h1.8M174.8 145.5h1.8M174.8 145.6h1.8M174.9 145.8h1.8M174.9 145.7h1.8"/>
<path d="M174.9 147.1h2.7M174.9 147h2.6M174.9 145.9h1.8M174.9 146h1.9M174.9 146.9h2.5M175 146.1v.7M175 146.5h2M175 146.8h2.3M175 146.7l2.2 .1M175 146.7h2.2M175 146.6l2.1 .1M175 146.6h2.1"/>
<path d="M175 146.5l2.1 .1M175 146.4l2 .1M175 146.4h1.9M175 146.3l1.9 .1M175 146.3h1.9M175 146.2h1.9M175 146.2h1.8M175 146.1h1.8M175 146.8l-.6 1.3M176.6 144.8v.9M176.6 145.7l.4 .8 .6 .6M177 143.8l-10 .1"/>
<path d="M177.1 143.8h-10.1M177.1 143.7l-10.1 .1M177.1 148v.8M177.1 148.8l.3 .7 .5 .5 .7 .3M177.2 147.9l-2.7 .1M177.2 147.9h-2.6M177.2 143.7h-10.2M177.2 147.8h-2.6M177.2 147.7h-2.6M177.2 143.6l-10.2 .1M177.3 147.6h-2.6M177.3 143.6h-10.3"/>
<path d="M177.3 147.5h-2.5M177.4 147.4l-2.6 .1M177.4 143.5l-10.4 .1M177.4 147.4h-2.6M177.4 147.3l-2.6 .1M177.4 143.5h-10.4M177.4 147.3h-2.6M177.4 143.4h-10.4M177.5 147.2l-2.6 .1M177.5 143.4h-10.5M177.5 147.2h-2.6M177.6 143.3h-10.6"/>
<path d="M177.6 147.1l-2.7 .1M177.6 147.1l-.5 .9M177.7 143.3h-10.7M177.8 141.5l.1 .3M177.8 143.2h-10.8M177.9 143.2h-10.9M177.9 143.2l-.9 .7-.4 .9M177.9 141.8v1.4M180.7 150.2h8M180.8 150.2h7.8M181 150.1h7.5M181.1 150.1h7.2"/>
<path d="M181.2 150h7M181.4 150h6.7M181.4 141.8v1.1h20.6M181.4 149.9h6.6M181.4 142.8l20.4 .1M181.4 142.8h20.4M181.4 142.7h20.2M181.4 142.7h20.1M181.4 142.6h20M181.4 142.5h19.9M181.4 142.4h19.8M181.4 142.3l19.7 .1"/>
<path d="M181.4 142.3h19.7M181.4 142.2l19.6 .1M181.4 142.2h19.6M181.4 142.1l19.5 .1M181.4 142.1h19.5M181.4 142l19.5 .1M181.4 142h19.5M181.4 141.9l19.4 .1M181.4 141.9h19.4M181.4 141.8l19.4 .1M181.4 141.8h19.3M181.4 141.7h19.3"/>
<path d="M181.4 141.6h19.3M181.5 149.9h6.5M181.5 141.6h19.2M181.5 141.5h19.1M181.5 149.8h6.4M181.5 141.4h19.1M181.5 141.3h19.1M181.5 141.2h19.1M181.5 141.1h19.1M181.5 141h19.1M181.5 140.9h19.1M181.5 140.8h19.1"/>
<path d="M181.5 140.7h19.1M181.5 140.6h19.1M181.5 140.5h19.1M181.5 140.4h19.1M181.5 140.3h19.1M181.5 140.2h19.1M181.5 140.1h19.1M181.5 141.5l-.1 .3M181.6 149.8h6.3M181.6 149.7h6.2M181.7 149.6h6.1M181.7 149.6h6"/>
<path d="M181.8 149.5h5.9M181.8 149.5h5.8M181.9 149.4h5.7M181.9 149.5l-.5 .5-.7 .3M181.9 142.9h.1M181.9 142.9h1.8M181.9 149.4h5.6M181.9 149.3h5.6M181.9 147.5h5.6M181.9 149.2h5.6M182 149.2h5.5M182 147.6h5.5"/>
<path d="M182 149.1h5.4M182 147.7h5.4M182.1 149h5.3M182.1 147.8h5.3M182.1 148.9h5.3M182.1 148.9h5.2M182.1 148.8h5.2M182.1 147.9h5.2M182.2 148.7h5.1M182.2 148.6h5.1M182.2 148.5h5.1M182.2 148.4h5.1"/>
<path d="M182.2 148.3h5.1M182.2 148.2h5.1M182.2 148.1h5.1M182.2 148h5.1M182.2 148v.8l-.3 .7M183.7 147.5h.1M183.7 147.5h-1.8l.3 .5M183.7 142.9h.1M187.2 142.9l27.6 .1M187.2 142.9l.8 .4 .7 .6 .3 .9M187.3 148v.8l.3 .7M187.3 143h27.5"/>
<path d="M187.5 143h27.3M187.5 147.4l-.3 .1M187.5 147.4h-.2M187.6 147.3l-.1 .1M187.6 147.3l-.4 .2M187.6 147.3l-.3 .7M187.6 149.5l.5 .5 .7 .3M187.6 147.3v.1M187.6 143.1h27.2M187.7 143.2h27.1M187.8 143.2h27M188 143.3h26.8"/>
<path d="M188.1 143.3h26.7M188.1 143.4h26.7M188.2 143.4h26.6M188.2 143.5h26.6M188.3 143.5h26.5M188.3 143.6h26.5M188.4 143.6h26.4M188.4 143.7h26.4M188.5 143.7h26.3M188.5 143.8h26.3M188.6 143.8h26.2M188.6 146.6h.1"/>
<path d="M188.6 143.9h20.4M188.7 146.5l-.1 .1M188.7 146.5h18.2M188.7 144h20.1M188.7 146.4h18.2M188.7 144h19.9M188.7 144.1h19.7M188.7 146.3h18.2M188.7 144.1h19.6M188.8 146.3h18.1M188.8 144.2h19.4M188.8 146.2h18.1"/>
<path d="M188.8 146.5l-.2 .1M188.8 144.3h19.2M188.8 146.1h18.1M188.8 146h18.1M188.9 144.4h18.9M188.9 144.5h18.8M188.9 145.9h18M189 145.8h17.9M189 145.7h18M189 145.5h18M189 145.2h18.2M189 145.1h18.2"/>
<path d="M189 145h18.3M189 145.7l-.4 .9M189 144.8v.9M190.8 150.3h.5M190.8 146.5h.5M190.9 150.2h.4M190.9 146.5h.3M191 150.2h.1M193.4 146.5l.6 .3 .6 .5 .3 .7M193.4 150.2h21.4M193.5 146.5h13.4M193.5 150.2h21.3"/>
<path d="M193.6 146.6h13.3M193.7 150.1h21.1M193.7 146.6h13.2M193.8 150.1h21M193.9 146.7h13M193.9 150h20.9M194 146.7h12.9M194.1 150h20.7M194.1 146.8h12.8M194.1 149.9h20.7M194.1 146.9h12.8M194.2 149.9h20.6"/>
<path d="M194.2 146.9h12.7M194.2 149.8h20.6M194.2 147h12.7M194.3 149.8h20.5M194.3 147h12.6M194.3 149.7h20.5M194.3 147.1h12.6M194.4 149.6h20.4M194.4 147.1h12.5M194.4 147.2h12.6M194.5 149.5h20.3M194.5 147.2h12.5"/>
<path d="M194.5 147.3h12.5M194.6 149.4h20.2M194.6 147.3h12.4M194.6 147.4h12.4M194.6 149.3h20.2M194.6 147.5h12.5M194.6 149.2h20.2M194.7 149.2h20.1M194.7 147.6h12.4M194.7 149.1h20.1M194.7 147.7h12.4M194.7 149.1h14.3"/>
<path d="M194.7 147.7h12.5M194.8 149h14M194.8 147.8h12.4M194.8 148.9h13.8M194.8 148.9h13.6M194.8 147.9h12.5M194.8 148.8h13.5M194.8 147.9l12.5 .1M194.8 148h12.5M194.9 148.7h13.3M194.9 148.7h13.2M194.9 148.6h13.1"/>
<path d="M194.9 148.5l13 .1M194.9 148.5h12.9M194.9 148.4l12.9 .1M194.9 148.4h12.8M194.9 148.3l12.8 .1M194.9 148.3h12.7M194.9 148.2l12.7 .1M194.9 148.2h12.6M194.9 148.1l12.6 .1M194.9 148.1h12.5M194.9 148l12.5 .1M194.9 148.8l-.3 .7-.6 .5-.6 .3"/>
<path d="M194.9 148v.8M200.6 141.5l.3 .7 .5 .5 .7 .3M203 142.9h11.8M203.1 142.9h11.7M203.2 142.8h11.6M203.4 142.7h11.4M203.5 142.7h11.3M203.6 142.6h11.2M203.7 142.5h11.1M203.8 142.5h11M203.8 142.4h11M203.9 142.4h10.9"/>
<path d="M203.9 142.3h10.9M204 142.3h10.8M204 142.2h10.8M204.1 142.2h10.7M204.1 142.2l-.5 .5-.7 .3M204.1 142.1h10.7M204.1 142h10.7M204.2 142h10.6M204.2 141.9h10.6M204.2 141.8h10.6M204.3 141.8h10.5M204.3 141.7h10.5"/>
<path d="M204.3 141.6h10.5M204.3 141.5h10.5M204.4 141.5h10.4M204.4 141.4h10.4M204.4 141.3h10.4M204.4 141.2h10.4M204.4 141.1h10.4M204.4 141h10.4M204.4 140.9h10.4M204.4 140.8h10.4M204.4 140.7h10.4M204.4 140.6h10.4"/>
<path d="M204.4 140.5h10.4M204.4 140.4h10.4M204.4 140.3h10.4M204.4 140.2h10.4M204.4 140.1h10.4M204.4 141.5l-.3 .7M206.9 146.1v.7M206.9 146.5h-18.3M206.9 146.8l.1 .7M206.9 146h-18M206.9 145.9h-18M206.9 145.8h-17.9"/>
<path d="M207 145.6l-18 .1M207 145.6h-18M207 147.5l.9 1.1M207 145.5h-18M207 145.5l-.1 .6M207.1 145.4l-18.1 .1M207.1 145.4h-18.1M207.1 145.3l-18.1 .1M207.1 145.3h-18.1M207.2 145.2h-18.2M207.3 145.1h-18.3M207.3 144.9l-18.3 .1"/>
<path d="M207.3 144.9h-18.3M207.4 144.8l-18.4 .1M207.4 144.8h-18.4M207.5 144.7l-18.5 .1M207.5 144.7h-18.5M207.6 144.6l-18.6 .1M207.7 144.6h-18.7M207.8 144.5h-18.9M207.9 144.4h-19M207.9 148.6l1.2 .5M209.1 143.8a2.73 2.73 0 0 0-2.1 1.7M209.8 143.8l1.3 .6"/>
<path d="M210 143.9h4.8M210 149.1h4.8M210.2 149h4.6M210.2 144h4.6M210.4 148.9h4.4M210.4 144h4.4M210.5 148.9h4.3M210.6 144.1h4.2M210.6 148.8h4.2M210.7 148.8h4.1M210.7 144.2h4.1M210.8 148.7h4"/>
<path d="M210.8 144.2h4M210.9 148.7h3.9M210.9 144.3h3.9M211 144.3h3.8M211 148.6h3.8M211.1 148.6h3.7M211.1 144.4h3.7M211.1 144.4l.8 1.1 .2 .6M211.1 148.5h3.7M211.2 148.5h3.6M211.2 144.5h3.6M211.2 148.4h3.6"/>
<path d="M211.3 148.4h3.5M211.3 144.6h3.5M211.3 148.3h3.5M211.4 148.3h3.4M211.4 144.7h3.4M211.5 148.2h3.3M211.5 144.7h3.3M211.5 144.8h3.3M211.6 148.1h3.2M211.6 144.8h3.2M211.6 148h3.2M211.6 144.9h3.2"/>
<path d="M211.7 147.9h3.1M211.7 145h3.1M211.7 145.1h3.1M211.7 147.8h3.1M211.8 147.8h3M211.8 145.2h3M211.8 147.7h3M211.8 145.3h3M211.8 147.6h3M211.9 145.3h2.9M211.9 147.6h2.9M211.9 145.4h2.9"/>
<path d="M211.9 147.5h2.9M211.9 147.4h2.9M211.9 145.5h2.9M212 147.3h2.8M212 145.6h2.8M212 145.7h2.8M212 147.2h2.8M212 145.8h2.8M212 147.1h2.8M212 145.9h2.8M212 147h2.8M212.1 147h2.7"/>
<path d="M212.1 146.9h2.7M212.1 146h2.7M212.1 146.1h2.7M212.1 146.1v.7M212.1 146.5h2.7M212.1 146.8h2.7M212.1 146.7h2.7M212.1 146.6h2.7M212.1 146.4h2.7M212.1 146.3h2.7M212.1 146.2h2.7M212.1 146.8a2.67 2.67 0 0 1-2.3 2.3"/>
</g>
<path d="M102.5 57.3v2.8l-.3 .4M102.5 59.9l-.5 .6M152.3 57.3v2.8l-.3 .4M152.3 59.9l-.5 .6M202.2 57.3v2.8l-.3 .4M202.2 59.9l-.5 .6M80.3 145.2l-.3 .3v2.9M80.5 145.2l-.5 .5M130.1 145.2l-.3 .3v2.9M130.3 145.2l-.5 .5M180 145.2l-.4 .3v2.9M180.2 145.2l-.6 .5" fill="none" stroke="#000" stroke-width="1"/>
<circle cx="98.4" cy="87.8" r=".71" fill="#000" stroke="#000" stroke-width=".21"/>
<circle cx="98.4" cy="87.8" r=".4" fill="#fff" stroke="#000" stroke-width=".21"/>
<circle cx="103.5" cy="87.8" r=".71" fill="#000" stroke="#000" stroke-width=".21"/>
<circle cx="103.5" cy="87.8" r=".4" fill="#fff" stroke="#000" stroke-width=".21"/>
<circle cx="85.4" cy="77.6" r=".71" fill="#000" stroke="#000" stroke-width=".21"/>
<circle cx="85.4" cy="77.6" r=".4" fill="#fff" stroke="#000" stroke-width=".21"/>
<circle cx="85.4" cy="72.5" r=".71" fill="#000" stroke="#000" stroke-width=".21"/>
<circle cx="85.4" cy="72.5" r=".4" fill="#fff" stroke="#000" stroke-width=".21"/>
<circle cx="98.4" cy="72.5" r=".71" fill="#000" stroke="#000" stroke-width=".21"/>
<circle cx="98.4" cy="72.5" r=".4" fill="#fff" stroke="#000" stroke-width=".21"/>
<circle cx="103.5" cy="72.5" r=".71" fill="#000" stroke="#000" stroke-width=".21"/>
<circle cx="103.5" cy="72.5" r=".4" fill="#fff" stroke="#000" stroke-width=".21"/>
<circle cx="103.5" cy="77.6" r=".71" fill="#000" stroke="#000" stroke-width=".21"/>
<circle cx="103.5" cy="77.6" r=".4" fill="#fff" stroke="#000" stroke-width=".21"/>
<circle cx="98.4" cy="77.6" r=".71" fill="#000" stroke="#000" stroke-width=".21"/>
<circle cx="98.4" cy="77.6" r=".4" fill="#fff" stroke="#000" stroke-width=".21"/>
<path d="M79 57.3h1.3" fill="none" stroke="#000" stroke-width="1.3"/>
<circle cx="79.7" cy="57.3" r=".4" fill="#fff" stroke="#000" stroke-width=".21"/>
<path d="M89.2 57.3h1.3" fill="none" stroke="#000" stroke-width="1.3"/>
<circle cx="89.8" cy="57.3" r=".4" fill="#fff" stroke="#000" stroke-width=".21"/>
<path d="M101.9 57.3h1.3" fill="none" stroke="#000" stroke-width="1.3"/>
<circle cx="102.5" cy="57.3" r=".4" fill="#fff" stroke="#000" stroke-width=".21"/>
<path d="M91.7 57.3h1.3" fill="none" stroke="#000" stroke-width="1.3"/>
<circle cx="92.4" cy="57.3" r=".4" fill="#fff" stroke="#000" stroke-width=".21"/>
<path d="M84.2 60.5h2.5" fill="none" stroke="#000" stroke-width="2.5"/>
<circle cx="85.5" cy="60.5" r=".55" fill="#fff" stroke="#000" stroke-width=".21"/>
<path d="M78.9 60.5h2.5" fill="none" stroke="#000" stroke-width="2.5"/>
<circle cx="80.2" cy="60.5" r=".55" fill="#fff" stroke="#000" stroke-width=".21"/>
<path d="M100.7 60.5h2.6" fill="none" stroke="#000" stroke-width="2.5"/>
<circle cx="102" cy="60.5" r=".55" fill="#fff" stroke="#000" stroke-width=".21"/>
<path d="M95.4 60.5h2.6" fill="none" stroke="#000" stroke-width="2.5"/>
<circle cx="96.7" cy="60.5" r=".55" fill="#fff" stroke="#000" stroke-width=".21"/>
<circle cx="77.1" cy="88.7" r=".71" fill="#000" stroke="#000" stroke-width=".21"/>
<circle cx="77.1" cy="88.7" r=".4" fill="#fff" stroke="#000" stroke-width=".21"/>
<circle cx="84.7" cy="88.7" r=".71" fill="#000" stroke="#000" stroke-width=".21"/>
<circle cx="84.7" cy="88.7" r=".4" fill="#fff" stroke="#000" stroke-width=".21"/>
<circle cx="102.5" cy="65.2" r=".83" fill="#000" stroke="#000" stroke-width=".21"/>
<circle cx="102.5" cy="65.2" r=".51" fill="#fff" stroke="#000" stroke-width=".21"/>
<circle cx="79.7" cy="65.2" r=".83" fill="#000" stroke="#000" stroke-width=".21"/>
<circle cx="79.7" cy="65.2" r=".51" fill="#fff" stroke="#000" stroke-width=".21"/>
<path d="M74.6 84.6v1.3" fill="none" stroke="#000" stroke-width="1.3"/>
<circle cx="74.6" cy="85.2" r=".4" fill="#fff" stroke="#000" stroke-width=".21"/>
<path d="M77.1 84.6v1.3" fill="none" stroke="#000" stroke-width="1.3"/>
<circle cx="77.1" cy="85.2" r=".4" fill="#fff" stroke="#000" stroke-width=".21"/>
<path d="M77.1 76.9v1.4" fill="none" stroke="#000" stroke-width="1.3"/>
<circle cx="77.1" cy="77.6" r=".4" fill="#fff" stroke="#000" stroke-width=".21"/>
<path d="M74.6 76.9v1.4" fill="none" stroke="#000" stroke-width="1.3"/>
<circle cx="74.6" cy="77.6" r=".4" fill="#fff" stroke="#000" stroke-width=".21"/>
<path d="M79.7 84.6v1.3" fill="none" stroke="#000" stroke-width="1.3"/>
<circle cx="79.7" cy="85.2" r=".4" fill="#fff" stroke="#000" stroke-width=".21"/>
<path d="M82.2 84.6v1.3" fill="none" stroke="#000" stroke-width="1.3"/>
<circle cx="82.2" cy="85.2" r=".4" fill="#fff" stroke="#000" stroke-width=".21"/>
<path d="M79.7 76.9v1.4" fill="none" stroke="#000" stroke-width="1.3"/>
<circle cx="79.7" cy="77.6" r=".4" fill="#fff" stroke="#000" stroke-width=".21"/>
<path d="M82.2 76.9v1.4" fill="none" stroke="#000" stroke-width="1.3"/>
<circle cx="82.2" cy="77.6" r=".4" fill="#fff" stroke="#000" stroke-width=".21"/>
<path d="M89 87.7h1.3" fill="none" stroke="#000" stroke-width="1.3"/>
<circle cx="89.6" cy="87.7" r=".4" fill="#fff" stroke="#000" stroke-width=".21"/>
<path d="M89 85.2h1.3" fill="none" stroke="#000" stroke-width="1.3"/>
<circle cx="89.6" cy="85.2" r=".4" fill="#fff" stroke="#000" stroke-width=".21"/>
<path d="M89 77.6h1.3" fill="none" stroke="#000" stroke-width="1.3"/>
<circle cx="89.6" cy="77.6" r=".4" fill="#fff" stroke="#000" stroke-width=".21"/>
<path d="M89 75h1.3" fill="none" stroke="#000" stroke-width="1.3"/>
<circle cx="89.6" cy="75" r=".4" fill="#fff" stroke="#000" stroke-width=".21"/>
<path d="M89 72.5h1.3" fill="none" stroke="#000" stroke-width="1.3"/>
<circle cx="89.6" cy="72.5" r=".4" fill="#fff" stroke="#000" stroke-width=".21"/>
<path d="M90.1 94.6v1.5" fill="none" stroke="#000" stroke-width="1.5"/>
<circle cx="90.1" cy="95.4" r=".51" fill="#fff" stroke="#000" stroke-width=".21"/>
<path d="M92.7 94.6v1.5" fill="none" stroke="#000" stroke-width="1.5"/>
<circle cx="92.7" cy="95.4" r=".51" fill="#fff" stroke="#000" stroke-width=".21"/>
<path d="M95.2 94.6v1.5" fill="none" stroke="#000" stroke-width="1.5"/>
<circle cx="95.2" cy="95.4" r=".51" fill="#fff" stroke="#000" stroke-width=".21"/>
<path d="M87.6 94.6v1.5" fill="none" stroke="#000" stroke-width="1.5"/>
<circle cx="87.6" cy="95.4" r=".51" fill="#fff" stroke="#000" stroke-width=".21"/>
<circle cx="148.2" cy="87.8" r=".71" fill="#000" stroke="#000" stroke-width=".21"/>
<circle cx="148.2" cy="87.8" r=".4" fill="#fff" stroke="#000" stroke-width=".21"/>
<circle cx="153.3" cy="87.8" r=".71" fill="#000" stroke="#000" stroke-width=".21"/>
<circle cx="153.3" cy="87.8" r=".4" fill="#fff" stroke="#000" stroke-width=".21"/>
<circle cx="135.2" cy="77.6" r=".71" fill="#000" stroke="#000" stroke-width=".21"/>
<circle cx="135.2" cy="77.6" r=".4" fill="#fff" stroke="#000" stroke-width=".21"/>
<circle cx="135.2" cy="72.5" r=".71" fill="#000" stroke="#000" stroke-width=".21"/>
<circle cx="135.2" cy="72.5" r=".4" fill="#fff" stroke="#000" stroke-width=".21"/>
<circle cx="148.2" cy="72.5" r=".71" fill="#000" stroke="#000" stroke-width=".21"/>
<circle cx="148.2" cy="72.5" r=".4" fill="#fff" stroke="#000" stroke-width=".21"/>
<circle cx="153.3" cy="72.5" r=".71" fill="#000" stroke="#000" stroke-width=".21"/>
<circle cx="153.3" cy="72.5" r=".4" fill="#fff" stroke="#000" stroke-width=".21"/>
<circle cx="153.3" cy="77.6" r=".71" fill="#000" stroke="#000" stroke-width=".21"/>
<circle cx="153.3" cy="77.6" r=".4" fill="#fff" stroke="#000" stroke-width=".21"/>
<circle cx="148.2" cy="77.6" r=".71" fill="#000" stroke="#000" stroke-width=".21"/>
<circle cx="148.2" cy="77.6" r=".4" fill="#fff" stroke="#000" stroke-width=".21"/>
<path d="M128.8 57.3h1.4" fill="none" stroke="#000" stroke-width="1.3"/>
<circle cx="129.5" cy="57.3" r=".4" fill="#fff" stroke="#000" stroke-width=".21"/>
<path d="M139 57.3h1.3" fill="none" stroke="#000" stroke-width="1.3"/>
<circle cx="139.6" cy="57.3" r=".4" fill="#fff" stroke="#000" stroke-width=".21"/>
<path d="M151.7 57.3h1.3" fill="none" stroke="#000" stroke-width="1.3"/>
<circle cx="152.3" cy="57.3" r=".4" fill="#fff" stroke="#000" stroke-width=".21"/>
<path d="M141.5 57.3h1.4" fill="none" stroke="#000" stroke-width="1.3"/>
<circle cx="142.2" cy="57.3" r=".4" fill="#fff" stroke="#000" stroke-width=".21"/>
<path d="M134 60.5h2.6" fill="none" stroke="#000" stroke-width="2.5"/>
<circle cx="135.3" cy="60.5" r=".55" fill="#fff" stroke="#000" stroke-width=".21"/>
<path d="M128.7 60.5h2.6" fill="none" stroke="#000" stroke-width="2.5"/>
<circle cx="130" cy="60.5" r=".55" fill="#fff" stroke="#000" stroke-width=".21"/>
<path d="M150.5 60.5h2.6" fill="none" stroke="#000" stroke-width="2.5"/>
<circle cx="151.8" cy="60.5" r=".55" fill="#fff" stroke="#000" stroke-width=".21"/>
<path d="M145.2 60.5h2.6" fill="none" stroke="#000" stroke-width="2.5"/>
<circle cx="146.5" cy="60.5" r=".55" fill="#fff" stroke="#000" stroke-width=".21"/>
<circle cx="126.9" cy="88.7" r=".71" fill="#000" stroke="#000" stroke-width=".21"/>
<circle cx="126.9" cy="88.7" r=".4" fill="#fff" stroke="#000" stroke-width=".21"/>
<circle cx="134.6" cy="88.7" r=".71" fill="#000" stroke="#000" stroke-width=".21"/>
<circle cx="134.6" cy="88.7" r=".4" fill="#fff" stroke="#000" stroke-width=".21"/>
<circle cx="152.3" cy="65.2" r=".83" fill="#000" stroke="#000" stroke-width=".21"/>
<circle cx="152.3" cy="65.2" r=".51" fill="#fff" stroke="#000" stroke-width=".21"/>
<circle cx="129.5" cy="65.2" r=".83" fill="#000" stroke="#000" stroke-width=".21"/>
<circle cx="129.5" cy="65.2" r=".51" fill="#fff" stroke="#000" stroke-width=".21"/>
<path d="M124.4 84.6v1.3" fill="none" stroke="#000" stroke-width="1.3"/>
<circle cx="124.4" cy="85.2" r=".4" fill="#fff" stroke="#000" stroke-width=".21"/>
<path d="M126.9 84.6v1.3" fill="none" stroke="#000" stroke-width="1.3"/>
<circle cx="126.9" cy="85.2" r=".4" fill="#fff" stroke="#000" stroke-width=".21"/>
<path d="M126.9 76.9v1.4" fill="none" stroke="#000" stroke-width="1.3"/>
<circle cx="126.9" cy="77.6" r=".4" fill="#fff" stroke="#000" stroke-width=".21"/>
<path d="M124.4 76.9v1.4" fill="none" stroke="#000" stroke-width="1.3"/>
<circle cx="124.4" cy="77.6" r=".4" fill="#fff" stroke="#000" stroke-width=".21"/>
<path d="M129.5 84.6v1.3" fill="none" stroke="#000" stroke-width="1.3"/>
<circle cx="129.5" cy="85.2" r=".4" fill="#fff" stroke="#000" stroke-width=".21"/>
<path d="M132 84.6v1.3" fill="none" stroke="#000" stroke-width="1.3"/>
<circle cx="132" cy="85.2" r=".4" fill="#fff" stroke="#000" stroke-width=".21"/>
<path d="M129.5 76.9v1.4" fill="none" stroke="#000" stroke-width="1.3"/>
<circle cx="129.5" cy="77.6" r=".4" fill="#fff" stroke="#000" stroke-width=".21"/>
<path d="M132 76.9v1.4" fill="none" stroke="#000" stroke-width="1.3"/>
<circle cx="132" cy="77.6" r=".4" fill="#fff" stroke="#000" stroke-width=".21"/>
<path d="M138.8 87.7h1.3" fill="none" stroke="#000" stroke-width="1.3"/>
<circle cx="139.4" cy="87.7" r=".4" fill="#fff" stroke="#000" stroke-width=".21"/>
<path d="M138.8 85.2h1.3" fill="none" stroke="#000" stroke-width="1.3"/>
<circle cx="139.4" cy="85.2" r=".4" fill="#fff" stroke="#000" stroke-width=".21"/>
<path d="M138.8 77.6h1.3" fill="none" stroke="#000" stroke-width="1.3"/>
<circle cx="139.4" cy="77.6" r=".4" fill="#fff" stroke="#000" stroke-width=".21"/>
<path d="M138.8 75h1.3" fill="none" stroke="#000" stroke-width="1.3"/>
<circle cx="139.4" cy="75" r=".4" fill="#fff" stroke="#000" stroke-width=".21"/>
<path d="M138.8 72.5h1.3" fill="none" stroke="#000" stroke-width="1.3"/>
<circle cx="139.4" cy="72.5" r=".4" fill="#fff" stroke="#000" stroke-width=".21"/>
<path d="M140 94.6v1.5" fill="none" stroke="#000" stroke-width="1.5"/>
<circle cx="140" cy="95.4" r=".51" fill="#fff" stroke="#000" stroke-width=".21"/>
<path d="M142.5 94.6v1.5" fill="none" stroke="#000" stroke-width="1.5"/>
<circle cx="142.5" cy="95.4" r=".51" fill="#fff" stroke="#000" stroke-width=".21"/>
<path d="M145 94.6v1.5" fill="none" stroke="#000" stroke-width="1.5"/>
<circle cx="145" cy="95.4" r=".51" fill="#fff" stroke="#000" stroke-width=".21"/>
<path d="M137.4 94.6v1.5" fill="none" stroke="#000" stroke-width="1.5"/>
<circle cx="137.4" cy="95.4" r=".51" fill="#fff" stroke="#000" stroke-width=".21"/>
<circle cx="198.1" cy="87.8" r=".71" fill="#000" stroke="#000" stroke-width=".21"/>
<circle cx="198.1" cy="87.8" r=".4" fill="#fff" stroke="#000" stroke-width=".21"/>
<circle cx="203.1" cy="87.8" r=".71" fill="#000" stroke="#000" stroke-width=".21"/>
<circle cx="203.1" cy="87.8" r=".4" fill="#fff" stroke="#000" stroke-width=".21"/>
<circle cx="185" cy="77.6" r=".71" fill="#000" stroke="#000" stroke-width=".21"/>
<circle cx="185" cy="77.6" r=".4" fill="#fff" stroke="#000" stroke-width=".21"/>
<circle cx="185" cy="72.5" r=".71" fill="#000" stroke="#000" stroke-width=".21"/>
<circle cx="185" cy="72.5" r=".4" fill="#fff" stroke="#000" stroke-width=".21"/>
<circle cx="198.1" cy="72.5" r=".71" fill="#000" stroke="#000" stroke-width=".21"/>
<circle cx="198.1" cy="72.5" r=".4" fill="#fff" stroke="#000" stroke-width=".21"/>
<circle cx="203.1" cy="72.5" r=".71" fill="#000" stroke="#000" stroke-width=".21"/>
<circle cx="203.1" cy="72.5" r=".4" fill="#fff" stroke="#000" stroke-width=".21"/>
<circle cx="203.1" cy="77.6" r=".71" fill="#000" stroke="#000" stroke-width=".21"/>
<circle cx="203.1" cy="77.6" r=".4" fill="#fff" stroke="#000" stroke-width=".21"/>
<circle cx="198.1" cy="77.6" r=".71" fill="#000" stroke="#000" stroke-width=".21"/>
<circle cx="198.1" cy="77.6" r=".4" fill="#fff" stroke="#000" stroke-width=".21"/>
<path d="M178.7 57.3h1.3" fill="none" stroke="#000" stroke-width="1.3"/>
<circle cx="179.3" cy="57.3" r=".4" fill="#fff" stroke="#000" stroke-width=".21"/>
<path d="M188.8 57.3h1.3" fill="none" stroke="#000" stroke-width="1.3"/>
<circle cx="189.5" cy="57.3" r=".4" fill="#fff" stroke="#000" stroke-width=".21"/>
<path d="M201.5 57.3h1.3" fill="none" stroke="#000" stroke-width="1.3"/>
<circle cx="202.2" cy="57.3" r=".4" fill="#fff" stroke="#000" stroke-width=".21"/>
<path d="M191.4 57.3h1.3" fill="none" stroke="#000" stroke-width="1.3"/>
<circle cx="192" cy="57.3" r=".4" fill="#fff" stroke="#000" stroke-width=".21"/>
<path d="M183.9 60.5h2.5" fill="none" stroke="#000" stroke-width="2.5"/>
<circle cx="185.1" cy="60.5" r=".55" fill="#fff" stroke="#000" stroke-width=".21"/>
<path d="M178.6 60.5h2.5" fill="none" stroke="#000" stroke-width="2.5"/>
<circle cx="179.9" cy="60.5" r=".55" fill="#fff" stroke="#000" stroke-width=".21"/>
<path d="M200.4 60.5h2.5" fill="none" stroke="#000" stroke-width="2.5"/>
<circle cx="201.7" cy="60.5" r=".55" fill="#fff" stroke="#000" stroke-width=".21"/>
<path d="M195.1 60.5h2.5" fill="none" stroke="#000" stroke-width="2.5"/>
<circle cx="196.4" cy="60.5" r=".55" fill="#fff" stroke="#000" stroke-width=".21"/>
<circle cx="176.8" cy="88.7" r=".71" fill="#000" stroke="#000" stroke-width=".21"/>
<circle cx="176.8" cy="88.7" r=".4" fill="#fff" stroke="#000" stroke-width=".21"/>
<circle cx="184.4" cy="88.7" r=".71" fill="#000" stroke="#000" stroke-width=".21"/>
<circle cx="184.4" cy="88.7" r=".4" fill="#fff" stroke="#000" stroke-width=".21"/>
<circle cx="202.2" cy="65.2" r=".83" fill="#000" stroke="#000" stroke-width=".21"/>
<circle cx="202.2" cy="65.2" r=".51" fill="#fff" stroke="#000" stroke-width=".21"/>
<circle cx="179.3" cy="65.2" r=".83" fill="#000" stroke="#000" stroke-width=".21"/>
<circle cx="179.3" cy="65.2" r=".51" fill="#fff" stroke="#000" stroke-width=".21"/>
<path d="M174.2 84.6v1.3" fill="none" stroke="#000" stroke-width="1.3"/>
<circle cx="174.2" cy="85.2" r=".4" fill="#fff" stroke="#000" stroke-width=".21"/>
<path d="M176.8 84.6v1.3" fill="none" stroke="#000" stroke-width="1.3"/>
<circle cx="176.8" cy="85.2" r=".4" fill="#fff" stroke="#000" stroke-width=".21"/>
<path d="M176.8 76.9v1.4" fill="none" stroke="#000" stroke-width="1.3"/>
<circle cx="176.8" cy="77.6" r=".4" fill="#fff" stroke="#000" stroke-width=".21"/>
<path d="M174.2 76.9v1.4" fill="none" stroke="#000" stroke-width="1.3"/>
<circle cx="174.2" cy="77.6" r=".4" fill="#fff" stroke="#000" stroke-width=".21"/>
<path d="M179.3 84.6v1.3" fill="none" stroke="#000" stroke-width="1.3"/>
<circle cx="179.3" cy="85.2" r=".4" fill="#fff" stroke="#000" stroke-width=".21"/>
<path d="M181.9 84.6v1.3" fill="none" stroke="#000" stroke-width="1.3"/>
<circle cx="181.9" cy="85.2" r=".4" fill="#fff" stroke="#000" stroke-width=".21"/>
<path d="M179.3 76.9v1.4" fill="none" stroke="#000" stroke-width="1.3"/>
<circle cx="179.3" cy="77.6" r=".4" fill="#fff" stroke="#000" stroke-width=".21"/>
<path d="M181.9 76.9v1.4" fill="none" stroke="#000" stroke-width="1.3"/>
<circle cx="181.9" cy="77.6" r=".4" fill="#fff" stroke="#000" stroke-width=".21"/>
<path d="M188.6 87.7h1.3" fill="none" stroke="#000" stroke-width="1.3"/>
<circle cx="189.3" cy="87.7" r=".4" fill="#fff" stroke="#000" stroke-width=".21"/>
<path d="M188.6 85.2h1.3" fill="none" stroke="#000" stroke-width="1.3"/>
<circle cx="189.3" cy="85.2" r=".4" fill="#fff" stroke="#000" stroke-width=".21"/>
<path d="M188.6 77.6h1.3" fill="none" stroke="#000" stroke-width="1.3"/>
<circle cx="189.3" cy="77.6" r=".4" fill="#fff" stroke="#000" stroke-width=".21"/>
<path d="M188.6 75h1.3" fill="none" stroke="#000" stroke-width="1.3"/>
<circle cx="189.3" cy="75" r=".4" fill="#fff" stroke="#000" stroke-width=".21"/>
<path d="M188.6 72.5h1.3" fill="none" stroke="#000" stroke-width="1.3"/>
<circle cx="189.3" cy="72.5" r=".4" fill="#fff" stroke="#000" stroke-width=".21"/>
<path d="M189.8 94.6v1.5" fill="none" stroke="#000" stroke-width="1.5"/>
<circle cx="189.8" cy="95.4" r=".51" fill="#fff" stroke="#000" stroke-width=".21"/>
<path d="M192.3 94.6v1.5" fill="none" stroke="#000" stroke-width="1.5"/>
<circle cx="192.3" cy="95.4" r=".51" fill="#fff" stroke="#000" stroke-width=".21"/>
<path d="M194.9 94.6v1.5" fill="none" stroke="#000" stroke-width="1.5"/>
<circle cx="194.9" cy="95.4" r=".51" fill="#fff" stroke="#000" stroke-width=".21"/>
<path d="M187.3 94.6v1.5" fill="none" stroke="#000" stroke-width="1.5"/>
<circle cx="187.3" cy="95.4" r=".51" fill="#fff" stroke="#000" stroke-width=".21"/>
<circle cx="84.1" cy="117.9" r=".71" fill="#000" stroke="#000" stroke-width=".21"/>
<circle cx="84.1" cy="117.9" r=".4" fill="#fff" stroke="#000" stroke-width=".21"/>
<circle cx="79" cy="117.9" r=".71" fill="#000" stroke="#000" stroke-width=".21"/>
<circle cx="79" cy="117.9" r=".4" fill="#fff" stroke="#000" stroke-width=".21"/>
<circle cx="97.1" cy="128.1" r=".71" fill="#000" stroke="#000" stroke-width=".21"/>
<circle cx="97.1" cy="128.1" r=".4" fill="#fff" stroke="#000" stroke-width=".21"/>
<circle cx="97.1" cy="133.1" r=".71" fill="#000" stroke="#000" stroke-width=".21"/>
<circle cx="97.1" cy="133.1" r=".4" fill="#fff" stroke="#000" stroke-width=".21"/>
<circle cx="84.1" cy="133.1" r=".71" fill="#000" stroke="#000" stroke-width=".21"/>
<circle cx="84.1" cy="133.1" r=".4" fill="#fff" stroke="#000" stroke-width=".21"/>
<circle cx="79" cy="133.1" r=".71" fill="#000" stroke="#000" stroke-width=".21"/>
<circle cx="79" cy="133.1" r=".4" fill="#fff" stroke="#000" stroke-width=".21"/>
<circle cx="79" cy="128.1" r=".71" fill="#000" stroke="#000" stroke-width=".21"/>
<circle cx="79" cy="128.1" r=".4" fill="#fff" stroke="#000" stroke-width=".21"/>
<circle cx="84.1" cy="128.1" r=".71" fill="#000" stroke="#000" stroke-width=".21"/>
<circle cx="84.1" cy="128.1" r=".4" fill="#fff" stroke="#000" stroke-width=".21"/>
<path d="M102.2 148.4h1.3" fill="none" stroke="#000" stroke-width="1.3"/>
<circle cx="102.8" cy="148.4" r=".4" fill="#fff" stroke="#000" stroke-width=".21"/>
<path d="M92 148.4h1.3" fill="none" stroke="#000" stroke-width="1.3"/>
<circle cx="92.7" cy="148.4" r=".4" fill="#fff" stroke="#000" stroke-width=".21"/>
<path d="M79.3 148.4h1.3" fill="none" stroke="#000" stroke-width="1.3"/>
<circle cx="80" cy="148.4" r=".4" fill="#fff" stroke="#000" stroke-width=".21"/>
<path d="M89.5 148.4h1.3" fill="none" stroke="#000" stroke-width="1.3"/>
<circle cx="90.1" cy="148.4" r=".4" fill="#fff" stroke="#000" stroke-width=".21"/>
<path d="M95.7 145.2h2.6" fill="none" stroke="#000" stroke-width="2.5"/>
<circle cx="97" cy="145.2" r=".55" fill="#fff" stroke="#000" stroke-width=".21"/>
<path d="M101 145.2h2.6" fill="none" stroke="#000" stroke-width="2.5"/>
<circle cx="102.3" cy="145.2" r=".55" fill="#fff" stroke="#000" stroke-width=".21"/>
<path d="M79.2 145.2h2.6" fill="none" stroke="#000" stroke-width="2.5"/>
<circle cx="80.5" cy="145.2" r=".55" fill="#fff" stroke="#000" stroke-width=".21"/>
<path d="M84.5 145.2h2.6" fill="none" stroke="#000" stroke-width="2.5"/>
<circle cx="85.8" cy="145.2" r=".55" fill="#fff" stroke="#000" stroke-width=".21"/>
<circle cx="105.4" cy="116.9" r=".71" fill="#000" stroke="#000" stroke-width=".21"/>
<circle cx="105.4" cy="116.9" r=".4" fill="#fff" stroke="#000" stroke-width=".21"/>
<circle cx="97.7" cy="116.9" r=".71" fill="#000" stroke="#000" stroke-width=".21"/>
<circle cx="97.7" cy="116.9" r=".4" fill="#fff" stroke="#000" stroke-width=".21"/>
<circle cx="80" cy="140.4" r=".83" fill="#000" stroke="#000" stroke-width=".21"/>
<circle cx="80" cy="140.4" r=".51" fill="#fff" stroke="#000" stroke-width=".21"/>
<circle cx="102.8" cy="140.4" r=".83" fill="#000" stroke="#000" stroke-width=".21"/>
<circle cx="102.8" cy="140.4" r=".51" fill="#fff" stroke="#000" stroke-width=".21"/>
<path d="M107.9 119.8v1.3" fill="none" stroke="#000" stroke-width="1.3"/>
<circle cx="107.9" cy="120.4" r=".4" fill="#fff" stroke="#000" stroke-width=".21"/>
<path d="M105.4 119.8v1.3" fill="none" stroke="#000" stroke-width="1.3"/>
<circle cx="105.4" cy="120.4" r=".4" fill="#fff" stroke="#000" stroke-width=".21"/>
<path d="M105.4 127.4v1.3" fill="none" stroke="#000" stroke-width="1.3"/>
<circle cx="105.4" cy="128.1" r=".4" fill="#fff" stroke="#000" stroke-width=".21"/>
<path d="M107.9 127.4v1.3" fill="none" stroke="#000" stroke-width="1.3"/>
<circle cx="107.9" cy="128.1" r=".4" fill="#fff" stroke="#000" stroke-width=".21"/>
<path d="M102.8 119.8v1.3" fill="none" stroke="#000" stroke-width="1.3"/>
<circle cx="102.8" cy="120.4" r=".4" fill="#fff" stroke="#000" stroke-width=".21"/>
<path d="M100.3 119.8v1.3" fill="none" stroke="#000" stroke-width="1.3"/>
<circle cx="100.3" cy="120.4" r=".4" fill="#fff" stroke="#000" stroke-width=".21"/>
<path d="M102.8 127.4v1.3" fill="none" stroke="#000" stroke-width="1.3"/>
<circle cx="102.8" cy="128.1" r=".4" fill="#fff" stroke="#000" stroke-width=".21"/>
<path d="M100.3 127.4v1.3" fill="none" stroke="#000" stroke-width="1.3"/>
<circle cx="100.3" cy="128.1" r=".4" fill="#fff" stroke="#000" stroke-width=".21"/>
<path d="M92.2 117.9h1.3" fill="none" stroke="#000" stroke-width="1.3"/>
<circle cx="92.9" cy="117.9" r=".4" fill="#fff" stroke="#000" stroke-width=".21"/>
<path d="M92.2 120.5h1.3" fill="none" stroke="#000" stroke-width="1.3"/>
<circle cx="92.9" cy="120.5" r=".4" fill="#fff" stroke="#000" stroke-width=".21"/>
<path d="M92.2 128.1h1.3" fill="none" stroke="#000" stroke-width="1.3"/>
<circle cx="92.9" cy="128.1" r=".4" fill="#fff" stroke="#000" stroke-width=".21"/>
<path d="M92.2 130.6h1.3" fill="none" stroke="#000" stroke-width="1.3"/>
<circle cx="92.9" cy="130.6" r=".4" fill="#fff" stroke="#000" stroke-width=".21"/>
<path d="M92.2 133.2h1.3" fill="none" stroke="#000" stroke-width="1.3"/>
<circle cx="92.9" cy="133.2" r=".4" fill="#fff" stroke="#000" stroke-width=".21"/>
<path d="M92.4 109.5v1.6" fill="none" stroke="#000" stroke-width="1.5"/>
<circle cx="92.4" cy="110.3" r=".51" fill="#fff" stroke="#000" stroke-width=".21"/>
<path d="M89.8 109.5v1.6" fill="none" stroke="#000" stroke-width="1.5"/>
<circle cx="89.8" cy="110.3" r=".51" fill="#fff" stroke="#000" stroke-width=".21"/>
<path d="M87.3 109.5v1.6" fill="none" stroke="#000" stroke-width="1.5"/>
<circle cx="87.3" cy="110.3" r=".51" fill="#fff" stroke="#000" stroke-width=".21"/>
<path d="M94.9 109.5v1.6" fill="none" stroke="#000" stroke-width="1.5"/>
<circle cx="94.9" cy="110.3" r=".51" fill="#fff" stroke="#000" stroke-width=".21"/>
<circle cx="133.9" cy="117.9" r=".71" fill="#000" stroke="#000" stroke-width=".21"/>
<circle cx="133.9" cy="117.9" r=".4" fill="#fff" stroke="#000" stroke-width=".21"/>
<circle cx="128.8" cy="117.9" r=".71" fill="#000" stroke="#000" stroke-width=".21"/>
<circle cx="128.8" cy="117.9" r=".4" fill="#fff" stroke="#000" stroke-width=".21"/>
<circle cx="146.9" cy="128.1" r=".71" fill="#000" stroke="#000" stroke-width=".21"/>
<circle cx="146.9" cy="128.1" r=".4" fill="#fff" stroke="#000" stroke-width=".21"/>
<circle cx="146.9" cy="133.1" r=".71" fill="#000" stroke="#000" stroke-width=".21"/>
<circle cx="146.9" cy="133.1" r=".4" fill="#fff" stroke="#000" stroke-width=".21"/>
<circle cx="133.9" cy="133.1" r=".71" fill="#000" stroke="#000" stroke-width=".21"/>
<circle cx="133.9" cy="133.1" r=".4" fill="#fff" stroke="#000" stroke-width=".21"/>
<circle cx="128.8" cy="133.1" r=".71" fill="#000" stroke="#000" stroke-width=".21"/>
<circle cx="128.8" cy="133.1" r=".4" fill="#fff" stroke="#000" stroke-width=".21"/>
<circle cx="128.8" cy="128.1" r=".71" fill="#000" stroke="#000" stroke-width=".21"/>
<circle cx="128.8" cy="128.1" r=".4" fill="#fff" stroke="#000" stroke-width=".21"/>
<circle cx="133.9" cy="128.1" r=".71" fill="#000" stroke="#000" stroke-width=".21"/>
<circle cx="133.9" cy="128.1" r=".4" fill="#fff" stroke="#000" stroke-width=".21"/>
<path d="M152 148.4h1.3" fill="none" stroke="#000" stroke-width="1.3"/>
<circle cx="152.7" cy="148.4" r=".4" fill="#fff" stroke="#000" stroke-width=".21"/>
<path d="M141.8 148.4h1.4" fill="none" stroke="#000" stroke-width="1.3"/>
<circle cx="142.5" cy="148.4" r=".4" fill="#fff" stroke="#000" stroke-width=".21"/>
<path d="M129.1 148.4h1.4" fill="none" stroke="#000" stroke-width="1.3"/>
<circle cx="129.8" cy="148.4" r=".4" fill="#fff" stroke="#000" stroke-width=".21"/>
<path d="M139.3 148.4h1.3" fill="none" stroke="#000" stroke-width="1.3"/>
<circle cx="140" cy="148.4" r=".4" fill="#fff" stroke="#000" stroke-width=".21"/>
<path d="M145.6 145.2h2.5" fill="none" stroke="#000" stroke-width="2.5"/>
<circle cx="146.8" cy="145.2" r=".55" fill="#fff" stroke="#000" stroke-width=".21"/>
<path d="M150.9 145.2h2.5" fill="none" stroke="#000" stroke-width="2.5"/>
<circle cx="152.1" cy="145.2" r=".55" fill="#fff" stroke="#000" stroke-width=".21"/>
<path d="M129.1 145.2h2.5" fill="none" stroke="#000" stroke-width="2.5"/>
<circle cx="130.3" cy="145.2" r=".55" fill="#fff" stroke="#000" stroke-width=".21"/>
<path d="M134.4 145.2h2.5" fill="none" stroke="#000" stroke-width="2.5"/>
<circle cx="135.6" cy="145.2" r=".55" fill="#fff" stroke="#000" stroke-width=".21"/>
<circle cx="155.2" cy="116.9" r=".71" fill="#000" stroke="#000" stroke-width=".21"/>
<circle cx="155.2" cy="116.9" r=".4" fill="#fff" stroke="#000" stroke-width=".21"/>
<circle cx="147.6" cy="116.9" r=".71" fill="#000" stroke="#000" stroke-width=".21"/>
<circle cx="147.6" cy="116.9" r=".4" fill="#fff" stroke="#000" stroke-width=".21"/>
<circle cx="129.8" cy="140.4" r=".83" fill="#000" stroke="#000" stroke-width=".21"/>
<circle cx="129.8" cy="140.4" r=".51" fill="#fff" stroke="#000" stroke-width=".21"/>
<circle cx="152.7" cy="140.4" r=".83" fill="#000" stroke="#000" stroke-width=".21"/>
<circle cx="152.7" cy="140.4" r=".51" fill="#fff" stroke="#000" stroke-width=".21"/>
<path d="M157.7 119.8v1.3" fill="none" stroke="#000" stroke-width="1.3"/>
<circle cx="157.7" cy="120.4" r=".4" fill="#fff" stroke="#000" stroke-width=".21"/>
<path d="M155.2 119.8v1.3" fill="none" stroke="#000" stroke-width="1.3"/>
<circle cx="155.2" cy="120.4" r=".4" fill="#fff" stroke="#000" stroke-width=".21"/>
<path d="M155.2 127.4v1.3" fill="none" stroke="#000" stroke-width="1.3"/>
<circle cx="155.2" cy="128.1" r=".4" fill="#fff" stroke="#000" stroke-width=".21"/>
<path d="M157.7 127.4v1.3" fill="none" stroke="#000" stroke-width="1.3"/>
<circle cx="157.7" cy="128.1" r=".4" fill="#fff" stroke="#000" stroke-width=".21"/>
<path d="M152.7 119.8v1.3" fill="none" stroke="#000" stroke-width="1.3"/>
<circle cx="152.7" cy="120.4" r=".4" fill="#fff" stroke="#000" stroke-width=".21"/>
<path d="M150.1 119.8v1.3" fill="none" stroke="#000" stroke-width="1.3"/>
<circle cx="150.1" cy="120.4" r=".4" fill="#fff" stroke="#000" stroke-width=".21"/>
<path d="M152.7 127.4v1.3" fill="none" stroke="#000" stroke-width="1.3"/>
<circle cx="152.7" cy="128.1" r=".4" fill="#fff" stroke="#000" stroke-width=".21"/>
<path d="M150.1 127.4v1.3" fill="none" stroke="#000" stroke-width="1.3"/>
<circle cx="150.1" cy="128.1" r=".4" fill="#fff" stroke="#000" stroke-width=".21"/>
<path d="M142 117.9h1.4" fill="none" stroke="#000" stroke-width="1.3"/>
<circle cx="142.7" cy="117.9" r=".4" fill="#fff" stroke="#000" stroke-width=".21"/>
<path d="M142 120.5h1.4" fill="none" stroke="#000" stroke-width="1.3"/>
<circle cx="142.7" cy="120.5" r=".4" fill="#fff" stroke="#000" stroke-width=".21"/>
<path d="M142 128.1h1.4" fill="none" stroke="#000" stroke-width="1.3"/>
<circle cx="142.7" cy="128.1" r=".4" fill="#fff" stroke="#000" stroke-width=".21"/>
<path d="M142 130.6h1.4" fill="none" stroke="#000" stroke-width="1.3"/>
<circle cx="142.7" cy="130.6" r=".4" fill="#fff" stroke="#000" stroke-width=".21"/>
<path d="M142 133.2h1.4" fill="none" stroke="#000" stroke-width="1.3"/>
<circle cx="142.7" cy="133.2" r=".4" fill="#fff" stroke="#000" stroke-width=".21"/>
<path d="M142.2 109.5v1.6" fill="none" stroke="#000" stroke-width="1.5"/>
<circle cx="142.2" cy="110.3" r=".51" fill="#fff" stroke="#000" stroke-width=".21"/>
<path d="M139.6 109.5v1.6" fill="none" stroke="#000" stroke-width="1.5"/>
<circle cx="139.6" cy="110.3" r=".51" fill="#fff" stroke="#000" stroke-width=".21"/>
<path d="M137.1 109.5v1.6" fill="none" stroke="#000" stroke-width="1.5"/>
<circle cx="137.1" cy="110.3" r=".51" fill="#fff" stroke="#000" stroke-width=".21"/>
<path d="M144.7 109.5v1.6" fill="none" stroke="#000" stroke-width="1.5"/>
<circle cx="144.7" cy="110.3" r=".51" fill="#fff" stroke="#000" stroke-width=".21"/>
<circle cx="183.8" cy="117.9" r=".71" fill="#000" stroke="#000" stroke-width=".21"/>
<circle cx="183.8" cy="117.9" r=".4" fill="#fff" stroke="#000" stroke-width=".21"/>
<circle cx="178.7" cy="117.9" r=".71" fill="#000" stroke="#000" stroke-width=".21"/>
<circle cx="178.7" cy="117.9" r=".4" fill="#fff" stroke="#000" stroke-width=".21"/>
<circle cx="196.8" cy="128.1" r=".71" fill="#000" stroke="#000" stroke-width=".21"/>
<circle cx="196.8" cy="128.1" r=".4" fill="#fff" stroke="#000" stroke-width=".21"/>
<circle cx="196.8" cy="133.1" r=".71" fill="#000" stroke="#000" stroke-width=".21"/>
<circle cx="196.8" cy="133.1" r=".4" fill="#fff" stroke="#000" stroke-width=".21"/>
<circle cx="183.8" cy="133.1" r=".71" fill="#000" stroke="#000" stroke-width=".21"/>
<circle cx="183.8" cy="133.1" r=".4" fill="#fff" stroke="#000" stroke-width=".21"/>
<circle cx="178.7" cy="133.1" r=".71" fill="#000" stroke="#000" stroke-width=".21"/>
<circle cx="178.7" cy="133.1" r=".4" fill="#fff" stroke="#000" stroke-width=".21"/>
<circle cx="178.7" cy="128.1" r=".71" fill="#000" stroke="#000" stroke-width=".21"/>
<circle cx="178.7" cy="128.1" r=".4" fill="#fff" stroke="#000" stroke-width=".21"/>
<circle cx="183.8" cy="128.1" r=".71" fill="#000" stroke="#000" stroke-width=".21"/>
<circle cx="183.8" cy="128.1" r=".4" fill="#fff" stroke="#000" stroke-width=".21"/>
<path d="M201.8 148.4h1.4" fill="none" stroke="#000" stroke-width="1.3"/>
<circle cx="202.5" cy="148.4" r=".4" fill="#fff" stroke="#000" stroke-width=".21"/>
<path d="M191.7 148.4h1.3" fill="none" stroke="#000" stroke-width="1.3"/>
<circle cx="192.3" cy="148.4" r=".4" fill="#fff" stroke="#000" stroke-width=".21"/>
<path d="M179 148.4h1.3" fill="none" stroke="#000" stroke-width="1.3"/>
<circle cx="179.6" cy="148.4" r=".4" fill="#fff" stroke="#000" stroke-width=".21"/>
<path d="M189.1 148.4h1.4" fill="none" stroke="#000" stroke-width="1.3"/>
<circle cx="189.8" cy="148.4" r=".4" fill="#fff" stroke="#000" stroke-width=".21"/>
<path d="M195.4 145.2h2.6" fill="none" stroke="#000" stroke-width="2.5"/>
<circle cx="196.7" cy="145.2" r=".55" fill="#fff" stroke="#000" stroke-width=".21"/>
<path d="M200.7 145.2h2.5" fill="none" stroke="#000" stroke-width="2.5"/>
<circle cx="202" cy="145.2" r=".55" fill="#fff" stroke="#000" stroke-width=".21"/>
<path d="M178.9 145.2h2.5" fill="none" stroke="#000" stroke-width="2.5"/>
<circle cx="180.2" cy="145.2" r=".55" fill="#fff" stroke="#000" stroke-width=".21"/>
<path d="M184.2 145.2h2.5" fill="none" stroke="#000" stroke-width="2.5"/>
<circle cx="185.5" cy="145.2" r=".55" fill="#fff" stroke="#000" stroke-width=".21"/>
<circle cx="205" cy="116.9" r=".71" fill="#000" stroke="#000" stroke-width=".21"/>
<circle cx="205" cy="116.9" r=".4" fill="#fff" stroke="#000" stroke-width=".21"/>
<circle cx="197.4" cy="116.9" r=".71" fill="#000" stroke="#000" stroke-width=".21"/>
<circle cx="197.4" cy="116.9" r=".4" fill="#fff" stroke="#000" stroke-width=".21"/>
<circle cx="179.6" cy="140.4" r=".83" fill="#000" stroke="#000" stroke-width=".21"/>
<circle cx="179.6" cy="140.4" r=".51" fill="#fff" stroke="#000" stroke-width=".21"/>
<circle cx="202.5" cy="140.4" r=".83" fill="#000" stroke="#000" stroke-width=".21"/>
<circle cx="202.5" cy="140.4" r=".51" fill="#fff" stroke="#000" stroke-width=".21"/>
<path d="M207.6 119.8v1.3" fill="none" stroke="#000" stroke-width="1.3"/>
<circle cx="207.6" cy="120.4" r=".4" fill="#fff" stroke="#000" stroke-width=".21"/>
<path d="M205 119.8v1.3" fill="none" stroke="#000" stroke-width="1.3"/>
<circle cx="205" cy="120.4" r=".4" fill="#fff" stroke="#000" stroke-width=".21"/>
<path d="M205 127.4v1.3" fill="none" stroke="#000" stroke-width="1.3"/>
<circle cx="205" cy="128.1" r=".4" fill="#fff" stroke="#000" stroke-width=".21"/>
<path d="M207.6 127.4v1.3" fill="none" stroke="#000" stroke-width="1.3"/>
<circle cx="207.6" cy="128.1" r=".4" fill="#fff" stroke="#000" stroke-width=".21"/>
<path d="M202.5 119.8v1.3" fill="none" stroke="#000" stroke-width="1.3"/>
<circle cx="202.5" cy="120.4" r=".4" fill="#fff" stroke="#000" stroke-width=".21"/>
<path d="M200 119.8v1.3" fill="none" stroke="#000" stroke-width="1.3"/>
<circle cx="200" cy="120.4" r=".4" fill="#fff" stroke="#000" stroke-width=".21"/>
<path d="M202.5 127.4v1.3" fill="none" stroke="#000" stroke-width="1.3"/>
<circle cx="202.5" cy="128.1" r=".4" fill="#fff" stroke="#000" stroke-width=".21"/>
<path d="M200 127.4v1.3" fill="none" stroke="#000" stroke-width="1.3"/>
<circle cx="200" cy="128.1" r=".4" fill="#fff" stroke="#000" stroke-width=".21"/>
<path d="M191.9 117.9h1.3" fill="none" stroke="#000" stroke-width="1.3"/>
<circle cx="192.5" cy="117.9" r=".4" fill="#fff" stroke="#000" stroke-width=".21"/>
<path d="M191.9 120.5h1.3" fill="none" stroke="#000" stroke-width="1.3"/>
<circle cx="192.5" cy="120.5" r=".4" fill="#fff" stroke="#000" stroke-width=".21"/>
<path d="M191.9 128.1h1.3" fill="none" stroke="#000" stroke-width="1.3"/>
<circle cx="192.5" cy="128.1" r=".4" fill="#fff" stroke="#000" stroke-width=".21"/>
<path d="M191.9 130.6h1.3" fill="none" stroke="#000" stroke-width="1.3"/>
<circle cx="192.5" cy="130.6" r=".4" fill="#fff" stroke="#000" stroke-width=".21"/>
<path d="M191.9 133.2h1.3" fill="none" stroke="#000" stroke-width="1.3"/>
<circle cx="192.5" cy="133.2" r=".4" fill="#fff" stroke="#000" stroke-width=".21"/>
<path d="M192 109.5v1.6" fill="none" stroke="#000" stroke-width="1.5"/>
<circle cx="192" cy="110.3" r=".51" fill="#fff" stroke="#000" stroke-width=".21"/>
<path d="M189.5 109.5v1.6" fill="none" stroke="#000" stroke-width="1.5"/>
<circle cx="189.5" cy="110.3" r=".51" fill="#fff" stroke="#000" stroke-width=".21"/>
<path d="M186.9 109.5v1.6" fill="none" stroke="#000" stroke-width="1.5"/>
<circle cx="186.9" cy="110.3" r=".51" fill="#fff" stroke="#000" stroke-width=".21"/>
<path d="M194.6 109.5v1.6" fill="none" stroke="#000" stroke-width="1.5"/>
<circle cx="194.6" cy="110.3" r=".51" fill="#fff" stroke="#000" stroke-width=".21"/>
<circle cx="98.4" cy="77.6" r=".94" fill="#000" stroke="#000" stroke-width=".21"/>
<circle cx="98.4" cy="77.6" r=".25" fill="#fff" stroke="#000" stroke-width=".21"/>
<circle cx="82.2" cy="77.6" r=".94" fill="#000" stroke="#000" stroke-width=".21"/>
<circle cx="82.2" cy="77.6" r=".25" fill="#fff" stroke="#000" stroke-width=".21"/>
<circle cx="85.4" cy="77.6" r=".94" fill="#000" stroke="#000" stroke-width=".21"/>
<circle cx="85.4" cy="77.6" r=".25" fill="#fff" stroke="#000" stroke-width=".21"/>
<circle cx="82.2" cy="72.5" r=".94" fill="#000" stroke="#000" stroke-width=".21"/>
<circle cx="82.2" cy="72.5" r=".25" fill="#fff" stroke="#000" stroke-width=".21"/>
<circle cx="98.4" cy="72.5" r=".94" fill="#000" stroke="#000" stroke-width=".21"/>
<circle cx="98.4" cy="72.5" r=".25" fill="#fff" stroke="#000" stroke-width=".21"/>
<circle cx="74.6" cy="77.6" r=".94" fill="#000" stroke="#000" stroke-width=".21"/>
<circle cx="74.6" cy="77.6" r=".25" fill="#fff" stroke="#000" stroke-width=".21"/>
<circle cx="85.4" cy="72.5" r=".94" fill="#000" stroke="#000" stroke-width=".21"/>
<circle cx="85.4" cy="72.5" r=".25" fill="#fff" stroke="#000" stroke-width=".21"/>
<circle cx="74.6" cy="72.5" r=".94" fill="#000" stroke="#000" stroke-width=".21"/>
<circle cx="74.6" cy="72.5" r=".25" fill="#fff" stroke="#000" stroke-width=".21"/>
<circle cx="77.1" cy="77.6" r=".94" fill="#000" stroke="#000" stroke-width=".21"/>
<circle cx="77.1" cy="77.6" r=".25" fill="#fff" stroke="#000" stroke-width=".21"/>
<circle cx="79.7" cy="77.6" r=".94" fill="#000" stroke="#000" stroke-width=".21"/>
<circle cx="79.7" cy="77.6" r=".25" fill="#fff" stroke="#000" stroke-width=".21"/>
<circle cx="79.7" cy="65.2" r=".94" fill="#000" stroke="#000" stroke-width=".21"/>
<circle cx="79.7" cy="65.2" r=".25" fill="#fff" stroke="#000" stroke-width=".21"/>
<circle cx="98.4" cy="87.8" r=".94" fill="#000" stroke="#000" stroke-width=".21"/>
<circle cx="98.4" cy="87.8" r=".25" fill="#fff" stroke="#000" stroke-width=".21"/>
<circle cx="89.8" cy="57.3" r=".94" fill="#000" stroke="#000" stroke-width=".21"/>
<circle cx="89.8" cy="57.3" r=".25" fill="#fff" stroke="#000" stroke-width=".21"/>
<circle cx="92.4" cy="57.3" r=".94" fill="#000" stroke="#000" stroke-width=".21"/>
<circle cx="92.4" cy="57.3" r=".25" fill="#fff" stroke="#000" stroke-width=".21"/>
<circle cx="79.7" cy="85.2" r=".94" fill="#000" stroke="#000" stroke-width=".21"/>
<circle cx="79.7" cy="85.2" r=".25" fill="#fff" stroke="#000" stroke-width=".21"/>
<circle cx="103.5" cy="77.6" r=".94" fill="#000" stroke="#000" stroke-width=".21"/>
<circle cx="103.5" cy="77.6" r=".25" fill="#fff" stroke="#000" stroke-width=".21"/>
<circle cx="103.5" cy="72.5" r=".94" fill="#000" stroke="#000" stroke-width=".21"/>
<circle cx="103.5" cy="72.5" r=".25" fill="#fff" stroke="#000" stroke-width=".21"/>
<circle cx="79.7" cy="57.3" r=".94" fill="#000" stroke="#000" stroke-width=".21"/>
<circle cx="79.7" cy="57.3" r=".25" fill="#fff" stroke="#000" stroke-width=".21"/>
<circle cx="102.5" cy="65.2" r=".94" fill="#000" stroke="#000" stroke-width=".21"/>
<circle cx="102.5" cy="65.2" r=".25" fill="#fff" stroke="#000" stroke-width=".21"/>
<circle cx="102.5" cy="57.3" r=".94" fill="#000" stroke="#000" stroke-width=".21"/>
<circle cx="102.5" cy="57.3" r=".25" fill="#fff" stroke="#000" stroke-width=".21"/>
<circle cx="77.1" cy="85.2" r=".94" fill="#000" stroke="#000" stroke-width=".21"/>
<circle cx="77.1" cy="85.2" r=".25" fill="#fff" stroke="#000" stroke-width=".21"/>
<circle cx="77.1" cy="88.7" r=".94" fill="#000" stroke="#000" stroke-width=".21"/>
<circle cx="77.1" cy="88.7" r=".25" fill="#fff" stroke="#000" stroke-width=".21"/>
<circle cx="103.5" cy="87.8" r=".94" fill="#000" stroke="#000" stroke-width=".21"/>
<circle cx="103.5" cy="87.8" r=".25" fill="#fff" stroke="#000" stroke-width=".21"/>
<circle cx="148.2" cy="77.6" r=".94" fill="#000" stroke="#000" stroke-width=".21"/>
<circle cx="148.2" cy="77.6" r=".25" fill="#fff" stroke="#000" stroke-width=".21"/>
<circle cx="132" cy="77.6" r=".94" fill="#000" stroke="#000" stroke-width=".21"/>
<circle cx="132" cy="77.6" r=".25" fill="#fff" stroke="#000" stroke-width=".21"/>
<circle cx="135.2" cy="77.6" r=".94" fill="#000" stroke="#000" stroke-width=".21"/>
<circle cx="135.2" cy="77.6" r=".25" fill="#fff" stroke="#000" stroke-width=".21"/>
<circle cx="132" cy="72.5" r=".94" fill="#000" stroke="#000" stroke-width=".21"/>
<circle cx="132" cy="72.5" r=".25" fill="#fff" stroke="#000" stroke-width=".21"/>
<circle cx="148.2" cy="72.5" r=".94" fill="#000" stroke="#000" stroke-width=".21"/>
<circle cx="148.2" cy="72.5" r=".25" fill="#fff" stroke="#000" stroke-width=".21"/>
<circle cx="124.4" cy="77.6" r=".94" fill="#000" stroke="#000" stroke-width=".21"/>
<circle cx="124.4" cy="77.6" r=".25" fill="#fff" stroke="#000" stroke-width=".21"/>
<circle cx="135.2" cy="72.5" r=".94" fill="#000" stroke="#000" stroke-width=".21"/>
<circle cx="135.2" cy="72.5" r=".25" fill="#fff" stroke="#000" stroke-width=".21"/>
<circle cx="124.4" cy="72.5" r=".94" fill="#000" stroke="#000" stroke-width=".21"/>
<circle cx="124.4" cy="72.5" r=".25" fill="#fff" stroke="#000" stroke-width=".21"/>
<circle cx="126.9" cy="77.6" r=".94" fill="#000" stroke="#000" stroke-width=".21"/>
<circle cx="126.9" cy="77.6" r=".25" fill="#fff" stroke="#000" stroke-width=".21"/>
<circle cx="129.5" cy="77.6" r=".94" fill="#000" stroke="#000" stroke-width=".21"/>
<circle cx="129.5" cy="77.6" r=".25" fill="#fff" stroke="#000" stroke-width=".21"/>
<circle cx="129.5" cy="65.2" r=".94" fill="#000" stroke="#000" stroke-width=".21"/>
<circle cx="129.5" cy="65.2" r=".25" fill="#fff" stroke="#000" stroke-width=".21"/>
<circle cx="148.2" cy="87.8" r=".94" fill="#000" stroke="#000" stroke-width=".21"/>
<circle cx="148.2" cy="87.8" r=".25" fill="#fff" stroke="#000" stroke-width=".21"/>
<circle cx="139.6" cy="57.3" r=".94" fill="#000" stroke="#000" stroke-width=".21"/>
<circle cx="139.6" cy="57.3" r=".25" fill="#fff" stroke="#000" stroke-width=".21"/>
<circle cx="142.2" cy="57.3" r=".94" fill="#000" stroke="#000" stroke-width=".21"/>
<circle cx="142.2" cy="57.3" r=".25" fill="#fff" stroke="#000" stroke-width=".21"/>
<circle cx="129.5" cy="85.2" r=".94" fill="#000" stroke="#000" stroke-width=".21"/>
<circle cx="129.5" cy="85.2" r=".25" fill="#fff" stroke="#000" stroke-width=".21"/>
<circle cx="153.3" cy="77.6" r=".94" fill="#000" stroke="#000" stroke-width=".21"/>
<circle cx="153.3" cy="77.6" r=".25" fill="#fff" stroke="#000" stroke-width=".21"/>
<circle cx="153.3" cy="72.5" r=".94" fill="#000" stroke="#000" stroke-width=".21"/>
<circle cx="153.3" cy="72.5" r=".25" fill="#fff" stroke="#000" stroke-width=".21"/>
<circle cx="129.5" cy="57.3" r=".94" fill="#000" stroke="#000" stroke-width=".21"/>
<circle cx="129.5" cy="57.3" r=".25" fill="#fff" stroke="#000" stroke-width=".21"/>
<circle cx="152.3" cy="65.2" r=".94" fill="#000" stroke="#000" stroke-width=".21"/>
<circle cx="152.3" cy="65.2" r=".25" fill="#fff" stroke="#000" stroke-width=".21"/>
<circle cx="152.3" cy="57.3" r=".94" fill="#000" stroke="#000" stroke-width=".21"/>
<circle cx="152.3" cy="57.3" r=".25" fill="#fff" stroke="#000" stroke-width=".21"/>
<circle cx="126.9" cy="85.2" r=".94" fill="#000" stroke="#000" stroke-width=".21"/>
<circle cx="126.9" cy="85.2" r=".25" fill="#fff" stroke="#000" stroke-width=".21"/>
<circle cx="126.9" cy="88.7" r=".94" fill="#000" stroke="#000" stroke-width=".21"/>
<circle cx="126.9" cy="88.7" r=".25" fill="#fff" stroke="#000" stroke-width=".21"/>
<circle cx="153.3" cy="87.8" r=".94" fill="#000" stroke="#000" stroke-width=".21"/>
<circle cx="153.3" cy="87.8" r=".25" fill="#fff" stroke="#000" stroke-width=".21"/>
<circle cx="198.1" cy="77.6" r=".94" fill="#000" stroke="#000" stroke-width=".21"/>
<circle cx="198.1" cy="77.6" r=".25" fill="#fff" stroke="#000" stroke-width=".21"/>
<circle cx="181.9" cy="77.6" r=".94" fill="#000" stroke="#000" stroke-width=".21"/>
<circle cx="181.9" cy="77.6" r=".25" fill="#fff" stroke="#000" stroke-width=".21"/>
<circle cx="185" cy="77.6" r=".94" fill="#000" stroke="#000" stroke-width=".21"/>
<circle cx="185" cy="77.6" r=".25" fill="#fff" stroke="#000" stroke-width=".21"/>
<circle cx="181.9" cy="72.5" r=".94" fill="#000" stroke="#000" stroke-width=".21"/>
<circle cx="181.9" cy="72.5" r=".25" fill="#fff" stroke="#000" stroke-width=".21"/>
<circle cx="198.1" cy="72.5" r=".94" fill="#000" stroke="#000" stroke-width=".21"/>
<circle cx="198.1" cy="72.5" r=".25" fill="#fff" stroke="#000" stroke-width=".21"/>
<circle cx="174.2" cy="77.6" r=".94" fill="#000" stroke="#000" stroke-width=".21"/>
<circle cx="174.2" cy="77.6" r=".25" fill="#fff" stroke="#000" stroke-width=".21"/>
<circle cx="185" cy="72.5" r=".94" fill="#000" stroke="#000" stroke-width=".21"/>
<circle cx="185" cy="72.5" r=".25" fill="#fff" stroke="#000" stroke-width=".21"/>
<circle cx="174.2" cy="72.5" r=".94" fill="#000" stroke="#000" stroke-width=".21"/>
<circle cx="174.2" cy="72.5" r=".25" fill="#fff" stroke="#000" stroke-width=".21"/>
<circle cx="176.8" cy="77.6" r=".94" fill="#000" stroke="#000" stroke-width=".21"/>
<circle cx="176.8" cy="77.6" r=".25" fill="#fff" stroke="#000" stroke-width=".21"/>
<circle cx="179.3" cy="77.6" r=".94" fill="#000" stroke="#000" stroke-width=".21"/>
<circle cx="179.3" cy="77.6" r=".25" fill="#fff" stroke="#000" stroke-width=".21"/>
<circle cx="179.3" cy="65.2" r=".94" fill="#000" stroke="#000" stroke-width=".21"/>
<circle cx="179.3" cy="65.2" r=".25" fill="#fff" stroke="#000" stroke-width=".21"/>
<circle cx="198.1" cy="87.8" r=".94" fill="#000" stroke="#000" stroke-width=".21"/>
<circle cx="198.1" cy="87.8" r=".25" fill="#fff" stroke="#000" stroke-width=".21"/>
<circle cx="189.5" cy="57.3" r=".94" fill="#000" stroke="#000" stroke-width=".21"/>
<circle cx="189.5" cy="57.3" r=".25" fill="#fff" stroke="#000" stroke-width=".21"/>
<circle cx="192" cy="57.3" r=".94" fill="#000" stroke="#000" stroke-width=".21"/>
<circle cx="192" cy="57.3" r=".25" fill="#fff" stroke="#000" stroke-width=".21"/>
<circle cx="179.3" cy="85.2" r=".94" fill="#000" stroke="#000" stroke-width=".21"/>
<circle cx="179.3" cy="85.2" r=".25" fill="#fff" stroke="#000" stroke-width=".21"/>
<circle cx="203.1" cy="77.6" r=".94" fill="#000" stroke="#000" stroke-width=".21"/>
<circle cx="203.1" cy="77.6" r=".25" fill="#fff" stroke="#000" stroke-width=".21"/>
<circle cx="203.1" cy="72.5" r=".94" fill="#000" stroke="#000" stroke-width=".21"/>
<circle cx="203.1" cy="72.5" r=".25" fill="#fff" stroke="#000" stroke-width=".21"/>
<circle cx="179.3" cy="57.3" r=".94" fill="#000" stroke="#000" stroke-width=".21"/>
<circle cx="179.3" cy="57.3" r=".25" fill="#fff" stroke="#000" stroke-width=".21"/>
<circle cx="202.2" cy="65.2" r=".94" fill="#000" stroke="#000" stroke-width=".21"/>
<circle cx="202.2" cy="65.2" r=".25" fill="#fff" stroke="#000" stroke-width=".21"/>
<circle cx="202.2" cy="57.3" r=".94" fill="#000" stroke="#000" stroke-width=".21"/>
<circle cx="202.2" cy="57.3" r=".25" fill="#fff" stroke="#000" stroke-width=".21"/>
<circle cx="176.8" cy="85.2" r=".94" fill="#000" stroke="#000" stroke-width=".21"/>
<circle cx="176.8" cy="85.2" r=".25" fill="#fff" stroke="#000" stroke-width=".21"/>
<circle cx="176.8" cy="88.7" r=".94" fill="#000" stroke="#000" stroke-width=".21"/>
<circle cx="176.8" cy="88.7" r=".25" fill="#fff" stroke="#000" stroke-width=".21"/>
<circle cx="203.1" cy="87.8" r=".94" fill="#000" stroke="#000" stroke-width=".21"/>
<circle cx="203.1" cy="87.8" r=".25" fill="#fff" stroke="#000" stroke-width=".21"/>
<circle cx="84.1" cy="128.1" r=".94" fill="#000" stroke="#000" stroke-width=".21"/>
<circle cx="84.1" cy="128.1" r=".25" fill="#fff" stroke="#000" stroke-width=".21"/>
<circle cx="100.3" cy="128.1" r=".94" fill="#000" stroke="#000" stroke-width=".21"/>
<circle cx="100.3" cy="128.1" r=".25" fill="#fff" stroke="#000" stroke-width=".21"/>
<circle cx="97.1" cy="128.1" r=".94" fill="#000" stroke="#000" stroke-width=".21"/>
<circle cx="97.1" cy="128.1" r=".25" fill="#fff" stroke="#000" stroke-width=".21"/>
<circle cx="100.3" cy="133.1" r=".94" fill="#000" stroke="#000" stroke-width=".21"/>
<circle cx="100.3" cy="133.1" r=".25" fill="#fff" stroke="#000" stroke-width=".21"/>
<circle cx="84.1" cy="133.1" r=".94" fill="#000" stroke="#000" stroke-width=".21"/>
<circle cx="84.1" cy="133.1" r=".25" fill="#fff" stroke="#000" stroke-width=".21"/>
<circle cx="107.9" cy="128.1" r=".94" fill="#000" stroke="#000" stroke-width=".21"/>
<circle cx="107.9" cy="128.1" r=".25" fill="#fff" stroke="#000" stroke-width=".21"/>
<circle cx="97.1" cy="133.1" r=".94" fill="#000" stroke="#000" stroke-width=".21"/>
<circle cx="97.1" cy="133.1" r=".25" fill="#fff" stroke="#000" stroke-width=".21"/>
<circle cx="107.9" cy="133.1" r=".94" fill="#000" stroke="#000" stroke-width=".21"/>
<circle cx="107.9" cy="133.1" r=".25" fill="#fff" stroke="#000" stroke-width=".21"/>
<circle cx="105.4" cy="128.1" r=".94" fill="#000" stroke="#000" stroke-width=".21"/>
<circle cx="105.4" cy="128.1" r=".25" fill="#fff" stroke="#000" stroke-width=".21"/>
<circle cx="102.8" cy="128.1" r=".94" fill="#000" stroke="#000" stroke-width=".21"/>
<circle cx="102.8" cy="128.1" r=".25" fill="#fff" stroke="#000" stroke-width=".21"/>
<circle cx="102.8" cy="140.4" r=".94" fill="#000" stroke="#000" stroke-width=".21"/>
<circle cx="102.8" cy="140.4" r=".25" fill="#fff" stroke="#000" stroke-width=".21"/>
<circle cx="84.1" cy="117.9" r=".94" fill="#000" stroke="#000" stroke-width=".21"/>
<circle cx="84.1" cy="117.9" r=".25" fill="#fff" stroke="#000" stroke-width=".21"/>
<circle cx="92.7" cy="148.4" r=".94" fill="#000" stroke="#000" stroke-width=".21"/>
<circle cx="92.7" cy="148.4" r=".25" fill="#fff" stroke="#000" stroke-width=".21"/>
<circle cx="90.1" cy="148.4" r=".94" fill="#000" stroke="#000" stroke-width=".21"/>
<circle cx="90.1" cy="148.4" r=".25" fill="#fff" stroke="#000" stroke-width=".21"/>
<circle cx="102.8" cy="120.4" r=".94" fill="#000" stroke="#000" stroke-width=".21"/>
<circle cx="102.8" cy="120.4" r=".25" fill="#fff" stroke="#000" stroke-width=".21"/>
<circle cx="79" cy="128.1" r=".94" fill="#000" stroke="#000" stroke-width=".21"/>
<circle cx="79" cy="128.1" r=".25" fill="#fff" stroke="#000" stroke-width=".21"/>
<circle cx="79" cy="133.1" r=".94" fill="#000" stroke="#000" stroke-width=".21"/>
<circle cx="79" cy="133.1" r=".25" fill="#fff" stroke="#000" stroke-width=".21"/>
<circle cx="102.8" cy="148.4" r=".94" fill="#000" stroke="#000" stroke-width=".21"/>
<circle cx="102.8" cy="148.4" r=".25" fill="#fff" stroke="#000" stroke-width=".21"/>
<circle cx="80" cy="140.4" r=".94" fill="#000" stroke="#000" stroke-width=".21"/>
<circle cx="80" cy="140.4" r=".25" fill="#fff" stroke="#000" stroke-width=".21"/>
<circle cx="80" cy="148.4" r=".94" fill="#000" stroke="#000" stroke-width=".21"/>
<circle cx="80" cy="148.4" r=".25" fill="#fff" stroke="#000" stroke-width=".21"/>
<circle cx="105.4" cy="120.4" r=".94" fill="#000" stroke="#000" stroke-width=".21"/>
<circle cx="105.4" cy="120.4" r=".25" fill="#fff" stroke="#000" stroke-width=".21"/>
<circle cx="105.4" cy="116.9" r=".94" fill="#000" stroke="#000" stroke-width=".21"/>
<circle cx="105.4" cy="116.9" r=".25" fill="#fff" stroke="#000" stroke-width=".21"/>
<circle cx="79" cy="117.9" r=".94" fill="#000" stroke="#000" stroke-width=".21"/>
<circle cx="79" cy="117.9" r=".25" fill="#fff" stroke="#000" stroke-width=".21"/>
<circle cx="133.9" cy="128.1" r=".94" fill="#000" stroke="#000" stroke-width=".21"/>
<circle cx="133.9" cy="128.1" r=".25" fill="#fff" stroke="#000" stroke-width=".21"/>
<circle cx="150.1" cy="128.1" r=".94" fill="#000" stroke="#000" stroke-width=".21"/>
<circle cx="150.1" cy="128.1" r=".25" fill="#fff" stroke="#000" stroke-width=".21"/>
<circle cx="146.9" cy="128.1" r=".94" fill="#000" stroke="#000" stroke-width=".21"/>
<circle cx="146.9" cy="128.1" r=".25" fill="#fff" stroke="#000" stroke-width=".21"/>
<circle cx="150.1" cy="133.1" r=".94" fill="#000" stroke="#000" stroke-width=".21"/>
<circle cx="150.1" cy="133.1" r=".25" fill="#fff" stroke="#000" stroke-width=".21"/>
<circle cx="133.9" cy="133.1" r=".94" fill="#000" stroke="#000" stroke-width=".21"/>
<circle cx="133.9" cy="133.1" r=".25" fill="#fff" stroke="#000" stroke-width=".21"/>
<circle cx="157.7" cy="128.1" r=".94" fill="#000" stroke="#000" stroke-width=".21"/>
<circle cx="157.7" cy="128.1" r=".25" fill="#fff" stroke="#000" stroke-width=".21"/>
<circle cx="146.9" cy="133.1" r=".94" fill="#000" stroke="#000" stroke-width=".21"/>
<circle cx="146.9" cy="133.1" r=".25" fill="#fff" stroke="#000" stroke-width=".21"/>
<circle cx="157.7" cy="133.1" r=".94" fill="#000" stroke="#000" stroke-width=".21"/>
<circle cx="157.7" cy="133.1" r=".25" fill="#fff" stroke="#000" stroke-width=".21"/>
<circle cx="155.2" cy="128.1" r=".94" fill="#000" stroke="#000" stroke-width=".21"/>
<circle cx="155.2" cy="128.1" r=".25" fill="#fff" stroke="#000" stroke-width=".21"/>
<circle cx="152.7" cy="128.1" r=".94" fill="#000" stroke="#000" stroke-width=".21"/>
<circle cx="152.7" cy="128.1" r=".25" fill="#fff" stroke="#000" stroke-width=".21"/>
<circle cx="152.7" cy="140.4" r=".94" fill="#000" stroke="#000" stroke-width=".21"/>
<circle cx="152.7" cy="140.4" r=".25" fill="#fff" stroke="#000" stroke-width=".21"/>
<circle cx="133.9" cy="117.9" r=".94" fill="#000" stroke="#000" stroke-width=".21"/>
<circle cx="133.9" cy="117.9" r=".25" fill="#fff" stroke="#000" stroke-width=".21"/>
<circle cx="142.5" cy="148.4" r=".94" fill="#000" stroke="#000" stroke-width=".21"/>
<circle cx="142.5" cy="148.4" r=".25" fill="#fff" stroke="#000" stroke-width=".21"/>
<circle cx="140" cy="148.4" r=".94" fill="#000" stroke="#000" stroke-width=".21"/>
<circle cx="140" cy="148.4" r=".25" fill="#fff" stroke="#000" stroke-width=".21"/>
<circle cx="152.7" cy="120.4" r=".94" fill="#000" stroke="#000" stroke-width=".21"/>
<circle cx="152.7" cy="120.4" r=".25" fill="#fff" stroke="#000" stroke-width=".21"/>
<circle cx="128.8" cy="128.1" r=".94" fill="#000" stroke="#000" stroke-width=".21"/>
<circle cx="128.8" cy="128.1" r=".25" fill="#fff" stroke="#000" stroke-width=".21"/>
<circle cx="128.8" cy="133.1" r=".94" fill="#000" stroke="#000" stroke-width=".21"/>
<circle cx="128.8" cy="133.1" r=".25" fill="#fff" stroke="#000" stroke-width=".21"/>
<circle cx="152.7" cy="148.4" r=".94" fill="#000" stroke="#000" stroke-width=".21"/>
<circle cx="152.7" cy="148.4" r=".25" fill="#fff" stroke="#000" stroke-width=".21"/>
<circle cx="129.8" cy="140.4" r=".94" fill="#000" stroke="#000" stroke-width=".21"/>
<circle cx="129.8" cy="140.4" r=".25" fill="#fff" stroke="#000" stroke-width=".21"/>
<circle cx="129.8" cy="148.4" r=".94" fill="#000" stroke="#000" stroke-width=".21"/>
<circle cx="129.8" cy="148.4" r=".25" fill="#fff" stroke="#000" stroke-width=".21"/>
<circle cx="155.2" cy="120.4" r=".94" fill="#000" stroke="#000" stroke-width=".21"/>
<circle cx="155.2" cy="120.4" r=".25" fill="#fff" stroke="#000" stroke-width=".21"/>
<circle cx="155.2" cy="116.9" r=".94" fill="#000" stroke="#000" stroke-width=".21"/>
<circle cx="155.2" cy="116.9" r=".25" fill="#fff" stroke="#000" stroke-width=".21"/>
<circle cx="128.8" cy="117.9" r=".94" fill="#000" stroke="#000" stroke-width=".21"/>
<circle cx="128.8" cy="117.9" r=".25" fill="#fff" stroke="#000" stroke-width=".21"/>
<circle cx="183.8" cy="128.1" r=".94" fill="#000" stroke="#000" stroke-width=".21"/>
<circle cx="183.8" cy="128.1" r=".25" fill="#fff" stroke="#000" stroke-width=".21"/>
<circle cx="200" cy="128.1" r=".94" fill="#000" stroke="#000" stroke-width=".21"/>
<circle cx="200" cy="128.1" r=".25" fill="#fff" stroke="#000" stroke-width=".21"/>
<circle cx="196.8" cy="128.1" r=".94" fill="#000" stroke="#000" stroke-width=".21"/>
<circle cx="196.8" cy="128.1" r=".25" fill="#fff" stroke="#000" stroke-width=".21"/>
<circle cx="200" cy="133.1" r=".94" fill="#000" stroke="#000" stroke-width=".21"/>
<circle cx="200" cy="133.1" r=".25" fill="#fff" stroke="#000" stroke-width=".21"/>
<circle cx="183.8" cy="133.1" r=".94" fill="#000" stroke="#000" stroke-width=".21"/>
<circle cx="183.8" cy="133.1" r=".25" fill="#fff" stroke="#000" stroke-width=".21"/>
<circle cx="207.6" cy="128.1" r=".94" fill="#000" stroke="#000" stroke-width=".21"/>
<circle cx="207.6" cy="128.1" r=".25" fill="#fff" stroke="#000" stroke-width=".21"/>
<circle cx="196.8" cy="133.1" r=".94" fill="#000" stroke="#000" stroke-width=".21"/>
<circle cx="196.8" cy="133.1" r=".25" fill="#fff" stroke="#000" stroke-width=".21"/>
<circle cx="207.6" cy="133.1" r=".94" fill="#000" stroke="#000" stroke-width=".21"/>
<circle cx="207.6" cy="133.1" r=".25" fill="#fff" stroke="#000" stroke-width=".21"/>
<circle cx="205" cy="128.1" r=".94" fill="#000" stroke="#000" stroke-width=".21"/>
<circle cx="205" cy="128.1" r=".25" fill="#fff" stroke="#000" stroke-width=".21"/>
<circle cx="202.5" cy="128.1" r=".94" fill="#000" stroke="#000" stroke-width=".21"/>
<circle cx="202.5" cy="128.1" r=".25" fill="#fff" stroke="#000" stroke-width=".21"/>
<circle cx="202.5" cy="140.4" r=".94" fill="#000" stroke="#000" stroke-width=".21"/>
<circle cx="202.5" cy="140.4" r=".25" fill="#fff" stroke="#000" stroke-width=".21"/>
<circle cx="183.8" cy="117.9" r=".94" fill="#000" stroke="#000" stroke-width=".21"/>
<circle cx="183.8" cy="117.9" r=".25" fill="#fff" stroke="#000" stroke-width=".21"/>
<circle cx="192.3" cy="148.4" r=".94" fill="#000" stroke="#000" stroke-width=".21"/>
<circle cx="192.3" cy="148.4" r=".25" fill="#fff" stroke="#000" stroke-width=".21"/>
<circle cx="189.8" cy="148.4" r=".94" fill="#000" stroke="#000" stroke-width=".21"/>
<circle cx="189.8" cy="148.4" r=".25" fill="#fff" stroke="#000" stroke-width=".21"/>
<circle cx="202.5" cy="120.4" r=".94" fill="#000" stroke="#000" stroke-width=".21"/>
<circle cx="202.5" cy="120.4" r=".25" fill="#fff" stroke="#000" stroke-width=".21"/>
<circle cx="178.7" cy="128.1" r=".94" fill="#000" stroke="#000" stroke-width=".21"/>
<circle cx="178.7" cy="128.1" r=".25" fill="#fff" stroke="#000" stroke-width=".21"/>
<circle cx="178.7" cy="133.1" r=".94" fill="#000" stroke="#000" stroke-width=".21"/>
<circle cx="178.7" cy="133.1" r=".25" fill="#fff" stroke="#000" stroke-width=".21"/>
<circle cx="202.5" cy="148.4" r=".94" fill="#000" stroke="#000" stroke-width=".21"/>
<circle cx="202.5" cy="148.4" r=".25" fill="#fff" stroke="#000" stroke-width=".21"/>
<circle cx="179.6" cy="140.4" r=".94" fill="#000" stroke="#000" stroke-width=".21"/>
<circle cx="179.6" cy="140.4" r=".25" fill="#fff" stroke="#000" stroke-width=".21"/>
<circle cx="179.6" cy="148.4" r=".94" fill="#000" stroke="#000" stroke-width=".21"/>
<circle cx="179.6" cy="148.4" r=".25" fill="#fff" stroke="#000" stroke-width=".21"/>
<circle cx="205" cy="120.4" r=".94" fill="#000" stroke="#000" stroke-width=".21"/>
<circle cx="205" cy="120.4" r=".25" fill="#fff" stroke="#000" stroke-width=".21"/>
<circle cx="205" cy="116.9" r=".94" fill="#000" stroke="#000" stroke-width=".21"/>
<circle cx="205" cy="116.9" r=".25" fill="#fff" stroke="#000" stroke-width=".21"/>
<circle cx="178.7" cy="117.9" r=".94" fill="#000" stroke="#000" stroke-width=".21"/>
<circle cx="178.7" cy="117.9" r=".25" fill="#fff" stroke="#000" stroke-width=".21"/>
<g fill="none" stroke="#000" stroke-width=".21">
<path d="M22.5 18.9h252.7v171.4h-252.7zM64.6 15.1v3.8M106.7 15.1v3.8M148.8 15.1v3.8M191 15.1v3.8M233.1 15.1v3.8M18.7 61.7h3.8M275.2 61.7h3.8M18.7 104.6h3.8M275.2 104.6h3.8M18.7 147.4h3.8M275.2 147.4h3.8"/>
<path d="M233.9 170v20.3M233.9 175h41.3M235.9 177.2l.6 1.6 .5-1.6M237.6 177.2h.7M238.3 176.4l-.5 .3v2.1M239.9 176.4v2.4l-.8-.1-.3-.3 .1-1 .3-.2h.7M240.7 179h1M242.4 176.4l.1 .2zM242.4 177.2v1.6M244.3 178.8h-.7l-.3-.3-.1-.9 .3-.4h.8v1.9l-.3 .4h-.6M245.2 176.4v2.4l.8-.1 .2-.2v-1.1l-.3-.2h-.7M246.8 177.2h.8"/>
<path d="M247.1 176.4v2.1l.5 .3M249.3 176.4v2.4l-.7-.1-.3-.3v-1l.4-.2h.6M251.1 177.5v-.3h-.8v1.6M251.6 176.4l.2 .2zM251.7 177.2v1.6M252.4 177.2l.5 1.6 .6-1.6M254.2 178h1a.54 .54 0 0 0-.4-.8 .54 .54 0 0 0-.6 .5l.1 .9 .9 .2M256.8 177.5v-.3h-.7v1.6M257.4 179h1M259.2 178.8v-1.6l1.4 .1 .2 1.5M260 177.2v1.6M261.5 177.2h.8"/>
<path d="M262.3 176.4l-.5 .3-.1 2.1M263.8 178.8h-.6l-.4-.3v-1.1l.2-.2h.8v1.9l-.2 .4h-.7M275.2 170h-95.2v20.3M64.6 190.3v3.8M106.7 190.3v3.8M148.8 190.3v3.8M191 190.3v3.8M233.1 190.3v3.8M233.9 185.2h41.3M233.9 180.1h41.3M235.9 182.2l.6-.5v2.1M235.9 183.8h1.2"/>
<path d="M239.7 183.7l.1 .1zM240.8 181.9l.1-.1a.86 .86 0 0 1 .8 1.2l-.1 .3a.51 .51 0 0 1-.5 .5 .51 .51 0 0 1-.5-.5v-.8zM241.6 182.2l-1 1.2M242.5 182v-.3h1.1l-.6 2.1M244.3 183.7l.2 .1zM245.2 182.2a.58 .58 0 0 1 .8-.4 .58 .58 0 0 1 .1 .9l-.9 1.1h1.1M247.3 181.9l.2-.1a.86 .86 0 0 1 .7 1.2v.3a.51 .51 0 0 1-.6 .5 .51 .51 0 0 1-.5-.5v-.8zM248.1 182.2l-.9 1.2M250 182.2a.58 .58 0 0 1 .8-.4 .58 .58 0 0 1 .2 .9l-1 1.1h1.2M251.9 182.2a.58 .58 0 0 1 .9-.4 .58 .58 0 0 1 .1 .9l-1 1.1h1.2M253.9 182.6l.1 .1zM253.9 183.6l.1 .1z"/>
<path d="M254.8 183.8h1.1M254.8 182.2l.5-.5v2.1M256.7 182.2a.58 .58 0 0 1 .8-.4 .58 .58 0 0 1 .2 .9l-1 1.1h1.2M265 185.2v5.1"/>
<circle cx="238.4" cy="183.3" r=".59"/>
<circle cx="238.4" cy="182.2" r=".46"/>
</g>
<path d="M18.7 15.1h260.3v179h-260.3z" fill="none" stroke="#000" stroke-width=".32"/>
<use href="#words"/>
</svg>
